
VERSION 5.7 ;
BUSBITCHARS "[]" ;
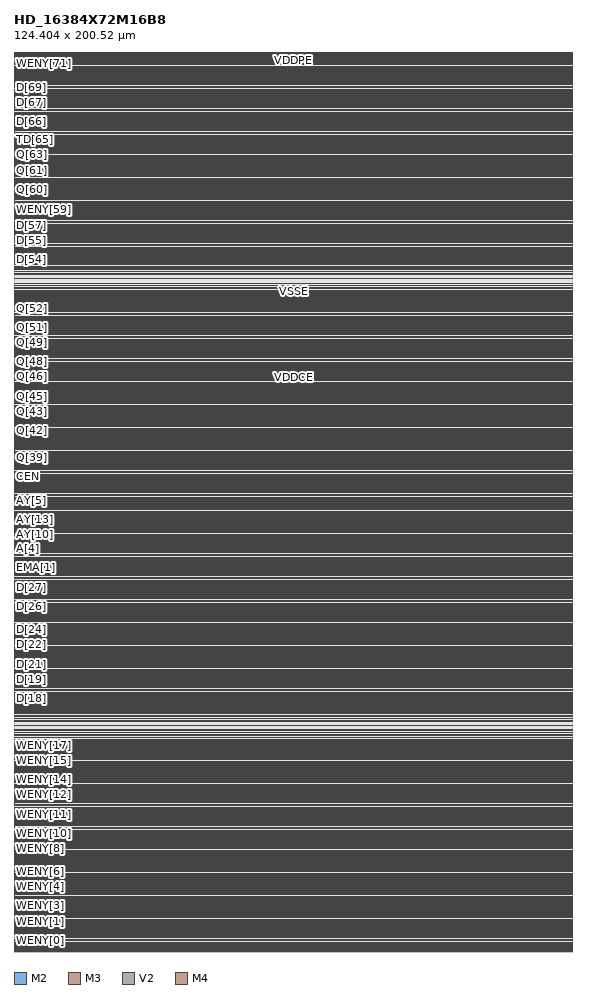
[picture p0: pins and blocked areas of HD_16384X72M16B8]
MACRO HD_16384X72M16B8
	FOREIGN HD_16384X72M16B8 0 0 ;
	SYMMETRY X Y ;
	SIZE 124.404 BY 200.52 ;
	CLASS BLOCK ;
	PIN AY[0]
		USE SIGNAL ;
		DIRECTION OUTPUT ;
		SHAPE ABUTMENT ;
		PORT
			 LAYER M2 ;
			RECT 0.0714 105.3427 0.1097 105.3804 ;
			 LAYER M3 ;
			RECT 0.0714 105.28 0.1097 105.3804 ;
			 LAYER V2 ;
			RECT 0.0831 105.3557 0.098 105.3682 ;
		END

		ANTENNADIFFAREA 0.00194719 ;
		ANTENNAPARTIALMETALAREA 0.00195671 ;
	END AY[0]

	PIN AY[10]
		USE SIGNAL ;
		DIRECTION OUTPUT ;
		SHAPE ABUTMENT ;
		PORT
			 LAYER M2 ;
			RECT 0.0098 91.2878 0.0481 91.3882 ;
			 LAYER M3 ;
			RECT 0.0098 91.2878 0.0481 91.3882 ;
			 LAYER V2 ;
			RECT 0.021 91.3008 0.0359 91.3133 ;
		END

		ANTENNADIFFAREA 0.00194719 ;
		ANTENNAPARTIALMETALAREA 0.00195671 ;
	END AY[10]

	PIN AY[11]
		USE SIGNAL ;
		DIRECTION OUTPUT ;
		SHAPE ABUTMENT ;
		PORT
			 LAYER M2 ;
			RECT 0.0098 93.8478 0.0481 93.9482 ;
			 LAYER M3 ;
			RECT 0.0098 93.8478 0.0481 93.9482 ;
			 LAYER V2 ;
			RECT 0.021 93.8608 0.0359 93.8733 ;
		END

		ANTENNADIFFAREA 0.00194719 ;
		ANTENNAPARTIALMETALAREA 0.00195671 ;
	END AY[11]

	PIN AY[12]
		USE SIGNAL ;
		DIRECTION OUTPUT ;
		SHAPE ABUTMENT ;
		PORT
			 LAYER M2 ;
			RECT 0.0098 95.1153 0.0481 95.1529 ;
			 LAYER M3 ;
			RECT 0.0098 95.0525 0.0481 95.1529 ;
			 LAYER V2 ;
			RECT 0.0215 95.1275 0.0364 95.14 ;
		END

		ANTENNADIFFAREA 0.00194719 ;
		ANTENNAPARTIALMETALAREA 0.00195671 ;
	END AY[12]

	PIN AY[13]
		USE SIGNAL ;
		DIRECTION OUTPUT ;
		SHAPE ABUTMENT ;
		PORT
			 LAYER M2 ;
			RECT 0.0098 96.3702 0.0481 96.4078 ;
			 LAYER M3 ;
			RECT 0.0098 96.3075 0.0481 96.4078 ;
			 LAYER V2 ;
			RECT 0.0215 96.3824 0.0364 96.3949 ;
		END

		ANTENNADIFFAREA 0.00194719 ;
		ANTENNAPARTIALMETALAREA 0.00195671 ;
	END AY[13]

	PIN AY[1]
		USE SIGNAL ;
		DIRECTION OUTPUT ;
		SHAPE ABUTMENT ;
		PORT
			 LAYER M2 ;
			RECT 0.0098 104.0753 0.0481 104.1129 ;
			 LAYER M3 ;
			RECT 0.0098 104.0753 0.0481 104.1757 ;
			 LAYER V2 ;
			RECT 0.0215 104.0882 0.0364 104.1008 ;
		END

		ANTENNADIFFAREA 0.00194719 ;
		ANTENNAPARTIALMETALAREA 0.00195671 ;
	END AY[1]

	PIN AY[2]
		USE SIGNAL ;
		DIRECTION OUTPUT ;
		SHAPE ABUTMENT ;
		PORT
			 LAYER M2 ;
			RECT 0.0098 103.0212 0.0481 103.0588 ;
			 LAYER M3 ;
			RECT 0.0098 103.0212 0.0481 103.1216 ;
			 LAYER V2 ;
			RECT 0.0215 103.0341 0.0364 103.0467 ;
		END

		ANTENNADIFFAREA 0.00194719 ;
		ANTENNAPARTIALMETALAREA 0.00195671 ;
	END AY[2]

	PIN AY[3]
		USE SIGNAL ;
		DIRECTION OUTPUT ;
		SHAPE ABUTMENT ;
		PORT
			 LAYER M2 ;
			RECT 0.0098 101.5153 0.0481 101.5529 ;
			 LAYER M3 ;
			RECT 0.0098 101.5153 0.0481 101.6157 ;
			 LAYER V2 ;
			RECT 0.0215 101.5282 0.0364 101.5408 ;
		END

		ANTENNADIFFAREA 0.00194719 ;
		ANTENNAPARTIALMETALAREA 0.00195671 ;
	END AY[3]

	PIN AY[4]
		USE SIGNAL ;
		DIRECTION OUTPUT ;
		SHAPE ABUTMENT ;
		PORT
			 LAYER M2 ;
			RECT 0.0098 89.5561 0.0481 89.6565 ;
			 LAYER M3 ;
			RECT 0.0098 89.5561 0.0481 89.6565 ;
			 LAYER V2 ;
			RECT 0.021 89.631 0.0359 89.6435 ;
		END

		ANTENNADIFFAREA 0.00194719 ;
		ANTENNAPARTIALMETALAREA 0.00195671 ;
	END AY[4]

	PIN AY[5]
		USE SIGNAL ;
		DIRECTION OUTPUT ;
		SHAPE ABUTMENT ;
		PORT
			 LAYER M2 ;
			RECT 0.0098 98.9302 0.0481 98.9678 ;
			 LAYER M3 ;
			RECT 0.0098 98.8675 0.0481 98.9678 ;
			 LAYER V2 ;
			RECT 0.0215 98.9424 0.0364 98.9549 ;
		END

		ANTENNADIFFAREA 0.00194719 ;
		ANTENNAPARTIALMETALAREA 0.00195671 ;
	END AY[5]

	PIN AY[6]
		USE SIGNAL ;
		DIRECTION OUTPUT ;
		SHAPE ABUTMENT ;
		PORT
			 LAYER M2 ;
			RECT 0.0714 94.7263 0.1097 94.7639 ;
			 LAYER M3 ;
			RECT 0.0714 94.7263 0.1097 94.8267 ;
			 LAYER V2 ;
			RECT 0.0831 94.7384 0.098 94.751 ;
		END

		ANTENNADIFFAREA 0.00194719 ;
		ANTENNAPARTIALMETALAREA 0.00195671 ;
	END AY[6]

	PIN AY[7]
		USE SIGNAL ;
		DIRECTION OUTPUT ;
		SHAPE ABUTMENT ;
		PORT
			 LAYER M2 ;
			RECT 0.0098 96.0816 0.0481 96.182 ;
			 LAYER M3 ;
			RECT 0.0098 96.0816 0.0481 96.182 ;
			 LAYER V2 ;
			RECT 0.021 96.1565 0.0359 96.169 ;
		END

		ANTENNADIFFAREA 0.00194719 ;
		ANTENNAPARTIALMETALAREA 0.00195671 ;
	END AY[7]

	PIN AY[8]
		USE SIGNAL ;
		DIRECTION OUTPUT ;
		SHAPE ABUTMENT ;
		PORT
			 LAYER M2 ;
			RECT 0.0098 92.5427 0.0481 92.6431 ;
			 LAYER M3 ;
			RECT 0.0098 92.5427 0.0481 92.6431 ;
			 LAYER V2 ;
			RECT 0.021 92.6176 0.0359 92.6302 ;
		END

		ANTENNADIFFAREA 0.00194719 ;
		ANTENNAPARTIALMETALAREA 0.00195671 ;
	END AY[8]

	PIN AY[9]
		USE SIGNAL ;
		DIRECTION OUTPUT ;
		SHAPE ABUTMENT ;
		PORT
			 LAYER M2 ;
			RECT 0.0098 90.0957 0.0481 90.1333 ;
			 LAYER M3 ;
			RECT 0.0098 90.0329 0.0481 90.1333 ;
			 LAYER V2 ;
			RECT 0.0215 90.1078 0.0364 90.1204 ;
		END

		ANTENNADIFFAREA 0.00194719 ;
		ANTENNAPARTIALMETALAREA 0.00195671 ;
	END AY[9]

	PIN A[0]
		USE SIGNAL ;
		DIRECTION INPUT ;
		SHAPE ABUTMENT ;
		PORT
			 LAYER M2 ;
			RECT 0.0098 105.4306 0.0481 105.4682 ;
			 LAYER M3 ;
			RECT 0.0098 105.4306 0.0481 105.531 ;
			 LAYER V2 ;
			RECT 0.0215 105.4435 0.0364 105.4561 ;
		END

		ANTENNAGATEAREA 0.00027817 ;
		ANTENNADIFFAREA 0.00194719 ;
		ANTENNAPARTIALMETALAREA 0.00195671 ;
	END A[0]

	PIN A[10]
		USE SIGNAL ;
		DIRECTION INPUT ;
		SHAPE ABUTMENT ;
		PORT
			 LAYER M2 ;
			RECT 0.0098 91.1373 0.0481 91.2376 ;
			 LAYER M3 ;
			RECT 0.0098 91.1373 0.0481 91.2376 ;
			 LAYER V2 ;
			RECT 0.021 91.2122 0.0359 91.2247 ;
		END

		ANTENNAGATEAREA 0.00027817 ;
		ANTENNADIFFAREA 0.00194719 ;
		ANTENNAPARTIALMETALAREA 0.00195671 ;
	END A[10]

	PIN A[11]
		USE SIGNAL ;
		DIRECTION INPUT ;
		SHAPE ABUTMENT ;
		PORT
			 LAYER M2 ;
			RECT 0.0098 93.4463 0.0481 93.5467 ;
			 LAYER M3 ;
			RECT 0.0098 93.4463 0.0481 93.5467 ;
			 LAYER V2 ;
			RECT 0.021 93.5212 0.0359 93.5337 ;
		END

		ANTENNAGATEAREA 0.00027817 ;
		ANTENNADIFFAREA 0.00194719 ;
		ANTENNAPARTIALMETALAREA 0.00195671 ;
	END A[11]

	PIN A[12]
		USE SIGNAL ;
		DIRECTION INPUT ;
		SHAPE ABUTMENT ;
		PORT
			 LAYER M2 ;
			RECT 0.0714 95.0525 0.1097 95.0902 ;
			 LAYER M3 ;
			RECT 0.0714 95.0525 0.1097 95.1529 ;
			 LAYER V2 ;
			RECT 0.0831 95.0647 0.098 95.0773 ;
		END

		ANTENNAGATEAREA 0.00027817 ;
		ANTENNADIFFAREA 0.00194719 ;
		ANTENNAPARTIALMETALAREA 0.00195671 ;
	END A[12]

	PIN A[13]
		USE SIGNAL ;
		DIRECTION INPUT ;
		SHAPE ABUTMENT ;
		PORT
			 LAYER M2 ;
			RECT 0.0714 96.3075 0.1097 96.3451 ;
			 LAYER M3 ;
			RECT 0.0714 96.3075 0.1097 96.4078 ;
			 LAYER V2 ;
			RECT 0.0831 96.3196 0.098 96.3322 ;
		END

		ANTENNAGATEAREA 0.00027817 ;
		ANTENNADIFFAREA 0.00194719 ;
		ANTENNAPARTIALMETALAREA 0.00195671 ;
	END A[13]

	PIN A[1]
		USE SIGNAL ;
		DIRECTION INPUT ;
		SHAPE ABUTMENT ;
		PORT
			 LAYER M2 ;
			RECT 0.0714 104.138 0.1097 104.1757 ;
			 LAYER M3 ;
			RECT 0.0714 104.0753 0.1097 104.1757 ;
			 LAYER V2 ;
			RECT 0.0831 104.151 0.098 104.1635 ;
		END

		ANTENNAGATEAREA 0.00027817 ;
		ANTENNADIFFAREA 0.00194719 ;
		ANTENNAPARTIALMETALAREA 0.00195671 ;
	END A[1]

	PIN A[2]
		USE SIGNAL ;
		DIRECTION INPUT ;
		SHAPE ABUTMENT ;
		PORT
			 LAYER M2 ;
			RECT 0.0098 102.4941 0.0481 102.5945 ;
			 LAYER M3 ;
			RECT 0.0098 102.4941 0.0481 102.5945 ;
			 LAYER V2 ;
			RECT 0.021 102.569 0.0359 102.5816 ;
		END

		ANTENNAGATEAREA 0.00027817 ;
		ANTENNADIFFAREA 0.00194719 ;
		ANTENNAPARTIALMETALAREA 0.00195671 ;
	END A[2]

	PIN A[3]
		USE SIGNAL ;
		DIRECTION INPUT ;
		SHAPE ABUTMENT ;
		PORT
			 LAYER M2 ;
			RECT 0.0098 101.2894 0.0481 101.3271 ;
			 LAYER M3 ;
			RECT 0.0098 101.2894 0.0481 101.3898 ;
			 LAYER V2 ;
			RECT 0.0215 101.3024 0.0364 101.3149 ;
		END

		ANTENNAGATEAREA 0.00027817 ;
		ANTENNADIFFAREA 0.00194719 ;
		ANTENNAPARTIALMETALAREA 0.00195671 ;
	END A[3]

	PIN A[4]
		USE SIGNAL ;
		DIRECTION INPUT ;
		SHAPE ABUTMENT ;
		PORT
			 LAYER M2 ;
			RECT 0.0714 89.8824 0.1097 89.92 ;
			 LAYER M3 ;
			RECT 0.0714 89.8824 0.1097 89.9827 ;
			 LAYER V2 ;
			RECT 0.0831 89.8945 0.098 89.9071 ;
		END

		ANTENNAGATEAREA 0.00027817 ;
		ANTENNADIFFAREA 0.00194719 ;
		ANTENNAPARTIALMETALAREA 0.00195671 ;
	END A[4]

	PIN A[5]
		USE SIGNAL ;
		DIRECTION INPUT ;
		SHAPE ABUTMENT ;
		PORT
			 LAYER M2 ;
			RECT 0.0098 99.1686 0.0481 99.269 ;
			 LAYER M3 ;
			RECT 0.0098 99.1686 0.0481 99.269 ;
			 LAYER V2 ;
			RECT 0.021 99.2435 0.0359 99.2561 ;
		END

		ANTENNAGATEAREA 0.00027817 ;
		ANTENNADIFFAREA 0.00194719 ;
		ANTENNAPARTIALMETALAREA 0.00195671 ;
	END A[5]

	PIN A[6]
		USE SIGNAL ;
		DIRECTION INPUT ;
		SHAPE ABUTMENT ;
		PORT
			 LAYER M2 ;
			RECT 0.0714 94.5757 0.1097 94.6133 ;
			 LAYER M3 ;
			RECT 0.0714 94.5757 0.1097 94.6761 ;
			 LAYER V2 ;
			RECT 0.0831 94.5878 0.098 94.6004 ;
		END

		ANTENNAGATEAREA 0.00027817 ;
		ANTENNADIFFAREA 0.00194719 ;
		ANTENNAPARTIALMETALAREA 0.00195671 ;
	END A[6]

	PIN A[7]
		USE SIGNAL ;
		DIRECTION INPUT ;
		SHAPE ABUTMENT ;
		PORT
			 LAYER M2 ;
			RECT 0.0098 95.9561 0.0481 96.0565 ;
			 LAYER M3 ;
			RECT 0.0098 95.9561 0.0481 96.0565 ;
			 LAYER V2 ;
			RECT 0.021 95.969 0.0359 95.9816 ;
		END

		ANTENNAGATEAREA 0.00027817 ;
		ANTENNADIFFAREA 0.00194719 ;
		ANTENNAPARTIALMETALAREA 0.00195671 ;
	END A[7]

	PIN A[8]
		USE SIGNAL ;
		DIRECTION INPUT ;
		SHAPE ABUTMENT ;
		PORT
			 LAYER M2 ;
			RECT 0.0098 90.811 0.0481 90.9114 ;
			 LAYER M3 ;
			RECT 0.0098 90.811 0.0481 90.9114 ;
			 LAYER V2 ;
			RECT 0.021 90.8859 0.0359 90.8984 ;
		END

		ANTENNAGATEAREA 0.00027817 ;
		ANTENNADIFFAREA 0.00194719 ;
		ANTENNAPARTIALMETALAREA 0.00195671 ;
	END A[8]

	PIN A[9]
		USE SIGNAL ;
		DIRECTION INPUT ;
		SHAPE ABUTMENT ;
		PORT
			 LAYER M2 ;
			RECT 0.0098 90.1835 0.0481 90.2839 ;
			 LAYER M3 ;
			RECT 0.0098 90.1835 0.0481 90.2839 ;
			 LAYER V2 ;
			RECT 0.021 90.2584 0.0359 90.271 ;
		END

		ANTENNAGATEAREA 0.00027817 ;
		ANTENNADIFFAREA 0.00194719 ;
		ANTENNAPARTIALMETALAREA 0.00195671 ;
	END A[9]

	PIN CEN
		USE SIGNAL ;
		DIRECTION INPUT ;
		SHAPE ABUTMENT ;
		PORT
			 LAYER M2 ;
			RECT 0.0098 105.8824 0.0481 105.92 ;
			 LAYER M3 ;
			RECT 0.0098 105.8824 0.0481 105.9827 ;
			 LAYER V2 ;
			RECT 0.0215 105.8953 0.0364 105.9078 ;
		END

		ANTENNAGATEAREA 0.00027817 ;
		ANTENNADIFFAREA 0.00194719 ;
		ANTENNAPARTIALMETALAREA 0.00195671 ;
	END CEN

	PIN CENY
		USE SIGNAL ;
		DIRECTION OUTPUT ;
		SHAPE ABUTMENT ;
		PORT
			 LAYER M2 ;
			RECT 0.0098 105.7318 0.0481 105.7694 ;
			 LAYER M3 ;
			RECT 0.0098 105.7318 0.0481 105.8322 ;
			 LAYER V2 ;
			RECT 0.0215 105.7447 0.0364 105.7573 ;
		END

		ANTENNADIFFAREA 0.00194719 ;
		ANTENNAPARTIALMETALAREA 0.00195671 ;
	END CENY

	PIN CLK
		USE SIGNAL ;
		DIRECTION INPUT ;
		SHAPE ABUTMENT ;
		PORT
			 LAYER M2 ;
			RECT 0.0098 107.9906 0.0481 108.091 ;
			 LAYER M3 ;
			RECT 0.0098 107.9906 0.0481 108.091 ;
			 LAYER V2 ;
			RECT 0.021 108.0655 0.0359 108.078 ;
		END

		ANTENNAGATEAREA 0.00027817 ;
		ANTENNADIFFAREA 0.00194719 ;
		ANTENNAPARTIALMETALAREA 0.00195671 ;
	END CLK

	PIN DFTRAMBYP
		USE SIGNAL ;
		DIRECTION INPUT ;
		SHAPE ABUTMENT ;
		PORT
			 LAYER M2 ;
			RECT 0.0098 113.0353 0.0481 113.0729 ;
			 LAYER M3 ;
			RECT 0.0098 113.0353 0.0481 113.1357 ;
			 LAYER V2 ;
			RECT 0.0215 113.0482 0.0364 113.0608 ;
		END

		ANTENNAGATEAREA 0.00027817 ;
		ANTENNADIFFAREA 0.00194719 ;
		ANTENNAPARTIALMETALAREA 0.00195671 ;
	END DFTRAMBYP

	PIN D[0]
		USE SIGNAL ;
		DIRECTION INPUT ;
		SHAPE ABUTMENT ;
		PORT
			 LAYER M2 ;
			RECT 0.0098 2.6478 0.0481 2.6855 ;
			 LAYER M3 ;
			RECT 0.0098 2.6478 0.0481 2.7482 ;
			 LAYER V2 ;
			RECT 0.0215 2.6608 0.0364 2.6733 ;
		END

		ANTENNAGATEAREA 0.00027817 ;
		ANTENNADIFFAREA 0.00194719 ;
		ANTENNAPARTIALMETALAREA 0.00195671 ;
	END D[0]

	PIN D[10]
		USE SIGNAL ;
		DIRECTION INPUT ;
		SHAPE ABUTMENT ;
		PORT
			 LAYER M2 ;
			RECT 0.0098 28.2478 0.0481 28.2855 ;
			 LAYER M3 ;
			RECT 0.0098 28.2478 0.0481 28.3482 ;
			 LAYER V2 ;
			RECT 0.0215 28.2608 0.0364 28.2733 ;
		END

		ANTENNAGATEAREA 0.00027817 ;
		ANTENNADIFFAREA 0.00194719 ;
		ANTENNAPARTIALMETALAREA 0.00195671 ;
	END D[10]

	PIN D[11]
		USE SIGNAL ;
		DIRECTION INPUT ;
		SHAPE ABUTMENT ;
		PORT
			 LAYER M2 ;
			RECT 0.0098 30.8078 0.0481 30.8455 ;
			 LAYER M3 ;
			RECT 0.0098 30.8078 0.0481 30.9082 ;
			 LAYER V2 ;
			RECT 0.0215 30.8208 0.0364 30.8333 ;
		END

		ANTENNAGATEAREA 0.00027817 ;
		ANTENNADIFFAREA 0.00194719 ;
		ANTENNAPARTIALMETALAREA 0.00195671 ;
	END D[11]

	PIN D[12]
		USE SIGNAL ;
		DIRECTION INPUT ;
		SHAPE ABUTMENT ;
		PORT
			 LAYER M2 ;
			RECT 0.0098 33.3678 0.0481 33.4055 ;
			 LAYER M3 ;
			RECT 0.0098 33.3678 0.0481 33.4682 ;
			 LAYER V2 ;
			RECT 0.0215 33.3808 0.0364 33.3933 ;
		END

		ANTENNAGATEAREA 0.00027817 ;
		ANTENNADIFFAREA 0.00194719 ;
		ANTENNAPARTIALMETALAREA 0.00195671 ;
	END D[12]

	PIN D[13]
		USE SIGNAL ;
		DIRECTION INPUT ;
		SHAPE ABUTMENT ;
		PORT
			 LAYER M2 ;
			RECT 0.0098 35.9278 0.0481 35.9655 ;
			 LAYER M3 ;
			RECT 0.0098 35.9278 0.0481 36.0282 ;
			 LAYER V2 ;
			RECT 0.0215 35.9408 0.0364 35.9533 ;
		END

		ANTENNAGATEAREA 0.00027817 ;
		ANTENNADIFFAREA 0.00194719 ;
		ANTENNAPARTIALMETALAREA 0.00195671 ;
	END D[13]

	PIN D[14]
		USE SIGNAL ;
		DIRECTION INPUT ;
		SHAPE ABUTMENT ;
		PORT
			 LAYER M2 ;
			RECT 0.0098 38.4878 0.0481 38.5255 ;
			 LAYER M3 ;
			RECT 0.0098 38.4878 0.0481 38.5882 ;
			 LAYER V2 ;
			RECT 0.0215 38.5008 0.0364 38.5133 ;
		END

		ANTENNAGATEAREA 0.00027817 ;
		ANTENNADIFFAREA 0.00194719 ;
		ANTENNAPARTIALMETALAREA 0.00195671 ;
	END D[14]

	PIN D[15]
		USE SIGNAL ;
		DIRECTION INPUT ;
		SHAPE ABUTMENT ;
		PORT
			 LAYER M2 ;
			RECT 0.0098 41.0478 0.0481 41.0855 ;
			 LAYER M3 ;
			RECT 0.0098 41.0478 0.0481 41.1482 ;
			 LAYER V2 ;
			RECT 0.0215 41.0608 0.0364 41.0733 ;
		END

		ANTENNAGATEAREA 0.00027817 ;
		ANTENNADIFFAREA 0.00194719 ;
		ANTENNAPARTIALMETALAREA 0.00195671 ;
	END D[15]

	PIN D[16]
		USE SIGNAL ;
		DIRECTION INPUT ;
		SHAPE ABUTMENT ;
		PORT
			 LAYER M2 ;
			RECT 0.0098 43.6078 0.0481 43.6455 ;
			 LAYER M3 ;
			RECT 0.0098 43.6078 0.0481 43.7082 ;
			 LAYER V2 ;
			RECT 0.0215 43.6208 0.0364 43.6333 ;
		END

		ANTENNAGATEAREA 0.00027817 ;
		ANTENNADIFFAREA 0.00194719 ;
		ANTENNAPARTIALMETALAREA 0.00195671 ;
	END D[16]

	PIN D[17]
		USE SIGNAL ;
		DIRECTION INPUT ;
		SHAPE ABUTMENT ;
		PORT
			 LAYER M2 ;
			RECT 0.0098 46.1678 0.0481 46.2055 ;
			 LAYER M3 ;
			RECT 0.0098 46.1678 0.0481 46.2682 ;
			 LAYER V2 ;
			RECT 0.0215 46.1808 0.0364 46.1933 ;
		END

		ANTENNAGATEAREA 0.00027817 ;
		ANTENNADIFFAREA 0.00194719 ;
		ANTENNAPARTIALMETALAREA 0.00195671 ;
	END D[17]

	PIN D[18]
		USE SIGNAL ;
		DIRECTION INPUT ;
		SHAPE ABUTMENT ;
		PORT
			 LAYER M2 ;
			RECT 0.0098 56.4267 0.0481 56.4643 ;
			 LAYER M3 ;
			RECT 0.0098 56.4267 0.0481 56.5271 ;
			 LAYER V2 ;
			RECT 0.0215 56.4396 0.0364 56.4522 ;
		END

		ANTENNAGATEAREA 0.00027817 ;
		ANTENNADIFFAREA 0.00194719 ;
		ANTENNAPARTIALMETALAREA 0.00195671 ;
	END D[18]

	PIN D[19]
		USE SIGNAL ;
		DIRECTION INPUT ;
		SHAPE ABUTMENT ;
		PORT
			 LAYER M2 ;
			RECT 0.0098 58.9867 0.0481 59.0243 ;
			 LAYER M3 ;
			RECT 0.0098 58.9867 0.0481 59.0871 ;
			 LAYER V2 ;
			RECT 0.0215 58.9996 0.0364 59.0122 ;
		END

		ANTENNAGATEAREA 0.00027817 ;
		ANTENNADIFFAREA 0.00194719 ;
		ANTENNAPARTIALMETALAREA 0.00195671 ;
	END D[19]

	PIN D[1]
		USE SIGNAL ;
		DIRECTION INPUT ;
		SHAPE ABUTMENT ;
		PORT
			 LAYER M2 ;
			RECT 0.0098 5.2078 0.0481 5.2455 ;
			 LAYER M3 ;
			RECT 0.0098 5.2078 0.0481 5.3082 ;
			 LAYER V2 ;
			RECT 0.0215 5.2208 0.0364 5.2333 ;
		END

		ANTENNAGATEAREA 0.00027817 ;
		ANTENNADIFFAREA 0.00194719 ;
		ANTENNAPARTIALMETALAREA 0.00195671 ;
	END D[1]

	PIN D[20]
		USE SIGNAL ;
		DIRECTION INPUT ;
		SHAPE ABUTMENT ;
		PORT
			 LAYER M2 ;
			RECT 0.0098 61.5467 0.0481 61.5843 ;
			 LAYER M3 ;
			RECT 0.0098 61.5467 0.0481 61.6471 ;
			 LAYER V2 ;
			RECT 0.0215 61.5596 0.0364 61.5722 ;
		END

		ANTENNAGATEAREA 0.00027817 ;
		ANTENNADIFFAREA 0.00194719 ;
		ANTENNAPARTIALMETALAREA 0.00195671 ;
	END D[20]

	PIN D[21]
		USE SIGNAL ;
		DIRECTION INPUT ;
		SHAPE ABUTMENT ;
		PORT
			 LAYER M2 ;
			RECT 0.0098 64.1067 0.0481 64.1443 ;
			 LAYER M3 ;
			RECT 0.0098 64.1067 0.0481 64.2071 ;
			 LAYER V2 ;
			RECT 0.0215 64.1196 0.0364 64.1322 ;
		END

		ANTENNAGATEAREA 0.00027817 ;
		ANTENNADIFFAREA 0.00194719 ;
		ANTENNAPARTIALMETALAREA 0.00195671 ;
	END D[21]

	PIN D[22]
		USE SIGNAL ;
		DIRECTION INPUT ;
		SHAPE ABUTMENT ;
		PORT
			 LAYER M2 ;
			RECT 0.0098 66.6667 0.0481 66.7043 ;
			 LAYER M3 ;
			RECT 0.0098 66.6667 0.0481 66.7671 ;
			 LAYER V2 ;
			RECT 0.0215 66.6796 0.0364 66.6922 ;
		END

		ANTENNAGATEAREA 0.00027817 ;
		ANTENNADIFFAREA 0.00194719 ;
		ANTENNAPARTIALMETALAREA 0.00195671 ;
	END D[22]

	PIN D[23]
		USE SIGNAL ;
		DIRECTION INPUT ;
		SHAPE ABUTMENT ;
		PORT
			 LAYER M2 ;
			RECT 0.0098 69.2267 0.0481 69.2643 ;
			 LAYER M3 ;
			RECT 0.0098 69.2267 0.0481 69.3271 ;
			 LAYER V2 ;
			RECT 0.0215 69.2396 0.0364 69.2522 ;
		END

		ANTENNAGATEAREA 0.00027817 ;
		ANTENNADIFFAREA 0.00194719 ;
		ANTENNAPARTIALMETALAREA 0.00195671 ;
	END D[23]

	PIN D[24]
		USE SIGNAL ;
		DIRECTION INPUT ;
		SHAPE ABUTMENT ;
		PORT
			 LAYER M2 ;
			RECT 0.0098 71.7867 0.0481 71.8243 ;
			 LAYER M3 ;
			RECT 0.0098 71.7867 0.0481 71.8871 ;
			 LAYER V2 ;
			RECT 0.0215 71.7996 0.0364 71.8122 ;
		END

		ANTENNAGATEAREA 0.00027817 ;
		ANTENNADIFFAREA 0.00194719 ;
		ANTENNAPARTIALMETALAREA 0.00195671 ;
	END D[24]

	PIN D[25]
		USE SIGNAL ;
		DIRECTION INPUT ;
		SHAPE ABUTMENT ;
		PORT
			 LAYER M2 ;
			RECT 0.0098 74.3467 0.0481 74.3843 ;
			 LAYER M3 ;
			RECT 0.0098 74.3467 0.0481 74.4471 ;
			 LAYER V2 ;
			RECT 0.0215 74.3596 0.0364 74.3722 ;
		END

		ANTENNAGATEAREA 0.00027817 ;
		ANTENNADIFFAREA 0.00194719 ;
		ANTENNAPARTIALMETALAREA 0.00195671 ;
	END D[25]

	PIN D[26]
		USE SIGNAL ;
		DIRECTION INPUT ;
		SHAPE ABUTMENT ;
		PORT
			 LAYER M2 ;
			RECT 0.0098 76.9067 0.0481 76.9443 ;
			 LAYER M3 ;
			RECT 0.0098 76.9067 0.0481 77.0071 ;
			 LAYER V2 ;
			RECT 0.0215 76.9196 0.0364 76.9322 ;
		END

		ANTENNAGATEAREA 0.00027817 ;
		ANTENNADIFFAREA 0.00194719 ;
		ANTENNAPARTIALMETALAREA 0.00195671 ;
	END D[26]

	PIN D[27]
		USE SIGNAL ;
		DIRECTION INPUT ;
		SHAPE ABUTMENT ;
		PORT
			 LAYER M2 ;
			RECT 0.0098 79.4667 0.0481 79.5043 ;
			 LAYER M3 ;
			RECT 0.0098 79.4667 0.0481 79.5671 ;
			 LAYER V2 ;
			RECT 0.0215 79.4796 0.0364 79.4922 ;
		END

		ANTENNAGATEAREA 0.00027817 ;
		ANTENNADIFFAREA 0.00194719 ;
		ANTENNAPARTIALMETALAREA 0.00195671 ;
	END D[27]

	PIN D[28]
		USE SIGNAL ;
		DIRECTION INPUT ;
		SHAPE ABUTMENT ;
		PORT
			 LAYER M2 ;
			RECT 0.0098 82.0267 0.0481 82.0643 ;
			 LAYER M3 ;
			RECT 0.0098 82.0267 0.0481 82.1271 ;
			 LAYER V2 ;
			RECT 0.0215 82.0396 0.0364 82.0522 ;
		END

		ANTENNAGATEAREA 0.00027817 ;
		ANTENNADIFFAREA 0.00194719 ;
		ANTENNAPARTIALMETALAREA 0.00195671 ;
	END D[28]

	PIN D[29]
		USE SIGNAL ;
		DIRECTION INPUT ;
		SHAPE ABUTMENT ;
		PORT
			 LAYER M2 ;
			RECT 0.0098 84.5867 0.0481 84.6243 ;
			 LAYER M3 ;
			RECT 0.0098 84.5867 0.0481 84.6871 ;
			 LAYER V2 ;
			RECT 0.0215 84.5996 0.0364 84.6122 ;
		END

		ANTENNAGATEAREA 0.00027817 ;
		ANTENNADIFFAREA 0.00194719 ;
		ANTENNAPARTIALMETALAREA 0.00195671 ;
	END D[29]

	PIN D[2]
		USE SIGNAL ;
		DIRECTION INPUT ;
		SHAPE ABUTMENT ;
		PORT
			 LAYER M2 ;
			RECT 0.0098 7.7678 0.0481 7.8055 ;
			 LAYER M3 ;
			RECT 0.0098 7.7678 0.0481 7.8682 ;
			 LAYER V2 ;
			RECT 0.0215 7.7808 0.0364 7.7933 ;
		END

		ANTENNAGATEAREA 0.00027817 ;
		ANTENNADIFFAREA 0.00194719 ;
		ANTENNAPARTIALMETALAREA 0.00195671 ;
	END D[2]

	PIN D[30]
		USE SIGNAL ;
		DIRECTION INPUT ;
		SHAPE ABUTMENT ;
		PORT
			 LAYER M2 ;
			RECT 0.0098 87.1467 0.0481 87.1843 ;
			 LAYER M3 ;
			RECT 0.0098 87.1467 0.0481 87.2471 ;
			 LAYER V2 ;
			RECT 0.0215 87.1596 0.0364 87.1722 ;
		END

		ANTENNAGATEAREA 0.00027817 ;
		ANTENNADIFFAREA 0.00194719 ;
		ANTENNAPARTIALMETALAREA 0.00195671 ;
	END D[30]

	PIN D[31]
		USE SIGNAL ;
		DIRECTION INPUT ;
		SHAPE ABUTMENT ;
		PORT
			 LAYER M2 ;
			RECT 0.0098 89.3176 0.0481 89.3553 ;
			 LAYER M3 ;
			RECT 0.0098 89.2549 0.0481 89.3553 ;
			 LAYER V2 ;
			RECT 0.0215 89.3298 0.0364 89.3424 ;
		END

		ANTENNAGATEAREA 0.00027817 ;
		ANTENNADIFFAREA 0.00194719 ;
		ANTENNAPARTIALMETALAREA 0.00195671 ;
	END D[31]

	PIN D[32]
		USE SIGNAL ;
		DIRECTION INPUT ;
		SHAPE ABUTMENT ;
		PORT
			 LAYER M2 ;
			RECT 0.0714 91.8902 0.1097 91.9278 ;
			 LAYER M3 ;
			RECT 0.0714 91.8902 0.1097 91.9906 ;
			 LAYER V2 ;
			RECT 0.0831 91.9024 0.098 91.9149 ;
		END

		ANTENNAGATEAREA 0.00027817 ;
		ANTENNADIFFAREA 0.00194719 ;
		ANTENNAPARTIALMETALAREA 0.00195671 ;
	END D[32]

	PIN D[33]
		USE SIGNAL ;
		DIRECTION INPUT ;
		SHAPE ABUTMENT ;
		PORT
			 LAYER M2 ;
			RECT 0.0714 94.4251 0.1097 94.4627 ;
			 LAYER M3 ;
			RECT 0.0714 94.4251 0.1097 94.5255 ;
			 LAYER V2 ;
			RECT 0.0831 94.4373 0.098 94.4498 ;
		END

		ANTENNAGATEAREA 0.00027817 ;
		ANTENNADIFFAREA 0.00194719 ;
		ANTENNAPARTIALMETALAREA 0.00195671 ;
	END D[33]

	PIN D[34]
		USE SIGNAL ;
		DIRECTION INPUT ;
		SHAPE ABUTMENT ;
		PORT
			 LAYER M2 ;
			RECT 0.0098 96.9725 0.0481 97.0102 ;
			 LAYER M3 ;
			RECT 0.0098 96.9098 0.0481 97.0102 ;
			 LAYER V2 ;
			RECT 0.0215 96.9847 0.0364 96.9973 ;
		END

		ANTENNAGATEAREA 0.00027817 ;
		ANTENNADIFFAREA 0.00194719 ;
		ANTENNAPARTIALMETALAREA 0.00195671 ;
	END D[34]

	PIN D[35]
		USE SIGNAL ;
		DIRECTION INPUT ;
		SHAPE ABUTMENT ;
		PORT
			 LAYER M2 ;
			RECT 0.0098 99.5325 0.0481 99.5702 ;
			 LAYER M3 ;
			RECT 0.0098 99.4698 0.0481 99.5702 ;
			 LAYER V2 ;
			RECT 0.0215 99.5447 0.0364 99.5573 ;
		END

		ANTENNAGATEAREA 0.00027817 ;
		ANTENNADIFFAREA 0.00194719 ;
		ANTENNAPARTIALMETALAREA 0.00195671 ;
	END D[35]

	PIN D[36]
		USE SIGNAL ;
		DIRECTION INPUT ;
		SHAPE ABUTMENT ;
		PORT
			 LAYER M2 ;
			RECT 0.0098 100.9129 0.0481 100.9506 ;
			 LAYER M3 ;
			RECT 0.0098 100.9129 0.0481 101.0133 ;
			 LAYER V2 ;
			RECT 0.0215 100.9259 0.0364 100.9384 ;
		END

		ANTENNAGATEAREA 0.00027817 ;
		ANTENNADIFFAREA 0.00194719 ;
		ANTENNAPARTIALMETALAREA 0.00195671 ;
	END D[36]

	PIN D[37]
		USE SIGNAL ;
		DIRECTION INPUT ;
		SHAPE ABUTMENT ;
		PORT
			 LAYER M2 ;
			RECT 0.0098 103.4729 0.0481 103.5106 ;
			 LAYER M3 ;
			RECT 0.0098 103.4729 0.0481 103.5733 ;
			 LAYER V2 ;
			RECT 0.0215 103.4859 0.0364 103.4984 ;
		END

		ANTENNAGATEAREA 0.00027817 ;
		ANTENNADIFFAREA 0.00194719 ;
		ANTENNAPARTIALMETALAREA 0.00195671 ;
	END D[37]

	PIN D[38]
		USE SIGNAL ;
		DIRECTION INPUT ;
		SHAPE ABUTMENT ;
		PORT
			 LAYER M2 ;
			RECT 0.0098 106.0329 0.0481 106.0706 ;
			 LAYER M3 ;
			RECT 0.0098 106.0329 0.0481 106.1333 ;
			 LAYER V2 ;
			RECT 0.0215 106.0459 0.0364 106.0584 ;
		END

		ANTENNAGATEAREA 0.00027817 ;
		ANTENNADIFFAREA 0.00194719 ;
		ANTENNAPARTIALMETALAREA 0.00195671 ;
	END D[38]

	PIN D[39]
		USE SIGNAL ;
		DIRECTION INPUT ;
		SHAPE ABUTMENT ;
		PORT
			 LAYER M2 ;
			RECT 0.0098 108.5929 0.0481 108.6306 ;
			 LAYER M3 ;
			RECT 0.0098 108.5929 0.0481 108.6933 ;
			 LAYER V2 ;
			RECT 0.0215 108.6059 0.0364 108.6184 ;
		END

		ANTENNAGATEAREA 0.00027817 ;
		ANTENNADIFFAREA 0.00194719 ;
		ANTENNAPARTIALMETALAREA 0.00195671 ;
	END D[39]

	PIN D[3]
		USE SIGNAL ;
		DIRECTION INPUT ;
		SHAPE ABUTMENT ;
		PORT
			 LAYER M2 ;
			RECT 0.0098 10.3278 0.0481 10.3655 ;
			 LAYER M3 ;
			RECT 0.0098 10.3278 0.0481 10.4282 ;
			 LAYER V2 ;
			RECT 0.0215 10.3408 0.0364 10.3533 ;
		END

		ANTENNAGATEAREA 0.00027817 ;
		ANTENNADIFFAREA 0.00194719 ;
		ANTENNAPARTIALMETALAREA 0.00195671 ;
	END D[3]

	PIN D[40]
		USE SIGNAL ;
		DIRECTION INPUT ;
		SHAPE ABUTMENT ;
		PORT
			 LAYER M2 ;
			RECT 0.0098 111.1529 0.0481 111.1906 ;
			 LAYER M3 ;
			RECT 0.0098 111.1529 0.0481 111.2533 ;
			 LAYER V2 ;
			RECT 0.0215 111.1659 0.0364 111.1784 ;
		END

		ANTENNAGATEAREA 0.00027817 ;
		ANTENNADIFFAREA 0.00194719 ;
		ANTENNAPARTIALMETALAREA 0.00195671 ;
	END D[40]

	PIN D[41]
		USE SIGNAL ;
		DIRECTION INPUT ;
		SHAPE ABUTMENT ;
		PORT
			 LAYER M2 ;
			RECT 0.0098 113.3239 0.0481 113.3616 ;
			 LAYER M3 ;
			RECT 0.0098 113.2612 0.0481 113.3616 ;
			 LAYER V2 ;
			RECT 0.0215 113.3361 0.0364 113.3486 ;
		END

		ANTENNAGATEAREA 0.00027817 ;
		ANTENNADIFFAREA 0.00194719 ;
		ANTENNAPARTIALMETALAREA 0.00195671 ;
	END D[41]

	PIN D[42]
		USE SIGNAL ;
		DIRECTION INPUT ;
		SHAPE ABUTMENT ;
		PORT
			 LAYER M2 ;
			RECT 0.0098 115.8839 0.0481 115.9216 ;
			 LAYER M3 ;
			RECT 0.0098 115.8212 0.0481 115.9216 ;
			 LAYER V2 ;
			RECT 0.0215 115.8961 0.0364 115.9086 ;
		END

		ANTENNAGATEAREA 0.00027817 ;
		ANTENNADIFFAREA 0.00194719 ;
		ANTENNAPARTIALMETALAREA 0.00195671 ;
	END D[42]

	PIN D[43]
		USE SIGNAL ;
		DIRECTION INPUT ;
		SHAPE ABUTMENT ;
		PORT
			 LAYER M2 ;
			RECT 0.0098 118.4439 0.0481 118.4816 ;
			 LAYER M3 ;
			RECT 0.0098 118.3812 0.0481 118.4816 ;
			 LAYER V2 ;
			RECT 0.0215 118.4561 0.0364 118.4686 ;
		END

		ANTENNAGATEAREA 0.00027817 ;
		ANTENNADIFFAREA 0.00194719 ;
		ANTENNAPARTIALMETALAREA 0.00195671 ;
	END D[43]

	PIN D[44]
		USE SIGNAL ;
		DIRECTION INPUT ;
		SHAPE ABUTMENT ;
		PORT
			 LAYER M2 ;
			RECT 0.0098 121.0039 0.0481 121.0416 ;
			 LAYER M3 ;
			RECT 0.0098 120.9412 0.0481 121.0416 ;
			 LAYER V2 ;
			RECT 0.0215 121.0161 0.0364 121.0286 ;
		END

		ANTENNAGATEAREA 0.00027817 ;
		ANTENNADIFFAREA 0.00194719 ;
		ANTENNAPARTIALMETALAREA 0.00195671 ;
	END D[44]

	PIN D[45]
		USE SIGNAL ;
		DIRECTION INPUT ;
		SHAPE ABUTMENT ;
		PORT
			 LAYER M2 ;
			RECT 0.0098 123.5639 0.0481 123.6016 ;
			 LAYER M3 ;
			RECT 0.0098 123.5012 0.0481 123.6016 ;
			 LAYER V2 ;
			RECT 0.0215 123.5761 0.0364 123.5886 ;
		END

		ANTENNAGATEAREA 0.00027817 ;
		ANTENNADIFFAREA 0.00194719 ;
		ANTENNAPARTIALMETALAREA 0.00195671 ;
	END D[45]

	PIN D[46]
		USE SIGNAL ;
		DIRECTION INPUT ;
		SHAPE ABUTMENT ;
		PORT
			 LAYER M2 ;
			RECT 0.0098 126.1239 0.0481 126.1616 ;
			 LAYER M3 ;
			RECT 0.0098 126.0612 0.0481 126.1616 ;
			 LAYER V2 ;
			RECT 0.0215 126.1361 0.0364 126.1486 ;
		END

		ANTENNAGATEAREA 0.00027817 ;
		ANTENNADIFFAREA 0.00194719 ;
		ANTENNAPARTIALMETALAREA 0.00195671 ;
	END D[46]

	PIN D[47]
		USE SIGNAL ;
		DIRECTION INPUT ;
		SHAPE ABUTMENT ;
		PORT
			 LAYER M2 ;
			RECT 0.0098 128.6839 0.0481 128.7216 ;
			 LAYER M3 ;
			RECT 0.0098 128.6212 0.0481 128.7216 ;
			 LAYER V2 ;
			RECT 0.0215 128.6961 0.0364 128.7086 ;
		END

		ANTENNAGATEAREA 0.00027817 ;
		ANTENNADIFFAREA 0.00194719 ;
		ANTENNAPARTIALMETALAREA 0.00195671 ;
	END D[47]

	PIN D[48]
		USE SIGNAL ;
		DIRECTION INPUT ;
		SHAPE ABUTMENT ;
		PORT
			 LAYER M2 ;
			RECT 0.0098 131.2439 0.0481 131.2816 ;
			 LAYER M3 ;
			RECT 0.0098 131.1812 0.0481 131.2816 ;
			 LAYER V2 ;
			RECT 0.0215 131.2561 0.0364 131.2686 ;
		END

		ANTENNAGATEAREA 0.00027817 ;
		ANTENNADIFFAREA 0.00194719 ;
		ANTENNAPARTIALMETALAREA 0.00195671 ;
	END D[48]

	PIN D[49]
		USE SIGNAL ;
		DIRECTION INPUT ;
		SHAPE ABUTMENT ;
		PORT
			 LAYER M2 ;
			RECT 0.0098 133.8039 0.0481 133.8416 ;
			 LAYER M3 ;
			RECT 0.0098 133.7412 0.0481 133.8416 ;
			 LAYER V2 ;
			RECT 0.0215 133.8161 0.0364 133.8286 ;
		END

		ANTENNAGATEAREA 0.00027817 ;
		ANTENNADIFFAREA 0.00194719 ;
		ANTENNAPARTIALMETALAREA 0.00195671 ;
	END D[49]

	PIN D[4]
		USE SIGNAL ;
		DIRECTION INPUT ;
		SHAPE ABUTMENT ;
		PORT
			 LAYER M2 ;
			RECT 0.0098 12.8878 0.0481 12.9255 ;
			 LAYER M3 ;
			RECT 0.0098 12.8878 0.0481 12.9882 ;
			 LAYER V2 ;
			RECT 0.0215 12.9008 0.0364 12.9133 ;
		END

		ANTENNAGATEAREA 0.00027817 ;
		ANTENNADIFFAREA 0.00194719 ;
		ANTENNAPARTIALMETALAREA 0.00195671 ;
	END D[4]

	PIN D[50]
		USE SIGNAL ;
		DIRECTION INPUT ;
		SHAPE ABUTMENT ;
		PORT
			 LAYER M2 ;
			RECT 0.0098 136.3639 0.0481 136.4016 ;
			 LAYER M3 ;
			RECT 0.0098 136.3012 0.0481 136.4016 ;
			 LAYER V2 ;
			RECT 0.0215 136.3761 0.0364 136.3886 ;
		END

		ANTENNAGATEAREA 0.00027817 ;
		ANTENNADIFFAREA 0.00194719 ;
		ANTENNAPARTIALMETALAREA 0.00195671 ;
	END D[50]

	PIN D[51]
		USE SIGNAL ;
		DIRECTION INPUT ;
		SHAPE ABUTMENT ;
		PORT
			 LAYER M2 ;
			RECT 0.0098 138.9239 0.0481 138.9616 ;
			 LAYER M3 ;
			RECT 0.0098 138.8612 0.0481 138.9616 ;
			 LAYER V2 ;
			RECT 0.0215 138.9361 0.0364 138.9486 ;
		END

		ANTENNAGATEAREA 0.00027817 ;
		ANTENNADIFFAREA 0.00194719 ;
		ANTENNAPARTIALMETALAREA 0.00195671 ;
	END D[51]

	PIN D[52]
		USE SIGNAL ;
		DIRECTION INPUT ;
		SHAPE ABUTMENT ;
		PORT
			 LAYER M2 ;
			RECT 0.0098 141.4839 0.0481 141.5216 ;
			 LAYER M3 ;
			RECT 0.0098 141.4212 0.0481 141.5216 ;
			 LAYER V2 ;
			RECT 0.0215 141.4961 0.0364 141.5086 ;
		END

		ANTENNAGATEAREA 0.00027817 ;
		ANTENNADIFFAREA 0.00194719 ;
		ANTENNAPARTIALMETALAREA 0.00195671 ;
	END D[52]

	PIN D[53]
		USE SIGNAL ;
		DIRECTION INPUT ;
		SHAPE ABUTMENT ;
		PORT
			 LAYER M2 ;
			RECT 0.0098 144.0439 0.0481 144.0816 ;
			 LAYER M3 ;
			RECT 0.0098 143.9812 0.0481 144.0816 ;
			 LAYER V2 ;
			RECT 0.0215 144.0561 0.0364 144.0686 ;
		END

		ANTENNAGATEAREA 0.00027817 ;
		ANTENNADIFFAREA 0.00194719 ;
		ANTENNAPARTIALMETALAREA 0.00195671 ;
	END D[53]

	PIN D[54]
		USE SIGNAL ;
		DIRECTION INPUT ;
		SHAPE ABUTMENT ;
		PORT
			 LAYER M2 ;
			RECT 0.0098 154.3027 0.0481 154.3404 ;
			 LAYER M3 ;
			RECT 0.0098 154.24 0.0481 154.3404 ;
			 LAYER V2 ;
			RECT 0.0215 154.3149 0.0364 154.3275 ;
		END

		ANTENNAGATEAREA 0.00027817 ;
		ANTENNADIFFAREA 0.00194719 ;
		ANTENNAPARTIALMETALAREA 0.00195671 ;
	END D[54]

	PIN D[55]
		USE SIGNAL ;
		DIRECTION INPUT ;
		SHAPE ABUTMENT ;
		PORT
			 LAYER M2 ;
			RECT 0.0098 156.8627 0.0481 156.9004 ;
			 LAYER M3 ;
			RECT 0.0098 156.8 0.0481 156.9004 ;
			 LAYER V2 ;
			RECT 0.0215 156.8749 0.0364 156.8875 ;
		END

		ANTENNAGATEAREA 0.00027817 ;
		ANTENNADIFFAREA 0.00194719 ;
		ANTENNAPARTIALMETALAREA 0.00195671 ;
	END D[55]

	PIN D[56]
		USE SIGNAL ;
		DIRECTION INPUT ;
		SHAPE ABUTMENT ;
		PORT
			 LAYER M2 ;
			RECT 0.0098 159.4227 0.0481 159.4604 ;
			 LAYER M3 ;
			RECT 0.0098 159.36 0.0481 159.4604 ;
			 LAYER V2 ;
			RECT 0.0215 159.4349 0.0364 159.4475 ;
		END

		ANTENNAGATEAREA 0.00027817 ;
		ANTENNADIFFAREA 0.00194719 ;
		ANTENNAPARTIALMETALAREA 0.00195671 ;
	END D[56]

	PIN D[57]
		USE SIGNAL ;
		DIRECTION INPUT ;
		SHAPE ABUTMENT ;
		PORT
			 LAYER M2 ;
			RECT 0.0098 161.9827 0.0481 162.0204 ;
			 LAYER M3 ;
			RECT 0.0098 161.92 0.0481 162.0204 ;
			 LAYER V2 ;
			RECT 0.0215 161.9949 0.0364 162.0075 ;
		END

		ANTENNAGATEAREA 0.00027817 ;
		ANTENNADIFFAREA 0.00194719 ;
		ANTENNAPARTIALMETALAREA 0.00195671 ;
	END D[57]

	PIN D[58]
		USE SIGNAL ;
		DIRECTION INPUT ;
		SHAPE ABUTMENT ;
		PORT
			 LAYER M2 ;
			RECT 0.0098 164.5427 0.0481 164.5804 ;
			 LAYER M3 ;
			RECT 0.0098 164.48 0.0481 164.5804 ;
			 LAYER V2 ;
			RECT 0.0215 164.5549 0.0364 164.5675 ;
		END

		ANTENNAGATEAREA 0.00027817 ;
		ANTENNADIFFAREA 0.00194719 ;
		ANTENNAPARTIALMETALAREA 0.00195671 ;
	END D[58]

	PIN D[59]
		USE SIGNAL ;
		DIRECTION INPUT ;
		SHAPE ABUTMENT ;
		PORT
			 LAYER M2 ;
			RECT 0.0098 167.1027 0.0481 167.1404 ;
			 LAYER M3 ;
			RECT 0.0098 167.04 0.0481 167.1404 ;
			 LAYER V2 ;
			RECT 0.0215 167.1149 0.0364 167.1275 ;
		END

		ANTENNAGATEAREA 0.00027817 ;
		ANTENNADIFFAREA 0.00194719 ;
		ANTENNAPARTIALMETALAREA 0.00195671 ;
	END D[59]

	PIN D[5]
		USE SIGNAL ;
		DIRECTION INPUT ;
		SHAPE ABUTMENT ;
		PORT
			 LAYER M2 ;
			RECT 0.0098 15.4478 0.0481 15.4855 ;
			 LAYER M3 ;
			RECT 0.0098 15.4478 0.0481 15.5482 ;
			 LAYER V2 ;
			RECT 0.0215 15.4608 0.0364 15.4733 ;
		END

		ANTENNAGATEAREA 0.00027817 ;
		ANTENNADIFFAREA 0.00194719 ;
		ANTENNAPARTIALMETALAREA 0.00195671 ;
	END D[5]

	PIN D[60]
		USE SIGNAL ;
		DIRECTION INPUT ;
		SHAPE ABUTMENT ;
		PORT
			 LAYER M2 ;
			RECT 0.0098 169.6627 0.0481 169.7004 ;
			 LAYER M3 ;
			RECT 0.0098 169.6 0.0481 169.7004 ;
			 LAYER V2 ;
			RECT 0.0215 169.6749 0.0364 169.6875 ;
		END

		ANTENNAGATEAREA 0.00027817 ;
		ANTENNADIFFAREA 0.00194719 ;
		ANTENNAPARTIALMETALAREA 0.00195671 ;
	END D[60]

	PIN D[61]
		USE SIGNAL ;
		DIRECTION INPUT ;
		SHAPE ABUTMENT ;
		PORT
			 LAYER M2 ;
			RECT 0.0098 172.2227 0.0481 172.2604 ;
			 LAYER M3 ;
			RECT 0.0098 172.16 0.0481 172.2604 ;
			 LAYER V2 ;
			RECT 0.0215 172.2349 0.0364 172.2475 ;
		END

		ANTENNAGATEAREA 0.00027817 ;
		ANTENNADIFFAREA 0.00194719 ;
		ANTENNAPARTIALMETALAREA 0.00195671 ;
	END D[61]

	PIN D[62]
		USE SIGNAL ;
		DIRECTION INPUT ;
		SHAPE ABUTMENT ;
		PORT
			 LAYER M2 ;
			RECT 0.0098 174.7827 0.0481 174.8204 ;
			 LAYER M3 ;
			RECT 0.0098 174.72 0.0481 174.8204 ;
			 LAYER V2 ;
			RECT 0.0215 174.7949 0.0364 174.8075 ;
		END

		ANTENNAGATEAREA 0.00027817 ;
		ANTENNADIFFAREA 0.00194719 ;
		ANTENNAPARTIALMETALAREA 0.00195671 ;
	END D[62]

	PIN D[63]
		USE SIGNAL ;
		DIRECTION INPUT ;
		SHAPE ABUTMENT ;
		PORT
			 LAYER M2 ;
			RECT 0.0098 177.3427 0.0481 177.3804 ;
			 LAYER M3 ;
			RECT 0.0098 177.28 0.0481 177.3804 ;
			 LAYER V2 ;
			RECT 0.0215 177.3549 0.0364 177.3675 ;
		END

		ANTENNAGATEAREA 0.00027817 ;
		ANTENNADIFFAREA 0.00194719 ;
		ANTENNAPARTIALMETALAREA 0.00195671 ;
	END D[63]

	PIN D[64]
		USE SIGNAL ;
		DIRECTION INPUT ;
		SHAPE ABUTMENT ;
		PORT
			 LAYER M2 ;
			RECT 0.0098 179.9027 0.0481 179.9404 ;
			 LAYER M3 ;
			RECT 0.0098 179.84 0.0481 179.9404 ;
			 LAYER V2 ;
			RECT 0.0215 179.9149 0.0364 179.9275 ;
		END

		ANTENNAGATEAREA 0.00027817 ;
		ANTENNADIFFAREA 0.00194719 ;
		ANTENNAPARTIALMETALAREA 0.00195671 ;
	END D[64]

	PIN D[65]
		USE SIGNAL ;
		DIRECTION INPUT ;
		SHAPE ABUTMENT ;
		PORT
			 LAYER M2 ;
			RECT 0.0098 182.4627 0.0481 182.5004 ;
			 LAYER M3 ;
			RECT 0.0098 182.4 0.0481 182.5004 ;
			 LAYER V2 ;
			RECT 0.0215 182.4749 0.0364 182.4875 ;
		END

		ANTENNAGATEAREA 0.00027817 ;
		ANTENNADIFFAREA 0.00194719 ;
		ANTENNAPARTIALMETALAREA 0.00195671 ;
	END D[65]

	PIN D[66]
		USE SIGNAL ;
		DIRECTION INPUT ;
		SHAPE ABUTMENT ;
		PORT
			 LAYER M2 ;
			RECT 0.0098 185.0227 0.0481 185.0604 ;
			 LAYER M3 ;
			RECT 0.0098 184.96 0.0481 185.0604 ;
			 LAYER V2 ;
			RECT 0.0215 185.0349 0.0364 185.0475 ;
		END

		ANTENNAGATEAREA 0.00027817 ;
		ANTENNADIFFAREA 0.00194719 ;
		ANTENNAPARTIALMETALAREA 0.00195671 ;
	END D[66]

	PIN D[67]
		USE SIGNAL ;
		DIRECTION INPUT ;
		SHAPE ABUTMENT ;
		PORT
			 LAYER M2 ;
			RECT 0.0098 187.5827 0.0481 187.6204 ;
			 LAYER M3 ;
			RECT 0.0098 187.52 0.0481 187.6204 ;
			 LAYER V2 ;
			RECT 0.0215 187.5949 0.0364 187.6075 ;
		END

		ANTENNAGATEAREA 0.00027817 ;
		ANTENNADIFFAREA 0.00194719 ;
		ANTENNAPARTIALMETALAREA 0.00195671 ;
	END D[67]

	PIN D[68]
		USE SIGNAL ;
		DIRECTION INPUT ;
		SHAPE ABUTMENT ;
		PORT
			 LAYER M2 ;
			RECT 0.0098 190.1427 0.0481 190.1804 ;
			 LAYER M3 ;
			RECT 0.0098 190.08 0.0481 190.1804 ;
			 LAYER V2 ;
			RECT 0.0215 190.1549 0.0364 190.1675 ;
		END

		ANTENNAGATEAREA 0.00027817 ;
		ANTENNADIFFAREA 0.00194719 ;
		ANTENNAPARTIALMETALAREA 0.00195671 ;
	END D[68]

	PIN D[69]
		USE SIGNAL ;
		DIRECTION INPUT ;
		SHAPE ABUTMENT ;
		PORT
			 LAYER M2 ;
			RECT 0.0098 192.7027 0.0481 192.7404 ;
			 LAYER M3 ;
			RECT 0.0098 192.64 0.0481 192.7404 ;
			 LAYER V2 ;
			RECT 0.0215 192.7149 0.0364 192.7275 ;
		END

		ANTENNAGATEAREA 0.00027817 ;
		ANTENNADIFFAREA 0.00194719 ;
		ANTENNAPARTIALMETALAREA 0.00195671 ;
	END D[69]

	PIN D[6]
		USE SIGNAL ;
		DIRECTION INPUT ;
		SHAPE ABUTMENT ;
		PORT
			 LAYER M2 ;
			RECT 0.0098 18.0078 0.0481 18.0455 ;
			 LAYER M3 ;
			RECT 0.0098 18.0078 0.0481 18.1082 ;
			 LAYER V2 ;
			RECT 0.0215 18.0208 0.0364 18.0333 ;
		END

		ANTENNAGATEAREA 0.00027817 ;
		ANTENNADIFFAREA 0.00194719 ;
		ANTENNAPARTIALMETALAREA 0.00195671 ;
	END D[6]

	PIN D[70]
		USE SIGNAL ;
		DIRECTION INPUT ;
		SHAPE ABUTMENT ;
		PORT
			 LAYER M2 ;
			RECT 0.0098 195.2627 0.0481 195.3004 ;
			 LAYER M3 ;
			RECT 0.0098 195.2 0.0481 195.3004 ;
			 LAYER V2 ;
			RECT 0.0215 195.2749 0.0364 195.2875 ;
		END

		ANTENNAGATEAREA 0.00027817 ;
		ANTENNADIFFAREA 0.00194719 ;
		ANTENNAPARTIALMETALAREA 0.00195671 ;
	END D[70]

	PIN D[71]
		USE SIGNAL ;
		DIRECTION INPUT ;
		SHAPE ABUTMENT ;
		PORT
			 LAYER M2 ;
			RECT 0.0098 197.8227 0.0481 197.8604 ;
			 LAYER M3 ;
			RECT 0.0098 197.76 0.0481 197.8604 ;
			 LAYER V2 ;
			RECT 0.0215 197.8349 0.0364 197.8475 ;
		END

		ANTENNAGATEAREA 0.00027817 ;
		ANTENNADIFFAREA 0.00194719 ;
		ANTENNAPARTIALMETALAREA 0.00195671 ;
	END D[71]

	PIN D[7]
		USE SIGNAL ;
		DIRECTION INPUT ;
		SHAPE ABUTMENT ;
		PORT
			 LAYER M2 ;
			RECT 0.0098 20.5678 0.0481 20.6055 ;
			 LAYER M3 ;
			RECT 0.0098 20.5678 0.0481 20.6682 ;
			 LAYER V2 ;
			RECT 0.0215 20.5808 0.0364 20.5933 ;
		END

		ANTENNAGATEAREA 0.00027817 ;
		ANTENNADIFFAREA 0.00194719 ;
		ANTENNAPARTIALMETALAREA 0.00195671 ;
	END D[7]

	PIN D[8]
		USE SIGNAL ;
		DIRECTION INPUT ;
		SHAPE ABUTMENT ;
		PORT
			 LAYER M2 ;
			RECT 0.0098 23.1278 0.0481 23.1655 ;
			 LAYER M3 ;
			RECT 0.0098 23.1278 0.0481 23.2282 ;
			 LAYER V2 ;
			RECT 0.0215 23.1408 0.0364 23.1533 ;
		END

		ANTENNAGATEAREA 0.00027817 ;
		ANTENNADIFFAREA 0.00194719 ;
		ANTENNAPARTIALMETALAREA 0.00195671 ;
	END D[8]

	PIN D[9]
		USE SIGNAL ;
		DIRECTION INPUT ;
		SHAPE ABUTMENT ;
		PORT
			 LAYER M2 ;
			RECT 0.0098 25.6878 0.0481 25.7255 ;
			 LAYER M3 ;
			RECT 0.0098 25.6878 0.0481 25.7882 ;
			 LAYER V2 ;
			RECT 0.0215 25.7008 0.0364 25.7133 ;
		END

		ANTENNAGATEAREA 0.00027817 ;
		ANTENNADIFFAREA 0.00194719 ;
		ANTENNAPARTIALMETALAREA 0.00195671 ;
	END D[9]

	PIN EMAS
		USE SIGNAL ;
		DIRECTION INPUT ;
		SHAPE ABUTMENT ;
		PORT
			 LAYER M2 ;
			RECT 0.0098 93.2957 0.0481 93.3961 ;
			 LAYER M3 ;
			RECT 0.0098 93.2957 0.0481 93.3961 ;
			 LAYER V2 ;
			RECT 0.021 93.3706 0.0359 93.3831 ;
		END

		ANTENNAGATEAREA 0.00027817 ;
		ANTENNADIFFAREA 0.00194719 ;
		ANTENNAPARTIALMETALAREA 0.00195671 ;
	END EMAS

	PIN EMAW[0]
		USE SIGNAL ;
		DIRECTION INPUT ;
		SHAPE ABUTMENT ;
		PORT
			 LAYER M2 ;
			RECT 0.0098 90.6604 0.0481 90.7608 ;
			 LAYER M3 ;
			RECT 0.0098 90.6604 0.0481 90.7608 ;
			 LAYER V2 ;
			RECT 0.021 90.7353 0.0359 90.7478 ;
		END

		ANTENNAGATEAREA 0.00027817 ;
		ANTENNADIFFAREA 0.00194719 ;
		ANTENNAPARTIALMETALAREA 0.00195671 ;
	END EMAW[0]

	PIN EMAW[1]
		USE SIGNAL ;
		DIRECTION INPUT ;
		SHAPE ABUTMENT ;
		PORT
			 LAYER M2 ;
			RECT 0.0714 92.3922 0.1097 92.4298 ;
			 LAYER M3 ;
			RECT 0.0714 92.3922 0.1097 92.4925 ;
			 LAYER V2 ;
			RECT 0.0831 92.4043 0.098 92.4169 ;
		END

		ANTENNAGATEAREA 0.00027817 ;
		ANTENNADIFFAREA 0.00194719 ;
		ANTENNAPARTIALMETALAREA 0.00195671 ;
	END EMAW[1]

	PIN EMA[0]
		USE SIGNAL ;
		DIRECTION INPUT ;
		SHAPE ABUTMENT ;
		PORT
			 LAYER M2 ;
			RECT 0.0098 88.778 0.0481 88.8784 ;
			 LAYER M3 ;
			RECT 0.0098 88.778 0.0481 88.8784 ;
			 LAYER V2 ;
			RECT 0.021 88.8529 0.0359 88.8655 ;
		END

		ANTENNAGATEAREA 0.00027817 ;
		ANTENNADIFFAREA 0.00194719 ;
		ANTENNAPARTIALMETALAREA 0.00195671 ;
	END EMA[0]

	PIN EMA[1]
		USE SIGNAL ;
		DIRECTION INPUT ;
		SHAPE ABUTMENT ;
		PORT
			 LAYER M2 ;
			RECT 0.0098 87.4353 0.0481 87.4729 ;
			 LAYER M3 ;
			RECT 0.0098 87.3725 0.0481 87.4729 ;
			 LAYER V2 ;
			RECT 0.0215 87.4475 0.0364 87.46 ;
		END

		ANTENNAGATEAREA 0.00027817 ;
		ANTENNADIFFAREA 0.00194719 ;
		ANTENNAPARTIALMETALAREA 0.00195671 ;
	END EMA[1]

	PIN EMA[2]
		USE SIGNAL ;
		DIRECTION INPUT ;
		SHAPE ABUTMENT ;
		PORT
			 LAYER M2 ;
			RECT 0.0714 87.3725 0.1097 87.4102 ;
			 LAYER M3 ;
			RECT 0.0714 87.3725 0.1097 87.4729 ;
			 LAYER V2 ;
			RECT 0.0831 87.3847 0.098 87.3973 ;
		END

		ANTENNAGATEAREA 0.00027817 ;
		ANTENNADIFFAREA 0.00194719 ;
		ANTENNAPARTIALMETALAREA 0.00195671 ;
	END EMA[2]

	PIN GWEN
		USE SIGNAL ;
		DIRECTION INPUT ;
		SHAPE ABUTMENT ;
		PORT
			 LAYER M2 ;
			RECT 0.0098 107.0118 0.0481 107.1122 ;
			 LAYER M3 ;
			RECT 0.0098 107.0118 0.0481 107.1122 ;
			 LAYER V2 ;
			RECT 0.021 107.0867 0.0359 107.0992 ;
		END

		ANTENNAGATEAREA 0.00027817 ;
		ANTENNADIFFAREA 0.00194719 ;
		ANTENNAPARTIALMETALAREA 0.00195671 ;
	END GWEN

	PIN GWENY
		USE SIGNAL ;
		DIRECTION OUTPUT ;
		SHAPE ABUTMENT ;
		PORT
			 LAYER M2 ;
			RECT 0.0098 106.6353 0.0481 106.6729 ;
			 LAYER M3 ;
			RECT 0.0098 106.6353 0.0481 106.7357 ;
			 LAYER V2 ;
			RECT 0.0215 106.6482 0.0364 106.6608 ;
		END

		ANTENNADIFFAREA 0.00194719 ;
		ANTENNAPARTIALMETALAREA 0.00195671 ;
	END GWENY

	PIN Q[0]
		USE SIGNAL ;
		DIRECTION OUTPUT ;
		SHAPE ABUTMENT ;
		PORT
			 LAYER M2 ;
			RECT 0.0098 2.3718 0.0481 2.4722 ;
			 LAYER M3 ;
			RECT 0.0098 2.3718 0.0481 2.4722 ;
			 LAYER V2 ;
			RECT 0.021 2.4467 0.0359 2.4592 ;
		END

		ANTENNADIFFAREA 0.00194719 ;
		ANTENNAPARTIALMETALAREA 0.00195671 ;
	END Q[0]

	PIN Q[10]
		USE SIGNAL ;
		DIRECTION OUTPUT ;
		SHAPE ABUTMENT ;
		PORT
			 LAYER M2 ;
			RECT 0.0098 27.9718 0.0481 28.0722 ;
			 LAYER M3 ;
			RECT 0.0098 27.9718 0.0481 28.0722 ;
			 LAYER V2 ;
			RECT 0.021 28.0467 0.0359 28.0592 ;
		END

		ANTENNADIFFAREA 0.00194719 ;
		ANTENNAPARTIALMETALAREA 0.00195671 ;
	END Q[10]

	PIN Q[11]
		USE SIGNAL ;
		DIRECTION OUTPUT ;
		SHAPE ABUTMENT ;
		PORT
			 LAYER M2 ;
			RECT 0.0098 30.5318 0.0481 30.6322 ;
			 LAYER M3 ;
			RECT 0.0098 30.5318 0.0481 30.6322 ;
			 LAYER V2 ;
			RECT 0.021 30.6067 0.0359 30.6192 ;
		END

		ANTENNADIFFAREA 0.00194719 ;
		ANTENNAPARTIALMETALAREA 0.00195671 ;
	END Q[11]

	PIN Q[12]
		USE SIGNAL ;
		DIRECTION OUTPUT ;
		SHAPE ABUTMENT ;
		PORT
			 LAYER M2 ;
			RECT 0.0098 33.0918 0.0481 33.1922 ;
			 LAYER M3 ;
			RECT 0.0098 33.0918 0.0481 33.1922 ;
			 LAYER V2 ;
			RECT 0.021 33.1667 0.0359 33.1792 ;
		END

		ANTENNADIFFAREA 0.00194719 ;
		ANTENNAPARTIALMETALAREA 0.00195671 ;
	END Q[12]

	PIN Q[13]
		USE SIGNAL ;
		DIRECTION OUTPUT ;
		SHAPE ABUTMENT ;
		PORT
			 LAYER M2 ;
			RECT 0.0098 35.6518 0.0481 35.7522 ;
			 LAYER M3 ;
			RECT 0.0098 35.6518 0.0481 35.7522 ;
			 LAYER V2 ;
			RECT 0.021 35.7267 0.0359 35.7392 ;
		END

		ANTENNADIFFAREA 0.00194719 ;
		ANTENNAPARTIALMETALAREA 0.00195671 ;
	END Q[13]

	PIN Q[14]
		USE SIGNAL ;
		DIRECTION OUTPUT ;
		SHAPE ABUTMENT ;
		PORT
			 LAYER M2 ;
			RECT 0.0098 38.2118 0.0481 38.3122 ;
			 LAYER M3 ;
			RECT 0.0098 38.2118 0.0481 38.3122 ;
			 LAYER V2 ;
			RECT 0.021 38.2867 0.0359 38.2992 ;
		END

		ANTENNADIFFAREA 0.00194719 ;
		ANTENNAPARTIALMETALAREA 0.00195671 ;
	END Q[14]

	PIN Q[15]
		USE SIGNAL ;
		DIRECTION OUTPUT ;
		SHAPE ABUTMENT ;
		PORT
			 LAYER M2 ;
			RECT 0.0098 40.7718 0.0481 40.8722 ;
			 LAYER M3 ;
			RECT 0.0098 40.7718 0.0481 40.8722 ;
			 LAYER V2 ;
			RECT 0.021 40.8467 0.0359 40.8592 ;
		END

		ANTENNADIFFAREA 0.00194719 ;
		ANTENNAPARTIALMETALAREA 0.00195671 ;
	END Q[15]

	PIN Q[16]
		USE SIGNAL ;
		DIRECTION OUTPUT ;
		SHAPE ABUTMENT ;
		PORT
			 LAYER M2 ;
			RECT 0.0098 43.3318 0.0481 43.4322 ;
			 LAYER M3 ;
			RECT 0.0098 43.3318 0.0481 43.4322 ;
			 LAYER V2 ;
			RECT 0.021 43.4067 0.0359 43.4192 ;
		END

		ANTENNADIFFAREA 0.00194719 ;
		ANTENNAPARTIALMETALAREA 0.00195671 ;
	END Q[16]

	PIN Q[17]
		USE SIGNAL ;
		DIRECTION OUTPUT ;
		SHAPE ABUTMENT ;
		PORT
			 LAYER M2 ;
			RECT 0.0098 45.8918 0.0481 45.9922 ;
			 LAYER M3 ;
			RECT 0.0098 45.8918 0.0481 45.9922 ;
			 LAYER V2 ;
			RECT 0.021 45.9667 0.0359 45.9792 ;
		END

		ANTENNADIFFAREA 0.00194719 ;
		ANTENNAPARTIALMETALAREA 0.00195671 ;
	END Q[17]

	PIN Q[18]
		USE SIGNAL ;
		DIRECTION OUTPUT ;
		SHAPE ABUTMENT ;
		PORT
			 LAYER M2 ;
			RECT 0.0098 56.1506 0.0481 56.251 ;
			 LAYER M3 ;
			RECT 0.0098 56.1506 0.0481 56.251 ;
			 LAYER V2 ;
			RECT 0.021 56.2255 0.0359 56.238 ;
		END

		ANTENNADIFFAREA 0.00194719 ;
		ANTENNAPARTIALMETALAREA 0.00195671 ;
	END Q[18]

	PIN Q[19]
		USE SIGNAL ;
		DIRECTION OUTPUT ;
		SHAPE ABUTMENT ;
		PORT
			 LAYER M2 ;
			RECT 0.0098 58.7106 0.0481 58.811 ;
			 LAYER M3 ;
			RECT 0.0098 58.7106 0.0481 58.811 ;
			 LAYER V2 ;
			RECT 0.021 58.7855 0.0359 58.798 ;
		END

		ANTENNADIFFAREA 0.00194719 ;
		ANTENNAPARTIALMETALAREA 0.00195671 ;
	END Q[19]

	PIN Q[1]
		USE SIGNAL ;
		DIRECTION OUTPUT ;
		SHAPE ABUTMENT ;
		PORT
			 LAYER M2 ;
			RECT 0.0098 4.9318 0.0481 5.0322 ;
			 LAYER M3 ;
			RECT 0.0098 4.9318 0.0481 5.0322 ;
			 LAYER V2 ;
			RECT 0.021 5.0067 0.0359 5.0192 ;
		END

		ANTENNADIFFAREA 0.00194719 ;
		ANTENNAPARTIALMETALAREA 0.00195671 ;
	END Q[1]

	PIN Q[20]
		USE SIGNAL ;
		DIRECTION OUTPUT ;
		SHAPE ABUTMENT ;
		PORT
			 LAYER M2 ;
			RECT 0.0098 61.2706 0.0481 61.371 ;
			 LAYER M3 ;
			RECT 0.0098 61.2706 0.0481 61.371 ;
			 LAYER V2 ;
			RECT 0.021 61.3455 0.0359 61.358 ;
		END

		ANTENNADIFFAREA 0.00194719 ;
		ANTENNAPARTIALMETALAREA 0.00195671 ;
	END Q[20]

	PIN Q[21]
		USE SIGNAL ;
		DIRECTION OUTPUT ;
		SHAPE ABUTMENT ;
		PORT
			 LAYER M2 ;
			RECT 0.0098 63.8306 0.0481 63.931 ;
			 LAYER M3 ;
			RECT 0.0098 63.8306 0.0481 63.931 ;
			 LAYER V2 ;
			RECT 0.021 63.9055 0.0359 63.918 ;
		END

		ANTENNADIFFAREA 0.00194719 ;
		ANTENNAPARTIALMETALAREA 0.00195671 ;
	END Q[21]

	PIN Q[22]
		USE SIGNAL ;
		DIRECTION OUTPUT ;
		SHAPE ABUTMENT ;
		PORT
			 LAYER M2 ;
			RECT 0.0098 66.3906 0.0481 66.491 ;
			 LAYER M3 ;
			RECT 0.0098 66.3906 0.0481 66.491 ;
			 LAYER V2 ;
			RECT 0.021 66.4655 0.0359 66.478 ;
		END

		ANTENNADIFFAREA 0.00194719 ;
		ANTENNAPARTIALMETALAREA 0.00195671 ;
	END Q[22]

	PIN Q[23]
		USE SIGNAL ;
		DIRECTION OUTPUT ;
		SHAPE ABUTMENT ;
		PORT
			 LAYER M2 ;
			RECT 0.0098 68.9506 0.0481 69.051 ;
			 LAYER M3 ;
			RECT 0.0098 68.9506 0.0481 69.051 ;
			 LAYER V2 ;
			RECT 0.021 69.0255 0.0359 69.038 ;
		END

		ANTENNADIFFAREA 0.00194719 ;
		ANTENNAPARTIALMETALAREA 0.00195671 ;
	END Q[23]

	PIN Q[24]
		USE SIGNAL ;
		DIRECTION OUTPUT ;
		SHAPE ABUTMENT ;
		PORT
			 LAYER M2 ;
			RECT 0.0098 71.5106 0.0481 71.611 ;
			 LAYER M3 ;
			RECT 0.0098 71.5106 0.0481 71.611 ;
			 LAYER V2 ;
			RECT 0.021 71.5855 0.0359 71.598 ;
		END

		ANTENNADIFFAREA 0.00194719 ;
		ANTENNAPARTIALMETALAREA 0.00195671 ;
	END Q[24]

	PIN Q[25]
		USE SIGNAL ;
		DIRECTION OUTPUT ;
		SHAPE ABUTMENT ;
		PORT
			 LAYER M2 ;
			RECT 0.0098 74.0706 0.0481 74.171 ;
			 LAYER M3 ;
			RECT 0.0098 74.0706 0.0481 74.171 ;
			 LAYER V2 ;
			RECT 0.021 74.1455 0.0359 74.158 ;
		END

		ANTENNADIFFAREA 0.00194719 ;
		ANTENNAPARTIALMETALAREA 0.00195671 ;
	END Q[25]

	PIN Q[26]
		USE SIGNAL ;
		DIRECTION OUTPUT ;
		SHAPE ABUTMENT ;
		PORT
			 LAYER M2 ;
			RECT 0.0098 76.6306 0.0481 76.731 ;
			 LAYER M3 ;
			RECT 0.0098 76.6306 0.0481 76.731 ;
			 LAYER V2 ;
			RECT 0.021 76.7055 0.0359 76.718 ;
		END

		ANTENNADIFFAREA 0.00194719 ;
		ANTENNAPARTIALMETALAREA 0.00195671 ;
	END Q[26]

	PIN Q[27]
		USE SIGNAL ;
		DIRECTION OUTPUT ;
		SHAPE ABUTMENT ;
		PORT
			 LAYER M2 ;
			RECT 0.0098 79.1906 0.0481 79.291 ;
			 LAYER M3 ;
			RECT 0.0098 79.1906 0.0481 79.291 ;
			 LAYER V2 ;
			RECT 0.021 79.2655 0.0359 79.278 ;
		END

		ANTENNADIFFAREA 0.00194719 ;
		ANTENNAPARTIALMETALAREA 0.00195671 ;
	END Q[27]

	PIN Q[28]
		USE SIGNAL ;
		DIRECTION OUTPUT ;
		SHAPE ABUTMENT ;
		PORT
			 LAYER M2 ;
			RECT 0.0098 81.7506 0.0481 81.851 ;
			 LAYER M3 ;
			RECT 0.0098 81.7506 0.0481 81.851 ;
			 LAYER V2 ;
			RECT 0.021 81.8255 0.0359 81.838 ;
		END

		ANTENNADIFFAREA 0.00194719 ;
		ANTENNAPARTIALMETALAREA 0.00195671 ;
	END Q[28]

	PIN Q[29]
		USE SIGNAL ;
		DIRECTION OUTPUT ;
		SHAPE ABUTMENT ;
		PORT
			 LAYER M2 ;
			RECT 0.0098 84.3106 0.0481 84.411 ;
			 LAYER M3 ;
			RECT 0.0098 84.3106 0.0481 84.411 ;
			 LAYER V2 ;
			RECT 0.021 84.3855 0.0359 84.398 ;
		END

		ANTENNADIFFAREA 0.00194719 ;
		ANTENNAPARTIALMETALAREA 0.00195671 ;
	END Q[29]

	PIN Q[2]
		USE SIGNAL ;
		DIRECTION OUTPUT ;
		SHAPE ABUTMENT ;
		PORT
			 LAYER M2 ;
			RECT 0.0098 7.4918 0.0481 7.5922 ;
			 LAYER M3 ;
			RECT 0.0098 7.4918 0.0481 7.5922 ;
			 LAYER V2 ;
			RECT 0.021 7.5667 0.0359 7.5792 ;
		END

		ANTENNADIFFAREA 0.00194719 ;
		ANTENNAPARTIALMETALAREA 0.00195671 ;
	END Q[2]

	PIN Q[30]
		USE SIGNAL ;
		DIRECTION OUTPUT ;
		SHAPE ABUTMENT ;
		PORT
			 LAYER M2 ;
			RECT 0.0098 86.8706 0.0481 86.971 ;
			 LAYER M3 ;
			RECT 0.0098 86.8706 0.0481 86.971 ;
			 LAYER V2 ;
			RECT 0.021 86.9455 0.0359 86.958 ;
		END

		ANTENNADIFFAREA 0.00194719 ;
		ANTENNAPARTIALMETALAREA 0.00195671 ;
	END Q[30]

	PIN Q[31]
		USE SIGNAL ;
		DIRECTION OUTPUT ;
		SHAPE ABUTMENT ;
		PORT
			 LAYER M2 ;
			RECT 0.0714 89.4055 0.1097 89.4431 ;
			 LAYER M3 ;
			RECT 0.0714 89.4055 0.1097 89.5059 ;
			 LAYER V2 ;
			RECT 0.0831 89.4176 0.098 89.4302 ;
		END

		ANTENNADIFFAREA 0.00194719 ;
		ANTENNAPARTIALMETALAREA 0.00195671 ;
	END Q[31]

	PIN Q[32]
		USE SIGNAL ;
		DIRECTION OUTPUT ;
		SHAPE ABUTMENT ;
		PORT
			 LAYER M2 ;
			RECT 0.0098 91.9529 0.0481 91.9906 ;
			 LAYER M3 ;
			RECT 0.0098 91.8902 0.0481 91.9906 ;
			 LAYER V2 ;
			RECT 0.0215 91.9651 0.0364 91.9776 ;
		END

		ANTENNADIFFAREA 0.00194719 ;
		ANTENNAPARTIALMETALAREA 0.00195671 ;
	END Q[32]

	PIN Q[33]
		USE SIGNAL ;
		DIRECTION OUTPUT ;
		SHAPE ABUTMENT ;
		PORT
			 LAYER M2 ;
			RECT 0.0098 94.4878 0.0481 94.5255 ;
			 LAYER M3 ;
			RECT 0.0098 94.4251 0.0481 94.5255 ;
			 LAYER V2 ;
			RECT 0.0215 94.5 0.0364 94.5125 ;
		END

		ANTENNADIFFAREA 0.00194719 ;
		ANTENNAPARTIALMETALAREA 0.00195671 ;
	END Q[33]

	PIN Q[34]
		USE SIGNAL ;
		DIRECTION OUTPUT ;
		SHAPE ABUTMENT ;
		PORT
			 LAYER M2 ;
			RECT 0.0714 97.0604 0.1097 97.098 ;
			 LAYER M3 ;
			RECT 0.0714 97.0604 0.1097 97.1608 ;
			 LAYER V2 ;
			RECT 0.0831 97.0725 0.098 97.0851 ;
		END

		ANTENNADIFFAREA 0.00194719 ;
		ANTENNAPARTIALMETALAREA 0.00195671 ;
	END Q[34]

	PIN Q[35]
		USE SIGNAL ;
		DIRECTION OUTPUT ;
		SHAPE ABUTMENT ;
		PORT
			 LAYER M2 ;
			RECT 0.0714 99.6204 0.1097 99.658 ;
			 LAYER M3 ;
			RECT 0.0714 99.6204 0.1097 99.7208 ;
			 LAYER V2 ;
			RECT 0.0831 99.6325 0.098 99.6451 ;
		END

		ANTENNADIFFAREA 0.00194719 ;
		ANTENNAPARTIALMETALAREA 0.00195671 ;
	END Q[35]

	PIN Q[36]
		USE SIGNAL ;
		DIRECTION OUTPUT ;
		SHAPE ABUTMENT ;
		PORT
			 LAYER M2 ;
			RECT 0.0714 100.8251 0.1097 100.8627 ;
			 LAYER M3 ;
			RECT 0.0714 100.7624 0.1097 100.8627 ;
			 LAYER V2 ;
			RECT 0.0831 100.838 0.098 100.8506 ;
		END

		ANTENNADIFFAREA 0.00194719 ;
		ANTENNAPARTIALMETALAREA 0.00195671 ;
	END Q[36]

	PIN Q[37]
		USE SIGNAL ;
		DIRECTION OUTPUT ;
		SHAPE ABUTMENT ;
		PORT
			 LAYER M2 ;
			RECT 0.0714 103.3851 0.1097 103.4227 ;
			 LAYER M3 ;
			RECT 0.0714 103.3224 0.1097 103.4227 ;
			 LAYER V2 ;
			RECT 0.0831 103.398 0.098 103.4106 ;
		END

		ANTENNADIFFAREA 0.00194719 ;
		ANTENNAPARTIALMETALAREA 0.00195671 ;
	END Q[37]

	PIN Q[38]
		USE SIGNAL ;
		DIRECTION OUTPUT ;
		SHAPE ABUTMENT ;
		PORT
			 LAYER M2 ;
			RECT 0.0714 105.9451 0.1097 105.9827 ;
			 LAYER M3 ;
			RECT 0.0714 105.8824 0.1097 105.9827 ;
			 LAYER V2 ;
			RECT 0.0831 105.958 0.098 105.9706 ;
		END

		ANTENNADIFFAREA 0.00194719 ;
		ANTENNAPARTIALMETALAREA 0.00195671 ;
	END Q[38]

	PIN Q[39]
		USE SIGNAL ;
		DIRECTION OUTPUT ;
		SHAPE ABUTMENT ;
		PORT
			 LAYER M2 ;
			RECT 0.0714 108.5051 0.1097 108.5427 ;
			 LAYER M3 ;
			RECT 0.0714 108.4424 0.1097 108.5427 ;
			 LAYER V2 ;
			RECT 0.0831 108.518 0.098 108.5306 ;
		END

		ANTENNADIFFAREA 0.00194719 ;
		ANTENNAPARTIALMETALAREA 0.00195671 ;
	END Q[39]

	PIN Q[3]
		USE SIGNAL ;
		DIRECTION OUTPUT ;
		SHAPE ABUTMENT ;
		PORT
			 LAYER M2 ;
			RECT 0.0098 10.0518 0.0481 10.1522 ;
			 LAYER M3 ;
			RECT 0.0098 10.0518 0.0481 10.1522 ;
			 LAYER V2 ;
			RECT 0.021 10.1267 0.0359 10.1392 ;
		END

		ANTENNADIFFAREA 0.00194719 ;
		ANTENNAPARTIALMETALAREA 0.00195671 ;
	END Q[3]

	PIN Q[40]
		USE SIGNAL ;
		DIRECTION OUTPUT ;
		SHAPE ABUTMENT ;
		PORT
			 LAYER M2 ;
			RECT 0.0714 111.0651 0.1097 111.1027 ;
			 LAYER M3 ;
			RECT 0.0714 111.0024 0.1097 111.1027 ;
			 LAYER V2 ;
			RECT 0.0831 111.078 0.098 111.0906 ;
		END

		ANTENNADIFFAREA 0.00194719 ;
		ANTENNAPARTIALMETALAREA 0.00195671 ;
	END Q[40]

	PIN Q[41]
		USE SIGNAL ;
		DIRECTION OUTPUT ;
		SHAPE ABUTMENT ;
		PORT
			 LAYER M2 ;
			RECT 0.0098 113.5373 0.0481 113.6376 ;
			 LAYER M3 ;
			RECT 0.0098 113.5373 0.0481 113.6376 ;
			 LAYER V2 ;
			RECT 0.021 113.5502 0.0359 113.5627 ;
		END

		ANTENNADIFFAREA 0.00194719 ;
		ANTENNAPARTIALMETALAREA 0.00195671 ;
	END Q[41]

	PIN Q[42]
		USE SIGNAL ;
		DIRECTION OUTPUT ;
		SHAPE ABUTMENT ;
		PORT
			 LAYER M2 ;
			RECT 0.0098 116.0973 0.0481 116.1976 ;
			 LAYER M3 ;
			RECT 0.0098 116.0973 0.0481 116.1976 ;
			 LAYER V2 ;
			RECT 0.021 116.1102 0.0359 116.1227 ;
		END

		ANTENNADIFFAREA 0.00194719 ;
		ANTENNAPARTIALMETALAREA 0.00195671 ;
	END Q[42]

	PIN Q[43]
		USE SIGNAL ;
		DIRECTION OUTPUT ;
		SHAPE ABUTMENT ;
		PORT
			 LAYER M2 ;
			RECT 0.0098 118.6573 0.0481 118.7576 ;
			 LAYER M3 ;
			RECT 0.0098 118.6573 0.0481 118.7576 ;
			 LAYER V2 ;
			RECT 0.021 118.6702 0.0359 118.6827 ;
		END

		ANTENNADIFFAREA 0.00194719 ;
		ANTENNAPARTIALMETALAREA 0.00195671 ;
	END Q[43]

	PIN Q[44]
		USE SIGNAL ;
		DIRECTION OUTPUT ;
		SHAPE ABUTMENT ;
		PORT
			 LAYER M2 ;
			RECT 0.0098 121.2173 0.0481 121.3176 ;
			 LAYER M3 ;
			RECT 0.0098 121.2173 0.0481 121.3176 ;
			 LAYER V2 ;
			RECT 0.021 121.2302 0.0359 121.2427 ;
		END

		ANTENNADIFFAREA 0.00194719 ;
		ANTENNAPARTIALMETALAREA 0.00195671 ;
	END Q[44]

	PIN Q[45]
		USE SIGNAL ;
		DIRECTION OUTPUT ;
		SHAPE ABUTMENT ;
		PORT
			 LAYER M2 ;
			RECT 0.0098 123.7773 0.0481 123.8776 ;
			 LAYER M3 ;
			RECT 0.0098 123.7773 0.0481 123.8776 ;
			 LAYER V2 ;
			RECT 0.021 123.7902 0.0359 123.8027 ;
		END

		ANTENNADIFFAREA 0.00194719 ;
		ANTENNAPARTIALMETALAREA 0.00195671 ;
	END Q[45]

	PIN Q[46]
		USE SIGNAL ;
		DIRECTION OUTPUT ;
		SHAPE ABUTMENT ;
		PORT
			 LAYER M2 ;
			RECT 0.0098 126.3373 0.0481 126.4376 ;
			 LAYER M3 ;
			RECT 0.0098 126.3373 0.0481 126.4376 ;
			 LAYER V2 ;
			RECT 0.021 126.3502 0.0359 126.3627 ;
		END

		ANTENNADIFFAREA 0.00194719 ;
		ANTENNAPARTIALMETALAREA 0.00195671 ;
	END Q[46]

	PIN Q[47]
		USE SIGNAL ;
		DIRECTION OUTPUT ;
		SHAPE ABUTMENT ;
		PORT
			 LAYER M2 ;
			RECT 0.0098 128.8973 0.0481 128.9976 ;
			 LAYER M3 ;
			RECT 0.0098 128.8973 0.0481 128.9976 ;
			 LAYER V2 ;
			RECT 0.021 128.9102 0.0359 128.9227 ;
		END

		ANTENNADIFFAREA 0.00194719 ;
		ANTENNAPARTIALMETALAREA 0.00195671 ;
	END Q[47]

	PIN Q[48]
		USE SIGNAL ;
		DIRECTION OUTPUT ;
		SHAPE ABUTMENT ;
		PORT
			 LAYER M2 ;
			RECT 0.0098 131.4573 0.0481 131.5576 ;
			 LAYER M3 ;
			RECT 0.0098 131.4573 0.0481 131.5576 ;
			 LAYER V2 ;
			RECT 0.021 131.4702 0.0359 131.4827 ;
		END

		ANTENNADIFFAREA 0.00194719 ;
		ANTENNAPARTIALMETALAREA 0.00195671 ;
	END Q[48]

	PIN Q[49]
		USE SIGNAL ;
		DIRECTION OUTPUT ;
		SHAPE ABUTMENT ;
		PORT
			 LAYER M2 ;
			RECT 0.0098 134.0173 0.0481 134.1176 ;
			 LAYER M3 ;
			RECT 0.0098 134.0173 0.0481 134.1176 ;
			 LAYER V2 ;
			RECT 0.021 134.0302 0.0359 134.0427 ;
		END

		ANTENNADIFFAREA 0.00194719 ;
		ANTENNAPARTIALMETALAREA 0.00195671 ;
	END Q[49]

	PIN Q[4]
		USE SIGNAL ;
		DIRECTION OUTPUT ;
		SHAPE ABUTMENT ;
		PORT
			 LAYER M2 ;
			RECT 0.0098 12.6118 0.0481 12.7122 ;
			 LAYER M3 ;
			RECT 0.0098 12.6118 0.0481 12.7122 ;
			 LAYER V2 ;
			RECT 0.021 12.6867 0.0359 12.6992 ;
		END

		ANTENNADIFFAREA 0.00194719 ;
		ANTENNAPARTIALMETALAREA 0.00195671 ;
	END Q[4]

	PIN Q[50]
		USE SIGNAL ;
		DIRECTION OUTPUT ;
		SHAPE ABUTMENT ;
		PORT
			 LAYER M2 ;
			RECT 0.0098 136.5773 0.0481 136.6776 ;
			 LAYER M3 ;
			RECT 0.0098 136.5773 0.0481 136.6776 ;
			 LAYER V2 ;
			RECT 0.021 136.5902 0.0359 136.6027 ;
		END

		ANTENNADIFFAREA 0.00194719 ;
		ANTENNAPARTIALMETALAREA 0.00195671 ;
	END Q[50]

	PIN Q[51]
		USE SIGNAL ;
		DIRECTION OUTPUT ;
		SHAPE ABUTMENT ;
		PORT
			 LAYER M2 ;
			RECT 0.0098 139.1373 0.0481 139.2376 ;
			 LAYER M3 ;
			RECT 0.0098 139.1373 0.0481 139.2376 ;
			 LAYER V2 ;
			RECT 0.021 139.1502 0.0359 139.1627 ;
		END

		ANTENNADIFFAREA 0.00194719 ;
		ANTENNAPARTIALMETALAREA 0.00195671 ;
	END Q[51]

	PIN Q[52]
		USE SIGNAL ;
		DIRECTION OUTPUT ;
		SHAPE ABUTMENT ;
		PORT
			 LAYER M2 ;
			RECT 0.0098 141.6973 0.0481 141.7976 ;
			 LAYER M3 ;
			RECT 0.0098 141.6973 0.0481 141.7976 ;
			 LAYER V2 ;
			RECT 0.021 141.7102 0.0359 141.7227 ;
		END

		ANTENNADIFFAREA 0.00194719 ;
		ANTENNAPARTIALMETALAREA 0.00195671 ;
	END Q[52]

	PIN Q[53]
		USE SIGNAL ;
		DIRECTION OUTPUT ;
		SHAPE ABUTMENT ;
		PORT
			 LAYER M2 ;
			RECT 0.0098 144.2573 0.0481 144.3576 ;
			 LAYER M3 ;
			RECT 0.0098 144.2573 0.0481 144.3576 ;
			 LAYER V2 ;
			RECT 0.021 144.2702 0.0359 144.2827 ;
		END

		ANTENNADIFFAREA 0.00194719 ;
		ANTENNAPARTIALMETALAREA 0.00195671 ;
	END Q[53]

	PIN Q[54]
		USE SIGNAL ;
		DIRECTION OUTPUT ;
		SHAPE ABUTMENT ;
		PORT
			 LAYER M2 ;
			RECT 0.0098 154.5161 0.0481 154.6165 ;
			 LAYER M3 ;
			RECT 0.0098 154.5161 0.0481 154.6165 ;
			 LAYER V2 ;
			RECT 0.021 154.529 0.0359 154.5416 ;
		END

		ANTENNADIFFAREA 0.00194719 ;
		ANTENNAPARTIALMETALAREA 0.00195671 ;
	END Q[54]

	PIN Q[55]
		USE SIGNAL ;
		DIRECTION OUTPUT ;
		SHAPE ABUTMENT ;
		PORT
			 LAYER M2 ;
			RECT 0.0098 157.0761 0.0481 157.1765 ;
			 LAYER M3 ;
			RECT 0.0098 157.0761 0.0481 157.1765 ;
			 LAYER V2 ;
			RECT 0.021 157.089 0.0359 157.1016 ;
		END

		ANTENNADIFFAREA 0.00194719 ;
		ANTENNAPARTIALMETALAREA 0.00195671 ;
	END Q[55]

	PIN Q[56]
		USE SIGNAL ;
		DIRECTION OUTPUT ;
		SHAPE ABUTMENT ;
		PORT
			 LAYER M2 ;
			RECT 0.0098 159.6361 0.0481 159.7365 ;
			 LAYER M3 ;
			RECT 0.0098 159.6361 0.0481 159.7365 ;
			 LAYER V2 ;
			RECT 0.021 159.649 0.0359 159.6616 ;
		END

		ANTENNADIFFAREA 0.00194719 ;
		ANTENNAPARTIALMETALAREA 0.00195671 ;
	END Q[56]

	PIN Q[57]
		USE SIGNAL ;
		DIRECTION OUTPUT ;
		SHAPE ABUTMENT ;
		PORT
			 LAYER M2 ;
			RECT 0.0098 162.1961 0.0481 162.2965 ;
			 LAYER M3 ;
			RECT 0.0098 162.1961 0.0481 162.2965 ;
			 LAYER V2 ;
			RECT 0.021 162.209 0.0359 162.2216 ;
		END

		ANTENNADIFFAREA 0.00194719 ;
		ANTENNAPARTIALMETALAREA 0.00195671 ;
	END Q[57]

	PIN Q[58]
		USE SIGNAL ;
		DIRECTION OUTPUT ;
		SHAPE ABUTMENT ;
		PORT
			 LAYER M2 ;
			RECT 0.0098 164.7561 0.0481 164.8565 ;
			 LAYER M3 ;
			RECT 0.0098 164.7561 0.0481 164.8565 ;
			 LAYER V2 ;
			RECT 0.021 164.769 0.0359 164.7816 ;
		END

		ANTENNADIFFAREA 0.00194719 ;
		ANTENNAPARTIALMETALAREA 0.00195671 ;
	END Q[58]

	PIN Q[59]
		USE SIGNAL ;
		DIRECTION OUTPUT ;
		SHAPE ABUTMENT ;
		PORT
			 LAYER M2 ;
			RECT 0.0098 167.3161 0.0481 167.4165 ;
			 LAYER M3 ;
			RECT 0.0098 167.3161 0.0481 167.4165 ;
			 LAYER V2 ;
			RECT 0.021 167.329 0.0359 167.3416 ;
		END

		ANTENNADIFFAREA 0.00194719 ;
		ANTENNAPARTIALMETALAREA 0.00195671 ;
	END Q[59]

	PIN Q[5]
		USE SIGNAL ;
		DIRECTION OUTPUT ;
		SHAPE ABUTMENT ;
		PORT
			 LAYER M2 ;
			RECT 0.0098 15.1718 0.0481 15.2722 ;
			 LAYER M3 ;
			RECT 0.0098 15.1718 0.0481 15.2722 ;
			 LAYER V2 ;
			RECT 0.021 15.2467 0.0359 15.2592 ;
		END

		ANTENNADIFFAREA 0.00194719 ;
		ANTENNAPARTIALMETALAREA 0.00195671 ;
	END Q[5]

	PIN Q[60]
		USE SIGNAL ;
		DIRECTION OUTPUT ;
		SHAPE ABUTMENT ;
		PORT
			 LAYER M2 ;
			RECT 0.0098 169.8761 0.0481 169.9765 ;
			 LAYER M3 ;
			RECT 0.0098 169.8761 0.0481 169.9765 ;
			 LAYER V2 ;
			RECT 0.021 169.889 0.0359 169.9016 ;
		END

		ANTENNADIFFAREA 0.00194719 ;
		ANTENNAPARTIALMETALAREA 0.00195671 ;
	END Q[60]

	PIN Q[61]
		USE SIGNAL ;
		DIRECTION OUTPUT ;
		SHAPE ABUTMENT ;
		PORT
			 LAYER M2 ;
			RECT 0.0098 172.4361 0.0481 172.5365 ;
			 LAYER M3 ;
			RECT 0.0098 172.4361 0.0481 172.5365 ;
			 LAYER V2 ;
			RECT 0.021 172.449 0.0359 172.4616 ;
		END

		ANTENNADIFFAREA 0.00194719 ;
		ANTENNAPARTIALMETALAREA 0.00195671 ;
	END Q[61]

	PIN Q[62]
		USE SIGNAL ;
		DIRECTION OUTPUT ;
		SHAPE ABUTMENT ;
		PORT
			 LAYER M2 ;
			RECT 0.0098 174.9961 0.0481 175.0965 ;
			 LAYER M3 ;
			RECT 0.0098 174.9961 0.0481 175.0965 ;
			 LAYER V2 ;
			RECT 0.021 175.009 0.0359 175.0216 ;
		END

		ANTENNADIFFAREA 0.00194719 ;
		ANTENNAPARTIALMETALAREA 0.00195671 ;
	END Q[62]

	PIN Q[63]
		USE SIGNAL ;
		DIRECTION OUTPUT ;
		SHAPE ABUTMENT ;
		PORT
			 LAYER M2 ;
			RECT 0.0098 177.5561 0.0481 177.6565 ;
			 LAYER M3 ;
			RECT 0.0098 177.5561 0.0481 177.6565 ;
			 LAYER V2 ;
			RECT 0.021 177.569 0.0359 177.5816 ;
		END

		ANTENNADIFFAREA 0.00194719 ;
		ANTENNAPARTIALMETALAREA 0.00195671 ;
	END Q[63]

	PIN Q[64]
		USE SIGNAL ;
		DIRECTION OUTPUT ;
		SHAPE ABUTMENT ;
		PORT
			 LAYER M2 ;
			RECT 0.0098 180.1161 0.0481 180.2165 ;
			 LAYER M3 ;
			RECT 0.0098 180.1161 0.0481 180.2165 ;
			 LAYER V2 ;
			RECT 0.021 180.129 0.0359 180.1416 ;
		END

		ANTENNADIFFAREA 0.00194719 ;
		ANTENNAPARTIALMETALAREA 0.00195671 ;
	END Q[64]

	PIN Q[65]
		USE SIGNAL ;
		DIRECTION OUTPUT ;
		SHAPE ABUTMENT ;
		PORT
			 LAYER M2 ;
			RECT 0.0098 182.6761 0.0481 182.7765 ;
			 LAYER M3 ;
			RECT 0.0098 182.6761 0.0481 182.7765 ;
			 LAYER V2 ;
			RECT 0.021 182.689 0.0359 182.7016 ;
		END

		ANTENNADIFFAREA 0.00194719 ;
		ANTENNAPARTIALMETALAREA 0.00195671 ;
	END Q[65]

	PIN Q[66]
		USE SIGNAL ;
		DIRECTION OUTPUT ;
		SHAPE ABUTMENT ;
		PORT
			 LAYER M2 ;
			RECT 0.0098 185.2361 0.0481 185.3365 ;
			 LAYER M3 ;
			RECT 0.0098 185.2361 0.0481 185.3365 ;
			 LAYER V2 ;
			RECT 0.021 185.249 0.0359 185.2616 ;
		END

		ANTENNADIFFAREA 0.00194719 ;
		ANTENNAPARTIALMETALAREA 0.00195671 ;
	END Q[66]

	PIN Q[67]
		USE SIGNAL ;
		DIRECTION OUTPUT ;
		SHAPE ABUTMENT ;
		PORT
			 LAYER M2 ;
			RECT 0.0098 187.7961 0.0481 187.8965 ;
			 LAYER M3 ;
			RECT 0.0098 187.7961 0.0481 187.8965 ;
			 LAYER V2 ;
			RECT 0.021 187.809 0.0359 187.8216 ;
		END

		ANTENNADIFFAREA 0.00194719 ;
		ANTENNAPARTIALMETALAREA 0.00195671 ;
	END Q[67]

	PIN Q[68]
		USE SIGNAL ;
		DIRECTION OUTPUT ;
		SHAPE ABUTMENT ;
		PORT
			 LAYER M2 ;
			RECT 0.0098 190.3561 0.0481 190.4565 ;
			 LAYER M3 ;
			RECT 0.0098 190.3561 0.0481 190.4565 ;
			 LAYER V2 ;
			RECT 0.021 190.369 0.0359 190.3816 ;
		END

		ANTENNADIFFAREA 0.00194719 ;
		ANTENNAPARTIALMETALAREA 0.00195671 ;
	END Q[68]

	PIN Q[69]
		USE SIGNAL ;
		DIRECTION OUTPUT ;
		SHAPE ABUTMENT ;
		PORT
			 LAYER M2 ;
			RECT 0.0098 192.9161 0.0481 193.0165 ;
			 LAYER M3 ;
			RECT 0.0098 192.9161 0.0481 193.0165 ;
			 LAYER V2 ;
			RECT 0.021 192.929 0.0359 192.9416 ;
		END

		ANTENNADIFFAREA 0.00194719 ;
		ANTENNAPARTIALMETALAREA 0.00195671 ;
	END Q[69]

	PIN Q[6]
		USE SIGNAL ;
		DIRECTION OUTPUT ;
		SHAPE ABUTMENT ;
		PORT
			 LAYER M2 ;
			RECT 0.0098 17.7318 0.0481 17.8322 ;
			 LAYER M3 ;
			RECT 0.0098 17.7318 0.0481 17.8322 ;
			 LAYER V2 ;
			RECT 0.021 17.8067 0.0359 17.8192 ;
		END

		ANTENNADIFFAREA 0.00194719 ;
		ANTENNAPARTIALMETALAREA 0.00195671 ;
	END Q[6]

	PIN Q[70]
		USE SIGNAL ;
		DIRECTION OUTPUT ;
		SHAPE ABUTMENT ;
		PORT
			 LAYER M2 ;
			RECT 0.0098 195.4761 0.0481 195.5765 ;
			 LAYER M3 ;
			RECT 0.0098 195.4761 0.0481 195.5765 ;
			 LAYER V2 ;
			RECT 0.021 195.489 0.0359 195.5016 ;
		END

		ANTENNADIFFAREA 0.00194719 ;
		ANTENNAPARTIALMETALAREA 0.00195671 ;
	END Q[70]

	PIN Q[71]
		USE SIGNAL ;
		DIRECTION OUTPUT ;
		SHAPE ABUTMENT ;
		PORT
			 LAYER M2 ;
			RECT 0.0098 198.0361 0.0481 198.1365 ;
			 LAYER M3 ;
			RECT 0.0098 198.0361 0.0481 198.1365 ;
			 LAYER V2 ;
			RECT 0.021 198.049 0.0359 198.0616 ;
		END

		ANTENNADIFFAREA 0.00194719 ;
		ANTENNAPARTIALMETALAREA 0.00195671 ;
	END Q[71]

	PIN Q[7]
		USE SIGNAL ;
		DIRECTION OUTPUT ;
		SHAPE ABUTMENT ;
		PORT
			 LAYER M2 ;
			RECT 0.0098 20.2918 0.0481 20.3922 ;
			 LAYER M3 ;
			RECT 0.0098 20.2918 0.0481 20.3922 ;
			 LAYER V2 ;
			RECT 0.021 20.3667 0.0359 20.3792 ;
		END

		ANTENNADIFFAREA 0.00194719 ;
		ANTENNAPARTIALMETALAREA 0.00195671 ;
	END Q[7]

	PIN Q[8]
		USE SIGNAL ;
		DIRECTION OUTPUT ;
		SHAPE ABUTMENT ;
		PORT
			 LAYER M2 ;
			RECT 0.0098 22.8518 0.0481 22.9522 ;
			 LAYER M3 ;
			RECT 0.0098 22.8518 0.0481 22.9522 ;
			 LAYER V2 ;
			RECT 0.021 22.9267 0.0359 22.9392 ;
		END

		ANTENNADIFFAREA 0.00194719 ;
		ANTENNAPARTIALMETALAREA 0.00195671 ;
	END Q[8]

	PIN Q[9]
		USE SIGNAL ;
		DIRECTION OUTPUT ;
		SHAPE ABUTMENT ;
		PORT
			 LAYER M2 ;
			RECT 0.0098 25.4118 0.0481 25.5122 ;
			 LAYER M3 ;
			RECT 0.0098 25.4118 0.0481 25.5122 ;
			 LAYER V2 ;
			RECT 0.021 25.4867 0.0359 25.4992 ;
		END

		ANTENNADIFFAREA 0.00194719 ;
		ANTENNAPARTIALMETALAREA 0.00195671 ;
	END Q[9]

	PIN RAWL
		USE SIGNAL ;
		DIRECTION INPUT ;
		SHAPE ABUTMENT ;
		PORT
			 LAYER M2 ;
			RECT 0.0714 101.578 0.1097 101.6157 ;
			 LAYER M3 ;
			RECT 0.0714 101.5153 0.1097 101.6157 ;
			 LAYER V2 ;
			RECT 0.0831 101.591 0.098 101.6035 ;
		END

		ANTENNAGATEAREA 0.00027817 ;
		ANTENNADIFFAREA 0.00194719 ;
		ANTENNAPARTIALMETALAREA 0.00195671 ;
	END RAWL

	PIN RAWLM[0]
		USE SIGNAL ;
		DIRECTION INPUT ;
		SHAPE ABUTMENT ;
		PORT
			 LAYER M2 ;
			RECT 0.0714 101.3522 0.1097 101.3898 ;
			 LAYER M3 ;
			RECT 0.0714 101.2894 0.1097 101.3898 ;
			 LAYER V2 ;
			RECT 0.0831 101.3651 0.098 101.3776 ;
		END

		ANTENNAGATEAREA 0.00027817 ;
		ANTENNADIFFAREA 0.00194719 ;
		ANTENNAPARTIALMETALAREA 0.00195671 ;
	END RAWLM[0]

	PIN RAWLM[1]
		USE SIGNAL ;
		DIRECTION INPUT ;
		SHAPE ABUTMENT ;
		PORT
			 LAYER M2 ;
			RECT 0.0098 100.7624 0.0481 100.8 ;
			 LAYER M3 ;
			RECT 0.0098 100.7624 0.0481 100.8627 ;
			 LAYER V2 ;
			RECT 0.0215 100.7753 0.0364 100.7878 ;
		END

		ANTENNAGATEAREA 0.00027817 ;
		ANTENNADIFFAREA 0.00194719 ;
		ANTENNAPARTIALMETALAREA 0.00195671 ;
	END RAWLM[1]

	PIN RET1N
		USE SIGNAL ;
		DIRECTION INPUT ;
		SHAPE ABUTMENT ;
		PORT
			 LAYER M2 ;
			RECT 0.0098 112.3576 0.0481 112.458 ;
			 LAYER M3 ;
			RECT 0.0098 112.3576 0.0481 112.458 ;
			 LAYER V2 ;
			RECT 0.021 112.4325 0.0359 112.4451 ;
		END

		ANTENNAGATEAREA 0.00027817 ;
		ANTENNADIFFAREA 0.00194719 ;
		ANTENNAPARTIALMETALAREA 0.00195671 ;
	END RET1N

	PIN SE
		USE SIGNAL ;
		DIRECTION INPUT ;
		SHAPE ABUTMENT ;
		PORT
			 LAYER M2 ;
			RECT 0.0098 109.7224 0.0481 109.8227 ;
			 LAYER M3 ;
			RECT 0.0098 109.7224 0.0481 109.8227 ;
			 LAYER V2 ;
			RECT 0.021 109.7973 0.0359 109.8098 ;
		END

		ANTENNAGATEAREA 0.00027817 ;
		ANTENNADIFFAREA 0.00194719 ;
		ANTENNAPARTIALMETALAREA 0.00195671 ;
	END SE

	PIN SI[0]
		USE SIGNAL ;
		DIRECTION INPUT ;
		SHAPE ABUTMENT ;
		PORT
			 LAYER M2 ;
			RECT 0.0714 0.0627 0.1097 0.1004 ;
			 LAYER M3 ;
			RECT 0.0714 0.0627 0.1097 0.1631 ;
			 LAYER V2 ;
			RECT 0.0831 0.0749 0.098 0.0875 ;
		END

		ANTENNAGATEAREA 0.00027817 ;
		ANTENNADIFFAREA 0.00194719 ;
		ANTENNAPARTIALMETALAREA 0.00195671 ;
	END SI[0]

	PIN SI[1]
		USE SIGNAL ;
		DIRECTION INPUT ;
		SHAPE ABUTMENT ;
		PORT
			 LAYER M2 ;
			RECT 0.0714 200.4078 0.1097 200.4455 ;
			 LAYER M3 ;
			RECT 0.0714 200.3451 0.1097 200.4455 ;
			 LAYER V2 ;
			RECT 0.0831 200.4208 0.098 200.4333 ;
		END

		ANTENNAGATEAREA 0.00027817 ;
		ANTENNADIFFAREA 0.00194719 ;
		ANTENNAPARTIALMETALAREA 0.00195671 ;
	END SI[1]

	PIN SO[0]
		USE SIGNAL ;
		DIRECTION OUTPUT ;
		SHAPE ABUTMENT ;
		PORT
			 LAYER M2 ;
			RECT 0.0098 100.0094 0.0481 100.0471 ;
			 LAYER M3 ;
			RECT 0.0098 99.9467 0.0481 100.0471 ;
			 LAYER V2 ;
			RECT 0.0215 100.0216 0.0364 100.0341 ;
		END

		ANTENNADIFFAREA 0.00194719 ;
		ANTENNAPARTIALMETALAREA 0.00195671 ;
	END SO[0]

	PIN SO[1]
		USE SIGNAL ;
		DIRECTION OUTPUT ;
		SHAPE ABUTMENT ;
		PORT
			 LAYER M2 ;
			RECT 0.0098 100.4612 0.0481 100.4988 ;
			 LAYER M3 ;
			RECT 0.0098 100.4612 0.0481 100.5616 ;
			 LAYER V2 ;
			RECT 0.0215 100.4741 0.0364 100.4867 ;
		END

		ANTENNADIFFAREA 0.00194719 ;
		ANTENNAPARTIALMETALAREA 0.00195671 ;
	END SO[1]

	PIN STOV
		USE SIGNAL ;
		DIRECTION INPUT ;
		SHAPE ABUTMENT ;
		PORT
			 LAYER M2 ;
			RECT 0.0714 111.5922 0.1097 111.6298 ;
			 LAYER M3 ;
			RECT 0.0714 111.5294 0.1097 111.6298 ;
			 LAYER V2 ;
			RECT 0.0831 111.6051 0.098 111.6176 ;
		END

		ANTENNAGATEAREA 0.00027817 ;
		ANTENNADIFFAREA 0.00194719 ;
		ANTENNAPARTIALMETALAREA 0.00195671 ;
	END STOV

	PIN TA[0]
		USE SIGNAL ;
		DIRECTION INPUT ;
		SHAPE ABUTMENT ;
		PORT
			 LAYER M2 ;
			RECT 0.0098 105.28 0.0481 105.3176 ;
			 LAYER M3 ;
			RECT 0.0098 105.28 0.0481 105.3804 ;
			 LAYER V2 ;
			RECT 0.0215 105.2929 0.0364 105.3055 ;
		END

		ANTENNAGATEAREA 0.00027817 ;
		ANTENNADIFFAREA 0.00194719 ;
		ANTENNAPARTIALMETALAREA 0.00195671 ;
	END TA[0]

	PIN TA[10]
		USE SIGNAL ;
		DIRECTION INPUT ;
		SHAPE ABUTMENT ;
		PORT
			 LAYER M2 ;
			RECT 0.0098 91.589 0.0481 91.6894 ;
			 LAYER M3 ;
			RECT 0.0098 91.589 0.0481 91.6894 ;
			 LAYER V2 ;
			RECT 0.021 91.6639 0.0359 91.6765 ;
		END

		ANTENNAGATEAREA 0.00027817 ;
		ANTENNADIFFAREA 0.00194719 ;
		ANTENNAPARTIALMETALAREA 0.00195671 ;
	END TA[10]

	PIN TA[11]
		USE SIGNAL ;
		DIRECTION INPUT ;
		SHAPE ABUTMENT ;
		PORT
			 LAYER M2 ;
			RECT 0.0098 93.6973 0.0481 93.7976 ;
			 LAYER M3 ;
			RECT 0.0098 93.6973 0.0481 93.7976 ;
			 LAYER V2 ;
			RECT 0.021 93.7722 0.0359 93.7847 ;
		END

		ANTENNAGATEAREA 0.00027817 ;
		ANTENNADIFFAREA 0.00194719 ;
		ANTENNAPARTIALMETALAREA 0.00195671 ;
	END TA[11]

	PIN TA[12]
		USE SIGNAL ;
		DIRECTION INPUT ;
		SHAPE ABUTMENT ;
		PORT
			 LAYER M2 ;
			RECT 0.0098 95.2031 0.0481 95.3035 ;
			 LAYER M3 ;
			RECT 0.0098 95.2031 0.0481 95.3035 ;
			 LAYER V2 ;
			RECT 0.021 95.278 0.0359 95.2906 ;
		END

		ANTENNAGATEAREA 0.00027817 ;
		ANTENNADIFFAREA 0.00194719 ;
		ANTENNAPARTIALMETALAREA 0.00195671 ;
	END TA[12]

	PIN TA[13]
		USE SIGNAL ;
		DIRECTION INPUT ;
		SHAPE ABUTMENT ;
		PORT
			 LAYER M2 ;
			RECT 0.0098 96.458 0.0481 96.5584 ;
			 LAYER M3 ;
			RECT 0.0098 96.458 0.0481 96.5584 ;
			 LAYER V2 ;
			RECT 0.021 96.5329 0.0359 96.5455 ;
		END

		ANTENNAGATEAREA 0.00027817 ;
		ANTENNADIFFAREA 0.00194719 ;
		ANTENNAPARTIALMETALAREA 0.00195671 ;
	END TA[13]

	PIN TA[1]
		USE SIGNAL ;
		DIRECTION INPUT ;
		SHAPE ABUTMENT ;
		PORT
			 LAYER M2 ;
			RECT 0.0098 103.8494 0.0481 103.9498 ;
			 LAYER M3 ;
			RECT 0.0098 103.8494 0.0481 103.9498 ;
			 LAYER V2 ;
			RECT 0.021 103.9243 0.0359 103.9369 ;
		END

		ANTENNAGATEAREA 0.00027817 ;
		ANTENNADIFFAREA 0.00194719 ;
		ANTENNAPARTIALMETALAREA 0.00195671 ;
	END TA[1]

	PIN TA[2]
		USE SIGNAL ;
		DIRECTION INPUT ;
		SHAPE ABUTMENT ;
		PORT
			 LAYER M2 ;
			RECT 0.0098 102.8706 0.0481 102.9082 ;
			 LAYER M3 ;
			RECT 0.0098 102.8706 0.0481 102.971 ;
			 LAYER V2 ;
			RECT 0.0215 102.8835 0.0364 102.8961 ;
		END

		ANTENNAGATEAREA 0.00027817 ;
		ANTENNADIFFAREA 0.00194719 ;
		ANTENNAPARTIALMETALAREA 0.00195671 ;
	END TA[2]

	PIN TA[3]
		USE SIGNAL ;
		DIRECTION INPUT ;
		SHAPE ABUTMENT ;
		PORT
			 LAYER M2 ;
			RECT 0.0714 101.1263 0.1097 101.1639 ;
			 LAYER M3 ;
			RECT 0.0714 101.0635 0.1097 101.1639 ;
			 LAYER V2 ;
			RECT 0.0831 101.1392 0.098 101.1518 ;
		END

		ANTENNAGATEAREA 0.00027817 ;
		ANTENNADIFFAREA 0.00194719 ;
		ANTENNAPARTIALMETALAREA 0.00195671 ;
	END TA[3]

	PIN TA[4]
		USE SIGNAL ;
		DIRECTION INPUT ;
		SHAPE ABUTMENT ;
		PORT
			 LAYER M2 ;
			RECT 0.0714 89.7067 0.1097 89.7443 ;
			 LAYER M3 ;
			RECT 0.0714 89.7067 0.1097 89.8071 ;
			 LAYER V2 ;
			RECT 0.0831 89.7188 0.098 89.7314 ;
		END

		ANTENNAGATEAREA 0.00027817 ;
		ANTENNADIFFAREA 0.00194719 ;
		ANTENNAPARTIALMETALAREA 0.00195671 ;
	END TA[4]

	PIN TA[5]
		USE SIGNAL ;
		DIRECTION INPUT ;
		SHAPE ABUTMENT ;
		PORT
			 LAYER M2 ;
			RECT 0.0098 99.3192 0.0481 99.4196 ;
			 LAYER M3 ;
			RECT 0.0098 99.3192 0.0481 99.4196 ;
			 LAYER V2 ;
			RECT 0.021 99.3941 0.0359 99.4067 ;
		END

		ANTENNAGATEAREA 0.00027817 ;
		ANTENNADIFFAREA 0.00194719 ;
		ANTENNAPARTIALMETALAREA 0.00195671 ;
	END TA[5]

	PIN TA[6]
		USE SIGNAL ;
		DIRECTION INPUT ;
		SHAPE ABUTMENT ;
		PORT
			 LAYER M2 ;
			RECT 0.0098 94.789 0.0481 94.8267 ;
			 LAYER M3 ;
			RECT 0.0098 94.7263 0.0481 94.8267 ;
			 LAYER V2 ;
			RECT 0.0215 94.8012 0.0364 94.8137 ;
		END

		ANTENNAGATEAREA 0.00027817 ;
		ANTENNADIFFAREA 0.00194719 ;
		ANTENNAPARTIALMETALAREA 0.00195671 ;
	END TA[6]

	PIN TA[7]
		USE SIGNAL ;
		DIRECTION INPUT ;
		SHAPE ABUTMENT ;
		PORT
			 LAYER M2 ;
			RECT 0.0098 95.8055 0.0481 95.9059 ;
			 LAYER M3 ;
			RECT 0.0098 95.8055 0.0481 95.9059 ;
			 LAYER V2 ;
			RECT 0.021 95.8804 0.0359 95.8929 ;
		END

		ANTENNAGATEAREA 0.00027817 ;
		ANTENNADIFFAREA 0.00194719 ;
		ANTENNAPARTIALMETALAREA 0.00195671 ;
	END TA[7]

	PIN TA[8]
		USE SIGNAL ;
		DIRECTION INPUT ;
		SHAPE ABUTMENT ;
		PORT
			 LAYER M2 ;
			RECT 0.0098 92.4549 0.0481 92.4925 ;
			 LAYER M3 ;
			RECT 0.0098 92.3922 0.0481 92.4925 ;
			 LAYER V2 ;
			RECT 0.0215 92.4671 0.0364 92.4796 ;
		END

		ANTENNAGATEAREA 0.00027817 ;
		ANTENNADIFFAREA 0.00194719 ;
		ANTENNAPARTIALMETALAREA 0.00195671 ;
	END TA[8]

	PIN TA[9]
		USE SIGNAL ;
		DIRECTION INPUT ;
		SHAPE ABUTMENT ;
		PORT
			 LAYER M2 ;
			RECT 0.0098 89.9451 0.0481 89.9827 ;
			 LAYER M3 ;
			RECT 0.0098 89.8824 0.0481 89.9827 ;
			 LAYER V2 ;
			RECT 0.0215 89.9573 0.0364 89.9698 ;
		END

		ANTENNAGATEAREA 0.00027817 ;
		ANTENNADIFFAREA 0.00194719 ;
		ANTENNAPARTIALMETALAREA 0.00195671 ;
	END TA[9]

	PIN TCEN
		USE SIGNAL ;
		DIRECTION INPUT ;
		SHAPE ABUTMENT ;
		PORT
			 LAYER M2 ;
			RECT 0.0714 105.6439 0.1097 105.6816 ;
			 LAYER M3 ;
			RECT 0.0714 105.5812 0.1097 105.6816 ;
			 LAYER V2 ;
			RECT 0.0831 105.6569 0.098 105.6694 ;
		END

		ANTENNAGATEAREA 0.00027817 ;
		ANTENNADIFFAREA 0.00194719 ;
		ANTENNAPARTIALMETALAREA 0.00195671 ;
	END TCEN

	PIN TD[0]
		USE SIGNAL ;
		DIRECTION INPUT ;
		SHAPE ABUTMENT ;
		PORT
			 LAYER M2 ;
			RECT 0.0098 2.2463 0.0481 2.2839 ;
			 LAYER M3 ;
			RECT 0.0098 2.2463 0.0481 2.3467 ;
			 LAYER V2 ;
			RECT 0.0215 2.2592 0.0364 2.2718 ;
		END

		ANTENNAGATEAREA 0.00027817 ;
		ANTENNADIFFAREA 0.00194719 ;
		ANTENNAPARTIALMETALAREA 0.00195671 ;
	END TD[0]

	PIN TD[10]
		USE SIGNAL ;
		DIRECTION INPUT ;
		SHAPE ABUTMENT ;
		PORT
			 LAYER M2 ;
			RECT 0.0098 27.8463 0.0481 27.8839 ;
			 LAYER M3 ;
			RECT 0.0098 27.8463 0.0481 27.9467 ;
			 LAYER V2 ;
			RECT 0.0215 27.8592 0.0364 27.8718 ;
		END

		ANTENNAGATEAREA 0.00027817 ;
		ANTENNADIFFAREA 0.00194719 ;
		ANTENNAPARTIALMETALAREA 0.00195671 ;
	END TD[10]

	PIN TD[11]
		USE SIGNAL ;
		DIRECTION INPUT ;
		SHAPE ABUTMENT ;
		PORT
			 LAYER M2 ;
			RECT 0.0098 30.4063 0.0481 30.4439 ;
			 LAYER M3 ;
			RECT 0.0098 30.4063 0.0481 30.5067 ;
			 LAYER V2 ;
			RECT 0.0215 30.4192 0.0364 30.4318 ;
		END

		ANTENNAGATEAREA 0.00027817 ;
		ANTENNADIFFAREA 0.00194719 ;
		ANTENNAPARTIALMETALAREA 0.00195671 ;
	END TD[11]

	PIN TD[12]
		USE SIGNAL ;
		DIRECTION INPUT ;
		SHAPE ABUTMENT ;
		PORT
			 LAYER M2 ;
			RECT 0.0098 32.9663 0.0481 33.0039 ;
			 LAYER M3 ;
			RECT 0.0098 32.9663 0.0481 33.0667 ;
			 LAYER V2 ;
			RECT 0.0215 32.9792 0.0364 32.9918 ;
		END

		ANTENNAGATEAREA 0.00027817 ;
		ANTENNADIFFAREA 0.00194719 ;
		ANTENNAPARTIALMETALAREA 0.00195671 ;
	END TD[12]

	PIN TD[13]
		USE SIGNAL ;
		DIRECTION INPUT ;
		SHAPE ABUTMENT ;
		PORT
			 LAYER M2 ;
			RECT 0.0098 35.5263 0.0481 35.5639 ;
			 LAYER M3 ;
			RECT 0.0098 35.5263 0.0481 35.6267 ;
			 LAYER V2 ;
			RECT 0.0215 35.5392 0.0364 35.5518 ;
		END

		ANTENNAGATEAREA 0.00027817 ;
		ANTENNADIFFAREA 0.00194719 ;
		ANTENNAPARTIALMETALAREA 0.00195671 ;
	END TD[13]

	PIN TD[14]
		USE SIGNAL ;
		DIRECTION INPUT ;
		SHAPE ABUTMENT ;
		PORT
			 LAYER M2 ;
			RECT 0.0098 38.0863 0.0481 38.1239 ;
			 LAYER M3 ;
			RECT 0.0098 38.0863 0.0481 38.1867 ;
			 LAYER V2 ;
			RECT 0.0215 38.0992 0.0364 38.1118 ;
		END

		ANTENNAGATEAREA 0.00027817 ;
		ANTENNADIFFAREA 0.00194719 ;
		ANTENNAPARTIALMETALAREA 0.00195671 ;
	END TD[14]

	PIN TD[15]
		USE SIGNAL ;
		DIRECTION INPUT ;
		SHAPE ABUTMENT ;
		PORT
			 LAYER M2 ;
			RECT 0.0098 40.6463 0.0481 40.6839 ;
			 LAYER M3 ;
			RECT 0.0098 40.6463 0.0481 40.7467 ;
			 LAYER V2 ;
			RECT 0.0215 40.6592 0.0364 40.6718 ;
		END

		ANTENNAGATEAREA 0.00027817 ;
		ANTENNADIFFAREA 0.00194719 ;
		ANTENNAPARTIALMETALAREA 0.00195671 ;
	END TD[15]

	PIN TD[16]
		USE SIGNAL ;
		DIRECTION INPUT ;
		SHAPE ABUTMENT ;
		PORT
			 LAYER M2 ;
			RECT 0.0098 43.2063 0.0481 43.2439 ;
			 LAYER M3 ;
			RECT 0.0098 43.2063 0.0481 43.3067 ;
			 LAYER V2 ;
			RECT 0.0215 43.2192 0.0364 43.2318 ;
		END

		ANTENNAGATEAREA 0.00027817 ;
		ANTENNADIFFAREA 0.00194719 ;
		ANTENNAPARTIALMETALAREA 0.00195671 ;
	END TD[16]

	PIN TD[17]
		USE SIGNAL ;
		DIRECTION INPUT ;
		SHAPE ABUTMENT ;
		PORT
			 LAYER M2 ;
			RECT 0.0098 45.7663 0.0481 45.8039 ;
			 LAYER M3 ;
			RECT 0.0098 45.7663 0.0481 45.8667 ;
			 LAYER V2 ;
			RECT 0.0215 45.7792 0.0364 45.7918 ;
		END

		ANTENNAGATEAREA 0.00027817 ;
		ANTENNADIFFAREA 0.00194719 ;
		ANTENNAPARTIALMETALAREA 0.00195671 ;
	END TD[17]

	PIN TD[18]
		USE SIGNAL ;
		DIRECTION INPUT ;
		SHAPE ABUTMENT ;
		PORT
			 LAYER M2 ;
			RECT 0.0098 56.0251 0.0481 56.0627 ;
			 LAYER M3 ;
			RECT 0.0098 56.0251 0.0481 56.1255 ;
			 LAYER V2 ;
			RECT 0.0215 56.038 0.0364 56.0506 ;
		END

		ANTENNAGATEAREA 0.00027817 ;
		ANTENNADIFFAREA 0.00194719 ;
		ANTENNAPARTIALMETALAREA 0.00195671 ;
	END TD[18]

	PIN TD[19]
		USE SIGNAL ;
		DIRECTION INPUT ;
		SHAPE ABUTMENT ;
		PORT
			 LAYER M2 ;
			RECT 0.0098 58.5851 0.0481 58.6227 ;
			 LAYER M3 ;
			RECT 0.0098 58.5851 0.0481 58.6855 ;
			 LAYER V2 ;
			RECT 0.0215 58.598 0.0364 58.6106 ;
		END

		ANTENNAGATEAREA 0.00027817 ;
		ANTENNADIFFAREA 0.00194719 ;
		ANTENNAPARTIALMETALAREA 0.00195671 ;
	END TD[19]

	PIN TD[1]
		USE SIGNAL ;
		DIRECTION INPUT ;
		SHAPE ABUTMENT ;
		PORT
			 LAYER M2 ;
			RECT 0.0098 4.8063 0.0481 4.8439 ;
			 LAYER M3 ;
			RECT 0.0098 4.8063 0.0481 4.9067 ;
			 LAYER V2 ;
			RECT 0.0215 4.8192 0.0364 4.8318 ;
		END

		ANTENNAGATEAREA 0.00027817 ;
		ANTENNADIFFAREA 0.00194719 ;
		ANTENNAPARTIALMETALAREA 0.00195671 ;
	END TD[1]

	PIN TD[20]
		USE SIGNAL ;
		DIRECTION INPUT ;
		SHAPE ABUTMENT ;
		PORT
			 LAYER M2 ;
			RECT 0.0098 61.1451 0.0481 61.1827 ;
			 LAYER M3 ;
			RECT 0.0098 61.1451 0.0481 61.2455 ;
			 LAYER V2 ;
			RECT 0.0215 61.158 0.0364 61.1706 ;
		END

		ANTENNAGATEAREA 0.00027817 ;
		ANTENNADIFFAREA 0.00194719 ;
		ANTENNAPARTIALMETALAREA 0.00195671 ;
	END TD[20]

	PIN TD[21]
		USE SIGNAL ;
		DIRECTION INPUT ;
		SHAPE ABUTMENT ;
		PORT
			 LAYER M2 ;
			RECT 0.0098 63.7051 0.0481 63.7427 ;
			 LAYER M3 ;
			RECT 0.0098 63.7051 0.0481 63.8055 ;
			 LAYER V2 ;
			RECT 0.0215 63.718 0.0364 63.7306 ;
		END

		ANTENNAGATEAREA 0.00027817 ;
		ANTENNADIFFAREA 0.00194719 ;
		ANTENNAPARTIALMETALAREA 0.00195671 ;
	END TD[21]

	PIN TD[22]
		USE SIGNAL ;
		DIRECTION INPUT ;
		SHAPE ABUTMENT ;
		PORT
			 LAYER M2 ;
			RECT 0.0098 66.2651 0.0481 66.3027 ;
			 LAYER M3 ;
			RECT 0.0098 66.2651 0.0481 66.3655 ;
			 LAYER V2 ;
			RECT 0.0215 66.278 0.0364 66.2906 ;
		END

		ANTENNAGATEAREA 0.00027817 ;
		ANTENNADIFFAREA 0.00194719 ;
		ANTENNAPARTIALMETALAREA 0.00195671 ;
	END TD[22]

	PIN TD[23]
		USE SIGNAL ;
		DIRECTION INPUT ;
		SHAPE ABUTMENT ;
		PORT
			 LAYER M2 ;
			RECT 0.0098 68.8251 0.0481 68.8627 ;
			 LAYER M3 ;
			RECT 0.0098 68.8251 0.0481 68.9255 ;
			 LAYER V2 ;
			RECT 0.0215 68.838 0.0364 68.8506 ;
		END

		ANTENNAGATEAREA 0.00027817 ;
		ANTENNADIFFAREA 0.00194719 ;
		ANTENNAPARTIALMETALAREA 0.00195671 ;
	END TD[23]

	PIN TD[24]
		USE SIGNAL ;
		DIRECTION INPUT ;
		SHAPE ABUTMENT ;
		PORT
			 LAYER M2 ;
			RECT 0.0098 71.3851 0.0481 71.4227 ;
			 LAYER M3 ;
			RECT 0.0098 71.3851 0.0481 71.4855 ;
			 LAYER V2 ;
			RECT 0.0215 71.398 0.0364 71.4106 ;
		END

		ANTENNAGATEAREA 0.00027817 ;
		ANTENNADIFFAREA 0.00194719 ;
		ANTENNAPARTIALMETALAREA 0.00195671 ;
	END TD[24]

	PIN TD[25]
		USE SIGNAL ;
		DIRECTION INPUT ;
		SHAPE ABUTMENT ;
		PORT
			 LAYER M2 ;
			RECT 0.0098 73.9451 0.0481 73.9827 ;
			 LAYER M3 ;
			RECT 0.0098 73.9451 0.0481 74.0455 ;
			 LAYER V2 ;
			RECT 0.0215 73.958 0.0364 73.9706 ;
		END

		ANTENNAGATEAREA 0.00027817 ;
		ANTENNADIFFAREA 0.00194719 ;
		ANTENNAPARTIALMETALAREA 0.00195671 ;
	END TD[25]

	PIN TD[26]
		USE SIGNAL ;
		DIRECTION INPUT ;
		SHAPE ABUTMENT ;
		PORT
			 LAYER M2 ;
			RECT 0.0098 76.5051 0.0481 76.5427 ;
			 LAYER M3 ;
			RECT 0.0098 76.5051 0.0481 76.6055 ;
			 LAYER V2 ;
			RECT 0.0215 76.518 0.0364 76.5306 ;
		END

		ANTENNAGATEAREA 0.00027817 ;
		ANTENNADIFFAREA 0.00194719 ;
		ANTENNAPARTIALMETALAREA 0.00195671 ;
	END TD[26]

	PIN TD[27]
		USE SIGNAL ;
		DIRECTION INPUT ;
		SHAPE ABUTMENT ;
		PORT
			 LAYER M2 ;
			RECT 0.0098 79.0651 0.0481 79.1027 ;
			 LAYER M3 ;
			RECT 0.0098 79.0651 0.0481 79.1655 ;
			 LAYER V2 ;
			RECT 0.0215 79.078 0.0364 79.0906 ;
		END

		ANTENNAGATEAREA 0.00027817 ;
		ANTENNADIFFAREA 0.00194719 ;
		ANTENNAPARTIALMETALAREA 0.00195671 ;
	END TD[27]

	PIN TD[28]
		USE SIGNAL ;
		DIRECTION INPUT ;
		SHAPE ABUTMENT ;
		PORT
			 LAYER M2 ;
			RECT 0.0098 81.6251 0.0481 81.6627 ;
			 LAYER M3 ;
			RECT 0.0098 81.6251 0.0481 81.7255 ;
			 LAYER V2 ;
			RECT 0.0215 81.638 0.0364 81.6506 ;
		END

		ANTENNAGATEAREA 0.00027817 ;
		ANTENNADIFFAREA 0.00194719 ;
		ANTENNAPARTIALMETALAREA 0.00195671 ;
	END TD[28]

	PIN TD[29]
		USE SIGNAL ;
		DIRECTION INPUT ;
		SHAPE ABUTMENT ;
		PORT
			 LAYER M2 ;
			RECT 0.0098 84.1851 0.0481 84.2227 ;
			 LAYER M3 ;
			RECT 0.0098 84.1851 0.0481 84.2855 ;
			 LAYER V2 ;
			RECT 0.0215 84.198 0.0364 84.2106 ;
		END

		ANTENNAGATEAREA 0.00027817 ;
		ANTENNADIFFAREA 0.00194719 ;
		ANTENNAPARTIALMETALAREA 0.00195671 ;
	END TD[29]

	PIN TD[2]
		USE SIGNAL ;
		DIRECTION INPUT ;
		SHAPE ABUTMENT ;
		PORT
			 LAYER M2 ;
			RECT 0.0098 7.3663 0.0481 7.4039 ;
			 LAYER M3 ;
			RECT 0.0098 7.3663 0.0481 7.4667 ;
			 LAYER V2 ;
			RECT 0.0215 7.3792 0.0364 7.3918 ;
		END

		ANTENNAGATEAREA 0.00027817 ;
		ANTENNADIFFAREA 0.00194719 ;
		ANTENNAPARTIALMETALAREA 0.00195671 ;
	END TD[2]

	PIN TD[30]
		USE SIGNAL ;
		DIRECTION INPUT ;
		SHAPE ABUTMENT ;
		PORT
			 LAYER M2 ;
			RECT 0.0098 86.7451 0.0481 86.7827 ;
			 LAYER M3 ;
			RECT 0.0098 86.7451 0.0481 86.8455 ;
			 LAYER V2 ;
			RECT 0.0215 86.758 0.0364 86.7706 ;
		END

		ANTENNAGATEAREA 0.00027817 ;
		ANTENNADIFFAREA 0.00194719 ;
		ANTENNAPARTIALMETALAREA 0.00195671 ;
	END TD[30]

	PIN TD[31]
		USE SIGNAL ;
		DIRECTION INPUT ;
		SHAPE ABUTMENT ;
		PORT
			 LAYER M2 ;
			RECT 0.0098 89.7694 0.0481 89.8071 ;
			 LAYER M3 ;
			RECT 0.0098 89.7067 0.0481 89.8071 ;
			 LAYER V2 ;
			RECT 0.0215 89.7816 0.0364 89.7941 ;
		END

		ANTENNAGATEAREA 0.00027817 ;
		ANTENNADIFFAREA 0.00194719 ;
		ANTENNAPARTIALMETALAREA 0.00195671 ;
	END TD[31]

	PIN TD[32]
		USE SIGNAL ;
		DIRECTION INPUT ;
		SHAPE ABUTMENT ;
		PORT
			 LAYER M2 ;
			RECT 0.0098 92.2792 0.0481 92.3169 ;
			 LAYER M3 ;
			RECT 0.0098 92.2165 0.0481 92.3169 ;
			 LAYER V2 ;
			RECT 0.0215 92.2914 0.0364 92.3039 ;
		END

		ANTENNAGATEAREA 0.00027817 ;
		ANTENNADIFFAREA 0.00194719 ;
		ANTENNAPARTIALMETALAREA 0.00195671 ;
	END TD[32]

	PIN TD[33]
		USE SIGNAL ;
		DIRECTION INPUT ;
		SHAPE ABUTMENT ;
		PORT
			 LAYER M2 ;
			RECT 0.0714 94.902 0.1097 94.9396 ;
			 LAYER M3 ;
			RECT 0.0714 94.902 0.1097 95.0024 ;
			 LAYER V2 ;
			RECT 0.0831 94.9141 0.098 94.9267 ;
		END

		ANTENNAGATEAREA 0.00027817 ;
		ANTENNADIFFAREA 0.00194719 ;
		ANTENNAPARTIALMETALAREA 0.00195671 ;
	END TD[33]

	PIN TD[34]
		USE SIGNAL ;
		DIRECTION INPUT ;
		SHAPE ABUTMENT ;
		PORT
			 LAYER M2 ;
			RECT 0.0714 97.3867 0.1097 97.4243 ;
			 LAYER M3 ;
			RECT 0.0714 97.3867 0.1097 97.4871 ;
			 LAYER V2 ;
			RECT 0.0831 97.3988 0.098 97.4114 ;
		END

		ANTENNAGATEAREA 0.00027817 ;
		ANTENNADIFFAREA 0.00194719 ;
		ANTENNAPARTIALMETALAREA 0.00195671 ;
	END TD[34]

	PIN TD[35]
		USE SIGNAL ;
		DIRECTION INPUT ;
		SHAPE ABUTMENT ;
		PORT
			 LAYER M2 ;
			RECT 0.0714 99.9467 0.1097 99.9843 ;
			 LAYER M3 ;
			RECT 0.0714 99.9467 0.1097 100.0471 ;
			 LAYER V2 ;
			RECT 0.0831 99.9588 0.098 99.9714 ;
		END

		ANTENNAGATEAREA 0.00027817 ;
		ANTENNADIFFAREA 0.00194719 ;
		ANTENNAPARTIALMETALAREA 0.00195671 ;
	END TD[35]

	PIN TD[36]
		USE SIGNAL ;
		DIRECTION INPUT ;
		SHAPE ABUTMENT ;
		PORT
			 LAYER M2 ;
			RECT 0.0714 100.5239 0.1097 100.5616 ;
			 LAYER M3 ;
			RECT 0.0714 100.4612 0.1097 100.5616 ;
			 LAYER V2 ;
			RECT 0.0831 100.5369 0.098 100.5494 ;
		END

		ANTENNAGATEAREA 0.00027817 ;
		ANTENNADIFFAREA 0.00194719 ;
		ANTENNAPARTIALMETALAREA 0.00195671 ;
	END TD[36]

	PIN TD[37]
		USE SIGNAL ;
		DIRECTION INPUT ;
		SHAPE ABUTMENT ;
		PORT
			 LAYER M2 ;
			RECT 0.0714 103.0839 0.1097 103.1216 ;
			 LAYER M3 ;
			RECT 0.0714 103.0212 0.1097 103.1216 ;
			 LAYER V2 ;
			RECT 0.0831 103.0969 0.098 103.1094 ;
		END

		ANTENNAGATEAREA 0.00027817 ;
		ANTENNADIFFAREA 0.00194719 ;
		ANTENNAPARTIALMETALAREA 0.00195671 ;
	END TD[37]

	PIN TD[38]
		USE SIGNAL ;
		DIRECTION INPUT ;
		SHAPE ABUTMENT ;
		PORT
			 LAYER M2 ;
			RECT 0.0098 105.5812 0.0481 105.6188 ;
			 LAYER M3 ;
			RECT 0.0098 105.5812 0.0481 105.6816 ;
			 LAYER V2 ;
			RECT 0.0215 105.5941 0.0364 105.6067 ;
		END

		ANTENNAGATEAREA 0.00027817 ;
		ANTENNADIFFAREA 0.00194719 ;
		ANTENNAPARTIALMETALAREA 0.00195671 ;
	END TD[38]

	PIN TD[39]
		USE SIGNAL ;
		DIRECTION INPUT ;
		SHAPE ABUTMENT ;
		PORT
			 LAYER M2 ;
			RECT 0.0098 108.2165 0.0481 108.2541 ;
			 LAYER M3 ;
			RECT 0.0098 108.2165 0.0481 108.3169 ;
			 LAYER V2 ;
			RECT 0.0215 108.2294 0.0364 108.242 ;
		END

		ANTENNAGATEAREA 0.00027817 ;
		ANTENNADIFFAREA 0.00194719 ;
		ANTENNAPARTIALMETALAREA 0.00195671 ;
	END TD[39]

	PIN TD[3]
		USE SIGNAL ;
		DIRECTION INPUT ;
		SHAPE ABUTMENT ;
		PORT
			 LAYER M2 ;
			RECT 0.0098 9.9263 0.0481 9.9639 ;
			 LAYER M3 ;
			RECT 0.0098 9.9263 0.0481 10.0267 ;
			 LAYER V2 ;
			RECT 0.0215 9.9392 0.0364 9.9518 ;
		END

		ANTENNAGATEAREA 0.00027817 ;
		ANTENNADIFFAREA 0.00194719 ;
		ANTENNAPARTIALMETALAREA 0.00195671 ;
	END TD[3]

	PIN TD[40]
		USE SIGNAL ;
		DIRECTION INPUT ;
		SHAPE ABUTMENT ;
		PORT
			 LAYER M2 ;
			RECT 0.0098 110.6259 0.0481 110.7263 ;
			 LAYER M3 ;
			RECT 0.0098 110.6259 0.0481 110.7263 ;
			 LAYER V2 ;
			RECT 0.021 110.7008 0.0359 110.7133 ;
		END

		ANTENNAGATEAREA 0.00027817 ;
		ANTENNADIFFAREA 0.00194719 ;
		ANTENNAPARTIALMETALAREA 0.00195671 ;
	END TD[40]

	PIN TD[41]
		USE SIGNAL ;
		DIRECTION INPUT ;
		SHAPE ABUTMENT ;
		PORT
			 LAYER M2 ;
			RECT 0.0098 113.7255 0.0481 113.7631 ;
			 LAYER M3 ;
			RECT 0.0098 113.6627 0.0481 113.7631 ;
			 LAYER V2 ;
			RECT 0.0215 113.7376 0.0364 113.7502 ;
		END

		ANTENNAGATEAREA 0.00027817 ;
		ANTENNADIFFAREA 0.00194719 ;
		ANTENNAPARTIALMETALAREA 0.00195671 ;
	END TD[41]

	PIN TD[42]
		USE SIGNAL ;
		DIRECTION INPUT ;
		SHAPE ABUTMENT ;
		PORT
			 LAYER M2 ;
			RECT 0.0098 116.2855 0.0481 116.3231 ;
			 LAYER M3 ;
			RECT 0.0098 116.2227 0.0481 116.3231 ;
			 LAYER V2 ;
			RECT 0.0215 116.2976 0.0364 116.3102 ;
		END

		ANTENNAGATEAREA 0.00027817 ;
		ANTENNADIFFAREA 0.00194719 ;
		ANTENNAPARTIALMETALAREA 0.00195671 ;
	END TD[42]

	PIN TD[43]
		USE SIGNAL ;
		DIRECTION INPUT ;
		SHAPE ABUTMENT ;
		PORT
			 LAYER M2 ;
			RECT 0.0098 118.8455 0.0481 118.8831 ;
			 LAYER M3 ;
			RECT 0.0098 118.7827 0.0481 118.8831 ;
			 LAYER V2 ;
			RECT 0.0215 118.8576 0.0364 118.8702 ;
		END

		ANTENNAGATEAREA 0.00027817 ;
		ANTENNADIFFAREA 0.00194719 ;
		ANTENNAPARTIALMETALAREA 0.00195671 ;
	END TD[43]

	PIN TD[44]
		USE SIGNAL ;
		DIRECTION INPUT ;
		SHAPE ABUTMENT ;
		PORT
			 LAYER M2 ;
			RECT 0.0098 121.4055 0.0481 121.4431 ;
			 LAYER M3 ;
			RECT 0.0098 121.3427 0.0481 121.4431 ;
			 LAYER V2 ;
			RECT 0.0215 121.4176 0.0364 121.4302 ;
		END

		ANTENNAGATEAREA 0.00027817 ;
		ANTENNADIFFAREA 0.00194719 ;
		ANTENNAPARTIALMETALAREA 0.00195671 ;
	END TD[44]

	PIN TD[45]
		USE SIGNAL ;
		DIRECTION INPUT ;
		SHAPE ABUTMENT ;
		PORT
			 LAYER M2 ;
			RECT 0.0098 123.9655 0.0481 124.0031 ;
			 LAYER M3 ;
			RECT 0.0098 123.9027 0.0481 124.0031 ;
			 LAYER V2 ;
			RECT 0.0215 123.9776 0.0364 123.9902 ;
		END

		ANTENNAGATEAREA 0.00027817 ;
		ANTENNADIFFAREA 0.00194719 ;
		ANTENNAPARTIALMETALAREA 0.00195671 ;
	END TD[45]

	PIN TD[46]
		USE SIGNAL ;
		DIRECTION INPUT ;
		SHAPE ABUTMENT ;
		PORT
			 LAYER M2 ;
			RECT 0.0098 126.5255 0.0481 126.5631 ;
			 LAYER M3 ;
			RECT 0.0098 126.4627 0.0481 126.5631 ;
			 LAYER V2 ;
			RECT 0.0215 126.5376 0.0364 126.5502 ;
		END

		ANTENNAGATEAREA 0.00027817 ;
		ANTENNADIFFAREA 0.00194719 ;
		ANTENNAPARTIALMETALAREA 0.00195671 ;
	END TD[46]

	PIN TD[47]
		USE SIGNAL ;
		DIRECTION INPUT ;
		SHAPE ABUTMENT ;
		PORT
			 LAYER M2 ;
			RECT 0.0098 129.0855 0.0481 129.1231 ;
			 LAYER M3 ;
			RECT 0.0098 129.0227 0.0481 129.1231 ;
			 LAYER V2 ;
			RECT 0.0215 129.0976 0.0364 129.1102 ;
		END

		ANTENNAGATEAREA 0.00027817 ;
		ANTENNADIFFAREA 0.00194719 ;
		ANTENNAPARTIALMETALAREA 0.00195671 ;
	END TD[47]

	PIN TD[48]
		USE SIGNAL ;
		DIRECTION INPUT ;
		SHAPE ABUTMENT ;
		PORT
			 LAYER M2 ;
			RECT 0.0098 131.6455 0.0481 131.6831 ;
			 LAYER M3 ;
			RECT 0.0098 131.5827 0.0481 131.6831 ;
			 LAYER V2 ;
			RECT 0.0215 131.6576 0.0364 131.6702 ;
		END

		ANTENNAGATEAREA 0.00027817 ;
		ANTENNADIFFAREA 0.00194719 ;
		ANTENNAPARTIALMETALAREA 0.00195671 ;
	END TD[48]

	PIN TD[49]
		USE SIGNAL ;
		DIRECTION INPUT ;
		SHAPE ABUTMENT ;
		PORT
			 LAYER M2 ;
			RECT 0.0098 134.2055 0.0481 134.2431 ;
			 LAYER M3 ;
			RECT 0.0098 134.1427 0.0481 134.2431 ;
			 LAYER V2 ;
			RECT 0.0215 134.2176 0.0364 134.2302 ;
		END

		ANTENNAGATEAREA 0.00027817 ;
		ANTENNADIFFAREA 0.00194719 ;
		ANTENNAPARTIALMETALAREA 0.00195671 ;
	END TD[49]

	PIN TD[4]
		USE SIGNAL ;
		DIRECTION INPUT ;
		SHAPE ABUTMENT ;
		PORT
			 LAYER M2 ;
			RECT 0.0098 12.4863 0.0481 12.5239 ;
			 LAYER M3 ;
			RECT 0.0098 12.4863 0.0481 12.5867 ;
			 LAYER V2 ;
			RECT 0.0215 12.4992 0.0364 12.5118 ;
		END

		ANTENNAGATEAREA 0.00027817 ;
		ANTENNADIFFAREA 0.00194719 ;
		ANTENNAPARTIALMETALAREA 0.00195671 ;
	END TD[4]

	PIN TD[50]
		USE SIGNAL ;
		DIRECTION INPUT ;
		SHAPE ABUTMENT ;
		PORT
			 LAYER M2 ;
			RECT 0.0098 136.7655 0.0481 136.8031 ;
			 LAYER M3 ;
			RECT 0.0098 136.7027 0.0481 136.8031 ;
			 LAYER V2 ;
			RECT 0.0215 136.7776 0.0364 136.7902 ;
		END

		ANTENNAGATEAREA 0.00027817 ;
		ANTENNADIFFAREA 0.00194719 ;
		ANTENNAPARTIALMETALAREA 0.00195671 ;
	END TD[50]

	PIN TD[51]
		USE SIGNAL ;
		DIRECTION INPUT ;
		SHAPE ABUTMENT ;
		PORT
			 LAYER M2 ;
			RECT 0.0098 139.3255 0.0481 139.3631 ;
			 LAYER M3 ;
			RECT 0.0098 139.2627 0.0481 139.3631 ;
			 LAYER V2 ;
			RECT 0.0215 139.3376 0.0364 139.3502 ;
		END

		ANTENNAGATEAREA 0.00027817 ;
		ANTENNADIFFAREA 0.00194719 ;
		ANTENNAPARTIALMETALAREA 0.00195671 ;
	END TD[51]

	PIN TD[52]
		USE SIGNAL ;
		DIRECTION INPUT ;
		SHAPE ABUTMENT ;
		PORT
			 LAYER M2 ;
			RECT 0.0098 141.8855 0.0481 141.9231 ;
			 LAYER M3 ;
			RECT 0.0098 141.8227 0.0481 141.9231 ;
			 LAYER V2 ;
			RECT 0.0215 141.8976 0.0364 141.9102 ;
		END

		ANTENNAGATEAREA 0.00027817 ;
		ANTENNADIFFAREA 0.00194719 ;
		ANTENNAPARTIALMETALAREA 0.00195671 ;
	END TD[52]

	PIN TD[53]
		USE SIGNAL ;
		DIRECTION INPUT ;
		SHAPE ABUTMENT ;
		PORT
			 LAYER M2 ;
			RECT 0.0098 144.4455 0.0481 144.4831 ;
			 LAYER M3 ;
			RECT 0.0098 144.3827 0.0481 144.4831 ;
			 LAYER V2 ;
			RECT 0.0215 144.4576 0.0364 144.4702 ;
		END

		ANTENNAGATEAREA 0.00027817 ;
		ANTENNADIFFAREA 0.00194719 ;
		ANTENNAPARTIALMETALAREA 0.00195671 ;
	END TD[53]

	PIN TD[54]
		USE SIGNAL ;
		DIRECTION INPUT ;
		SHAPE ABUTMENT ;
		PORT
			 LAYER M2 ;
			RECT 0.0098 154.7043 0.0481 154.742 ;
			 LAYER M3 ;
			RECT 0.0098 154.6416 0.0481 154.742 ;
			 LAYER V2 ;
			RECT 0.0215 154.7165 0.0364 154.729 ;
		END

		ANTENNAGATEAREA 0.00027817 ;
		ANTENNADIFFAREA 0.00194719 ;
		ANTENNAPARTIALMETALAREA 0.00195671 ;
	END TD[54]

	PIN TD[55]
		USE SIGNAL ;
		DIRECTION INPUT ;
		SHAPE ABUTMENT ;
		PORT
			 LAYER M2 ;
			RECT 0.0098 157.2643 0.0481 157.302 ;
			 LAYER M3 ;
			RECT 0.0098 157.2016 0.0481 157.302 ;
			 LAYER V2 ;
			RECT 0.0215 157.2765 0.0364 157.289 ;
		END

		ANTENNAGATEAREA 0.00027817 ;
		ANTENNADIFFAREA 0.00194719 ;
		ANTENNAPARTIALMETALAREA 0.00195671 ;
	END TD[55]

	PIN TD[56]
		USE SIGNAL ;
		DIRECTION INPUT ;
		SHAPE ABUTMENT ;
		PORT
			 LAYER M2 ;
			RECT 0.0098 159.8243 0.0481 159.862 ;
			 LAYER M3 ;
			RECT 0.0098 159.7616 0.0481 159.862 ;
			 LAYER V2 ;
			RECT 0.0215 159.8365 0.0364 159.849 ;
		END

		ANTENNAGATEAREA 0.00027817 ;
		ANTENNADIFFAREA 0.00194719 ;
		ANTENNAPARTIALMETALAREA 0.00195671 ;
	END TD[56]

	PIN TD[57]
		USE SIGNAL ;
		DIRECTION INPUT ;
		SHAPE ABUTMENT ;
		PORT
			 LAYER M2 ;
			RECT 0.0098 162.3843 0.0481 162.422 ;
			 LAYER M3 ;
			RECT 0.0098 162.3216 0.0481 162.422 ;
			 LAYER V2 ;
			RECT 0.0215 162.3965 0.0364 162.409 ;
		END

		ANTENNAGATEAREA 0.00027817 ;
		ANTENNADIFFAREA 0.00194719 ;
		ANTENNAPARTIALMETALAREA 0.00195671 ;
	END TD[57]

	PIN TD[58]
		USE SIGNAL ;
		DIRECTION INPUT ;
		SHAPE ABUTMENT ;
		PORT
			 LAYER M2 ;
			RECT 0.0098 164.9443 0.0481 164.982 ;
			 LAYER M3 ;
			RECT 0.0098 164.8816 0.0481 164.982 ;
			 LAYER V2 ;
			RECT 0.0215 164.9565 0.0364 164.969 ;
		END

		ANTENNAGATEAREA 0.00027817 ;
		ANTENNADIFFAREA 0.00194719 ;
		ANTENNAPARTIALMETALAREA 0.00195671 ;
	END TD[58]

	PIN TD[59]
		USE SIGNAL ;
		DIRECTION INPUT ;
		SHAPE ABUTMENT ;
		PORT
			 LAYER M2 ;
			RECT 0.0098 167.5043 0.0481 167.542 ;
			 LAYER M3 ;
			RECT 0.0098 167.4416 0.0481 167.542 ;
			 LAYER V2 ;
			RECT 0.0215 167.5165 0.0364 167.529 ;
		END

		ANTENNAGATEAREA 0.00027817 ;
		ANTENNADIFFAREA 0.00194719 ;
		ANTENNAPARTIALMETALAREA 0.00195671 ;
	END TD[59]

	PIN TD[5]
		USE SIGNAL ;
		DIRECTION INPUT ;
		SHAPE ABUTMENT ;
		PORT
			 LAYER M2 ;
			RECT 0.0098 15.0463 0.0481 15.0839 ;
			 LAYER M3 ;
			RECT 0.0098 15.0463 0.0481 15.1467 ;
			 LAYER V2 ;
			RECT 0.0215 15.0592 0.0364 15.0718 ;
		END

		ANTENNAGATEAREA 0.00027817 ;
		ANTENNADIFFAREA 0.00194719 ;
		ANTENNAPARTIALMETALAREA 0.00195671 ;
	END TD[5]

	PIN TD[60]
		USE SIGNAL ;
		DIRECTION INPUT ;
		SHAPE ABUTMENT ;
		PORT
			 LAYER M2 ;
			RECT 0.0098 170.0643 0.0481 170.102 ;
			 LAYER M3 ;
			RECT 0.0098 170.0016 0.0481 170.102 ;
			 LAYER V2 ;
			RECT 0.0215 170.0765 0.0364 170.089 ;
		END

		ANTENNAGATEAREA 0.00027817 ;
		ANTENNADIFFAREA 0.00194719 ;
		ANTENNAPARTIALMETALAREA 0.00195671 ;
	END TD[60]

	PIN TD[61]
		USE SIGNAL ;
		DIRECTION INPUT ;
		SHAPE ABUTMENT ;
		PORT
			 LAYER M2 ;
			RECT 0.0098 172.6243 0.0481 172.662 ;
			 LAYER M3 ;
			RECT 0.0098 172.5616 0.0481 172.662 ;
			 LAYER V2 ;
			RECT 0.0215 172.6365 0.0364 172.649 ;
		END

		ANTENNAGATEAREA 0.00027817 ;
		ANTENNADIFFAREA 0.00194719 ;
		ANTENNAPARTIALMETALAREA 0.00195671 ;
	END TD[61]

	PIN TD[62]
		USE SIGNAL ;
		DIRECTION INPUT ;
		SHAPE ABUTMENT ;
		PORT
			 LAYER M2 ;
			RECT 0.0098 175.1843 0.0481 175.222 ;
			 LAYER M3 ;
			RECT 0.0098 175.1216 0.0481 175.222 ;
			 LAYER V2 ;
			RECT 0.0215 175.1965 0.0364 175.209 ;
		END

		ANTENNAGATEAREA 0.00027817 ;
		ANTENNADIFFAREA 0.00194719 ;
		ANTENNAPARTIALMETALAREA 0.00195671 ;
	END TD[62]

	PIN TD[63]
		USE SIGNAL ;
		DIRECTION INPUT ;
		SHAPE ABUTMENT ;
		PORT
			 LAYER M2 ;
			RECT 0.0098 177.7443 0.0481 177.782 ;
			 LAYER M3 ;
			RECT 0.0098 177.6816 0.0481 177.782 ;
			 LAYER V2 ;
			RECT 0.0215 177.7565 0.0364 177.769 ;
		END

		ANTENNAGATEAREA 0.00027817 ;
		ANTENNADIFFAREA 0.00194719 ;
		ANTENNAPARTIALMETALAREA 0.00195671 ;
	END TD[63]

	PIN TD[64]
		USE SIGNAL ;
		DIRECTION INPUT ;
		SHAPE ABUTMENT ;
		PORT
			 LAYER M2 ;
			RECT 0.0098 180.3043 0.0481 180.342 ;
			 LAYER M3 ;
			RECT 0.0098 180.2416 0.0481 180.342 ;
			 LAYER V2 ;
			RECT 0.0215 180.3165 0.0364 180.329 ;
		END

		ANTENNAGATEAREA 0.00027817 ;
		ANTENNADIFFAREA 0.00194719 ;
		ANTENNAPARTIALMETALAREA 0.00195671 ;
	END TD[64]

	PIN TD[65]
		USE SIGNAL ;
		DIRECTION INPUT ;
		SHAPE ABUTMENT ;
		PORT
			 LAYER M2 ;
			RECT 0.0098 182.8643 0.0481 182.902 ;
			 LAYER M3 ;
			RECT 0.0098 182.8016 0.0481 182.902 ;
			 LAYER V2 ;
			RECT 0.0215 182.8765 0.0364 182.889 ;
		END

		ANTENNAGATEAREA 0.00027817 ;
		ANTENNADIFFAREA 0.00194719 ;
		ANTENNAPARTIALMETALAREA 0.00195671 ;
	END TD[65]

	PIN TD[66]
		USE SIGNAL ;
		DIRECTION INPUT ;
		SHAPE ABUTMENT ;
		PORT
			 LAYER M2 ;
			RECT 0.0098 185.4243 0.0481 185.462 ;
			 LAYER M3 ;
			RECT 0.0098 185.3616 0.0481 185.462 ;
			 LAYER V2 ;
			RECT 0.0215 185.4365 0.0364 185.449 ;
		END

		ANTENNAGATEAREA 0.00027817 ;
		ANTENNADIFFAREA 0.00194719 ;
		ANTENNAPARTIALMETALAREA 0.00195671 ;
	END TD[66]

	PIN TD[67]
		USE SIGNAL ;
		DIRECTION INPUT ;
		SHAPE ABUTMENT ;
		PORT
			 LAYER M2 ;
			RECT 0.0098 187.9843 0.0481 188.022 ;
			 LAYER M3 ;
			RECT 0.0098 187.9216 0.0481 188.022 ;
			 LAYER V2 ;
			RECT 0.0215 187.9965 0.0364 188.009 ;
		END

		ANTENNAGATEAREA 0.00027817 ;
		ANTENNADIFFAREA 0.00194719 ;
		ANTENNAPARTIALMETALAREA 0.00195671 ;
	END TD[67]

	PIN TD[68]
		USE SIGNAL ;
		DIRECTION INPUT ;
		SHAPE ABUTMENT ;
		PORT
			 LAYER M2 ;
			RECT 0.0098 190.5443 0.0481 190.582 ;
			 LAYER M3 ;
			RECT 0.0098 190.4816 0.0481 190.582 ;
			 LAYER V2 ;
			RECT 0.0215 190.5565 0.0364 190.569 ;
		END

		ANTENNAGATEAREA 0.00027817 ;
		ANTENNADIFFAREA 0.00194719 ;
		ANTENNAPARTIALMETALAREA 0.00195671 ;
	END TD[68]

	PIN TD[69]
		USE SIGNAL ;
		DIRECTION INPUT ;
		SHAPE ABUTMENT ;
		PORT
			 LAYER M2 ;
			RECT 0.0098 193.1043 0.0481 193.142 ;
			 LAYER M3 ;
			RECT 0.0098 193.0416 0.0481 193.142 ;
			 LAYER V2 ;
			RECT 0.0215 193.1165 0.0364 193.129 ;
		END

		ANTENNAGATEAREA 0.00027817 ;
		ANTENNADIFFAREA 0.00194719 ;
		ANTENNAPARTIALMETALAREA 0.00195671 ;
	END TD[69]

	PIN TD[6]
		USE SIGNAL ;
		DIRECTION INPUT ;
		SHAPE ABUTMENT ;
		PORT
			 LAYER M2 ;
			RECT 0.0098 17.6063 0.0481 17.6439 ;
			 LAYER M3 ;
			RECT 0.0098 17.6063 0.0481 17.7067 ;
			 LAYER V2 ;
			RECT 0.0215 17.6192 0.0364 17.6318 ;
		END

		ANTENNAGATEAREA 0.00027817 ;
		ANTENNADIFFAREA 0.00194719 ;
		ANTENNAPARTIALMETALAREA 0.00195671 ;
	END TD[6]

	PIN TD[70]
		USE SIGNAL ;
		DIRECTION INPUT ;
		SHAPE ABUTMENT ;
		PORT
			 LAYER M2 ;
			RECT 0.0098 195.6643 0.0481 195.702 ;
			 LAYER M3 ;
			RECT 0.0098 195.6016 0.0481 195.702 ;
			 LAYER V2 ;
			RECT 0.0215 195.6765 0.0364 195.689 ;
		END

		ANTENNAGATEAREA 0.00027817 ;
		ANTENNADIFFAREA 0.00194719 ;
		ANTENNAPARTIALMETALAREA 0.00195671 ;
	END TD[70]

	PIN TD[71]
		USE SIGNAL ;
		DIRECTION INPUT ;
		SHAPE ABUTMENT ;
		PORT
			 LAYER M2 ;
			RECT 0.0098 198.2243 0.0481 198.262 ;
			 LAYER M3 ;
			RECT 0.0098 198.1616 0.0481 198.262 ;
			 LAYER V2 ;
			RECT 0.0215 198.2365 0.0364 198.249 ;
		END

		ANTENNAGATEAREA 0.00027817 ;
		ANTENNADIFFAREA 0.00194719 ;
		ANTENNAPARTIALMETALAREA 0.00195671 ;
	END TD[71]

	PIN TD[7]
		USE SIGNAL ;
		DIRECTION INPUT ;
		SHAPE ABUTMENT ;
		PORT
			 LAYER M2 ;
			RECT 0.0098 20.1663 0.0481 20.2039 ;
			 LAYER M3 ;
			RECT 0.0098 20.1663 0.0481 20.2667 ;
			 LAYER V2 ;
			RECT 0.0215 20.1792 0.0364 20.1918 ;
		END

		ANTENNAGATEAREA 0.00027817 ;
		ANTENNADIFFAREA 0.00194719 ;
		ANTENNAPARTIALMETALAREA 0.00195671 ;
	END TD[7]

	PIN TD[8]
		USE SIGNAL ;
		DIRECTION INPUT ;
		SHAPE ABUTMENT ;
		PORT
			 LAYER M2 ;
			RECT 0.0098 22.7263 0.0481 22.7639 ;
			 LAYER M3 ;
			RECT 0.0098 22.7263 0.0481 22.8267 ;
			 LAYER V2 ;
			RECT 0.0215 22.7392 0.0364 22.7518 ;
		END

		ANTENNAGATEAREA 0.00027817 ;
		ANTENNADIFFAREA 0.00194719 ;
		ANTENNAPARTIALMETALAREA 0.00195671 ;
	END TD[8]

	PIN TD[9]
		USE SIGNAL ;
		DIRECTION INPUT ;
		SHAPE ABUTMENT ;
		PORT
			 LAYER M2 ;
			RECT 0.0098 25.2863 0.0481 25.3239 ;
			 LAYER M3 ;
			RECT 0.0098 25.2863 0.0481 25.3867 ;
			 LAYER V2 ;
			RECT 0.0215 25.2992 0.0364 25.3118 ;
		END

		ANTENNAGATEAREA 0.00027817 ;
		ANTENNADIFFAREA 0.00194719 ;
		ANTENNAPARTIALMETALAREA 0.00195671 ;
	END TD[9]

	PIN TEN
		USE SIGNAL ;
		DIRECTION INPUT ;
		SHAPE ABUTMENT ;
		PORT
			 LAYER M2 ;
			RECT 0.0714 113.098 0.1097 113.1357 ;
			 LAYER M3 ;
			RECT 0.0714 113.0353 0.1097 113.1357 ;
			 LAYER V2 ;
			RECT 0.0831 113.111 0.098 113.1235 ;
		END

		ANTENNAGATEAREA 0.00027817 ;
		ANTENNADIFFAREA 0.00194719 ;
		ANTENNAPARTIALMETALAREA 0.00195671 ;
	END TEN

	PIN TGWEN
		USE SIGNAL ;
		DIRECTION INPUT ;
		SHAPE ABUTMENT ;
		PORT
			 LAYER M2 ;
			RECT 0.0714 106.698 0.1097 106.7357 ;
			 LAYER M3 ;
			RECT 0.0714 106.6353 0.1097 106.7357 ;
			 LAYER V2 ;
			RECT 0.0831 106.711 0.098 106.7235 ;
		END

		ANTENNAGATEAREA 0.00027817 ;
		ANTENNADIFFAREA 0.00194719 ;
		ANTENNAPARTIALMETALAREA 0.00195671 ;
	END TGWEN

	PIN TWEN[0]
		USE SIGNAL ;
		DIRECTION INPUT ;
		SHAPE ABUTMENT ;
		PORT
			 LAYER M2 ;
			RECT 0.0714 2.7106 0.1097 2.7482 ;
			 LAYER M3 ;
			RECT 0.0714 2.6478 0.1097 2.7482 ;
			 LAYER V2 ;
			RECT 0.0831 2.7235 0.098 2.7361 ;
		END

		ANTENNAGATEAREA 0.00027817 ;
		ANTENNADIFFAREA 0.00194719 ;
		ANTENNAPARTIALMETALAREA 0.00195671 ;
	END TWEN[0]

	PIN TWEN[10]
		USE SIGNAL ;
		DIRECTION INPUT ;
		SHAPE ABUTMENT ;
		PORT
			 LAYER M2 ;
			RECT 0.0714 28.3106 0.1097 28.3482 ;
			 LAYER M3 ;
			RECT 0.0714 28.2478 0.1097 28.3482 ;
			 LAYER V2 ;
			RECT 0.0831 28.3235 0.098 28.3361 ;
		END

		ANTENNAGATEAREA 0.00027817 ;
		ANTENNADIFFAREA 0.00194719 ;
		ANTENNAPARTIALMETALAREA 0.00195671 ;
	END TWEN[10]

	PIN TWEN[11]
		USE SIGNAL ;
		DIRECTION INPUT ;
		SHAPE ABUTMENT ;
		PORT
			 LAYER M2 ;
			RECT 0.0714 30.8706 0.1097 30.9082 ;
			 LAYER M3 ;
			RECT 0.0714 30.8078 0.1097 30.9082 ;
			 LAYER V2 ;
			RECT 0.0831 30.8835 0.098 30.8961 ;
		END

		ANTENNAGATEAREA 0.00027817 ;
		ANTENNADIFFAREA 0.00194719 ;
		ANTENNAPARTIALMETALAREA 0.00195671 ;
	END TWEN[11]

	PIN TWEN[12]
		USE SIGNAL ;
		DIRECTION INPUT ;
		SHAPE ABUTMENT ;
		PORT
			 LAYER M2 ;
			RECT 0.0714 33.4306 0.1097 33.4682 ;
			 LAYER M3 ;
			RECT 0.0714 33.3678 0.1097 33.4682 ;
			 LAYER V2 ;
			RECT 0.0831 33.4435 0.098 33.4561 ;
		END

		ANTENNAGATEAREA 0.00027817 ;
		ANTENNADIFFAREA 0.00194719 ;
		ANTENNAPARTIALMETALAREA 0.00195671 ;
	END TWEN[12]

	PIN TWEN[13]
		USE SIGNAL ;
		DIRECTION INPUT ;
		SHAPE ABUTMENT ;
		PORT
			 LAYER M2 ;
			RECT 0.0714 35.9906 0.1097 36.0282 ;
			 LAYER M3 ;
			RECT 0.0714 35.9278 0.1097 36.0282 ;
			 LAYER V2 ;
			RECT 0.0831 36.0035 0.098 36.0161 ;
		END

		ANTENNAGATEAREA 0.00027817 ;
		ANTENNADIFFAREA 0.00194719 ;
		ANTENNAPARTIALMETALAREA 0.00195671 ;
	END TWEN[13]

	PIN TWEN[14]
		USE SIGNAL ;
		DIRECTION INPUT ;
		SHAPE ABUTMENT ;
		PORT
			 LAYER M2 ;
			RECT 0.0714 38.5506 0.1097 38.5882 ;
			 LAYER M3 ;
			RECT 0.0714 38.4878 0.1097 38.5882 ;
			 LAYER V2 ;
			RECT 0.0831 38.5635 0.098 38.5761 ;
		END

		ANTENNAGATEAREA 0.00027817 ;
		ANTENNADIFFAREA 0.00194719 ;
		ANTENNAPARTIALMETALAREA 0.00195671 ;
	END TWEN[14]

	PIN TWEN[15]
		USE SIGNAL ;
		DIRECTION INPUT ;
		SHAPE ABUTMENT ;
		PORT
			 LAYER M2 ;
			RECT 0.0714 41.1106 0.1097 41.1482 ;
			 LAYER M3 ;
			RECT 0.0714 41.0478 0.1097 41.1482 ;
			 LAYER V2 ;
			RECT 0.0831 41.1235 0.098 41.1361 ;
		END

		ANTENNAGATEAREA 0.00027817 ;
		ANTENNADIFFAREA 0.00194719 ;
		ANTENNAPARTIALMETALAREA 0.00195671 ;
	END TWEN[15]

	PIN TWEN[16]
		USE SIGNAL ;
		DIRECTION INPUT ;
		SHAPE ABUTMENT ;
		PORT
			 LAYER M2 ;
			RECT 0.0714 43.6706 0.1097 43.7082 ;
			 LAYER M3 ;
			RECT 0.0714 43.6078 0.1097 43.7082 ;
			 LAYER V2 ;
			RECT 0.0831 43.6835 0.098 43.6961 ;
		END

		ANTENNAGATEAREA 0.00027817 ;
		ANTENNADIFFAREA 0.00194719 ;
		ANTENNAPARTIALMETALAREA 0.00195671 ;
	END TWEN[16]

	PIN TWEN[17]
		USE SIGNAL ;
		DIRECTION INPUT ;
		SHAPE ABUTMENT ;
		PORT
			 LAYER M2 ;
			RECT 0.0714 46.2306 0.1097 46.2682 ;
			 LAYER M3 ;
			RECT 0.0714 46.1678 0.1097 46.2682 ;
			 LAYER V2 ;
			RECT 0.0831 46.2435 0.098 46.2561 ;
		END

		ANTENNAGATEAREA 0.00027817 ;
		ANTENNADIFFAREA 0.00194719 ;
		ANTENNAPARTIALMETALAREA 0.00195671 ;
	END TWEN[17]

	PIN TWEN[18]
		USE SIGNAL ;
		DIRECTION INPUT ;
		SHAPE ABUTMENT ;
		PORT
			 LAYER M2 ;
			RECT 0.0714 56.4894 0.1097 56.5271 ;
			 LAYER M3 ;
			RECT 0.0714 56.4267 0.1097 56.5271 ;
			 LAYER V2 ;
			RECT 0.0831 56.5024 0.098 56.5149 ;
		END

		ANTENNAGATEAREA 0.00027817 ;
		ANTENNADIFFAREA 0.00194719 ;
		ANTENNAPARTIALMETALAREA 0.00195671 ;
	END TWEN[18]

	PIN TWEN[19]
		USE SIGNAL ;
		DIRECTION INPUT ;
		SHAPE ABUTMENT ;
		PORT
			 LAYER M2 ;
			RECT 0.0714 59.0494 0.1097 59.0871 ;
			 LAYER M3 ;
			RECT 0.0714 58.9867 0.1097 59.0871 ;
			 LAYER V2 ;
			RECT 0.0831 59.0624 0.098 59.0749 ;
		END

		ANTENNAGATEAREA 0.00027817 ;
		ANTENNADIFFAREA 0.00194719 ;
		ANTENNAPARTIALMETALAREA 0.00195671 ;
	END TWEN[19]

	PIN TWEN[1]
		USE SIGNAL ;
		DIRECTION INPUT ;
		SHAPE ABUTMENT ;
		PORT
			 LAYER M2 ;
			RECT 0.0714 5.2706 0.1097 5.3082 ;
			 LAYER M3 ;
			RECT 0.0714 5.2078 0.1097 5.3082 ;
			 LAYER V2 ;
			RECT 0.0831 5.2835 0.098 5.2961 ;
		END

		ANTENNAGATEAREA 0.00027817 ;
		ANTENNADIFFAREA 0.00194719 ;
		ANTENNAPARTIALMETALAREA 0.00195671 ;
	END TWEN[1]

	PIN TWEN[20]
		USE SIGNAL ;
		DIRECTION INPUT ;
		SHAPE ABUTMENT ;
		PORT
			 LAYER M2 ;
			RECT 0.0714 61.6094 0.1097 61.6471 ;
			 LAYER M3 ;
			RECT 0.0714 61.5467 0.1097 61.6471 ;
			 LAYER V2 ;
			RECT 0.0831 61.6224 0.098 61.6349 ;
		END

		ANTENNAGATEAREA 0.00027817 ;
		ANTENNADIFFAREA 0.00194719 ;
		ANTENNAPARTIALMETALAREA 0.00195671 ;
	END TWEN[20]

	PIN TWEN[21]
		USE SIGNAL ;
		DIRECTION INPUT ;
		SHAPE ABUTMENT ;
		PORT
			 LAYER M2 ;
			RECT 0.0714 64.1694 0.1097 64.2071 ;
			 LAYER M3 ;
			RECT 0.0714 64.1067 0.1097 64.2071 ;
			 LAYER V2 ;
			RECT 0.0831 64.1824 0.098 64.1949 ;
		END

		ANTENNAGATEAREA 0.00027817 ;
		ANTENNADIFFAREA 0.00194719 ;
		ANTENNAPARTIALMETALAREA 0.00195671 ;
	END TWEN[21]

	PIN TWEN[22]
		USE SIGNAL ;
		DIRECTION INPUT ;
		SHAPE ABUTMENT ;
		PORT
			 LAYER M2 ;
			RECT 0.0714 66.7294 0.1097 66.7671 ;
			 LAYER M3 ;
			RECT 0.0714 66.6667 0.1097 66.7671 ;
			 LAYER V2 ;
			RECT 0.0831 66.7424 0.098 66.7549 ;
		END

		ANTENNAGATEAREA 0.00027817 ;
		ANTENNADIFFAREA 0.00194719 ;
		ANTENNAPARTIALMETALAREA 0.00195671 ;
	END TWEN[22]

	PIN TWEN[23]
		USE SIGNAL ;
		DIRECTION INPUT ;
		SHAPE ABUTMENT ;
		PORT
			 LAYER M2 ;
			RECT 0.0714 69.2894 0.1097 69.3271 ;
			 LAYER M3 ;
			RECT 0.0714 69.2267 0.1097 69.3271 ;
			 LAYER V2 ;
			RECT 0.0831 69.3024 0.098 69.3149 ;
		END

		ANTENNAGATEAREA 0.00027817 ;
		ANTENNADIFFAREA 0.00194719 ;
		ANTENNAPARTIALMETALAREA 0.00195671 ;
	END TWEN[23]

	PIN TWEN[24]
		USE SIGNAL ;
		DIRECTION INPUT ;
		SHAPE ABUTMENT ;
		PORT
			 LAYER M2 ;
			RECT 0.0714 71.8494 0.1097 71.8871 ;
			 LAYER M3 ;
			RECT 0.0714 71.7867 0.1097 71.8871 ;
			 LAYER V2 ;
			RECT 0.0831 71.8624 0.098 71.8749 ;
		END

		ANTENNAGATEAREA 0.00027817 ;
		ANTENNADIFFAREA 0.00194719 ;
		ANTENNAPARTIALMETALAREA 0.00195671 ;
	END TWEN[24]

	PIN TWEN[25]
		USE SIGNAL ;
		DIRECTION INPUT ;
		SHAPE ABUTMENT ;
		PORT
			 LAYER M2 ;
			RECT 0.0714 74.4094 0.1097 74.4471 ;
			 LAYER M3 ;
			RECT 0.0714 74.3467 0.1097 74.4471 ;
			 LAYER V2 ;
			RECT 0.0831 74.4224 0.098 74.4349 ;
		END

		ANTENNAGATEAREA 0.00027817 ;
		ANTENNADIFFAREA 0.00194719 ;
		ANTENNAPARTIALMETALAREA 0.00195671 ;
	END TWEN[25]

	PIN TWEN[26]
		USE SIGNAL ;
		DIRECTION INPUT ;
		SHAPE ABUTMENT ;
		PORT
			 LAYER M2 ;
			RECT 0.0714 76.9694 0.1097 77.0071 ;
			 LAYER M3 ;
			RECT 0.0714 76.9067 0.1097 77.0071 ;
			 LAYER V2 ;
			RECT 0.0831 76.9824 0.098 76.9949 ;
		END

		ANTENNAGATEAREA 0.00027817 ;
		ANTENNADIFFAREA 0.00194719 ;
		ANTENNAPARTIALMETALAREA 0.00195671 ;
	END TWEN[26]

	PIN TWEN[27]
		USE SIGNAL ;
		DIRECTION INPUT ;
		SHAPE ABUTMENT ;
		PORT
			 LAYER M2 ;
			RECT 0.0714 79.5294 0.1097 79.5671 ;
			 LAYER M3 ;
			RECT 0.0714 79.4667 0.1097 79.5671 ;
			 LAYER V2 ;
			RECT 0.0831 79.5424 0.098 79.5549 ;
		END

		ANTENNAGATEAREA 0.00027817 ;
		ANTENNADIFFAREA 0.00194719 ;
		ANTENNAPARTIALMETALAREA 0.00195671 ;
	END TWEN[27]

	PIN TWEN[28]
		USE SIGNAL ;
		DIRECTION INPUT ;
		SHAPE ABUTMENT ;
		PORT
			 LAYER M2 ;
			RECT 0.0714 82.0894 0.1097 82.1271 ;
			 LAYER M3 ;
			RECT 0.0714 82.0267 0.1097 82.1271 ;
			 LAYER V2 ;
			RECT 0.0831 82.1024 0.098 82.1149 ;
		END

		ANTENNAGATEAREA 0.00027817 ;
		ANTENNADIFFAREA 0.00194719 ;
		ANTENNAPARTIALMETALAREA 0.00195671 ;
	END TWEN[28]

	PIN TWEN[29]
		USE SIGNAL ;
		DIRECTION INPUT ;
		SHAPE ABUTMENT ;
		PORT
			 LAYER M2 ;
			RECT 0.0714 84.6494 0.1097 84.6871 ;
			 LAYER M3 ;
			RECT 0.0714 84.5867 0.1097 84.6871 ;
			 LAYER V2 ;
			RECT 0.0831 84.6624 0.098 84.6749 ;
		END

		ANTENNAGATEAREA 0.00027817 ;
		ANTENNADIFFAREA 0.00194719 ;
		ANTENNAPARTIALMETALAREA 0.00195671 ;
	END TWEN[29]

	PIN TWEN[2]
		USE SIGNAL ;
		DIRECTION INPUT ;
		SHAPE ABUTMENT ;
		PORT
			 LAYER M2 ;
			RECT 0.0714 7.8306 0.1097 7.8682 ;
			 LAYER M3 ;
			RECT 0.0714 7.7678 0.1097 7.8682 ;
			 LAYER V2 ;
			RECT 0.0831 7.8435 0.098 7.8561 ;
		END

		ANTENNAGATEAREA 0.00027817 ;
		ANTENNADIFFAREA 0.00194719 ;
		ANTENNAPARTIALMETALAREA 0.00195671 ;
	END TWEN[2]

	PIN TWEN[30]
		USE SIGNAL ;
		DIRECTION INPUT ;
		SHAPE ABUTMENT ;
		PORT
			 LAYER M2 ;
			RECT 0.0714 87.2094 0.1097 87.2471 ;
			 LAYER M3 ;
			RECT 0.0714 87.1467 0.1097 87.2471 ;
			 LAYER V2 ;
			RECT 0.0831 87.2224 0.098 87.2349 ;
		END

		ANTENNAGATEAREA 0.00027817 ;
		ANTENNADIFFAREA 0.00194719 ;
		ANTENNAPARTIALMETALAREA 0.00195671 ;
	END TWEN[30]

	PIN TWEN[31]
		USE SIGNAL ;
		DIRECTION INPUT ;
		SHAPE ABUTMENT ;
		PORT
			 LAYER M2 ;
			RECT 0.0714 89.2549 0.1097 89.2925 ;
			 LAYER M3 ;
			RECT 0.0714 89.2549 0.1097 89.3553 ;
			 LAYER V2 ;
			RECT 0.0831 89.2671 0.098 89.2796 ;
		END

		ANTENNAGATEAREA 0.00027817 ;
		ANTENNADIFFAREA 0.00194719 ;
		ANTENNAPARTIALMETALAREA 0.00195671 ;
	END TWEN[31]

	PIN TWEN[32]
		USE SIGNAL ;
		DIRECTION INPUT ;
		SHAPE ABUTMENT ;
		PORT
			 LAYER M2 ;
			RECT 0.0098 91.7647 0.0481 91.8651 ;
			 LAYER M3 ;
			RECT 0.0098 91.7647 0.0481 91.8651 ;
			 LAYER V2 ;
			RECT 0.021 91.8396 0.0359 91.8522 ;
		END

		ANTENNAGATEAREA 0.00027817 ;
		ANTENNADIFFAREA 0.00194719 ;
		ANTENNAPARTIALMETALAREA 0.00195671 ;
	END TWEN[32]

	PIN TWEN[33]
		USE SIGNAL ;
		DIRECTION INPUT ;
		SHAPE ABUTMENT ;
		PORT
			 LAYER M2 ;
			RECT 0.0098 94.2745 0.0481 94.3749 ;
			 LAYER M3 ;
			RECT 0.0098 94.2745 0.0481 94.3749 ;
			 LAYER V2 ;
			RECT 0.021 94.3494 0.0359 94.362 ;
		END

		ANTENNAGATEAREA 0.00027817 ;
		ANTENNADIFFAREA 0.00194719 ;
		ANTENNAPARTIALMETALAREA 0.00195671 ;
	END TWEN[33]

	PIN TWEN[34]
		USE SIGNAL ;
		DIRECTION INPUT ;
		SHAPE ABUTMENT ;
		PORT
			 LAYER M2 ;
			RECT 0.0714 96.9098 0.1097 96.9475 ;
			 LAYER M3 ;
			RECT 0.0714 96.9098 0.1097 97.0102 ;
			 LAYER V2 ;
			RECT 0.0831 96.922 0.098 96.9345 ;
		END

		ANTENNAGATEAREA 0.00027817 ;
		ANTENNADIFFAREA 0.00194719 ;
		ANTENNAPARTIALMETALAREA 0.00195671 ;
	END TWEN[34]

	PIN TWEN[35]
		USE SIGNAL ;
		DIRECTION INPUT ;
		SHAPE ABUTMENT ;
		PORT
			 LAYER M2 ;
			RECT 0.0714 99.4698 0.1097 99.5075 ;
			 LAYER M3 ;
			RECT 0.0714 99.4698 0.1097 99.5702 ;
			 LAYER V2 ;
			RECT 0.0831 99.482 0.098 99.4945 ;
		END

		ANTENNAGATEAREA 0.00027817 ;
		ANTENNADIFFAREA 0.00194719 ;
		ANTENNAPARTIALMETALAREA 0.00195671 ;
	END TWEN[35]

	PIN TWEN[36]
		USE SIGNAL ;
		DIRECTION INPUT ;
		SHAPE ABUTMENT ;
		PORT
			 LAYER M2 ;
			RECT 0.0714 100.9757 0.1097 101.0133 ;
			 LAYER M3 ;
			RECT 0.0714 100.9129 0.1097 101.0133 ;
			 LAYER V2 ;
			RECT 0.0831 100.9886 0.098 101.0012 ;
		END

		ANTENNAGATEAREA 0.00027817 ;
		ANTENNADIFFAREA 0.00194719 ;
		ANTENNAPARTIALMETALAREA 0.00195671 ;
	END TWEN[36]

	PIN TWEN[37]
		USE SIGNAL ;
		DIRECTION INPUT ;
		SHAPE ABUTMENT ;
		PORT
			 LAYER M2 ;
			RECT 0.0714 103.5357 0.1097 103.5733 ;
			 LAYER M3 ;
			RECT 0.0714 103.4729 0.1097 103.5733 ;
			 LAYER V2 ;
			RECT 0.0831 103.5486 0.098 103.5612 ;
		END

		ANTENNAGATEAREA 0.00027817 ;
		ANTENNADIFFAREA 0.00194719 ;
		ANTENNAPARTIALMETALAREA 0.00195671 ;
	END TWEN[37]

	PIN TWEN[38]
		USE SIGNAL ;
		DIRECTION INPUT ;
		SHAPE ABUTMENT ;
		PORT
			 LAYER M2 ;
			RECT 0.0714 106.0957 0.1097 106.1333 ;
			 LAYER M3 ;
			RECT 0.0714 106.0329 0.1097 106.1333 ;
			 LAYER V2 ;
			RECT 0.0831 106.1086 0.098 106.1212 ;
		END

		ANTENNAGATEAREA 0.00027817 ;
		ANTENNADIFFAREA 0.00194719 ;
		ANTENNAPARTIALMETALAREA 0.00195671 ;
	END TWEN[38]

	PIN TWEN[39]
		USE SIGNAL ;
		DIRECTION INPUT ;
		SHAPE ABUTMENT ;
		PORT
			 LAYER M2 ;
			RECT 0.0714 108.6557 0.1097 108.6933 ;
			 LAYER M3 ;
			RECT 0.0714 108.5929 0.1097 108.6933 ;
			 LAYER V2 ;
			RECT 0.0831 108.6686 0.098 108.6812 ;
		END

		ANTENNAGATEAREA 0.00027817 ;
		ANTENNADIFFAREA 0.00194719 ;
		ANTENNAPARTIALMETALAREA 0.00195671 ;
	END TWEN[39]

	PIN TWEN[3]
		USE SIGNAL ;
		DIRECTION INPUT ;
		SHAPE ABUTMENT ;
		PORT
			 LAYER M2 ;
			RECT 0.0714 10.3906 0.1097 10.4282 ;
			 LAYER M3 ;
			RECT 0.0714 10.3278 0.1097 10.4282 ;
			 LAYER V2 ;
			RECT 0.0831 10.4035 0.098 10.4161 ;
		END

		ANTENNAGATEAREA 0.00027817 ;
		ANTENNADIFFAREA 0.00194719 ;
		ANTENNAPARTIALMETALAREA 0.00195671 ;
	END TWEN[3]

	PIN TWEN[40]
		USE SIGNAL ;
		DIRECTION INPUT ;
		SHAPE ABUTMENT ;
		PORT
			 LAYER M2 ;
			RECT 0.0714 111.2157 0.1097 111.2533 ;
			 LAYER M3 ;
			RECT 0.0714 111.1529 0.1097 111.2533 ;
			 LAYER V2 ;
			RECT 0.0831 111.2286 0.098 111.2412 ;
		END

		ANTENNAGATEAREA 0.00027817 ;
		ANTENNADIFFAREA 0.00194719 ;
		ANTENNAPARTIALMETALAREA 0.00195671 ;
	END TWEN[40]

	PIN TWEN[41]
		USE SIGNAL ;
		DIRECTION INPUT ;
		SHAPE ABUTMENT ;
		PORT
			 LAYER M2 ;
			RECT 0.0714 113.2612 0.1097 113.2988 ;
			 LAYER M3 ;
			RECT 0.0714 113.2612 0.1097 113.3616 ;
			 LAYER V2 ;
			RECT 0.0831 113.2733 0.098 113.2859 ;
		END

		ANTENNAGATEAREA 0.00027817 ;
		ANTENNADIFFAREA 0.00194719 ;
		ANTENNAPARTIALMETALAREA 0.00195671 ;
	END TWEN[41]

	PIN TWEN[42]
		USE SIGNAL ;
		DIRECTION INPUT ;
		SHAPE ABUTMENT ;
		PORT
			 LAYER M2 ;
			RECT 0.0714 115.8212 0.1097 115.8588 ;
			 LAYER M3 ;
			RECT 0.0714 115.8212 0.1097 115.9216 ;
			 LAYER V2 ;
			RECT 0.0831 115.8333 0.098 115.8459 ;
		END

		ANTENNAGATEAREA 0.00027817 ;
		ANTENNADIFFAREA 0.00194719 ;
		ANTENNAPARTIALMETALAREA 0.00195671 ;
	END TWEN[42]

	PIN TWEN[43]
		USE SIGNAL ;
		DIRECTION INPUT ;
		SHAPE ABUTMENT ;
		PORT
			 LAYER M2 ;
			RECT 0.0714 118.3812 0.1097 118.4188 ;
			 LAYER M3 ;
			RECT 0.0714 118.3812 0.1097 118.4816 ;
			 LAYER V2 ;
			RECT 0.0831 118.3933 0.098 118.4059 ;
		END

		ANTENNAGATEAREA 0.00027817 ;
		ANTENNADIFFAREA 0.00194719 ;
		ANTENNAPARTIALMETALAREA 0.00195671 ;
	END TWEN[43]

	PIN TWEN[44]
		USE SIGNAL ;
		DIRECTION INPUT ;
		SHAPE ABUTMENT ;
		PORT
			 LAYER M2 ;
			RECT 0.0714 120.9412 0.1097 120.9788 ;
			 LAYER M3 ;
			RECT 0.0714 120.9412 0.1097 121.0416 ;
			 LAYER V2 ;
			RECT 0.0831 120.9533 0.098 120.9659 ;
		END

		ANTENNAGATEAREA 0.00027817 ;
		ANTENNADIFFAREA 0.00194719 ;
		ANTENNAPARTIALMETALAREA 0.00195671 ;
	END TWEN[44]

	PIN TWEN[45]
		USE SIGNAL ;
		DIRECTION INPUT ;
		SHAPE ABUTMENT ;
		PORT
			 LAYER M2 ;
			RECT 0.0714 123.5012 0.1097 123.5388 ;
			 LAYER M3 ;
			RECT 0.0714 123.5012 0.1097 123.6016 ;
			 LAYER V2 ;
			RECT 0.0831 123.5133 0.098 123.5259 ;
		END

		ANTENNAGATEAREA 0.00027817 ;
		ANTENNADIFFAREA 0.00194719 ;
		ANTENNAPARTIALMETALAREA 0.00195671 ;
	END TWEN[45]

	PIN TWEN[46]
		USE SIGNAL ;
		DIRECTION INPUT ;
		SHAPE ABUTMENT ;
		PORT
			 LAYER M2 ;
			RECT 0.0714 126.0612 0.1097 126.0988 ;
			 LAYER M3 ;
			RECT 0.0714 126.0612 0.1097 126.1616 ;
			 LAYER V2 ;
			RECT 0.0831 126.0733 0.098 126.0859 ;
		END

		ANTENNAGATEAREA 0.00027817 ;
		ANTENNADIFFAREA 0.00194719 ;
		ANTENNAPARTIALMETALAREA 0.00195671 ;
	END TWEN[46]

	PIN TWEN[47]
		USE SIGNAL ;
		DIRECTION INPUT ;
		SHAPE ABUTMENT ;
		PORT
			 LAYER M2 ;
			RECT 0.0714 128.6212 0.1097 128.6588 ;
			 LAYER M3 ;
			RECT 0.0714 128.6212 0.1097 128.7216 ;
			 LAYER V2 ;
			RECT 0.0831 128.6333 0.098 128.6459 ;
		END

		ANTENNAGATEAREA 0.00027817 ;
		ANTENNADIFFAREA 0.00194719 ;
		ANTENNAPARTIALMETALAREA 0.00195671 ;
	END TWEN[47]

	PIN TWEN[48]
		USE SIGNAL ;
		DIRECTION INPUT ;
		SHAPE ABUTMENT ;
		PORT
			 LAYER M2 ;
			RECT 0.0714 131.1812 0.1097 131.2188 ;
			 LAYER M3 ;
			RECT 0.0714 131.1812 0.1097 131.2816 ;
			 LAYER V2 ;
			RECT 0.0831 131.1933 0.098 131.2059 ;
		END

		ANTENNAGATEAREA 0.00027817 ;
		ANTENNADIFFAREA 0.00194719 ;
		ANTENNAPARTIALMETALAREA 0.00195671 ;
	END TWEN[48]

	PIN TWEN[49]
		USE SIGNAL ;
		DIRECTION INPUT ;
		SHAPE ABUTMENT ;
		PORT
			 LAYER M2 ;
			RECT 0.0714 133.7412 0.1097 133.7788 ;
			 LAYER M3 ;
			RECT 0.0714 133.7412 0.1097 133.8416 ;
			 LAYER V2 ;
			RECT 0.0831 133.7533 0.098 133.7659 ;
		END

		ANTENNAGATEAREA 0.00027817 ;
		ANTENNADIFFAREA 0.00194719 ;
		ANTENNAPARTIALMETALAREA 0.00195671 ;
	END TWEN[49]

	PIN TWEN[4]
		USE SIGNAL ;
		DIRECTION INPUT ;
		SHAPE ABUTMENT ;
		PORT
			 LAYER M2 ;
			RECT 0.0714 12.9506 0.1097 12.9882 ;
			 LAYER M3 ;
			RECT 0.0714 12.8878 0.1097 12.9882 ;
			 LAYER V2 ;
			RECT 0.0831 12.9635 0.098 12.9761 ;
		END

		ANTENNAGATEAREA 0.00027817 ;
		ANTENNADIFFAREA 0.00194719 ;
		ANTENNAPARTIALMETALAREA 0.00195671 ;
	END TWEN[4]

	PIN TWEN[50]
		USE SIGNAL ;
		DIRECTION INPUT ;
		SHAPE ABUTMENT ;
		PORT
			 LAYER M2 ;
			RECT 0.0714 136.3012 0.1097 136.3388 ;
			 LAYER M3 ;
			RECT 0.0714 136.3012 0.1097 136.4016 ;
			 LAYER V2 ;
			RECT 0.0831 136.3133 0.098 136.3259 ;
		END

		ANTENNAGATEAREA 0.00027817 ;
		ANTENNADIFFAREA 0.00194719 ;
		ANTENNAPARTIALMETALAREA 0.00195671 ;
	END TWEN[50]

	PIN TWEN[51]
		USE SIGNAL ;
		DIRECTION INPUT ;
		SHAPE ABUTMENT ;
		PORT
			 LAYER M2 ;
			RECT 0.0714 138.8612 0.1097 138.8988 ;
			 LAYER M3 ;
			RECT 0.0714 138.8612 0.1097 138.9616 ;
			 LAYER V2 ;
			RECT 0.0831 138.8733 0.098 138.8859 ;
		END

		ANTENNAGATEAREA 0.00027817 ;
		ANTENNADIFFAREA 0.00194719 ;
		ANTENNAPARTIALMETALAREA 0.00195671 ;
	END TWEN[51]

	PIN TWEN[52]
		USE SIGNAL ;
		DIRECTION INPUT ;
		SHAPE ABUTMENT ;
		PORT
			 LAYER M2 ;
			RECT 0.0714 141.4212 0.1097 141.4588 ;
			 LAYER M3 ;
			RECT 0.0714 141.4212 0.1097 141.5216 ;
			 LAYER V2 ;
			RECT 0.0831 141.4333 0.098 141.4459 ;
		END

		ANTENNAGATEAREA 0.00027817 ;
		ANTENNADIFFAREA 0.00194719 ;
		ANTENNAPARTIALMETALAREA 0.00195671 ;
	END TWEN[52]

	PIN TWEN[53]
		USE SIGNAL ;
		DIRECTION INPUT ;
		SHAPE ABUTMENT ;
		PORT
			 LAYER M2 ;
			RECT 0.0714 143.9812 0.1097 144.0188 ;
			 LAYER M3 ;
			RECT 0.0714 143.9812 0.1097 144.0816 ;
			 LAYER V2 ;
			RECT 0.0831 143.9933 0.098 144.0059 ;
		END

		ANTENNAGATEAREA 0.00027817 ;
		ANTENNADIFFAREA 0.00194719 ;
		ANTENNAPARTIALMETALAREA 0.00195671 ;
	END TWEN[53]

	PIN TWEN[54]
		USE SIGNAL ;
		DIRECTION INPUT ;
		SHAPE ABUTMENT ;
		PORT
			 LAYER M2 ;
			RECT 0.0714 154.24 0.1097 154.2776 ;
			 LAYER M3 ;
			RECT 0.0714 154.24 0.1097 154.3404 ;
			 LAYER V2 ;
			RECT 0.0831 154.2522 0.098 154.2647 ;
		END

		ANTENNAGATEAREA 0.00027817 ;
		ANTENNADIFFAREA 0.00194719 ;
		ANTENNAPARTIALMETALAREA 0.00195671 ;
	END TWEN[54]

	PIN TWEN[55]
		USE SIGNAL ;
		DIRECTION INPUT ;
		SHAPE ABUTMENT ;
		PORT
			 LAYER M2 ;
			RECT 0.0714 156.8 0.1097 156.8376 ;
			 LAYER M3 ;
			RECT 0.0714 156.8 0.1097 156.9004 ;
			 LAYER V2 ;
			RECT 0.0831 156.8122 0.098 156.8247 ;
		END

		ANTENNAGATEAREA 0.00027817 ;
		ANTENNADIFFAREA 0.00194719 ;
		ANTENNAPARTIALMETALAREA 0.00195671 ;
	END TWEN[55]

	PIN TWEN[56]
		USE SIGNAL ;
		DIRECTION INPUT ;
		SHAPE ABUTMENT ;
		PORT
			 LAYER M2 ;
			RECT 0.0714 159.36 0.1097 159.3976 ;
			 LAYER M3 ;
			RECT 0.0714 159.36 0.1097 159.4604 ;
			 LAYER V2 ;
			RECT 0.0831 159.3722 0.098 159.3847 ;
		END

		ANTENNAGATEAREA 0.00027817 ;
		ANTENNADIFFAREA 0.00194719 ;
		ANTENNAPARTIALMETALAREA 0.00195671 ;
	END TWEN[56]

	PIN TWEN[57]
		USE SIGNAL ;
		DIRECTION INPUT ;
		SHAPE ABUTMENT ;
		PORT
			 LAYER M2 ;
			RECT 0.0714 161.92 0.1097 161.9576 ;
			 LAYER M3 ;
			RECT 0.0714 161.92 0.1097 162.0204 ;
			 LAYER V2 ;
			RECT 0.0831 161.9322 0.098 161.9447 ;
		END

		ANTENNAGATEAREA 0.00027817 ;
		ANTENNADIFFAREA 0.00194719 ;
		ANTENNAPARTIALMETALAREA 0.00195671 ;
	END TWEN[57]

	PIN TWEN[58]
		USE SIGNAL ;
		DIRECTION INPUT ;
		SHAPE ABUTMENT ;
		PORT
			 LAYER M2 ;
			RECT 0.0714 164.48 0.1097 164.5176 ;
			 LAYER M3 ;
			RECT 0.0714 164.48 0.1097 164.5804 ;
			 LAYER V2 ;
			RECT 0.0831 164.4922 0.098 164.5047 ;
		END

		ANTENNAGATEAREA 0.00027817 ;
		ANTENNADIFFAREA 0.00194719 ;
		ANTENNAPARTIALMETALAREA 0.00195671 ;
	END TWEN[58]

	PIN TWEN[59]
		USE SIGNAL ;
		DIRECTION INPUT ;
		SHAPE ABUTMENT ;
		PORT
			 LAYER M2 ;
			RECT 0.0714 167.04 0.1097 167.0776 ;
			 LAYER M3 ;
			RECT 0.0714 167.04 0.1097 167.1404 ;
			 LAYER V2 ;
			RECT 0.0831 167.0522 0.098 167.0647 ;
		END

		ANTENNAGATEAREA 0.00027817 ;
		ANTENNADIFFAREA 0.00194719 ;
		ANTENNAPARTIALMETALAREA 0.00195671 ;
	END TWEN[59]

	PIN TWEN[5]
		USE SIGNAL ;
		DIRECTION INPUT ;
		SHAPE ABUTMENT ;
		PORT
			 LAYER M2 ;
			RECT 0.0714 15.5106 0.1097 15.5482 ;
			 LAYER M3 ;
			RECT 0.0714 15.4478 0.1097 15.5482 ;
			 LAYER V2 ;
			RECT 0.0831 15.5235 0.098 15.5361 ;
		END

		ANTENNAGATEAREA 0.00027817 ;
		ANTENNADIFFAREA 0.00194719 ;
		ANTENNAPARTIALMETALAREA 0.00195671 ;
	END TWEN[5]

	PIN TWEN[60]
		USE SIGNAL ;
		DIRECTION INPUT ;
		SHAPE ABUTMENT ;
		PORT
			 LAYER M2 ;
			RECT 0.0714 169.6 0.1097 169.6376 ;
			 LAYER M3 ;
			RECT 0.0714 169.6 0.1097 169.7004 ;
			 LAYER V2 ;
			RECT 0.0831 169.6122 0.098 169.6247 ;
		END

		ANTENNAGATEAREA 0.00027817 ;
		ANTENNADIFFAREA 0.00194719 ;
		ANTENNAPARTIALMETALAREA 0.00195671 ;
	END TWEN[60]

	PIN TWEN[61]
		USE SIGNAL ;
		DIRECTION INPUT ;
		SHAPE ABUTMENT ;
		PORT
			 LAYER M2 ;
			RECT 0.0714 172.16 0.1097 172.1976 ;
			 LAYER M3 ;
			RECT 0.0714 172.16 0.1097 172.2604 ;
			 LAYER V2 ;
			RECT 0.0831 172.1722 0.098 172.1847 ;
		END

		ANTENNAGATEAREA 0.00027817 ;
		ANTENNADIFFAREA 0.00194719 ;
		ANTENNAPARTIALMETALAREA 0.00195671 ;
	END TWEN[61]

	PIN TWEN[62]
		USE SIGNAL ;
		DIRECTION INPUT ;
		SHAPE ABUTMENT ;
		PORT
			 LAYER M2 ;
			RECT 0.0714 174.72 0.1097 174.7576 ;
			 LAYER M3 ;
			RECT 0.0714 174.72 0.1097 174.8204 ;
			 LAYER V2 ;
			RECT 0.0831 174.7322 0.098 174.7447 ;
		END

		ANTENNAGATEAREA 0.00027817 ;
		ANTENNADIFFAREA 0.00194719 ;
		ANTENNAPARTIALMETALAREA 0.00195671 ;
	END TWEN[62]

	PIN TWEN[63]
		USE SIGNAL ;
		DIRECTION INPUT ;
		SHAPE ABUTMENT ;
		PORT
			 LAYER M2 ;
			RECT 0.0714 177.28 0.1097 177.3176 ;
			 LAYER M3 ;
			RECT 0.0714 177.28 0.1097 177.3804 ;
			 LAYER V2 ;
			RECT 0.0831 177.2922 0.098 177.3047 ;
		END

		ANTENNAGATEAREA 0.00027817 ;
		ANTENNADIFFAREA 0.00194719 ;
		ANTENNAPARTIALMETALAREA 0.00195671 ;
	END TWEN[63]

	PIN TWEN[64]
		USE SIGNAL ;
		DIRECTION INPUT ;
		SHAPE ABUTMENT ;
		PORT
			 LAYER M2 ;
			RECT 0.0714 179.84 0.1097 179.8776 ;
			 LAYER M3 ;
			RECT 0.0714 179.84 0.1097 179.9404 ;
			 LAYER V2 ;
			RECT 0.0831 179.8522 0.098 179.8647 ;
		END

		ANTENNAGATEAREA 0.00027817 ;
		ANTENNADIFFAREA 0.00194719 ;
		ANTENNAPARTIALMETALAREA 0.00195671 ;
	END TWEN[64]

	PIN TWEN[65]
		USE SIGNAL ;
		DIRECTION INPUT ;
		SHAPE ABUTMENT ;
		PORT
			 LAYER M2 ;
			RECT 0.0714 182.4 0.1097 182.4376 ;
			 LAYER M3 ;
			RECT 0.0714 182.4 0.1097 182.5004 ;
			 LAYER V2 ;
			RECT 0.0831 182.4122 0.098 182.4247 ;
		END

		ANTENNAGATEAREA 0.00027817 ;
		ANTENNADIFFAREA 0.00194719 ;
		ANTENNAPARTIALMETALAREA 0.00195671 ;
	END TWEN[65]

	PIN TWEN[66]
		USE SIGNAL ;
		DIRECTION INPUT ;
		SHAPE ABUTMENT ;
		PORT
			 LAYER M2 ;
			RECT 0.0714 184.96 0.1097 184.9976 ;
			 LAYER M3 ;
			RECT 0.0714 184.96 0.1097 185.0604 ;
			 LAYER V2 ;
			RECT 0.0831 184.9722 0.098 184.9847 ;
		END

		ANTENNAGATEAREA 0.00027817 ;
		ANTENNADIFFAREA 0.00194719 ;
		ANTENNAPARTIALMETALAREA 0.00195671 ;
	END TWEN[66]

	PIN TWEN[67]
		USE SIGNAL ;
		DIRECTION INPUT ;
		SHAPE ABUTMENT ;
		PORT
			 LAYER M2 ;
			RECT 0.0714 187.52 0.1097 187.5576 ;
			 LAYER M3 ;
			RECT 0.0714 187.52 0.1097 187.6204 ;
			 LAYER V2 ;
			RECT 0.0831 187.5322 0.098 187.5447 ;
		END

		ANTENNAGATEAREA 0.00027817 ;
		ANTENNADIFFAREA 0.00194719 ;
		ANTENNAPARTIALMETALAREA 0.00195671 ;
	END TWEN[67]

	PIN TWEN[68]
		USE SIGNAL ;
		DIRECTION INPUT ;
		SHAPE ABUTMENT ;
		PORT
			 LAYER M2 ;
			RECT 0.0714 190.08 0.1097 190.1176 ;
			 LAYER M3 ;
			RECT 0.0714 190.08 0.1097 190.1804 ;
			 LAYER V2 ;
			RECT 0.0831 190.0922 0.098 190.1047 ;
		END

		ANTENNAGATEAREA 0.00027817 ;
		ANTENNADIFFAREA 0.00194719 ;
		ANTENNAPARTIALMETALAREA 0.00195671 ;
	END TWEN[68]

	PIN TWEN[69]
		USE SIGNAL ;
		DIRECTION INPUT ;
		SHAPE ABUTMENT ;
		PORT
			 LAYER M2 ;
			RECT 0.0714 192.64 0.1097 192.6776 ;
			 LAYER M3 ;
			RECT 0.0714 192.64 0.1097 192.7404 ;
			 LAYER V2 ;
			RECT 0.0831 192.6522 0.098 192.6647 ;
		END

		ANTENNAGATEAREA 0.00027817 ;
		ANTENNADIFFAREA 0.00194719 ;
		ANTENNAPARTIALMETALAREA 0.00195671 ;
	END TWEN[69]

	PIN TWEN[6]
		USE SIGNAL ;
		DIRECTION INPUT ;
		SHAPE ABUTMENT ;
		PORT
			 LAYER M2 ;
			RECT 0.0714 18.0706 0.1097 18.1082 ;
			 LAYER M3 ;
			RECT 0.0714 18.0078 0.1097 18.1082 ;
			 LAYER V2 ;
			RECT 0.0831 18.0835 0.098 18.0961 ;
		END

		ANTENNAGATEAREA 0.00027817 ;
		ANTENNADIFFAREA 0.00194719 ;
		ANTENNAPARTIALMETALAREA 0.00195671 ;
	END TWEN[6]

	PIN TWEN[70]
		USE SIGNAL ;
		DIRECTION INPUT ;
		SHAPE ABUTMENT ;
		PORT
			 LAYER M2 ;
			RECT 0.0714 195.2 0.1097 195.2376 ;
			 LAYER M3 ;
			RECT 0.0714 195.2 0.1097 195.3004 ;
			 LAYER V2 ;
			RECT 0.0831 195.2122 0.098 195.2247 ;
		END

		ANTENNAGATEAREA 0.00027817 ;
		ANTENNADIFFAREA 0.00194719 ;
		ANTENNAPARTIALMETALAREA 0.00195671 ;
	END TWEN[70]

	PIN TWEN[71]
		USE SIGNAL ;
		DIRECTION INPUT ;
		SHAPE ABUTMENT ;
		PORT
			 LAYER M2 ;
			RECT 0.0714 197.76 0.1097 197.7976 ;
			 LAYER M3 ;
			RECT 0.0714 197.76 0.1097 197.8604 ;
			 LAYER V2 ;
			RECT 0.0831 197.7722 0.098 197.7847 ;
		END

		ANTENNAGATEAREA 0.00027817 ;
		ANTENNADIFFAREA 0.00194719 ;
		ANTENNAPARTIALMETALAREA 0.00195671 ;
	END TWEN[71]

	PIN TWEN[7]
		USE SIGNAL ;
		DIRECTION INPUT ;
		SHAPE ABUTMENT ;
		PORT
			 LAYER M2 ;
			RECT 0.0714 20.6306 0.1097 20.6682 ;
			 LAYER M3 ;
			RECT 0.0714 20.5678 0.1097 20.6682 ;
			 LAYER V2 ;
			RECT 0.0831 20.6435 0.098 20.6561 ;
		END

		ANTENNAGATEAREA 0.00027817 ;
		ANTENNADIFFAREA 0.00194719 ;
		ANTENNAPARTIALMETALAREA 0.00195671 ;
	END TWEN[7]

	PIN TWEN[8]
		USE SIGNAL ;
		DIRECTION INPUT ;
		SHAPE ABUTMENT ;
		PORT
			 LAYER M2 ;
			RECT 0.0714 23.1906 0.1097 23.2282 ;
			 LAYER M3 ;
			RECT 0.0714 23.1278 0.1097 23.2282 ;
			 LAYER V2 ;
			RECT 0.0831 23.2035 0.098 23.2161 ;
		END

		ANTENNAGATEAREA 0.00027817 ;
		ANTENNADIFFAREA 0.00194719 ;
		ANTENNAPARTIALMETALAREA 0.00195671 ;
	END TWEN[8]

	PIN TWEN[9]
		USE SIGNAL ;
		DIRECTION INPUT ;
		SHAPE ABUTMENT ;
		PORT
			 LAYER M2 ;
			RECT 0.0714 25.7506 0.1097 25.7882 ;
			 LAYER M3 ;
			RECT 0.0714 25.6878 0.1097 25.7882 ;
			 LAYER V2 ;
			RECT 0.0831 25.7635 0.098 25.7761 ;
		END

		ANTENNAGATEAREA 0.00027817 ;
		ANTENNADIFFAREA 0.00194719 ;
		ANTENNAPARTIALMETALAREA 0.00195671 ;
	END TWEN[9]

	PIN VDDCE
		USE POWER ;
		DIRECTION INOUT ;
		PORT
			 LAYER M4 ;
			RECT 0.2105 199.6667 124.383 199.7137 ;
		END

		PORT
			 LAYER M4 ;
			RECT 0.2105 179.1867 124.383 179.2337 ;
		END

		PORT
			 LAYER M4 ;
			RECT 0.2105 178.5467 124.383 178.5937 ;
		END

		PORT
			 LAYER M4 ;
			RECT 0.2105 177.9067 124.383 177.9537 ;
		END

		PORT
			 LAYER M4 ;
			RECT 0.2105 198.3867 124.383 198.4337 ;
		END

		PORT
			 LAYER M4 ;
			RECT 0.2105 177.2667 124.383 177.3137 ;
		END

		PORT
			 LAYER M4 ;
			RECT 0.2105 176.6267 124.383 176.6737 ;
		END

		PORT
			 LAYER M4 ;
			RECT 0.2105 175.9867 124.383 176.0337 ;
		END

		PORT
			 LAYER M4 ;
			RECT 0.2105 175.3467 124.383 175.3937 ;
		END

		PORT
			 LAYER M4 ;
			RECT 0.2105 174.7067 124.383 174.7537 ;
		END

		PORT
			 LAYER M4 ;
			RECT 0.2105 174.0667 124.383 174.1137 ;
		END

		PORT
			 LAYER M4 ;
			RECT 0.2105 173.4267 124.383 173.4737 ;
		END

		PORT
			 LAYER M4 ;
			RECT 0.2105 172.7867 124.383 172.8337 ;
		END

		PORT
			 LAYER M4 ;
			RECT 0.2105 172.1467 124.383 172.1937 ;
		END

		PORT
			 LAYER M4 ;
			RECT 0.2105 171.5067 124.383 171.5537 ;
		END

		PORT
			 LAYER M4 ;
			RECT 0.2105 197.7467 124.383 197.7937 ;
		END

		PORT
			 LAYER M4 ;
			RECT 0.2105 170.8667 124.383 170.9137 ;
		END

		PORT
			 LAYER M4 ;
			RECT 0.2105 170.2267 124.383 170.2737 ;
		END

		PORT
			 LAYER M4 ;
			RECT 0.2105 169.5867 124.383 169.6337 ;
		END

		PORT
			 LAYER M4 ;
			RECT 0.2105 168.9467 124.383 168.9937 ;
		END

		PORT
			 LAYER M4 ;
			RECT 0.2105 168.3067 124.383 168.3537 ;
		END

		PORT
			 LAYER M4 ;
			RECT 0.2105 167.6667 124.383 167.7137 ;
		END

		PORT
			 LAYER M4 ;
			RECT 0.2105 167.0267 124.383 167.0737 ;
		END

		PORT
			 LAYER M4 ;
			RECT 0.2105 166.3867 124.383 166.4337 ;
		END

		PORT
			 LAYER M4 ;
			RECT 0.2105 165.7467 124.383 165.7937 ;
		END

		PORT
			 LAYER M4 ;
			RECT 0.2105 165.1067 124.383 165.1537 ;
		END

		PORT
			 LAYER M4 ;
			RECT 0.2105 197.1067 124.383 197.1537 ;
		END

		PORT
			 LAYER M4 ;
			RECT 0.2105 164.4667 124.383 164.5137 ;
		END

		PORT
			 LAYER M4 ;
			RECT 0.2105 163.8267 124.383 163.8737 ;
		END

		PORT
			 LAYER M4 ;
			RECT 0.2105 163.1867 124.383 163.2337 ;
		END

		PORT
			 LAYER M4 ;
			RECT 0.2105 162.5467 124.383 162.5937 ;
		END

		PORT
			 LAYER M4 ;
			RECT 0.2105 161.9067 124.383 161.9537 ;
		END

		PORT
			 LAYER M4 ;
			RECT 0.2105 161.2667 124.383 161.3137 ;
		END

		PORT
			 LAYER M4 ;
			RECT 0.2105 160.6267 124.383 160.6737 ;
		END

		PORT
			 LAYER M4 ;
			RECT 0.2105 159.9867 124.383 160.0337 ;
		END

		PORT
			 LAYER M4 ;
			RECT 0.2105 159.3467 124.383 159.3937 ;
		END

		PORT
			 LAYER M4 ;
			RECT 0.2105 158.7067 124.383 158.7537 ;
		END

		PORT
			 LAYER M4 ;
			RECT 0.2105 196.4667 124.383 196.5137 ;
		END

		PORT
			 LAYER M4 ;
			RECT 0.2105 158.0667 124.383 158.1137 ;
		END

		PORT
			 LAYER M4 ;
			RECT 0.2105 157.4267 124.383 157.4737 ;
		END

		PORT
			 LAYER M4 ;
			RECT 0.2105 156.7867 124.383 156.8337 ;
		END

		PORT
			 LAYER M4 ;
			RECT 0.2105 156.1467 124.383 156.1937 ;
		END

		PORT
			 LAYER M4 ;
			RECT 0.2105 155.5067 124.383 155.5537 ;
		END

		PORT
			 LAYER M4 ;
			RECT 0.2105 154.8667 124.383 154.9137 ;
		END

		PORT
			 LAYER M4 ;
			RECT 0.2105 154.2267 124.383 154.2737 ;
		END

		PORT
			 LAYER M4 ;
			RECT 0.2105 195.8267 124.383 195.8737 ;
		END

		PORT
			 LAYER M4 ;
			RECT 0.2105 145.8878 124.383 145.9349 ;
		END

		PORT
			 LAYER M4 ;
			RECT 0.2105 145.2478 124.383 145.2949 ;
		END

		PORT
			 LAYER M4 ;
			RECT 0.2105 195.1867 124.383 195.2337 ;
		END

		PORT
			 LAYER M4 ;
			RECT 0.2105 144.6078 124.383 144.6549 ;
		END

		PORT
			 LAYER M4 ;
			RECT 0.2105 143.9678 124.383 144.0149 ;
		END

		PORT
			 LAYER M4 ;
			RECT 0.2105 143.3278 124.383 143.3749 ;
		END

		PORT
			 LAYER M4 ;
			RECT 0.2105 142.6878 124.383 142.7349 ;
		END

		PORT
			 LAYER M4 ;
			RECT 0.2105 142.0478 124.383 142.0949 ;
		END

		PORT
			 LAYER M4 ;
			RECT 0.2105 141.4078 124.383 141.4549 ;
		END

		PORT
			 LAYER M4 ;
			RECT 0.2105 140.7678 124.383 140.8149 ;
		END

		PORT
			 LAYER M4 ;
			RECT 0.2105 140.1278 124.383 140.1749 ;
		END

		PORT
			 LAYER M4 ;
			RECT 0.2105 139.4878 124.383 139.5349 ;
		END

		PORT
			 LAYER M4 ;
			RECT 0.2105 138.8478 124.383 138.8949 ;
		END

		PORT
			 LAYER M4 ;
			RECT 0.2105 194.5467 124.383 194.5937 ;
		END

		PORT
			 LAYER M4 ;
			RECT 0.2105 138.2078 124.383 138.2549 ;
		END

		PORT
			 LAYER M4 ;
			RECT 0.2105 137.5678 124.383 137.6149 ;
		END

		PORT
			 LAYER M4 ;
			RECT 0.2105 136.9278 124.383 136.9749 ;
		END

		PORT
			 LAYER M4 ;
			RECT 0.2105 136.2878 124.383 136.3349 ;
		END

		PORT
			 LAYER M4 ;
			RECT 0.2105 135.6478 124.383 135.6949 ;
		END

		PORT
			 LAYER M4 ;
			RECT 0.2105 135.0078 124.383 135.0549 ;
		END

		PORT
			 LAYER M4 ;
			RECT 0.2105 134.3678 124.383 134.4149 ;
		END

		PORT
			 LAYER M4 ;
			RECT 0.2105 133.7278 124.383 133.7749 ;
		END

		PORT
			 LAYER M4 ;
			RECT 0.2105 133.0878 124.383 133.1349 ;
		END

		PORT
			 LAYER M4 ;
			RECT 0.2105 132.4478 124.383 132.4949 ;
		END

		PORT
			 LAYER M4 ;
			RECT 0.2105 193.9067 124.383 193.9537 ;
		END

		PORT
			 LAYER M4 ;
			RECT 0.2105 131.8078 124.383 131.8549 ;
		END

		PORT
			 LAYER M4 ;
			RECT 0.2105 131.1678 124.383 131.2149 ;
		END

		PORT
			 LAYER M4 ;
			RECT 0.2105 130.5278 124.383 130.5749 ;
		END

		PORT
			 LAYER M4 ;
			RECT 0.2105 129.8878 124.383 129.9349 ;
		END

		PORT
			 LAYER M4 ;
			RECT 0.2105 129.2478 124.383 129.2949 ;
		END

		PORT
			 LAYER M4 ;
			RECT 0.2105 128.6078 124.383 128.6549 ;
		END

		PORT
			 LAYER M4 ;
			RECT 0.2105 127.9678 124.383 128.0149 ;
		END

		PORT
			 LAYER M4 ;
			RECT 0.2105 127.3278 124.383 127.3749 ;
		END

		PORT
			 LAYER M4 ;
			RECT 0.2105 126.6878 124.383 126.7349 ;
		END

		PORT
			 LAYER M4 ;
			RECT 0.2105 126.0478 124.383 126.0949 ;
		END

		PORT
			 LAYER M4 ;
			RECT 0.2105 193.2667 124.383 193.3137 ;
		END

		PORT
			 LAYER M4 ;
			RECT 0.2105 125.4078 124.383 125.4549 ;
		END

		PORT
			 LAYER M4 ;
			RECT 0.2105 124.7678 124.383 124.8149 ;
		END

		PORT
			 LAYER M4 ;
			RECT 0.2105 124.1278 124.383 124.1749 ;
		END

		PORT
			 LAYER M4 ;
			RECT 0.2105 123.4878 124.383 123.5349 ;
		END

		PORT
			 LAYER M4 ;
			RECT 0.2105 122.8478 124.383 122.8949 ;
		END

		PORT
			 LAYER M4 ;
			RECT 0.2105 122.2078 124.383 122.2549 ;
		END

		PORT
			 LAYER M4 ;
			RECT 0.2105 121.5678 124.383 121.6149 ;
		END

		PORT
			 LAYER M4 ;
			RECT 0.2105 120.9278 124.383 120.9749 ;
		END

		PORT
			 LAYER M4 ;
			RECT 0.2105 120.2878 124.383 120.3349 ;
		END

		PORT
			 LAYER M4 ;
			RECT 0.2105 119.6478 124.383 119.6949 ;
		END

		PORT
			 LAYER M4 ;
			RECT 0.2105 192.6267 124.383 192.6737 ;
		END

		PORT
			 LAYER M4 ;
			RECT 0.2105 119.0078 124.383 119.0549 ;
		END

		PORT
			 LAYER M4 ;
			RECT 0.2105 118.3678 124.383 118.4149 ;
		END

		PORT
			 LAYER M4 ;
			RECT 0.2105 117.7278 124.383 117.7749 ;
		END

		PORT
			 LAYER M4 ;
			RECT 0.2105 117.0878 124.383 117.1349 ;
		END

		PORT
			 LAYER M4 ;
			RECT 0.2105 116.4478 124.383 116.4949 ;
		END

		PORT
			 LAYER M4 ;
			RECT 0.2105 115.8078 124.383 115.8549 ;
		END

		PORT
			 LAYER M4 ;
			RECT 0.2105 115.1678 124.383 115.2149 ;
		END

		PORT
			 LAYER M4 ;
			RECT 0.2105 114.5278 124.383 114.5749 ;
		END

		PORT
			 LAYER M4 ;
			RECT 0.2105 113.8878 124.383 113.9349 ;
		END

		PORT
			 LAYER M4 ;
			RECT 0.2105 113.2478 124.383 113.2949 ;
		END

		PORT
			 LAYER M4 ;
			RECT 0.2105 191.9867 124.383 192.0337 ;
		END

		PORT
			 LAYER M4 ;
			RECT 0.2105 112.6078 124.383 112.6549 ;
		END

		PORT
			 LAYER M4 ;
			RECT 0.2105 111.9678 124.383 112.0149 ;
		END

		PORT
			 LAYER M4 ;
			RECT 0.2105 111.3278 124.383 111.3749 ;
		END

		PORT
			 LAYER M4 ;
			RECT 0.2105 110.6878 124.383 110.7349 ;
		END

		PORT
			 LAYER M4 ;
			RECT 0.2105 110.0478 124.383 110.0949 ;
		END

		PORT
			 LAYER M4 ;
			RECT 0.2105 109.4078 124.383 109.4549 ;
		END

		PORT
			 LAYER M4 ;
			RECT 0.2105 108.7678 124.383 108.8149 ;
		END

		PORT
			 LAYER M4 ;
			RECT 0.2105 108.1278 124.383 108.1749 ;
		END

		PORT
			 LAYER M4 ;
			RECT 0.2105 107.4878 124.383 107.5349 ;
		END

		PORT
			 LAYER M4 ;
			RECT 0.2105 106.8478 124.383 106.8949 ;
		END

		PORT
			 LAYER M4 ;
			RECT 0.2105 191.3467 124.383 191.3937 ;
		END

		PORT
			 LAYER M4 ;
			RECT 0.2105 106.2078 124.383 106.2549 ;
		END

		PORT
			 LAYER M4 ;
			RECT 0.2105 105.5678 124.383 105.6149 ;
		END

		PORT
			 LAYER M4 ;
			RECT 0.2105 104.9278 124.383 104.9749 ;
		END

		PORT
			 LAYER M4 ;
			RECT 0.2105 104.2878 124.383 104.3349 ;
		END

		PORT
			 LAYER M4 ;
			RECT 0.2105 103.6478 124.383 103.6949 ;
		END

		PORT
			 LAYER M4 ;
			RECT 0.2105 103.0078 124.383 103.0549 ;
		END

		PORT
			 LAYER M4 ;
			RECT 0.2105 102.3678 124.383 102.4149 ;
		END

		PORT
			 LAYER M4 ;
			RECT 0.2105 101.7278 124.383 101.7749 ;
		END

		PORT
			 LAYER M4 ;
			RECT 0.2105 101.0878 124.383 101.1349 ;
		END

		PORT
			 LAYER M4 ;
			RECT 0.2105 100.4478 124.383 100.4949 ;
		END

		PORT
			 LAYER M4 ;
			RECT 0.2105 190.7067 124.383 190.7537 ;
		END

		PORT
			 LAYER M4 ;
			RECT 0.2105 100.0133 124.383 100.0604 ;
		END

		PORT
			 LAYER M4 ;
			RECT 0.2105 99.3733 124.383 99.4204 ;
		END

		PORT
			 LAYER M4 ;
			RECT 0.2105 98.7333 124.383 98.7804 ;
		END

		PORT
			 LAYER M4 ;
			RECT 0.2105 98.0933 124.383 98.1404 ;
		END

		PORT
			 LAYER M4 ;
			RECT 0.2105 97.4533 124.383 97.5004 ;
		END

		PORT
			 LAYER M4 ;
			RECT 0.2105 96.8133 124.383 96.8604 ;
		END

		PORT
			 LAYER M4 ;
			RECT 0.2105 96.1733 124.383 96.2204 ;
		END

		PORT
			 LAYER M4 ;
			RECT 0.2105 95.5333 124.383 95.5804 ;
		END

		PORT
			 LAYER M4 ;
			RECT 0.2105 94.8933 124.383 94.9404 ;
		END

		PORT
			 LAYER M4 ;
			RECT 0.2105 190.0667 124.383 190.1137 ;
		END

		PORT
			 LAYER M4 ;
			RECT 0.2105 94.2533 124.383 94.3004 ;
		END

		PORT
			 LAYER M4 ;
			RECT 0.2105 93.6133 124.383 93.6604 ;
		END

		PORT
			 LAYER M4 ;
			RECT 0.2105 92.9733 124.383 93.0204 ;
		END

		PORT
			 LAYER M4 ;
			RECT 0.2105 92.3333 124.383 92.3804 ;
		END

		PORT
			 LAYER M4 ;
			RECT 0.2105 91.6933 124.383 91.7404 ;
		END

		PORT
			 LAYER M4 ;
			RECT 0.2105 91.0533 124.383 91.1004 ;
		END

		PORT
			 LAYER M4 ;
			RECT 0.2105 90.4133 124.383 90.4604 ;
		END

		PORT
			 LAYER M4 ;
			RECT 0.2105 89.7733 124.383 89.8204 ;
		END

		PORT
			 LAYER M4 ;
			RECT 0.2105 89.1333 124.383 89.1804 ;
		END

		PORT
			 LAYER M4 ;
			RECT 0.2105 88.4933 124.383 88.5404 ;
		END

		PORT
			 LAYER M4 ;
			RECT 0.2105 189.4267 124.383 189.4737 ;
		END

		PORT
			 LAYER M4 ;
			RECT 0.2105 87.8533 124.383 87.9004 ;
		END

		PORT
			 LAYER M4 ;
			RECT 0.2105 87.2133 124.383 87.2604 ;
		END

		PORT
			 LAYER M4 ;
			RECT 0.2105 86.5733 124.383 86.6204 ;
		END

		PORT
			 LAYER M4 ;
			RECT 0.2105 85.9333 124.383 85.9804 ;
		END

		PORT
			 LAYER M4 ;
			RECT 0.2105 85.2933 124.383 85.3404 ;
		END

		PORT
			 LAYER M4 ;
			RECT 0.2105 84.6533 124.383 84.7004 ;
		END

		PORT
			 LAYER M4 ;
			RECT 0.2105 84.0133 124.383 84.0604 ;
		END

		PORT
			 LAYER M4 ;
			RECT 0.2105 83.3733 124.383 83.4204 ;
		END

		PORT
			 LAYER M4 ;
			RECT 0.2105 82.7333 124.383 82.7804 ;
		END

		PORT
			 LAYER M4 ;
			RECT 0.2105 82.0933 124.383 82.1404 ;
		END

		PORT
			 LAYER M4 ;
			RECT 0.2105 188.7867 124.383 188.8337 ;
		END

		PORT
			 LAYER M4 ;
			RECT 0.2105 81.4533 124.383 81.5004 ;
		END

		PORT
			 LAYER M4 ;
			RECT 0.2105 80.8133 124.383 80.8604 ;
		END

		PORT
			 LAYER M4 ;
			RECT 0.2105 80.1733 124.383 80.2204 ;
		END

		PORT
			 LAYER M4 ;
			RECT 0.2105 79.5333 124.383 79.5804 ;
		END

		PORT
			 LAYER M4 ;
			RECT 0.2105 78.8933 124.383 78.9404 ;
		END

		PORT
			 LAYER M4 ;
			RECT 0.2105 78.2533 124.383 78.3004 ;
		END

		PORT
			 LAYER M4 ;
			RECT 0.2105 77.6133 124.383 77.6604 ;
		END

		PORT
			 LAYER M4 ;
			RECT 0.2105 76.9733 124.383 77.0204 ;
		END

		PORT
			 LAYER M4 ;
			RECT 0.2105 76.3333 124.383 76.3804 ;
		END

		PORT
			 LAYER M4 ;
			RECT 0.2105 75.6933 124.383 75.7404 ;
		END

		PORT
			 LAYER M4 ;
			RECT 0.2105 188.1467 124.383 188.1937 ;
		END

		PORT
			 LAYER M4 ;
			RECT 0.2105 75.0533 124.383 75.1004 ;
		END

		PORT
			 LAYER M4 ;
			RECT 0.2105 74.4133 124.383 74.4604 ;
		END

		PORT
			 LAYER M4 ;
			RECT 0.2105 73.7733 124.383 73.8204 ;
		END

		PORT
			 LAYER M4 ;
			RECT 0.2105 73.1333 124.383 73.1804 ;
		END

		PORT
			 LAYER M4 ;
			RECT 0.2105 72.4933 124.383 72.5404 ;
		END

		PORT
			 LAYER M4 ;
			RECT 0.2105 71.8533 124.383 71.9004 ;
		END

		PORT
			 LAYER M4 ;
			RECT 0.2105 71.2133 124.383 71.2604 ;
		END

		PORT
			 LAYER M4 ;
			RECT 0.2105 70.5733 124.383 70.6204 ;
		END

		PORT
			 LAYER M4 ;
			RECT 0.2105 69.9333 124.383 69.9804 ;
		END

		PORT
			 LAYER M4 ;
			RECT 0.2105 69.2933 124.383 69.3404 ;
		END

		PORT
			 LAYER M4 ;
			RECT 0.2105 187.5067 124.383 187.5537 ;
		END

		PORT
			 LAYER M4 ;
			RECT 0.2105 68.6533 124.383 68.7004 ;
		END

		PORT
			 LAYER M4 ;
			RECT 0.2105 68.0133 124.383 68.0604 ;
		END

		PORT
			 LAYER M4 ;
			RECT 0.2105 67.3733 124.383 67.4204 ;
		END

		PORT
			 LAYER M4 ;
			RECT 0.2105 66.7333 124.383 66.7804 ;
		END

		PORT
			 LAYER M4 ;
			RECT 0.2105 66.0933 124.383 66.1404 ;
		END

		PORT
			 LAYER M4 ;
			RECT 0.2105 65.4533 124.383 65.5004 ;
		END

		PORT
			 LAYER M4 ;
			RECT 0.2105 64.8133 124.383 64.8604 ;
		END

		PORT
			 LAYER M4 ;
			RECT 0.2105 64.1733 124.383 64.2204 ;
		END

		PORT
			 LAYER M4 ;
			RECT 0.2105 63.5333 124.383 63.5804 ;
		END

		PORT
			 LAYER M4 ;
			RECT 0.2105 62.8933 124.383 62.9404 ;
		END

		PORT
			 LAYER M4 ;
			RECT 0.2105 186.8667 124.383 186.9137 ;
		END

		PORT
			 LAYER M4 ;
			RECT 0.2105 62.2533 124.383 62.3004 ;
		END

		PORT
			 LAYER M4 ;
			RECT 0.2105 61.6133 124.383 61.6604 ;
		END

		PORT
			 LAYER M4 ;
			RECT 0.2105 60.9733 124.383 61.0204 ;
		END

		PORT
			 LAYER M4 ;
			RECT 0.2105 60.3333 124.383 60.3804 ;
		END

		PORT
			 LAYER M4 ;
			RECT 0.2105 59.6933 124.383 59.7404 ;
		END

		PORT
			 LAYER M4 ;
			RECT 0.2105 59.0533 124.383 59.1004 ;
		END

		PORT
			 LAYER M4 ;
			RECT 0.2105 58.4133 124.383 58.4604 ;
		END

		PORT
			 LAYER M4 ;
			RECT 0.2105 57.7733 124.383 57.8204 ;
		END

		PORT
			 LAYER M4 ;
			RECT 0.2105 57.1333 124.383 57.1804 ;
		END

		PORT
			 LAYER M4 ;
			RECT 0.2105 56.4933 124.383 56.5404 ;
		END

		PORT
			 LAYER M4 ;
			RECT 0.2105 186.2267 124.383 186.2737 ;
		END

		PORT
			 LAYER M4 ;
			RECT 0.2105 55.8533 124.383 55.9004 ;
		END

		PORT
			 LAYER M4 ;
			RECT 0.2105 55.2133 124.383 55.2604 ;
		END

		PORT
			 LAYER M4 ;
			RECT 0.2105 54.5733 124.383 54.6204 ;
		END

		PORT
			 LAYER M4 ;
			RECT 0.2105 185.5867 124.383 185.6337 ;
		END

		PORT
			 LAYER M4 ;
			RECT 0.2105 46.2345 124.383 46.2816 ;
		END

		PORT
			 LAYER M4 ;
			RECT 0.2105 45.5945 124.383 45.6416 ;
		END

		PORT
			 LAYER M4 ;
			RECT 0.2105 44.9545 124.383 45.0016 ;
		END

		PORT
			 LAYER M4 ;
			RECT 0.2105 44.3145 124.383 44.3616 ;
		END

		PORT
			 LAYER M4 ;
			RECT 0.2105 43.6745 124.383 43.7216 ;
		END

		PORT
			 LAYER M4 ;
			RECT 0.2105 184.9467 124.383 184.9937 ;
		END

		PORT
			 LAYER M4 ;
			RECT 0.2105 43.0345 124.383 43.0816 ;
		END

		PORT
			 LAYER M4 ;
			RECT 0.2105 42.3945 124.383 42.4416 ;
		END

		PORT
			 LAYER M4 ;
			RECT 0.2105 41.7545 124.383 41.8016 ;
		END

		PORT
			 LAYER M4 ;
			RECT 0.2105 41.1145 124.383 41.1616 ;
		END

		PORT
			 LAYER M4 ;
			RECT 0.2105 40.4745 124.383 40.5216 ;
		END

		PORT
			 LAYER M4 ;
			RECT 0.2105 39.8345 124.383 39.8816 ;
		END

		PORT
			 LAYER M4 ;
			RECT 0.2105 39.1945 124.383 39.2416 ;
		END

		PORT
			 LAYER M4 ;
			RECT 0.2105 38.5545 124.383 38.6016 ;
		END

		PORT
			 LAYER M4 ;
			RECT 0.2105 37.9145 124.383 37.9616 ;
		END

		PORT
			 LAYER M4 ;
			RECT 0.2105 37.2745 124.383 37.3216 ;
		END

		PORT
			 LAYER M4 ;
			RECT 0.2105 184.3067 124.383 184.3537 ;
		END

		PORT
			 LAYER M4 ;
			RECT 0.2105 36.6345 124.383 36.6816 ;
		END

		PORT
			 LAYER M4 ;
			RECT 0.2105 35.9945 124.383 36.0416 ;
		END

		PORT
			 LAYER M4 ;
			RECT 0.2105 35.3545 124.383 35.4016 ;
		END

		PORT
			 LAYER M4 ;
			RECT 0.2105 34.7145 124.383 34.7616 ;
		END

		PORT
			 LAYER M4 ;
			RECT 0.2105 34.0745 124.383 34.1216 ;
		END

		PORT
			 LAYER M4 ;
			RECT 0.2105 33.4345 124.383 33.4816 ;
		END

		PORT
			 LAYER M4 ;
			RECT 0.2105 32.7945 124.383 32.8416 ;
		END

		PORT
			 LAYER M4 ;
			RECT 0.2105 32.1545 124.383 32.2016 ;
		END

		PORT
			 LAYER M4 ;
			RECT 0.2105 31.5145 124.383 31.5616 ;
		END

		PORT
			 LAYER M4 ;
			RECT 0.2105 30.8745 124.383 30.9216 ;
		END

		PORT
			 LAYER M4 ;
			RECT 0.2105 199.0267 124.383 199.0737 ;
		END

		PORT
			 LAYER M4 ;
			RECT 0.2105 183.6667 124.383 183.7137 ;
		END

		PORT
			 LAYER M4 ;
			RECT 0.2105 30.2345 124.383 30.2816 ;
		END

		PORT
			 LAYER M4 ;
			RECT 0.2105 29.5945 124.383 29.6416 ;
		END

		PORT
			 LAYER M4 ;
			RECT 0.2105 28.9545 124.383 29.0016 ;
		END

		PORT
			 LAYER M4 ;
			RECT 0.2105 28.3145 124.383 28.3616 ;
		END

		PORT
			 LAYER M4 ;
			RECT 0.2105 27.6745 124.383 27.7216 ;
		END

		PORT
			 LAYER M4 ;
			RECT 0.2105 27.0345 124.383 27.0816 ;
		END

		PORT
			 LAYER M4 ;
			RECT 0.2105 26.3945 124.383 26.4416 ;
		END

		PORT
			 LAYER M4 ;
			RECT 0.2105 25.7545 124.383 25.8016 ;
		END

		PORT
			 LAYER M4 ;
			RECT 0.2105 25.1145 124.383 25.1616 ;
		END

		PORT
			 LAYER M4 ;
			RECT 0.2105 24.4745 124.383 24.5216 ;
		END

		PORT
			 LAYER M4 ;
			RECT 0.2105 183.0267 124.383 183.0737 ;
		END

		PORT
			 LAYER M4 ;
			RECT 0.2105 23.8345 124.383 23.8816 ;
		END

		PORT
			 LAYER M4 ;
			RECT 0.2105 23.1945 124.383 23.2416 ;
		END

		PORT
			 LAYER M4 ;
			RECT 0.2105 22.5545 124.383 22.6016 ;
		END

		PORT
			 LAYER M4 ;
			RECT 0.2105 21.9145 124.383 21.9616 ;
		END

		PORT
			 LAYER M4 ;
			RECT 0.2105 21.2745 124.383 21.3216 ;
		END

		PORT
			 LAYER M4 ;
			RECT 0.2105 20.6345 124.383 20.6816 ;
		END

		PORT
			 LAYER M4 ;
			RECT 0.2105 19.9945 124.383 20.0416 ;
		END

		PORT
			 LAYER M4 ;
			RECT 0.2105 19.3545 124.383 19.4016 ;
		END

		PORT
			 LAYER M4 ;
			RECT 0.2105 18.7145 124.383 18.7616 ;
		END

		PORT
			 LAYER M4 ;
			RECT 0.2105 18.0745 124.383 18.1216 ;
		END

		PORT
			 LAYER M4 ;
			RECT 0.2105 182.3867 124.383 182.4337 ;
		END

		PORT
			 LAYER M4 ;
			RECT 0.2105 17.4345 124.383 17.4816 ;
		END

		PORT
			 LAYER M4 ;
			RECT 0.2105 16.7945 124.383 16.8416 ;
		END

		PORT
			 LAYER M4 ;
			RECT 0.2105 16.1545 124.383 16.2016 ;
		END

		PORT
			 LAYER M4 ;
			RECT 0.2105 15.5145 124.383 15.5616 ;
		END

		PORT
			 LAYER M4 ;
			RECT 0.2105 14.8745 124.383 14.9216 ;
		END

		PORT
			 LAYER M4 ;
			RECT 0.2105 14.2345 124.383 14.2816 ;
		END

		PORT
			 LAYER M4 ;
			RECT 0.2105 13.5945 124.383 13.6416 ;
		END

		PORT
			 LAYER M4 ;
			RECT 0.2105 12.9545 124.383 13.0016 ;
		END

		PORT
			 LAYER M4 ;
			RECT 0.2105 12.3145 124.383 12.3616 ;
		END

		PORT
			 LAYER M4 ;
			RECT 0.2105 11.6745 124.383 11.7216 ;
		END

		PORT
			 LAYER M4 ;
			RECT 0.2105 181.7467 124.383 181.7937 ;
		END

		PORT
			 LAYER M4 ;
			RECT 0.2105 11.0345 124.383 11.0816 ;
		END

		PORT
			 LAYER M4 ;
			RECT 0.2105 10.3945 124.383 10.4416 ;
		END

		PORT
			 LAYER M4 ;
			RECT 0.2105 9.7545 124.383 9.8016 ;
		END

		PORT
			 LAYER M4 ;
			RECT 0.2105 9.1145 124.383 9.1616 ;
		END

		PORT
			 LAYER M4 ;
			RECT 0.2105 8.4745 124.383 8.5216 ;
		END

		PORT
			 LAYER M4 ;
			RECT 0.2105 7.8345 124.383 7.8816 ;
		END

		PORT
			 LAYER M4 ;
			RECT 0.2105 7.1945 124.383 7.2416 ;
		END

		PORT
			 LAYER M4 ;
			RECT 0.2105 6.5545 124.383 6.6016 ;
		END

		PORT
			 LAYER M4 ;
			RECT 0.2105 5.9145 124.383 5.9616 ;
		END

		PORT
			 LAYER M4 ;
			RECT 0.2105 5.2745 124.383 5.3216 ;
		END

		PORT
			 LAYER M4 ;
			RECT 0.2105 181.1067 124.383 181.1537 ;
		END

		PORT
			 LAYER M4 ;
			RECT 0.2105 4.6345 124.383 4.6816 ;
		END

		PORT
			 LAYER M4 ;
			RECT 0.2105 3.9945 124.383 4.0416 ;
		END

		PORT
			 LAYER M4 ;
			RECT 0.2105 3.3545 124.383 3.4016 ;
		END

		PORT
			 LAYER M4 ;
			RECT 0.2105 2.7145 124.383 2.7616 ;
		END

		PORT
			 LAYER M4 ;
			RECT 0.2105 2.0745 124.383 2.1216 ;
		END

		PORT
			 LAYER M4 ;
			RECT 0.2105 1.4345 124.383 1.4816 ;
		END

		PORT
			 LAYER M4 ;
			RECT 0.2105 0.7945 124.383 0.8416 ;
		END

		PORT
			 LAYER M4 ;
			RECT 0.2105 180.4667 124.383 180.5137 ;
		END

		PORT
			 LAYER M4 ;
			RECT 0.2105 179.8267 124.383 179.8737 ;
		END

		PORT
			 LAYER M4 ;
			RECT 0.2105 200.4235 124.383 200.4549 ;
		END

		PORT
			 LAYER M4 ;
			RECT 0.2105 0.0533 124.383 0.0847 ;
		END

		PORT
			 LAYER M4 ;
			RECT 0.2105 153.5137 124.383 153.5608 ;
		END

		PORT
			 LAYER M4 ;
			RECT 0.2105 46.9475 124.383 46.9945 ;
		END

		PORT
			 LAYER M4 ;
			RECT 0.2105 153.222 124.383 153.269 ;
		END

		PORT
			 LAYER M4 ;
			RECT 0.2105 47.2392 124.383 47.2863 ;
		END

		PORT
			 LAYER M4 ;
			RECT 0.2105 147.2675 124.383 147.3145 ;
		END

		PORT
			 LAYER M4 ;
			RECT 0.2105 53.1937 124.383 53.2408 ;
		END

		PORT
			 LAYER M4 ;
			RECT 0.2105 146.9757 124.383 147.0227 ;
		END

		PORT
			 LAYER M4 ;
			RECT 0.2105 53.4855 124.383 53.5325 ;
		END

		PORT
			 LAYER M4 ;
			RECT 0.2105 154.0925 124.383 154.1239 ;
		END

		PORT
			 LAYER M4 ;
			RECT 0.2105 46.3843 124.383 46.4157 ;
		END

		PORT
			 LAYER M4 ;
			RECT 0.2105 146.5784 124.383 146.6098 ;
		END

		PORT
			 LAYER M4 ;
			RECT 0.2105 53.8984 124.383 53.9298 ;
		END

		PORT
			 LAYER M4 ;
			RECT 0.2105 100.3765 124.383 100.4078 ;
		END

		PORT
			 LAYER M4 ;
			RECT 0.2105 100.1004 124.383 100.1318 ;
		END

		PORT
			 LAYER M4 ;
			RECT 0.2105 200.298 124.383 200.3294 ;
		END

		PORT
			 LAYER M4 ;
			RECT 0.2105 0.1788 124.383 0.2102 ;
		END

	END VDDCE

	PIN VDDPE
		USE POWER ;
		DIRECTION INOUT ;
		PORT
			 LAYER M4 ;
			RECT 0.2105 199.8996 124.383 199.9467 ;
		END

		PORT
			 LAYER M4 ;
			RECT 0.2105 198.6196 124.383 198.6667 ;
		END

		PORT
			 LAYER M4 ;
			RECT 0.2105 179.4196 124.383 179.4667 ;
		END

		PORT
			 LAYER M4 ;
			RECT 0.2105 178.7796 124.383 178.8267 ;
		END

		PORT
			 LAYER M4 ;
			RECT 0.2105 178.1396 124.383 178.1867 ;
		END

		PORT
			 LAYER M4 ;
			RECT 0.2105 177.4996 124.383 177.5467 ;
		END

		PORT
			 LAYER M4 ;
			RECT 0.2105 176.8596 124.383 176.9067 ;
		END

		PORT
			 LAYER M4 ;
			RECT 0.2105 176.2196 124.383 176.2667 ;
		END

		PORT
			 LAYER M4 ;
			RECT 0.2105 175.5796 124.383 175.6267 ;
		END

		PORT
			 LAYER M4 ;
			RECT 0.2105 174.9396 124.383 174.9867 ;
		END

		PORT
			 LAYER M4 ;
			RECT 0.2105 174.2996 124.383 174.3467 ;
		END

		PORT
			 LAYER M4 ;
			RECT 0.2105 173.6596 124.383 173.7067 ;
		END

		PORT
			 LAYER M4 ;
			RECT 0.2105 197.9796 124.383 198.0267 ;
		END

		PORT
			 LAYER M4 ;
			RECT 0.2105 173.0196 124.383 173.0667 ;
		END

		PORT
			 LAYER M4 ;
			RECT 0.2105 172.3796 124.383 172.4267 ;
		END

		PORT
			 LAYER M4 ;
			RECT 0.2105 171.7396 124.383 171.7867 ;
		END

		PORT
			 LAYER M4 ;
			RECT 0.2105 171.0996 124.383 171.1467 ;
		END

		PORT
			 LAYER M4 ;
			RECT 0.2105 170.4596 124.383 170.5067 ;
		END

		PORT
			 LAYER M4 ;
			RECT 0.2105 169.8196 124.383 169.8667 ;
		END

		PORT
			 LAYER M4 ;
			RECT 0.2105 169.1796 124.383 169.2267 ;
		END

		PORT
			 LAYER M4 ;
			RECT 0.2105 168.5396 124.383 168.5867 ;
		END

		PORT
			 LAYER M4 ;
			RECT 0.2105 167.8996 124.383 167.9467 ;
		END

		PORT
			 LAYER M4 ;
			RECT 0.2105 167.2596 124.383 167.3067 ;
		END

		PORT
			 LAYER M4 ;
			RECT 0.2105 197.3396 124.383 197.3867 ;
		END

		PORT
			 LAYER M4 ;
			RECT 0.2105 166.6196 124.383 166.6667 ;
		END

		PORT
			 LAYER M4 ;
			RECT 0.2105 165.9796 124.383 166.0267 ;
		END

		PORT
			 LAYER M4 ;
			RECT 0.2105 165.3396 124.383 165.3867 ;
		END

		PORT
			 LAYER M4 ;
			RECT 0.2105 164.6996 124.383 164.7467 ;
		END

		PORT
			 LAYER M4 ;
			RECT 0.2105 164.0596 124.383 164.1067 ;
		END

		PORT
			 LAYER M4 ;
			RECT 0.2105 163.4196 124.383 163.4667 ;
		END

		PORT
			 LAYER M4 ;
			RECT 0.2105 162.7796 124.383 162.8267 ;
		END

		PORT
			 LAYER M4 ;
			RECT 0.2105 162.1396 124.383 162.1867 ;
		END

		PORT
			 LAYER M4 ;
			RECT 0.2105 161.4996 124.383 161.5467 ;
		END

		PORT
			 LAYER M4 ;
			RECT 0.2105 160.8596 124.383 160.9067 ;
		END

		PORT
			 LAYER M4 ;
			RECT 0.2105 196.6996 124.383 196.7467 ;
		END

		PORT
			 LAYER M4 ;
			RECT 0.2105 160.2196 124.383 160.2667 ;
		END

		PORT
			 LAYER M4 ;
			RECT 0.2105 159.5796 124.383 159.6267 ;
		END

		PORT
			 LAYER M4 ;
			RECT 0.2105 158.9396 124.383 158.9867 ;
		END

		PORT
			 LAYER M4 ;
			RECT 0.2105 158.2996 124.383 158.3467 ;
		END

		PORT
			 LAYER M4 ;
			RECT 0.2105 157.6596 124.383 157.7067 ;
		END

		PORT
			 LAYER M4 ;
			RECT 0.2105 157.0196 124.383 157.0667 ;
		END

		PORT
			 LAYER M4 ;
			RECT 0.2105 156.3796 124.383 156.4267 ;
		END

		PORT
			 LAYER M4 ;
			RECT 0.2105 155.7396 124.383 155.7867 ;
		END

		PORT
			 LAYER M4 ;
			RECT 0.2105 155.0996 124.383 155.1467 ;
		END

		PORT
			 LAYER M4 ;
			RECT 0.2105 154.4596 124.383 154.5067 ;
		END

		PORT
			 LAYER M4 ;
			RECT 0.2105 196.0596 124.383 196.1067 ;
		END

		PORT
			 LAYER M4 ;
			RECT 0.2105 195.4196 124.383 195.4667 ;
		END

		PORT
			 LAYER M4 ;
			RECT 0.2105 146.1208 124.383 146.1678 ;
		END

		PORT
			 LAYER M4 ;
			RECT 0.2105 145.4808 124.383 145.5278 ;
		END

		PORT
			 LAYER M4 ;
			RECT 0.2105 144.8408 124.383 144.8878 ;
		END

		PORT
			 LAYER M4 ;
			RECT 0.2105 144.2008 124.383 144.2478 ;
		END

		PORT
			 LAYER M4 ;
			RECT 0.2105 143.5608 124.383 143.6078 ;
		END

		PORT
			 LAYER M4 ;
			RECT 0.2105 142.9208 124.383 142.9678 ;
		END

		PORT
			 LAYER M4 ;
			RECT 0.2105 142.2808 124.383 142.3278 ;
		END

		PORT
			 LAYER M4 ;
			RECT 0.2105 141.6408 124.383 141.6878 ;
		END

		PORT
			 LAYER M4 ;
			RECT 0.2105 141.0008 124.383 141.0478 ;
		END

		PORT
			 LAYER M4 ;
			RECT 0.2105 194.7796 124.383 194.8267 ;
		END

		PORT
			 LAYER M4 ;
			RECT 0.2105 140.3608 124.383 140.4078 ;
		END

		PORT
			 LAYER M4 ;
			RECT 0.2105 139.7208 124.383 139.7678 ;
		END

		PORT
			 LAYER M4 ;
			RECT 0.2105 139.0808 124.383 139.1278 ;
		END

		PORT
			 LAYER M4 ;
			RECT 0.2105 138.4408 124.383 138.4878 ;
		END

		PORT
			 LAYER M4 ;
			RECT 0.2105 137.8008 124.383 137.8478 ;
		END

		PORT
			 LAYER M4 ;
			RECT 0.2105 137.1608 124.383 137.2078 ;
		END

		PORT
			 LAYER M4 ;
			RECT 0.2105 136.5208 124.383 136.5678 ;
		END

		PORT
			 LAYER M4 ;
			RECT 0.2105 135.8808 124.383 135.9278 ;
		END

		PORT
			 LAYER M4 ;
			RECT 0.2105 135.2408 124.383 135.2878 ;
		END

		PORT
			 LAYER M4 ;
			RECT 0.2105 134.6008 124.383 134.6478 ;
		END

		PORT
			 LAYER M4 ;
			RECT 0.2105 194.1396 124.383 194.1867 ;
		END

		PORT
			 LAYER M4 ;
			RECT 0.2105 133.9608 124.383 134.0078 ;
		END

		PORT
			 LAYER M4 ;
			RECT 0.2105 133.3208 124.383 133.3678 ;
		END

		PORT
			 LAYER M4 ;
			RECT 0.2105 132.6808 124.383 132.7278 ;
		END

		PORT
			 LAYER M4 ;
			RECT 0.2105 132.0408 124.383 132.0878 ;
		END

		PORT
			 LAYER M4 ;
			RECT 0.2105 131.4008 124.383 131.4478 ;
		END

		PORT
			 LAYER M4 ;
			RECT 0.2105 130.7608 124.383 130.8078 ;
		END

		PORT
			 LAYER M4 ;
			RECT 0.2105 130.1208 124.383 130.1678 ;
		END

		PORT
			 LAYER M4 ;
			RECT 0.2105 129.4808 124.383 129.5278 ;
		END

		PORT
			 LAYER M4 ;
			RECT 0.2105 128.8408 124.383 128.8878 ;
		END

		PORT
			 LAYER M4 ;
			RECT 0.2105 128.2008 124.383 128.2478 ;
		END

		PORT
			 LAYER M4 ;
			RECT 0.2105 193.4996 124.383 193.5467 ;
		END

		PORT
			 LAYER M4 ;
			RECT 0.2105 127.5608 124.383 127.6078 ;
		END

		PORT
			 LAYER M4 ;
			RECT 0.2105 126.9208 124.383 126.9678 ;
		END

		PORT
			 LAYER M4 ;
			RECT 0.2105 126.2808 124.383 126.3278 ;
		END

		PORT
			 LAYER M4 ;
			RECT 0.2105 125.6408 124.383 125.6878 ;
		END

		PORT
			 LAYER M4 ;
			RECT 0.2105 125.0008 124.383 125.0478 ;
		END

		PORT
			 LAYER M4 ;
			RECT 0.2105 124.3608 124.383 124.4078 ;
		END

		PORT
			 LAYER M4 ;
			RECT 0.2105 123.7208 124.383 123.7678 ;
		END

		PORT
			 LAYER M4 ;
			RECT 0.2105 123.0808 124.383 123.1278 ;
		END

		PORT
			 LAYER M4 ;
			RECT 0.2105 122.4408 124.383 122.4878 ;
		END

		PORT
			 LAYER M4 ;
			RECT 0.2105 121.8008 124.383 121.8478 ;
		END

		PORT
			 LAYER M4 ;
			RECT 0.2105 192.8596 124.383 192.9067 ;
		END

		PORT
			 LAYER M4 ;
			RECT 0.2105 121.1608 124.383 121.2078 ;
		END

		PORT
			 LAYER M4 ;
			RECT 0.2105 120.5208 124.383 120.5678 ;
		END

		PORT
			 LAYER M4 ;
			RECT 0.2105 119.8808 124.383 119.9278 ;
		END

		PORT
			 LAYER M4 ;
			RECT 0.2105 119.2408 124.383 119.2878 ;
		END

		PORT
			 LAYER M4 ;
			RECT 0.2105 118.6008 124.383 118.6478 ;
		END

		PORT
			 LAYER M4 ;
			RECT 0.2105 117.9608 124.383 118.0078 ;
		END

		PORT
			 LAYER M4 ;
			RECT 0.2105 117.3208 124.383 117.3678 ;
		END

		PORT
			 LAYER M4 ;
			RECT 0.2105 116.6808 124.383 116.7278 ;
		END

		PORT
			 LAYER M4 ;
			RECT 0.2105 116.0408 124.383 116.0878 ;
		END

		PORT
			 LAYER M4 ;
			RECT 0.2105 115.4008 124.383 115.4478 ;
		END

		PORT
			 LAYER M4 ;
			RECT 0.2105 192.2196 124.383 192.2667 ;
		END

		PORT
			 LAYER M4 ;
			RECT 0.2105 114.7608 124.383 114.8078 ;
		END

		PORT
			 LAYER M4 ;
			RECT 0.2105 114.1208 124.383 114.1678 ;
		END

		PORT
			 LAYER M4 ;
			RECT 0.2105 113.4808 124.383 113.5278 ;
		END

		PORT
			 LAYER M4 ;
			RECT 0.2105 112.8408 124.383 112.8878 ;
		END

		PORT
			 LAYER M4 ;
			RECT 0.2105 112.2008 124.383 112.2478 ;
		END

		PORT
			 LAYER M4 ;
			RECT 0.2105 111.5608 124.383 111.6078 ;
		END

		PORT
			 LAYER M4 ;
			RECT 0.2105 110.9208 124.383 110.9678 ;
		END

		PORT
			 LAYER M4 ;
			RECT 0.2105 110.2808 124.383 110.3278 ;
		END

		PORT
			 LAYER M4 ;
			RECT 0.2105 109.6408 124.383 109.6878 ;
		END

		PORT
			 LAYER M4 ;
			RECT 0.2105 109.0008 124.383 109.0478 ;
		END

		PORT
			 LAYER M4 ;
			RECT 0.2105 191.5796 124.383 191.6267 ;
		END

		PORT
			 LAYER M4 ;
			RECT 0.2105 108.3608 124.383 108.4078 ;
		END

		PORT
			 LAYER M4 ;
			RECT 0.2105 107.7208 124.383 107.7678 ;
		END

		PORT
			 LAYER M4 ;
			RECT 0.2105 107.0808 124.383 107.1278 ;
		END

		PORT
			 LAYER M4 ;
			RECT 0.2105 106.4408 124.383 106.4878 ;
		END

		PORT
			 LAYER M4 ;
			RECT 0.2105 105.8008 124.383 105.8478 ;
		END

		PORT
			 LAYER M4 ;
			RECT 0.2105 105.1608 124.383 105.2078 ;
		END

		PORT
			 LAYER M4 ;
			RECT 0.2105 104.5208 124.383 104.5678 ;
		END

		PORT
			 LAYER M4 ;
			RECT 0.2105 103.8808 124.383 103.9278 ;
		END

		PORT
			 LAYER M4 ;
			RECT 0.2105 103.2408 124.383 103.2878 ;
		END

		PORT
			 LAYER M4 ;
			RECT 0.2105 102.6008 124.383 102.6478 ;
		END

		PORT
			 LAYER M4 ;
			RECT 0.2105 190.9396 124.383 190.9867 ;
		END

		PORT
			 LAYER M4 ;
			RECT 0.2105 101.9608 124.383 102.0078 ;
		END

		PORT
			 LAYER M4 ;
			RECT 0.2105 101.3208 124.383 101.3678 ;
		END

		PORT
			 LAYER M4 ;
			RECT 0.2105 100.6808 124.383 100.7278 ;
		END

		PORT
			 LAYER M4 ;
			RECT 0.2105 99.7804 124.383 99.8275 ;
		END

		PORT
			 LAYER M4 ;
			RECT 0.2105 99.1404 124.383 99.1875 ;
		END

		PORT
			 LAYER M4 ;
			RECT 0.2105 98.5004 124.383 98.5475 ;
		END

		PORT
			 LAYER M4 ;
			RECT 0.2105 97.8604 124.383 97.9075 ;
		END

		PORT
			 LAYER M4 ;
			RECT 0.2105 97.2204 124.383 97.2675 ;
		END

		PORT
			 LAYER M4 ;
			RECT 0.2105 190.2996 124.383 190.3467 ;
		END

		PORT
			 LAYER M4 ;
			RECT 0.2105 96.5804 124.383 96.6275 ;
		END

		PORT
			 LAYER M4 ;
			RECT 0.2105 95.9404 124.383 95.9875 ;
		END

		PORT
			 LAYER M4 ;
			RECT 0.2105 95.3004 124.383 95.3475 ;
		END

		PORT
			 LAYER M4 ;
			RECT 0.2105 94.6604 124.383 94.7075 ;
		END

		PORT
			 LAYER M4 ;
			RECT 0.2105 94.0204 124.383 94.0675 ;
		END

		PORT
			 LAYER M4 ;
			RECT 0.2105 93.3804 124.383 93.4275 ;
		END

		PORT
			 LAYER M4 ;
			RECT 0.2105 92.7404 124.383 92.7875 ;
		END

		PORT
			 LAYER M4 ;
			RECT 0.2105 92.1004 124.383 92.1475 ;
		END

		PORT
			 LAYER M4 ;
			RECT 0.2105 91.4604 124.383 91.5075 ;
		END

		PORT
			 LAYER M4 ;
			RECT 0.2105 90.8204 124.383 90.8675 ;
		END

		PORT
			 LAYER M4 ;
			RECT 0.2105 189.6596 124.383 189.7067 ;
		END

		PORT
			 LAYER M4 ;
			RECT 0.2105 90.1804 124.383 90.2275 ;
		END

		PORT
			 LAYER M4 ;
			RECT 0.2105 89.5404 124.383 89.5875 ;
		END

		PORT
			 LAYER M4 ;
			RECT 0.2105 88.9004 124.383 88.9475 ;
		END

		PORT
			 LAYER M4 ;
			RECT 0.2105 88.2604 124.383 88.3075 ;
		END

		PORT
			 LAYER M4 ;
			RECT 0.2105 87.6204 124.383 87.6675 ;
		END

		PORT
			 LAYER M4 ;
			RECT 0.2105 86.9804 124.383 87.0275 ;
		END

		PORT
			 LAYER M4 ;
			RECT 0.2105 86.3404 124.383 86.3875 ;
		END

		PORT
			 LAYER M4 ;
			RECT 0.2105 85.7004 124.383 85.7475 ;
		END

		PORT
			 LAYER M4 ;
			RECT 0.2105 85.0604 124.383 85.1075 ;
		END

		PORT
			 LAYER M4 ;
			RECT 0.2105 84.4204 124.383 84.4675 ;
		END

		PORT
			 LAYER M4 ;
			RECT 0.2105 189.0196 124.383 189.0667 ;
		END

		PORT
			 LAYER M4 ;
			RECT 0.2105 83.7804 124.383 83.8275 ;
		END

		PORT
			 LAYER M4 ;
			RECT 0.2105 83.1404 124.383 83.1875 ;
		END

		PORT
			 LAYER M4 ;
			RECT 0.2105 82.5004 124.383 82.5475 ;
		END

		PORT
			 LAYER M4 ;
			RECT 0.2105 81.8604 124.383 81.9075 ;
		END

		PORT
			 LAYER M4 ;
			RECT 0.2105 81.2204 124.383 81.2675 ;
		END

		PORT
			 LAYER M4 ;
			RECT 0.2105 80.5804 124.383 80.6275 ;
		END

		PORT
			 LAYER M4 ;
			RECT 0.2105 79.9404 124.383 79.9875 ;
		END

		PORT
			 LAYER M4 ;
			RECT 0.2105 79.3004 124.383 79.3475 ;
		END

		PORT
			 LAYER M4 ;
			RECT 0.2105 78.6604 124.383 78.7075 ;
		END

		PORT
			 LAYER M4 ;
			RECT 0.2105 78.0204 124.383 78.0675 ;
		END

		PORT
			 LAYER M4 ;
			RECT 0.2105 188.3796 124.383 188.4267 ;
		END

		PORT
			 LAYER M4 ;
			RECT 0.2105 77.3804 124.383 77.4275 ;
		END

		PORT
			 LAYER M4 ;
			RECT 0.2105 76.7404 124.383 76.7875 ;
		END

		PORT
			 LAYER M4 ;
			RECT 0.2105 76.1004 124.383 76.1475 ;
		END

		PORT
			 LAYER M4 ;
			RECT 0.2105 75.4604 124.383 75.5075 ;
		END

		PORT
			 LAYER M4 ;
			RECT 0.2105 74.8204 124.383 74.8675 ;
		END

		PORT
			 LAYER M4 ;
			RECT 0.2105 74.1804 124.383 74.2275 ;
		END

		PORT
			 LAYER M4 ;
			RECT 0.2105 73.5404 124.383 73.5875 ;
		END

		PORT
			 LAYER M4 ;
			RECT 0.2105 72.9004 124.383 72.9475 ;
		END

		PORT
			 LAYER M4 ;
			RECT 0.2105 72.2604 124.383 72.3075 ;
		END

		PORT
			 LAYER M4 ;
			RECT 0.2105 71.6204 124.383 71.6675 ;
		END

		PORT
			 LAYER M4 ;
			RECT 0.2105 187.7396 124.383 187.7867 ;
		END

		PORT
			 LAYER M4 ;
			RECT 0.2105 70.9804 124.383 71.0275 ;
		END

		PORT
			 LAYER M4 ;
			RECT 0.2105 70.3404 124.383 70.3875 ;
		END

		PORT
			 LAYER M4 ;
			RECT 0.2105 69.7004 124.383 69.7475 ;
		END

		PORT
			 LAYER M4 ;
			RECT 0.2105 69.0604 124.383 69.1075 ;
		END

		PORT
			 LAYER M4 ;
			RECT 0.2105 68.4204 124.383 68.4675 ;
		END

		PORT
			 LAYER M4 ;
			RECT 0.2105 67.7804 124.383 67.8275 ;
		END

		PORT
			 LAYER M4 ;
			RECT 0.2105 67.1404 124.383 67.1875 ;
		END

		PORT
			 LAYER M4 ;
			RECT 0.2105 66.5004 124.383 66.5475 ;
		END

		PORT
			 LAYER M4 ;
			RECT 0.2105 65.8604 124.383 65.9075 ;
		END

		PORT
			 LAYER M4 ;
			RECT 0.2105 65.2204 124.383 65.2675 ;
		END

		PORT
			 LAYER M4 ;
			RECT 0.2105 187.0996 124.383 187.1467 ;
		END

		PORT
			 LAYER M4 ;
			RECT 0.2105 64.5804 124.383 64.6275 ;
		END

		PORT
			 LAYER M4 ;
			RECT 0.2105 63.9404 124.383 63.9875 ;
		END

		PORT
			 LAYER M4 ;
			RECT 0.2105 63.3004 124.383 63.3475 ;
		END

		PORT
			 LAYER M4 ;
			RECT 0.2105 62.6604 124.383 62.7075 ;
		END

		PORT
			 LAYER M4 ;
			RECT 0.2105 62.0204 124.383 62.0675 ;
		END

		PORT
			 LAYER M4 ;
			RECT 0.2105 61.3804 124.383 61.4275 ;
		END

		PORT
			 LAYER M4 ;
			RECT 0.2105 60.7404 124.383 60.7875 ;
		END

		PORT
			 LAYER M4 ;
			RECT 0.2105 60.1004 124.383 60.1475 ;
		END

		PORT
			 LAYER M4 ;
			RECT 0.2105 59.4604 124.383 59.5075 ;
		END

		PORT
			 LAYER M4 ;
			RECT 0.2105 58.8204 124.383 58.8675 ;
		END

		PORT
			 LAYER M4 ;
			RECT 0.2105 186.4596 124.383 186.5067 ;
		END

		PORT
			 LAYER M4 ;
			RECT 0.2105 58.1804 124.383 58.2275 ;
		END

		PORT
			 LAYER M4 ;
			RECT 0.2105 57.5404 124.383 57.5875 ;
		END

		PORT
			 LAYER M4 ;
			RECT 0.2105 56.9004 124.383 56.9475 ;
		END

		PORT
			 LAYER M4 ;
			RECT 0.2105 56.2604 124.383 56.3075 ;
		END

		PORT
			 LAYER M4 ;
			RECT 0.2105 55.6204 124.383 55.6675 ;
		END

		PORT
			 LAYER M4 ;
			RECT 0.2105 54.9804 124.383 55.0275 ;
		END

		PORT
			 LAYER M4 ;
			RECT 0.2105 54.3404 124.383 54.3875 ;
		END

		PORT
			 LAYER M4 ;
			RECT 0.2105 199.2596 124.383 199.3067 ;
		END

		PORT
			 LAYER M4 ;
			RECT 0.2105 185.8196 124.383 185.8667 ;
		END

		PORT
			 LAYER M4 ;
			RECT 0.2105 46.0016 124.383 46.0486 ;
		END

		PORT
			 LAYER M4 ;
			RECT 0.2105 185.1796 124.383 185.2267 ;
		END

		PORT
			 LAYER M4 ;
			RECT 0.2105 45.3616 124.383 45.4086 ;
		END

		PORT
			 LAYER M4 ;
			RECT 0.2105 44.7216 124.383 44.7686 ;
		END

		PORT
			 LAYER M4 ;
			RECT 0.2105 44.0816 124.383 44.1286 ;
		END

		PORT
			 LAYER M4 ;
			RECT 0.2105 43.4416 124.383 43.4886 ;
		END

		PORT
			 LAYER M4 ;
			RECT 0.2105 42.8016 124.383 42.8486 ;
		END

		PORT
			 LAYER M4 ;
			RECT 0.2105 42.1616 124.383 42.2086 ;
		END

		PORT
			 LAYER M4 ;
			RECT 0.2105 41.5216 124.383 41.5686 ;
		END

		PORT
			 LAYER M4 ;
			RECT 0.2105 40.8816 124.383 40.9286 ;
		END

		PORT
			 LAYER M4 ;
			RECT 0.2105 40.2416 124.383 40.2886 ;
		END

		PORT
			 LAYER M4 ;
			RECT 0.2105 39.6016 124.383 39.6486 ;
		END

		PORT
			 LAYER M4 ;
			RECT 0.2105 184.5396 124.383 184.5867 ;
		END

		PORT
			 LAYER M4 ;
			RECT 0.2105 38.9616 124.383 39.0086 ;
		END

		PORT
			 LAYER M4 ;
			RECT 0.2105 38.3216 124.383 38.3686 ;
		END

		PORT
			 LAYER M4 ;
			RECT 0.2105 37.6816 124.383 37.7286 ;
		END

		PORT
			 LAYER M4 ;
			RECT 0.2105 37.0416 124.383 37.0886 ;
		END

		PORT
			 LAYER M4 ;
			RECT 0.2105 36.4016 124.383 36.4486 ;
		END

		PORT
			 LAYER M4 ;
			RECT 0.2105 35.7616 124.383 35.8086 ;
		END

		PORT
			 LAYER M4 ;
			RECT 0.2105 35.1216 124.383 35.1686 ;
		END

		PORT
			 LAYER M4 ;
			RECT 0.2105 34.4816 124.383 34.5286 ;
		END

		PORT
			 LAYER M4 ;
			RECT 0.2105 33.8416 124.383 33.8886 ;
		END

		PORT
			 LAYER M4 ;
			RECT 0.2105 33.2016 124.383 33.2486 ;
		END

		PORT
			 LAYER M4 ;
			RECT 0.2105 183.8996 124.383 183.9467 ;
		END

		PORT
			 LAYER M4 ;
			RECT 0.2105 32.5616 124.383 32.6086 ;
		END

		PORT
			 LAYER M4 ;
			RECT 0.2105 31.9216 124.383 31.9686 ;
		END

		PORT
			 LAYER M4 ;
			RECT 0.2105 31.2816 124.383 31.3286 ;
		END

		PORT
			 LAYER M4 ;
			RECT 0.2105 30.6416 124.383 30.6886 ;
		END

		PORT
			 LAYER M4 ;
			RECT 0.2105 30.0016 124.383 30.0486 ;
		END

		PORT
			 LAYER M4 ;
			RECT 0.2105 29.3616 124.383 29.4086 ;
		END

		PORT
			 LAYER M4 ;
			RECT 0.2105 28.7216 124.383 28.7686 ;
		END

		PORT
			 LAYER M4 ;
			RECT 0.2105 28.0816 124.383 28.1286 ;
		END

		PORT
			 LAYER M4 ;
			RECT 0.2105 27.4416 124.383 27.4886 ;
		END

		PORT
			 LAYER M4 ;
			RECT 0.2105 26.8016 124.383 26.8486 ;
		END

		PORT
			 LAYER M4 ;
			RECT 0.2105 183.2596 124.383 183.3067 ;
		END

		PORT
			 LAYER M4 ;
			RECT 0.2105 26.1616 124.383 26.2086 ;
		END

		PORT
			 LAYER M4 ;
			RECT 0.2105 25.5216 124.383 25.5686 ;
		END

		PORT
			 LAYER M4 ;
			RECT 0.2105 24.8816 124.383 24.9286 ;
		END

		PORT
			 LAYER M4 ;
			RECT 0.2105 24.2416 124.383 24.2886 ;
		END

		PORT
			 LAYER M4 ;
			RECT 0.2105 23.6016 124.383 23.6486 ;
		END

		PORT
			 LAYER M4 ;
			RECT 0.2105 22.9616 124.383 23.0086 ;
		END

		PORT
			 LAYER M4 ;
			RECT 0.2105 22.3216 124.383 22.3686 ;
		END

		PORT
			 LAYER M4 ;
			RECT 0.2105 21.6816 124.383 21.7286 ;
		END

		PORT
			 LAYER M4 ;
			RECT 0.2105 21.0416 124.383 21.0886 ;
		END

		PORT
			 LAYER M4 ;
			RECT 0.2105 20.4016 124.383 20.4486 ;
		END

		PORT
			 LAYER M4 ;
			RECT 0.2105 182.6196 124.383 182.6667 ;
		END

		PORT
			 LAYER M4 ;
			RECT 0.2105 19.7616 124.383 19.8086 ;
		END

		PORT
			 LAYER M4 ;
			RECT 0.2105 19.1216 124.383 19.1686 ;
		END

		PORT
			 LAYER M4 ;
			RECT 0.2105 18.4816 124.383 18.5286 ;
		END

		PORT
			 LAYER M4 ;
			RECT 0.2105 17.8416 124.383 17.8886 ;
		END

		PORT
			 LAYER M4 ;
			RECT 0.2105 17.2016 124.383 17.2486 ;
		END

		PORT
			 LAYER M4 ;
			RECT 0.2105 16.5616 124.383 16.6086 ;
		END

		PORT
			 LAYER M4 ;
			RECT 0.2105 15.9216 124.383 15.9686 ;
		END

		PORT
			 LAYER M4 ;
			RECT 0.2105 15.2816 124.383 15.3286 ;
		END

		PORT
			 LAYER M4 ;
			RECT 0.2105 14.6416 124.383 14.6886 ;
		END

		PORT
			 LAYER M4 ;
			RECT 0.2105 14.0016 124.383 14.0486 ;
		END

		PORT
			 LAYER M4 ;
			RECT 0.2105 181.9796 124.383 182.0267 ;
		END

		PORT
			 LAYER M4 ;
			RECT 0.2105 13.3616 124.383 13.4086 ;
		END

		PORT
			 LAYER M4 ;
			RECT 0.2105 12.7216 124.383 12.7686 ;
		END

		PORT
			 LAYER M4 ;
			RECT 0.2105 12.0816 124.383 12.1286 ;
		END

		PORT
			 LAYER M4 ;
			RECT 0.2105 11.4416 124.383 11.4886 ;
		END

		PORT
			 LAYER M4 ;
			RECT 0.2105 10.8016 124.383 10.8486 ;
		END

		PORT
			 LAYER M4 ;
			RECT 0.2105 10.1616 124.383 10.2086 ;
		END

		PORT
			 LAYER M4 ;
			RECT 0.2105 9.5216 124.383 9.5686 ;
		END

		PORT
			 LAYER M4 ;
			RECT 0.2105 8.8816 124.383 8.9286 ;
		END

		PORT
			 LAYER M4 ;
			RECT 0.2105 8.2416 124.383 8.2886 ;
		END

		PORT
			 LAYER M4 ;
			RECT 0.2105 7.6016 124.383 7.6486 ;
		END

		PORT
			 LAYER M4 ;
			RECT 0.2105 181.3396 124.383 181.3867 ;
		END

		PORT
			 LAYER M4 ;
			RECT 0.2105 6.9616 124.383 7.0086 ;
		END

		PORT
			 LAYER M4 ;
			RECT 0.2105 6.3216 124.383 6.3686 ;
		END

		PORT
			 LAYER M4 ;
			RECT 0.2105 5.6816 124.383 5.7286 ;
		END

		PORT
			 LAYER M4 ;
			RECT 0.2105 5.0416 124.383 5.0886 ;
		END

		PORT
			 LAYER M4 ;
			RECT 0.2105 4.4016 124.383 4.4486 ;
		END

		PORT
			 LAYER M4 ;
			RECT 0.2105 3.7616 124.383 3.8086 ;
		END

		PORT
			 LAYER M4 ;
			RECT 0.2105 3.1216 124.383 3.1686 ;
		END

		PORT
			 LAYER M4 ;
			RECT 0.2105 2.4816 124.383 2.5286 ;
		END

		PORT
			 LAYER M4 ;
			RECT 0.2105 1.8416 124.383 1.8886 ;
		END

		PORT
			 LAYER M4 ;
			RECT 0.2105 1.2016 124.383 1.2486 ;
		END

		PORT
			 LAYER M4 ;
			RECT 0.2105 180.6996 124.383 180.7467 ;
		END

		PORT
			 LAYER M4 ;
			RECT 0.2105 0.5616 124.383 0.6086 ;
		END

		PORT
			 LAYER M4 ;
			RECT 0.2105 180.0596 124.383 180.1067 ;
		END

		PORT
			 LAYER M4 ;
			RECT 0.2105 153.8729 124.383 153.92 ;
		END

		PORT
			 LAYER M4 ;
			RECT 0.2105 46.5882 124.383 46.6353 ;
		END

		PORT
			 LAYER M4 ;
			RECT 0.2105 153.4353 124.383 153.4824 ;
		END

		PORT
			 LAYER M4 ;
			RECT 0.2105 47.0259 124.383 47.0729 ;
		END

		PORT
			 LAYER M4 ;
			RECT 0.2105 153.1435 124.383 153.1906 ;
		END

		PORT
			 LAYER M4 ;
			RECT 0.2105 47.3176 124.383 47.3647 ;
		END

		PORT
			 LAYER M4 ;
			RECT 0.2105 152.6165 124.383 152.6635 ;
		END

		PORT
			 LAYER M4 ;
			RECT 0.2105 47.8447 124.383 47.8918 ;
		END

		PORT
			 LAYER M4 ;
			RECT 0.2105 152.0894 124.383 152.1365 ;
		END

		PORT
			 LAYER M4 ;
			RECT 0.2105 48.3718 124.383 48.4188 ;
		END

		PORT
			 LAYER M4 ;
			RECT 0.2105 151.5624 124.383 151.6094 ;
		END

		PORT
			 LAYER M4 ;
			RECT 0.2105 48.8988 124.383 48.9459 ;
		END

		PORT
			 LAYER M4 ;
			RECT 0.2105 151.0353 124.383 151.0824 ;
		END

		PORT
			 LAYER M4 ;
			RECT 0.2105 49.4259 124.383 49.4729 ;
		END

		PORT
			 LAYER M4 ;
			RECT 0.2105 149.9812 124.383 150.0282 ;
		END

		PORT
			 LAYER M4 ;
			RECT 0.2105 50.48 124.383 50.5271 ;
		END

		PORT
			 LAYER M4 ;
			RECT 0.2105 148.9271 124.383 148.9741 ;
		END

		PORT
			 LAYER M4 ;
			RECT 0.2105 51.5341 124.383 51.5812 ;
		END

		PORT
			 LAYER M4 ;
			RECT 0.2105 148.4 124.383 148.4471 ;
		END

		PORT
			 LAYER M4 ;
			RECT 0.2105 52.0612 124.383 52.1082 ;
		END

		PORT
			 LAYER M4 ;
			RECT 0.2105 147.8729 124.383 147.92 ;
		END

		PORT
			 LAYER M4 ;
			RECT 0.2105 52.5882 124.383 52.6353 ;
		END

		PORT
			 LAYER M4 ;
			RECT 0.2105 147.3459 124.383 147.3929 ;
		END

		PORT
			 LAYER M4 ;
			RECT 0.2105 53.1153 124.383 53.1624 ;
		END

		PORT
			 LAYER M4 ;
			RECT 0.2105 147.0541 124.383 147.1012 ;
		END

		PORT
			 LAYER M4 ;
			RECT 0.2105 53.4071 124.383 53.4541 ;
		END

		PORT
			 LAYER M4 ;
			RECT 0.2105 154.0298 124.383 154.0612 ;
		END

		PORT
			 LAYER M4 ;
			RECT 0.2105 46.4471 124.383 46.4784 ;
		END

		PORT
			 LAYER M4 ;
			RECT 0.2105 146.6412 124.383 146.6725 ;
		END

		PORT
			 LAYER M4 ;
			RECT 0.2105 53.8357 124.383 53.8671 ;
		END

		PORT
			 LAYER M4 ;
			RECT 0.2105 100.2384 124.383 100.2698 ;
		END

	END VDDPE

	PIN VSSE
		USE GROUND ;
		DIRECTION INOUT ;
		PORT
			 LAYER M4 ;
			RECT 0.2105 154.1553 124.383 154.1867 ;
		END

		PORT
			 LAYER M4 ;
			RECT 0.2105 46.3216 124.383 46.3529 ;
		END

		PORT
			 LAYER M4 ;
			RECT 0.2105 146.5157 124.383 146.5471 ;
		END

		PORT
			 LAYER M4 ;
			RECT 0.2105 53.9612 124.383 53.9925 ;
		END

		PORT
			 LAYER M4 ;
			RECT 0.2105 200.3608 124.383 200.3922 ;
		END

		PORT
			 LAYER M4 ;
			RECT 0.2105 0.1161 124.383 0.1475 ;
		END

		PORT
			 LAYER M4 ;
			RECT 0.2105 100.3137 124.383 100.3451 ;
		END

		PORT
			 LAYER M4 ;
			RECT 0.2105 100.1631 124.383 100.1945 ;
		END

		PORT
			 LAYER M4 ;
			RECT 0.2105 147.189 124.383 147.2361 ;
		END

		PORT
			 LAYER M4 ;
			RECT 0.2105 53.2722 124.383 53.3192 ;
		END

		PORT
			 LAYER M4 ;
			RECT 0.2105 153.9514 124.383 153.9984 ;
		END

		PORT
			 LAYER M4 ;
			RECT 0.2105 46.5098 124.383 46.5569 ;
		END

		PORT
			 LAYER M4 ;
			RECT 0.2105 153.3004 124.383 153.3475 ;
		END

		PORT
			 LAYER M4 ;
			RECT 0.2105 47.1608 124.383 47.2078 ;
		END

		PORT
			 LAYER M4 ;
			RECT 0.2105 152.6949 124.383 152.742 ;
		END

		PORT
			 LAYER M4 ;
			RECT 0.2105 47.7663 124.383 47.8133 ;
		END

		PORT
			 LAYER M4 ;
			RECT 0.2105 152.1678 124.383 152.2149 ;
		END

		PORT
			 LAYER M4 ;
			RECT 0.2105 48.2933 124.383 48.3404 ;
		END

		PORT
			 LAYER M4 ;
			RECT 0.2105 151.6408 124.383 151.6878 ;
		END

		PORT
			 LAYER M4 ;
			RECT 0.2105 48.8204 124.383 48.8675 ;
		END

		PORT
			 LAYER M4 ;
			RECT 0.2105 151.1137 124.383 151.1608 ;
		END

		PORT
			 LAYER M4 ;
			RECT 0.2105 49.3475 124.383 49.3945 ;
		END

		PORT
			 LAYER M4 ;
			RECT 0.2105 150.0596 124.383 150.1067 ;
		END

		PORT
			 LAYER M4 ;
			RECT 0.2105 50.4016 124.383 50.4486 ;
		END

		PORT
			 LAYER M4 ;
			RECT 0.2105 149.0055 124.383 149.0525 ;
		END

		PORT
			 LAYER M4 ;
			RECT 0.2105 51.4557 124.383 51.5027 ;
		END

		PORT
			 LAYER M4 ;
			RECT 0.2105 148.4784 124.383 148.5255 ;
		END

		PORT
			 LAYER M4 ;
			RECT 0.2105 51.9827 124.383 52.0298 ;
		END

		PORT
			 LAYER M4 ;
			RECT 0.2105 147.9514 124.383 147.9984 ;
		END

		PORT
			 LAYER M4 ;
			RECT 0.2105 52.5098 124.383 52.5569 ;
		END

		PORT
			 LAYER M4 ;
			RECT 0.2105 147.4243 124.383 147.4714 ;
		END

		PORT
			 LAYER M4 ;
			RECT 0.2105 53.0369 124.383 53.0839 ;
		END

		PORT
			 LAYER M4 ;
			RECT 0.2105 200.211 124.383 200.258 ;
		END

		PORT
			 LAYER M4 ;
			RECT 0.2105 179.091 124.383 179.138 ;
		END

		PORT
			 LAYER M4 ;
			RECT 0.2105 178.451 124.383 178.498 ;
		END

		PORT
			 LAYER M4 ;
			RECT 0.2105 177.811 124.383 177.858 ;
		END

		PORT
			 LAYER M4 ;
			RECT 0.2105 177.171 124.383 177.218 ;
		END

		PORT
			 LAYER M4 ;
			RECT 0.2105 176.531 124.383 176.578 ;
		END

		PORT
			 LAYER M4 ;
			RECT 0.2105 175.891 124.383 175.938 ;
		END

		PORT
			 LAYER M4 ;
			RECT 0.2105 198.291 124.383 198.338 ;
		END

		PORT
			 LAYER M4 ;
			RECT 0.2105 175.251 124.383 175.298 ;
		END

		PORT
			 LAYER M4 ;
			RECT 0.2105 174.611 124.383 174.658 ;
		END

		PORT
			 LAYER M4 ;
			RECT 0.2105 173.971 124.383 174.018 ;
		END

		PORT
			 LAYER M4 ;
			RECT 0.2105 173.331 124.383 173.378 ;
		END

		PORT
			 LAYER M4 ;
			RECT 0.2105 172.691 124.383 172.738 ;
		END

		PORT
			 LAYER M4 ;
			RECT 0.2105 172.051 124.383 172.098 ;
		END

		PORT
			 LAYER M4 ;
			RECT 0.2105 171.411 124.383 171.458 ;
		END

		PORT
			 LAYER M4 ;
			RECT 0.2105 170.771 124.383 170.818 ;
		END

		PORT
			 LAYER M4 ;
			RECT 0.2105 170.131 124.383 170.178 ;
		END

		PORT
			 LAYER M4 ;
			RECT 0.2105 169.491 124.383 169.538 ;
		END

		PORT
			 LAYER M4 ;
			RECT 0.2105 197.651 124.383 197.698 ;
		END

		PORT
			 LAYER M4 ;
			RECT 0.2105 168.851 124.383 168.898 ;
		END

		PORT
			 LAYER M4 ;
			RECT 0.2105 168.211 124.383 168.258 ;
		END

		PORT
			 LAYER M4 ;
			RECT 0.2105 167.571 124.383 167.618 ;
		END

		PORT
			 LAYER M4 ;
			RECT 0.2105 166.931 124.383 166.978 ;
		END

		PORT
			 LAYER M4 ;
			RECT 0.2105 166.291 124.383 166.338 ;
		END

		PORT
			 LAYER M4 ;
			RECT 0.2105 165.651 124.383 165.698 ;
		END

		PORT
			 LAYER M4 ;
			RECT 0.2105 165.011 124.383 165.058 ;
		END

		PORT
			 LAYER M4 ;
			RECT 0.2105 164.371 124.383 164.418 ;
		END

		PORT
			 LAYER M4 ;
			RECT 0.2105 163.731 124.383 163.778 ;
		END

		PORT
			 LAYER M4 ;
			RECT 0.2105 163.091 124.383 163.138 ;
		END

		PORT
			 LAYER M4 ;
			RECT 0.2105 197.011 124.383 197.058 ;
		END

		PORT
			 LAYER M4 ;
			RECT 0.2105 162.451 124.383 162.498 ;
		END

		PORT
			 LAYER M4 ;
			RECT 0.2105 161.811 124.383 161.858 ;
		END

		PORT
			 LAYER M4 ;
			RECT 0.2105 161.171 124.383 161.218 ;
		END

		PORT
			 LAYER M4 ;
			RECT 0.2105 160.531 124.383 160.578 ;
		END

		PORT
			 LAYER M4 ;
			RECT 0.2105 159.891 124.383 159.938 ;
		END

		PORT
			 LAYER M4 ;
			RECT 0.2105 159.251 124.383 159.298 ;
		END

		PORT
			 LAYER M4 ;
			RECT 0.2105 158.611 124.383 158.658 ;
		END

		PORT
			 LAYER M4 ;
			RECT 0.2105 157.971 124.383 158.018 ;
		END

		PORT
			 LAYER M4 ;
			RECT 0.2105 157.331 124.383 157.378 ;
		END

		PORT
			 LAYER M4 ;
			RECT 0.2105 156.691 124.383 156.738 ;
		END

		PORT
			 LAYER M4 ;
			RECT 0.2105 196.371 124.383 196.418 ;
		END

		PORT
			 LAYER M4 ;
			RECT 0.2105 156.051 124.383 156.098 ;
		END

		PORT
			 LAYER M4 ;
			RECT 0.2105 155.411 124.383 155.458 ;
		END

		PORT
			 LAYER M4 ;
			RECT 0.2105 154.771 124.383 154.818 ;
		END

		PORT
			 LAYER M4 ;
			RECT 0.2105 195.731 124.383 195.778 ;
		END

		PORT
			 LAYER M4 ;
			RECT 0.2105 146.4322 124.383 146.4792 ;
		END

		PORT
			 LAYER M4 ;
			RECT 0.2105 145.7922 124.383 145.8392 ;
		END

		PORT
			 LAYER M4 ;
			RECT 0.2105 145.1522 124.383 145.1992 ;
		END

		PORT
			 LAYER M4 ;
			RECT 0.2105 144.5122 124.383 144.5592 ;
		END

		PORT
			 LAYER M4 ;
			RECT 0.2105 143.8722 124.383 143.9192 ;
		END

		PORT
			 LAYER M4 ;
			RECT 0.2105 143.2322 124.383 143.2792 ;
		END

		PORT
			 LAYER M4 ;
			RECT 0.2105 195.091 124.383 195.138 ;
		END

		PORT
			 LAYER M4 ;
			RECT 0.2105 142.5922 124.383 142.6392 ;
		END

		PORT
			 LAYER M4 ;
			RECT 0.2105 141.9522 124.383 141.9992 ;
		END

		PORT
			 LAYER M4 ;
			RECT 0.2105 141.3122 124.383 141.3592 ;
		END

		PORT
			 LAYER M4 ;
			RECT 0.2105 140.6722 124.383 140.7192 ;
		END

		PORT
			 LAYER M4 ;
			RECT 0.2105 140.0322 124.383 140.0792 ;
		END

		PORT
			 LAYER M4 ;
			RECT 0.2105 139.3922 124.383 139.4392 ;
		END

		PORT
			 LAYER M4 ;
			RECT 0.2105 138.7522 124.383 138.7992 ;
		END

		PORT
			 LAYER M4 ;
			RECT 0.2105 138.1122 124.383 138.1592 ;
		END

		PORT
			 LAYER M4 ;
			RECT 0.2105 137.4722 124.383 137.5192 ;
		END

		PORT
			 LAYER M4 ;
			RECT 0.2105 136.8322 124.383 136.8792 ;
		END

		PORT
			 LAYER M4 ;
			RECT 0.2105 194.451 124.383 194.498 ;
		END

		PORT
			 LAYER M4 ;
			RECT 0.2105 136.1922 124.383 136.2392 ;
		END

		PORT
			 LAYER M4 ;
			RECT 0.2105 135.5522 124.383 135.5992 ;
		END

		PORT
			 LAYER M4 ;
			RECT 0.2105 134.9122 124.383 134.9592 ;
		END

		PORT
			 LAYER M4 ;
			RECT 0.2105 134.2722 124.383 134.3192 ;
		END

		PORT
			 LAYER M4 ;
			RECT 0.2105 133.6322 124.383 133.6792 ;
		END

		PORT
			 LAYER M4 ;
			RECT 0.2105 132.9922 124.383 133.0392 ;
		END

		PORT
			 LAYER M4 ;
			RECT 0.2105 132.3522 124.383 132.3992 ;
		END

		PORT
			 LAYER M4 ;
			RECT 0.2105 131.7122 124.383 131.7592 ;
		END

		PORT
			 LAYER M4 ;
			RECT 0.2105 131.0722 124.383 131.1192 ;
		END

		PORT
			 LAYER M4 ;
			RECT 0.2105 130.4322 124.383 130.4792 ;
		END

		PORT
			 LAYER M4 ;
			RECT 0.2105 193.811 124.383 193.858 ;
		END

		PORT
			 LAYER M4 ;
			RECT 0.2105 129.7922 124.383 129.8392 ;
		END

		PORT
			 LAYER M4 ;
			RECT 0.2105 129.1522 124.383 129.1992 ;
		END

		PORT
			 LAYER M4 ;
			RECT 0.2105 128.5122 124.383 128.5592 ;
		END

		PORT
			 LAYER M4 ;
			RECT 0.2105 127.8722 124.383 127.9192 ;
		END

		PORT
			 LAYER M4 ;
			RECT 0.2105 127.2322 124.383 127.2792 ;
		END

		PORT
			 LAYER M4 ;
			RECT 0.2105 126.5922 124.383 126.6392 ;
		END

		PORT
			 LAYER M4 ;
			RECT 0.2105 125.9522 124.383 125.9992 ;
		END

		PORT
			 LAYER M4 ;
			RECT 0.2105 125.3122 124.383 125.3592 ;
		END

		PORT
			 LAYER M4 ;
			RECT 0.2105 124.6722 124.383 124.7192 ;
		END

		PORT
			 LAYER M4 ;
			RECT 0.2105 124.0322 124.383 124.0792 ;
		END

		PORT
			 LAYER M4 ;
			RECT 0.2105 193.171 124.383 193.218 ;
		END

		PORT
			 LAYER M4 ;
			RECT 0.2105 123.3922 124.383 123.4392 ;
		END

		PORT
			 LAYER M4 ;
			RECT 0.2105 122.7522 124.383 122.7992 ;
		END

		PORT
			 LAYER M4 ;
			RECT 0.2105 122.1122 124.383 122.1592 ;
		END

		PORT
			 LAYER M4 ;
			RECT 0.2105 121.4722 124.383 121.5192 ;
		END

		PORT
			 LAYER M4 ;
			RECT 0.2105 120.8322 124.383 120.8792 ;
		END

		PORT
			 LAYER M4 ;
			RECT 0.2105 120.1922 124.383 120.2392 ;
		END

		PORT
			 LAYER M4 ;
			RECT 0.2105 119.5522 124.383 119.5992 ;
		END

		PORT
			 LAYER M4 ;
			RECT 0.2105 118.9122 124.383 118.9592 ;
		END

		PORT
			 LAYER M4 ;
			RECT 0.2105 118.2722 124.383 118.3192 ;
		END

		PORT
			 LAYER M4 ;
			RECT 0.2105 117.6322 124.383 117.6792 ;
		END

		PORT
			 LAYER M4 ;
			RECT 0.2105 192.531 124.383 192.578 ;
		END

		PORT
			 LAYER M4 ;
			RECT 0.2105 116.9922 124.383 117.0392 ;
		END

		PORT
			 LAYER M4 ;
			RECT 0.2105 116.3522 124.383 116.3992 ;
		END

		PORT
			 LAYER M4 ;
			RECT 0.2105 115.7122 124.383 115.7592 ;
		END

		PORT
			 LAYER M4 ;
			RECT 0.2105 115.0722 124.383 115.1192 ;
		END

		PORT
			 LAYER M4 ;
			RECT 0.2105 114.4322 124.383 114.4792 ;
		END

		PORT
			 LAYER M4 ;
			RECT 0.2105 113.7922 124.383 113.8392 ;
		END

		PORT
			 LAYER M4 ;
			RECT 0.2105 113.1522 124.383 113.1992 ;
		END

		PORT
			 LAYER M4 ;
			RECT 0.2105 112.5122 124.383 112.5592 ;
		END

		PORT
			 LAYER M4 ;
			RECT 0.2105 111.8722 124.383 111.9192 ;
		END

		PORT
			 LAYER M4 ;
			RECT 0.2105 111.2322 124.383 111.2792 ;
		END

		PORT
			 LAYER M4 ;
			RECT 0.2105 191.891 124.383 191.938 ;
		END

		PORT
			 LAYER M4 ;
			RECT 0.2105 110.5922 124.383 110.6392 ;
		END

		PORT
			 LAYER M4 ;
			RECT 0.2105 109.9522 124.383 109.9992 ;
		END

		PORT
			 LAYER M4 ;
			RECT 0.2105 109.3122 124.383 109.3592 ;
		END

		PORT
			 LAYER M4 ;
			RECT 0.2105 108.6722 124.383 108.7192 ;
		END

		PORT
			 LAYER M4 ;
			RECT 0.2105 108.0322 124.383 108.0792 ;
		END

		PORT
			 LAYER M4 ;
			RECT 0.2105 107.3922 124.383 107.4392 ;
		END

		PORT
			 LAYER M4 ;
			RECT 0.2105 106.7522 124.383 106.7992 ;
		END

		PORT
			 LAYER M4 ;
			RECT 0.2105 106.1122 124.383 106.1592 ;
		END

		PORT
			 LAYER M4 ;
			RECT 0.2105 105.4722 124.383 105.5192 ;
		END

		PORT
			 LAYER M4 ;
			RECT 0.2105 104.8322 124.383 104.8792 ;
		END

		PORT
			 LAYER M4 ;
			RECT 0.2105 191.251 124.383 191.298 ;
		END

		PORT
			 LAYER M4 ;
			RECT 0.2105 104.1922 124.383 104.2392 ;
		END

		PORT
			 LAYER M4 ;
			RECT 0.2105 103.5522 124.383 103.5992 ;
		END

		PORT
			 LAYER M4 ;
			RECT 0.2105 102.9122 124.383 102.9592 ;
		END

		PORT
			 LAYER M4 ;
			RECT 0.2105 102.2722 124.383 102.3192 ;
		END

		PORT
			 LAYER M4 ;
			RECT 0.2105 101.6322 124.383 101.6792 ;
		END

		PORT
			 LAYER M4 ;
			RECT 0.2105 100.9922 124.383 101.0392 ;
		END

		PORT
			 LAYER M4 ;
			RECT 0.2105 99.469 124.383 99.5161 ;
		END

		PORT
			 LAYER M4 ;
			RECT 0.2105 190.611 124.383 190.658 ;
		END

		PORT
			 LAYER M4 ;
			RECT 0.2105 98.829 124.383 98.8761 ;
		END

		PORT
			 LAYER M4 ;
			RECT 0.2105 98.189 124.383 98.2361 ;
		END

		PORT
			 LAYER M4 ;
			RECT 0.2105 97.549 124.383 97.5961 ;
		END

		PORT
			 LAYER M4 ;
			RECT 0.2105 96.909 124.383 96.9561 ;
		END

		PORT
			 LAYER M4 ;
			RECT 0.2105 96.269 124.383 96.3161 ;
		END

		PORT
			 LAYER M4 ;
			RECT 0.2105 95.629 124.383 95.6761 ;
		END

		PORT
			 LAYER M4 ;
			RECT 0.2105 94.989 124.383 95.0361 ;
		END

		PORT
			 LAYER M4 ;
			RECT 0.2105 94.349 124.383 94.3961 ;
		END

		PORT
			 LAYER M4 ;
			RECT 0.2105 93.709 124.383 93.7561 ;
		END

		PORT
			 LAYER M4 ;
			RECT 0.2105 93.069 124.383 93.1161 ;
		END

		PORT
			 LAYER M4 ;
			RECT 0.2105 189.971 124.383 190.018 ;
		END

		PORT
			 LAYER M4 ;
			RECT 0.2105 92.429 124.383 92.4761 ;
		END

		PORT
			 LAYER M4 ;
			RECT 0.2105 91.789 124.383 91.8361 ;
		END

		PORT
			 LAYER M4 ;
			RECT 0.2105 91.149 124.383 91.1961 ;
		END

		PORT
			 LAYER M4 ;
			RECT 0.2105 90.509 124.383 90.5561 ;
		END

		PORT
			 LAYER M4 ;
			RECT 0.2105 89.869 124.383 89.9161 ;
		END

		PORT
			 LAYER M4 ;
			RECT 0.2105 89.229 124.383 89.2761 ;
		END

		PORT
			 LAYER M4 ;
			RECT 0.2105 88.589 124.383 88.6361 ;
		END

		PORT
			 LAYER M4 ;
			RECT 0.2105 87.949 124.383 87.9961 ;
		END

		PORT
			 LAYER M4 ;
			RECT 0.2105 87.309 124.383 87.3561 ;
		END

		PORT
			 LAYER M4 ;
			RECT 0.2105 86.669 124.383 86.7161 ;
		END

		PORT
			 LAYER M4 ;
			RECT 0.2105 189.331 124.383 189.378 ;
		END

		PORT
			 LAYER M4 ;
			RECT 0.2105 86.029 124.383 86.0761 ;
		END

		PORT
			 LAYER M4 ;
			RECT 0.2105 85.389 124.383 85.4361 ;
		END

		PORT
			 LAYER M4 ;
			RECT 0.2105 84.749 124.383 84.7961 ;
		END

		PORT
			 LAYER M4 ;
			RECT 0.2105 84.109 124.383 84.1561 ;
		END

		PORT
			 LAYER M4 ;
			RECT 0.2105 83.469 124.383 83.5161 ;
		END

		PORT
			 LAYER M4 ;
			RECT 0.2105 82.829 124.383 82.8761 ;
		END

		PORT
			 LAYER M4 ;
			RECT 0.2105 82.189 124.383 82.2361 ;
		END

		PORT
			 LAYER M4 ;
			RECT 0.2105 81.549 124.383 81.5961 ;
		END

		PORT
			 LAYER M4 ;
			RECT 0.2105 80.909 124.383 80.9561 ;
		END

		PORT
			 LAYER M4 ;
			RECT 0.2105 80.269 124.383 80.3161 ;
		END

		PORT
			 LAYER M4 ;
			RECT 0.2105 188.691 124.383 188.738 ;
		END

		PORT
			 LAYER M4 ;
			RECT 0.2105 79.629 124.383 79.6761 ;
		END

		PORT
			 LAYER M4 ;
			RECT 0.2105 78.989 124.383 79.0361 ;
		END

		PORT
			 LAYER M4 ;
			RECT 0.2105 78.349 124.383 78.3961 ;
		END

		PORT
			 LAYER M4 ;
			RECT 0.2105 77.709 124.383 77.7561 ;
		END

		PORT
			 LAYER M4 ;
			RECT 0.2105 77.069 124.383 77.1161 ;
		END

		PORT
			 LAYER M4 ;
			RECT 0.2105 76.429 124.383 76.4761 ;
		END

		PORT
			 LAYER M4 ;
			RECT 0.2105 75.789 124.383 75.8361 ;
		END

		PORT
			 LAYER M4 ;
			RECT 0.2105 75.149 124.383 75.1961 ;
		END

		PORT
			 LAYER M4 ;
			RECT 0.2105 74.509 124.383 74.5561 ;
		END

		PORT
			 LAYER M4 ;
			RECT 0.2105 73.869 124.383 73.9161 ;
		END

		PORT
			 LAYER M4 ;
			RECT 0.2105 199.571 124.383 199.618 ;
		END

		PORT
			 LAYER M4 ;
			RECT 0.2105 188.051 124.383 188.098 ;
		END

		PORT
			 LAYER M4 ;
			RECT 0.2105 73.229 124.383 73.2761 ;
		END

		PORT
			 LAYER M4 ;
			RECT 0.2105 72.589 124.383 72.6361 ;
		END

		PORT
			 LAYER M4 ;
			RECT 0.2105 71.949 124.383 71.9961 ;
		END

		PORT
			 LAYER M4 ;
			RECT 0.2105 71.309 124.383 71.3561 ;
		END

		PORT
			 LAYER M4 ;
			RECT 0.2105 70.669 124.383 70.7161 ;
		END

		PORT
			 LAYER M4 ;
			RECT 0.2105 70.029 124.383 70.0761 ;
		END

		PORT
			 LAYER M4 ;
			RECT 0.2105 69.389 124.383 69.4361 ;
		END

		PORT
			 LAYER M4 ;
			RECT 0.2105 68.749 124.383 68.7961 ;
		END

		PORT
			 LAYER M4 ;
			RECT 0.2105 68.109 124.383 68.1561 ;
		END

		PORT
			 LAYER M4 ;
			RECT 0.2105 67.469 124.383 67.5161 ;
		END

		PORT
			 LAYER M4 ;
			RECT 0.2105 187.411 124.383 187.458 ;
		END

		PORT
			 LAYER M4 ;
			RECT 0.2105 66.829 124.383 66.8761 ;
		END

		PORT
			 LAYER M4 ;
			RECT 0.2105 66.189 124.383 66.2361 ;
		END

		PORT
			 LAYER M4 ;
			RECT 0.2105 65.549 124.383 65.5961 ;
		END

		PORT
			 LAYER M4 ;
			RECT 0.2105 64.909 124.383 64.9561 ;
		END

		PORT
			 LAYER M4 ;
			RECT 0.2105 64.269 124.383 64.3161 ;
		END

		PORT
			 LAYER M4 ;
			RECT 0.2105 63.629 124.383 63.6761 ;
		END

		PORT
			 LAYER M4 ;
			RECT 0.2105 62.989 124.383 63.0361 ;
		END

		PORT
			 LAYER M4 ;
			RECT 0.2105 62.349 124.383 62.3961 ;
		END

		PORT
			 LAYER M4 ;
			RECT 0.2105 61.709 124.383 61.7561 ;
		END

		PORT
			 LAYER M4 ;
			RECT 0.2105 61.069 124.383 61.1161 ;
		END

		PORT
			 LAYER M4 ;
			RECT 0.2105 186.771 124.383 186.818 ;
		END

		PORT
			 LAYER M4 ;
			RECT 0.2105 60.429 124.383 60.4761 ;
		END

		PORT
			 LAYER M4 ;
			RECT 0.2105 59.789 124.383 59.8361 ;
		END

		PORT
			 LAYER M4 ;
			RECT 0.2105 59.149 124.383 59.1961 ;
		END

		PORT
			 LAYER M4 ;
			RECT 0.2105 58.509 124.383 58.5561 ;
		END

		PORT
			 LAYER M4 ;
			RECT 0.2105 57.869 124.383 57.9161 ;
		END

		PORT
			 LAYER M4 ;
			RECT 0.2105 57.229 124.383 57.2761 ;
		END

		PORT
			 LAYER M4 ;
			RECT 0.2105 56.589 124.383 56.6361 ;
		END

		PORT
			 LAYER M4 ;
			RECT 0.2105 55.949 124.383 55.9961 ;
		END

		PORT
			 LAYER M4 ;
			RECT 0.2105 55.309 124.383 55.3561 ;
		END

		PORT
			 LAYER M4 ;
			RECT 0.2105 54.669 124.383 54.7161 ;
		END

		PORT
			 LAYER M4 ;
			RECT 0.2105 186.131 124.383 186.178 ;
		END

		PORT
			 LAYER M4 ;
			RECT 0.2105 54.029 124.383 54.0761 ;
		END

		PORT
			 LAYER M4 ;
			RECT 0.2105 185.491 124.383 185.538 ;
		END

		PORT
			 LAYER M4 ;
			RECT 0.2105 45.6902 124.383 45.7373 ;
		END

		PORT
			 LAYER M4 ;
			RECT 0.2105 45.0502 124.383 45.0973 ;
		END

		PORT
			 LAYER M4 ;
			RECT 0.2105 44.4102 124.383 44.4573 ;
		END

		PORT
			 LAYER M4 ;
			RECT 0.2105 43.7702 124.383 43.8173 ;
		END

		PORT
			 LAYER M4 ;
			RECT 0.2105 43.1302 124.383 43.1773 ;
		END

		PORT
			 LAYER M4 ;
			RECT 0.2105 42.4902 124.383 42.5373 ;
		END

		PORT
			 LAYER M4 ;
			RECT 0.2105 41.8502 124.383 41.8973 ;
		END

		PORT
			 LAYER M4 ;
			RECT 0.2105 41.2102 124.383 41.2573 ;
		END

		PORT
			 LAYER M4 ;
			RECT 0.2105 184.851 124.383 184.898 ;
		END

		PORT
			 LAYER M4 ;
			RECT 0.2105 40.5702 124.383 40.6173 ;
		END

		PORT
			 LAYER M4 ;
			RECT 0.2105 39.9302 124.383 39.9773 ;
		END

		PORT
			 LAYER M4 ;
			RECT 0.2105 39.2902 124.383 39.3373 ;
		END

		PORT
			 LAYER M4 ;
			RECT 0.2105 38.6502 124.383 38.6973 ;
		END

		PORT
			 LAYER M4 ;
			RECT 0.2105 38.0102 124.383 38.0573 ;
		END

		PORT
			 LAYER M4 ;
			RECT 0.2105 37.3702 124.383 37.4173 ;
		END

		PORT
			 LAYER M4 ;
			RECT 0.2105 36.7302 124.383 36.7773 ;
		END

		PORT
			 LAYER M4 ;
			RECT 0.2105 36.0902 124.383 36.1373 ;
		END

		PORT
			 LAYER M4 ;
			RECT 0.2105 35.4502 124.383 35.4973 ;
		END

		PORT
			 LAYER M4 ;
			RECT 0.2105 34.8102 124.383 34.8573 ;
		END

		PORT
			 LAYER M4 ;
			RECT 0.2105 184.211 124.383 184.258 ;
		END

		PORT
			 LAYER M4 ;
			RECT 0.2105 34.1702 124.383 34.2173 ;
		END

		PORT
			 LAYER M4 ;
			RECT 0.2105 33.5302 124.383 33.5773 ;
		END

		PORT
			 LAYER M4 ;
			RECT 0.2105 32.8902 124.383 32.9373 ;
		END

		PORT
			 LAYER M4 ;
			RECT 0.2105 32.2502 124.383 32.2973 ;
		END

		PORT
			 LAYER M4 ;
			RECT 0.2105 31.6102 124.383 31.6573 ;
		END

		PORT
			 LAYER M4 ;
			RECT 0.2105 30.9702 124.383 31.0173 ;
		END

		PORT
			 LAYER M4 ;
			RECT 0.2105 30.3302 124.383 30.3773 ;
		END

		PORT
			 LAYER M4 ;
			RECT 0.2105 29.6902 124.383 29.7373 ;
		END

		PORT
			 LAYER M4 ;
			RECT 0.2105 29.0502 124.383 29.0973 ;
		END

		PORT
			 LAYER M4 ;
			RECT 0.2105 28.4102 124.383 28.4573 ;
		END

		PORT
			 LAYER M4 ;
			RECT 0.2105 183.571 124.383 183.618 ;
		END

		PORT
			 LAYER M4 ;
			RECT 0.2105 27.7702 124.383 27.8173 ;
		END

		PORT
			 LAYER M4 ;
			RECT 0.2105 27.1302 124.383 27.1773 ;
		END

		PORT
			 LAYER M4 ;
			RECT 0.2105 26.4902 124.383 26.5373 ;
		END

		PORT
			 LAYER M4 ;
			RECT 0.2105 25.8502 124.383 25.8973 ;
		END

		PORT
			 LAYER M4 ;
			RECT 0.2105 25.2102 124.383 25.2573 ;
		END

		PORT
			 LAYER M4 ;
			RECT 0.2105 24.5702 124.383 24.6173 ;
		END

		PORT
			 LAYER M4 ;
			RECT 0.2105 23.9302 124.383 23.9773 ;
		END

		PORT
			 LAYER M4 ;
			RECT 0.2105 23.2902 124.383 23.3373 ;
		END

		PORT
			 LAYER M4 ;
			RECT 0.2105 22.6502 124.383 22.6973 ;
		END

		PORT
			 LAYER M4 ;
			RECT 0.2105 22.0102 124.383 22.0573 ;
		END

		PORT
			 LAYER M4 ;
			RECT 0.2105 182.931 124.383 182.978 ;
		END

		PORT
			 LAYER M4 ;
			RECT 0.2105 21.3702 124.383 21.4173 ;
		END

		PORT
			 LAYER M4 ;
			RECT 0.2105 20.7302 124.383 20.7773 ;
		END

		PORT
			 LAYER M4 ;
			RECT 0.2105 20.0902 124.383 20.1373 ;
		END

		PORT
			 LAYER M4 ;
			RECT 0.2105 19.4502 124.383 19.4973 ;
		END

		PORT
			 LAYER M4 ;
			RECT 0.2105 18.8102 124.383 18.8573 ;
		END

		PORT
			 LAYER M4 ;
			RECT 0.2105 18.1702 124.383 18.2173 ;
		END

		PORT
			 LAYER M4 ;
			RECT 0.2105 17.5302 124.383 17.5773 ;
		END

		PORT
			 LAYER M4 ;
			RECT 0.2105 16.8902 124.383 16.9373 ;
		END

		PORT
			 LAYER M4 ;
			RECT 0.2105 16.2502 124.383 16.2973 ;
		END

		PORT
			 LAYER M4 ;
			RECT 0.2105 15.6102 124.383 15.6573 ;
		END

		PORT
			 LAYER M4 ;
			RECT 0.2105 182.291 124.383 182.338 ;
		END

		PORT
			 LAYER M4 ;
			RECT 0.2105 14.9702 124.383 15.0173 ;
		END

		PORT
			 LAYER M4 ;
			RECT 0.2105 14.3302 124.383 14.3773 ;
		END

		PORT
			 LAYER M4 ;
			RECT 0.2105 13.6902 124.383 13.7373 ;
		END

		PORT
			 LAYER M4 ;
			RECT 0.2105 13.0502 124.383 13.0973 ;
		END

		PORT
			 LAYER M4 ;
			RECT 0.2105 12.4102 124.383 12.4573 ;
		END

		PORT
			 LAYER M4 ;
			RECT 0.2105 11.7702 124.383 11.8173 ;
		END

		PORT
			 LAYER M4 ;
			RECT 0.2105 11.1302 124.383 11.1773 ;
		END

		PORT
			 LAYER M4 ;
			RECT 0.2105 10.4902 124.383 10.5373 ;
		END

		PORT
			 LAYER M4 ;
			RECT 0.2105 9.8502 124.383 9.8973 ;
		END

		PORT
			 LAYER M4 ;
			RECT 0.2105 9.2102 124.383 9.2573 ;
		END

		PORT
			 LAYER M4 ;
			RECT 0.2105 198.931 124.383 198.978 ;
		END

		PORT
			 LAYER M4 ;
			RECT 0.2105 181.651 124.383 181.698 ;
		END

		PORT
			 LAYER M4 ;
			RECT 0.2105 8.5702 124.383 8.6173 ;
		END

		PORT
			 LAYER M4 ;
			RECT 0.2105 7.9302 124.383 7.9773 ;
		END

		PORT
			 LAYER M4 ;
			RECT 0.2105 7.2902 124.383 7.3373 ;
		END

		PORT
			 LAYER M4 ;
			RECT 0.2105 6.6502 124.383 6.6973 ;
		END

		PORT
			 LAYER M4 ;
			RECT 0.2105 6.0102 124.383 6.0573 ;
		END

		PORT
			 LAYER M4 ;
			RECT 0.2105 5.3702 124.383 5.4173 ;
		END

		PORT
			 LAYER M4 ;
			RECT 0.2105 4.7302 124.383 4.7773 ;
		END

		PORT
			 LAYER M4 ;
			RECT 0.2105 4.0902 124.383 4.1373 ;
		END

		PORT
			 LAYER M4 ;
			RECT 0.2105 3.4502 124.383 3.4973 ;
		END

		PORT
			 LAYER M4 ;
			RECT 0.2105 2.8102 124.383 2.8573 ;
		END

		PORT
			 LAYER M4 ;
			RECT 0.2105 181.011 124.383 181.058 ;
		END

		PORT
			 LAYER M4 ;
			RECT 0.2105 2.1702 124.383 2.2173 ;
		END

		PORT
			 LAYER M4 ;
			RECT 0.2105 1.5302 124.383 1.5773 ;
		END

		PORT
			 LAYER M4 ;
			RECT 0.2105 0.8902 124.383 0.9373 ;
		END

		PORT
			 LAYER M4 ;
			RECT 0.2105 0.2502 124.383 0.2973 ;
		END

		PORT
			 LAYER M4 ;
			RECT 0.2105 180.371 124.383 180.418 ;
		END

		PORT
			 LAYER M4 ;
			RECT 0.2105 179.731 124.383 179.778 ;
		END

	END VSSE

	PIN WABL
		USE SIGNAL ;
		DIRECTION INPUT ;
		SHAPE ABUTMENT ;
		PORT
			 LAYER M2 ;
			RECT 0.0714 98.8675 0.1097 98.9051 ;
			 LAYER M3 ;
			RECT 0.0714 98.8675 0.1097 98.9678 ;
			 LAYER V2 ;
			RECT 0.0831 98.8796 0.098 98.8922 ;
		END

		ANTENNAGATEAREA 0.00027817 ;
		ANTENNADIFFAREA 0.00194719 ;
		ANTENNAPARTIALMETALAREA 0.00195671 ;
	END WABL

	PIN WABLM[0]
		USE SIGNAL ;
		DIRECTION INPUT ;
		SHAPE ABUTMENT ;
		PORT
			 LAYER M2 ;
			RECT 0.0098 99.018 0.0481 99.1184 ;
			 LAYER M3 ;
			RECT 0.0098 99.018 0.0481 99.1184 ;
			 LAYER V2 ;
			RECT 0.021 99.0929 0.0359 99.1055 ;
		END

		ANTENNAGATEAREA 0.00027817 ;
		ANTENNADIFFAREA 0.00194719 ;
		ANTENNAPARTIALMETALAREA 0.00195671 ;
	END WABLM[0]

	PIN WABLM[1]
		USE SIGNAL ;
		DIRECTION INPUT ;
		SHAPE ABUTMENT ;
		PORT
			 LAYER M2 ;
			RECT 0.0098 99.6831 0.0481 99.7208 ;
			 LAYER M3 ;
			RECT 0.0098 99.6204 0.0481 99.7208 ;
			 LAYER V2 ;
			RECT 0.0215 99.6953 0.0364 99.7078 ;
		END

		ANTENNAGATEAREA 0.00027817 ;
		ANTENNADIFFAREA 0.00194719 ;
		ANTENNAPARTIALMETALAREA 0.00195671 ;
	END WABLM[1]

	PIN WENY[0]
		USE SIGNAL ;
		DIRECTION OUTPUT ;
		SHAPE ABUTMENT ;
		PORT
			 LAYER M2 ;
			RECT 0.0098 2.5224 0.0481 2.6227 ;
			 LAYER M3 ;
			RECT 0.0098 2.5224 0.0481 2.6227 ;
			 LAYER V2 ;
			RECT 0.021 2.5353 0.0359 2.5478 ;
		END

		ANTENNADIFFAREA 0.00194719 ;
		ANTENNAPARTIALMETALAREA 0.00195671 ;
	END WENY[0]

	PIN WENY[10]
		USE SIGNAL ;
		DIRECTION OUTPUT ;
		SHAPE ABUTMENT ;
		PORT
			 LAYER M2 ;
			RECT 0.0098 28.1224 0.0481 28.2227 ;
			 LAYER M3 ;
			RECT 0.0098 28.1224 0.0481 28.2227 ;
			 LAYER V2 ;
			RECT 0.021 28.1353 0.0359 28.1478 ;
		END

		ANTENNADIFFAREA 0.00194719 ;
		ANTENNAPARTIALMETALAREA 0.00195671 ;
	END WENY[10]

	PIN WENY[11]
		USE SIGNAL ;
		DIRECTION OUTPUT ;
		SHAPE ABUTMENT ;
		PORT
			 LAYER M2 ;
			RECT 0.0098 30.6824 0.0481 30.7827 ;
			 LAYER M3 ;
			RECT 0.0098 30.6824 0.0481 30.7827 ;
			 LAYER V2 ;
			RECT 0.021 30.6953 0.0359 30.7078 ;
		END

		ANTENNADIFFAREA 0.00194719 ;
		ANTENNAPARTIALMETALAREA 0.00195671 ;
	END WENY[11]

	PIN WENY[12]
		USE SIGNAL ;
		DIRECTION OUTPUT ;
		SHAPE ABUTMENT ;
		PORT
			 LAYER M2 ;
			RECT 0.0098 33.2424 0.0481 33.3427 ;
			 LAYER M3 ;
			RECT 0.0098 33.2424 0.0481 33.3427 ;
			 LAYER V2 ;
			RECT 0.021 33.2553 0.0359 33.2678 ;
		END

		ANTENNADIFFAREA 0.00194719 ;
		ANTENNAPARTIALMETALAREA 0.00195671 ;
	END WENY[12]

	PIN WENY[13]
		USE SIGNAL ;
		DIRECTION OUTPUT ;
		SHAPE ABUTMENT ;
		PORT
			 LAYER M2 ;
			RECT 0.0098 35.8024 0.0481 35.9027 ;
			 LAYER M3 ;
			RECT 0.0098 35.8024 0.0481 35.9027 ;
			 LAYER V2 ;
			RECT 0.021 35.8153 0.0359 35.8278 ;
		END

		ANTENNADIFFAREA 0.00194719 ;
		ANTENNAPARTIALMETALAREA 0.00195671 ;
	END WENY[13]

	PIN WENY[14]
		USE SIGNAL ;
		DIRECTION OUTPUT ;
		SHAPE ABUTMENT ;
		PORT
			 LAYER M2 ;
			RECT 0.0098 38.3624 0.0481 38.4627 ;
			 LAYER M3 ;
			RECT 0.0098 38.3624 0.0481 38.4627 ;
			 LAYER V2 ;
			RECT 0.021 38.3753 0.0359 38.3878 ;
		END

		ANTENNADIFFAREA 0.00194719 ;
		ANTENNAPARTIALMETALAREA 0.00195671 ;
	END WENY[14]

	PIN WENY[15]
		USE SIGNAL ;
		DIRECTION OUTPUT ;
		SHAPE ABUTMENT ;
		PORT
			 LAYER M2 ;
			RECT 0.0098 40.9224 0.0481 41.0227 ;
			 LAYER M3 ;
			RECT 0.0098 40.9224 0.0481 41.0227 ;
			 LAYER V2 ;
			RECT 0.021 40.9353 0.0359 40.9478 ;
		END

		ANTENNADIFFAREA 0.00194719 ;
		ANTENNAPARTIALMETALAREA 0.00195671 ;
	END WENY[15]

	PIN WENY[16]
		USE SIGNAL ;
		DIRECTION OUTPUT ;
		SHAPE ABUTMENT ;
		PORT
			 LAYER M2 ;
			RECT 0.0098 43.4824 0.0481 43.5827 ;
			 LAYER M3 ;
			RECT 0.0098 43.4824 0.0481 43.5827 ;
			 LAYER V2 ;
			RECT 0.021 43.4953 0.0359 43.5078 ;
		END

		ANTENNADIFFAREA 0.00194719 ;
		ANTENNAPARTIALMETALAREA 0.00195671 ;
	END WENY[16]

	PIN WENY[17]
		USE SIGNAL ;
		DIRECTION OUTPUT ;
		SHAPE ABUTMENT ;
		PORT
			 LAYER M2 ;
			RECT 0.0098 46.0424 0.0481 46.1427 ;
			 LAYER M3 ;
			RECT 0.0098 46.0424 0.0481 46.1427 ;
			 LAYER V2 ;
			RECT 0.021 46.0553 0.0359 46.0678 ;
		END

		ANTENNADIFFAREA 0.00194719 ;
		ANTENNAPARTIALMETALAREA 0.00195671 ;
	END WENY[17]

	PIN WENY[18]
		USE SIGNAL ;
		DIRECTION OUTPUT ;
		SHAPE ABUTMENT ;
		PORT
			 LAYER M2 ;
			RECT 0.0098 56.3012 0.0481 56.4016 ;
			 LAYER M3 ;
			RECT 0.0098 56.3012 0.0481 56.4016 ;
			 LAYER V2 ;
			RECT 0.021 56.3141 0.0359 56.3267 ;
		END

		ANTENNADIFFAREA 0.00194719 ;
		ANTENNAPARTIALMETALAREA 0.00195671 ;
	END WENY[18]

	PIN WENY[19]
		USE SIGNAL ;
		DIRECTION OUTPUT ;
		SHAPE ABUTMENT ;
		PORT
			 LAYER M2 ;
			RECT 0.0098 58.8612 0.0481 58.9616 ;
			 LAYER M3 ;
			RECT 0.0098 58.8612 0.0481 58.9616 ;
			 LAYER V2 ;
			RECT 0.021 58.8741 0.0359 58.8867 ;
		END

		ANTENNADIFFAREA 0.00194719 ;
		ANTENNAPARTIALMETALAREA 0.00195671 ;
	END WENY[19]

	PIN WENY[1]
		USE SIGNAL ;
		DIRECTION OUTPUT ;
		SHAPE ABUTMENT ;
		PORT
			 LAYER M2 ;
			RECT 0.0098 5.0824 0.0481 5.1827 ;
			 LAYER M3 ;
			RECT 0.0098 5.0824 0.0481 5.1827 ;
			 LAYER V2 ;
			RECT 0.021 5.0953 0.0359 5.1078 ;
		END

		ANTENNADIFFAREA 0.00194719 ;
		ANTENNAPARTIALMETALAREA 0.00195671 ;
	END WENY[1]

	PIN WENY[20]
		USE SIGNAL ;
		DIRECTION OUTPUT ;
		SHAPE ABUTMENT ;
		PORT
			 LAYER M2 ;
			RECT 0.0098 61.4212 0.0481 61.5216 ;
			 LAYER M3 ;
			RECT 0.0098 61.4212 0.0481 61.5216 ;
			 LAYER V2 ;
			RECT 0.021 61.4341 0.0359 61.4467 ;
		END

		ANTENNADIFFAREA 0.00194719 ;
		ANTENNAPARTIALMETALAREA 0.00195671 ;
	END WENY[20]

	PIN WENY[21]
		USE SIGNAL ;
		DIRECTION OUTPUT ;
		SHAPE ABUTMENT ;
		PORT
			 LAYER M2 ;
			RECT 0.0098 63.9812 0.0481 64.0816 ;
			 LAYER M3 ;
			RECT 0.0098 63.9812 0.0481 64.0816 ;
			 LAYER V2 ;
			RECT 0.021 63.9941 0.0359 64.0067 ;
		END

		ANTENNADIFFAREA 0.00194719 ;
		ANTENNAPARTIALMETALAREA 0.00195671 ;
	END WENY[21]

	PIN WENY[22]
		USE SIGNAL ;
		DIRECTION OUTPUT ;
		SHAPE ABUTMENT ;
		PORT
			 LAYER M2 ;
			RECT 0.0098 66.5412 0.0481 66.6416 ;
			 LAYER M3 ;
			RECT 0.0098 66.5412 0.0481 66.6416 ;
			 LAYER V2 ;
			RECT 0.021 66.5541 0.0359 66.5667 ;
		END

		ANTENNADIFFAREA 0.00194719 ;
		ANTENNAPARTIALMETALAREA 0.00195671 ;
	END WENY[22]

	PIN WENY[23]
		USE SIGNAL ;
		DIRECTION OUTPUT ;
		SHAPE ABUTMENT ;
		PORT
			 LAYER M2 ;
			RECT 0.0098 69.1012 0.0481 69.2016 ;
			 LAYER M3 ;
			RECT 0.0098 69.1012 0.0481 69.2016 ;
			 LAYER V2 ;
			RECT 0.021 69.1141 0.0359 69.1267 ;
		END

		ANTENNADIFFAREA 0.00194719 ;
		ANTENNAPARTIALMETALAREA 0.00195671 ;
	END WENY[23]

	PIN WENY[24]
		USE SIGNAL ;
		DIRECTION OUTPUT ;
		SHAPE ABUTMENT ;
		PORT
			 LAYER M2 ;
			RECT 0.0098 71.6612 0.0481 71.7616 ;
			 LAYER M3 ;
			RECT 0.0098 71.6612 0.0481 71.7616 ;
			 LAYER V2 ;
			RECT 0.021 71.6741 0.0359 71.6867 ;
		END

		ANTENNADIFFAREA 0.00194719 ;
		ANTENNAPARTIALMETALAREA 0.00195671 ;
	END WENY[24]

	PIN WENY[25]
		USE SIGNAL ;
		DIRECTION OUTPUT ;
		SHAPE ABUTMENT ;
		PORT
			 LAYER M2 ;
			RECT 0.0098 74.2212 0.0481 74.3216 ;
			 LAYER M3 ;
			RECT 0.0098 74.2212 0.0481 74.3216 ;
			 LAYER V2 ;
			RECT 0.021 74.2341 0.0359 74.2467 ;
		END

		ANTENNADIFFAREA 0.00194719 ;
		ANTENNAPARTIALMETALAREA 0.00195671 ;
	END WENY[25]

	PIN WENY[26]
		USE SIGNAL ;
		DIRECTION OUTPUT ;
		SHAPE ABUTMENT ;
		PORT
			 LAYER M2 ;
			RECT 0.0098 76.7812 0.0481 76.8816 ;
			 LAYER M3 ;
			RECT 0.0098 76.7812 0.0481 76.8816 ;
			 LAYER V2 ;
			RECT 0.021 76.7941 0.0359 76.8067 ;
		END

		ANTENNADIFFAREA 0.00194719 ;
		ANTENNAPARTIALMETALAREA 0.00195671 ;
	END WENY[26]

	PIN WENY[27]
		USE SIGNAL ;
		DIRECTION OUTPUT ;
		SHAPE ABUTMENT ;
		PORT
			 LAYER M2 ;
			RECT 0.0098 79.3412 0.0481 79.4416 ;
			 LAYER M3 ;
			RECT 0.0098 79.3412 0.0481 79.4416 ;
			 LAYER V2 ;
			RECT 0.021 79.3541 0.0359 79.3667 ;
		END

		ANTENNADIFFAREA 0.00194719 ;
		ANTENNAPARTIALMETALAREA 0.00195671 ;
	END WENY[27]

	PIN WENY[28]
		USE SIGNAL ;
		DIRECTION OUTPUT ;
		SHAPE ABUTMENT ;
		PORT
			 LAYER M2 ;
			RECT 0.0098 81.9012 0.0481 82.0016 ;
			 LAYER M3 ;
			RECT 0.0098 81.9012 0.0481 82.0016 ;
			 LAYER V2 ;
			RECT 0.021 81.9141 0.0359 81.9267 ;
		END

		ANTENNADIFFAREA 0.00194719 ;
		ANTENNAPARTIALMETALAREA 0.00195671 ;
	END WENY[28]

	PIN WENY[29]
		USE SIGNAL ;
		DIRECTION OUTPUT ;
		SHAPE ABUTMENT ;
		PORT
			 LAYER M2 ;
			RECT 0.0098 84.4612 0.0481 84.5616 ;
			 LAYER M3 ;
			RECT 0.0098 84.4612 0.0481 84.5616 ;
			 LAYER V2 ;
			RECT 0.021 84.4741 0.0359 84.4867 ;
		END

		ANTENNADIFFAREA 0.00194719 ;
		ANTENNAPARTIALMETALAREA 0.00195671 ;
	END WENY[29]

	PIN WENY[2]
		USE SIGNAL ;
		DIRECTION OUTPUT ;
		SHAPE ABUTMENT ;
		PORT
			 LAYER M2 ;
			RECT 0.0098 7.6424 0.0481 7.7427 ;
			 LAYER M3 ;
			RECT 0.0098 7.6424 0.0481 7.7427 ;
			 LAYER V2 ;
			RECT 0.021 7.6553 0.0359 7.6678 ;
		END

		ANTENNADIFFAREA 0.00194719 ;
		ANTENNAPARTIALMETALAREA 0.00195671 ;
	END WENY[2]

	PIN WENY[30]
		USE SIGNAL ;
		DIRECTION OUTPUT ;
		SHAPE ABUTMENT ;
		PORT
			 LAYER M2 ;
			RECT 0.0098 87.0212 0.0481 87.1216 ;
			 LAYER M3 ;
			RECT 0.0098 87.0212 0.0481 87.1216 ;
			 LAYER V2 ;
			RECT 0.021 87.0341 0.0359 87.0467 ;
		END

		ANTENNADIFFAREA 0.00194719 ;
		ANTENNAPARTIALMETALAREA 0.00195671 ;
	END WENY[30]

	PIN WENY[31]
		USE SIGNAL ;
		DIRECTION OUTPUT ;
		SHAPE ABUTMENT ;
		PORT
			 LAYER M2 ;
			RECT 0.0098 89.4682 0.0481 89.5059 ;
			 LAYER M3 ;
			RECT 0.0098 89.4055 0.0481 89.5059 ;
			 LAYER V2 ;
			RECT 0.0215 89.4804 0.0364 89.4929 ;
		END

		ANTENNADIFFAREA 0.00194719 ;
		ANTENNAPARTIALMETALAREA 0.00195671 ;
	END WENY[31]

	PIN WENY[32]
		USE SIGNAL ;
		DIRECTION OUTPUT ;
		SHAPE ABUTMENT ;
		PORT
			 LAYER M2 ;
			RECT 0.0098 92.0659 0.0481 92.1663 ;
			 LAYER M3 ;
			RECT 0.0098 92.0659 0.0481 92.1663 ;
			 LAYER V2 ;
			RECT 0.021 92.1408 0.0359 92.1533 ;
		END

		ANTENNADIFFAREA 0.00194719 ;
		ANTENNAPARTIALMETALAREA 0.00195671 ;
	END WENY[32]

	PIN WENY[33]
		USE SIGNAL ;
		DIRECTION OUTPUT ;
		SHAPE ABUTMENT ;
		PORT
			 LAYER M2 ;
			RECT 0.0098 94.6384 0.0481 94.6761 ;
			 LAYER M3 ;
			RECT 0.0098 94.5757 0.0481 94.6761 ;
			 LAYER V2 ;
			RECT 0.0215 94.6506 0.0364 94.6631 ;
		END

		ANTENNADIFFAREA 0.00194719 ;
		ANTENNAPARTIALMETALAREA 0.00195671 ;
	END WENY[33]

	PIN WENY[34]
		USE SIGNAL ;
		DIRECTION OUTPUT ;
		SHAPE ABUTMENT ;
		PORT
			 LAYER M2 ;
			RECT 0.0098 97.1231 0.0481 97.1608 ;
			 LAYER M3 ;
			RECT 0.0098 97.0604 0.0481 97.1608 ;
			 LAYER V2 ;
			RECT 0.0215 97.1353 0.0364 97.1478 ;
		END

		ANTENNADIFFAREA 0.00194719 ;
		ANTENNAPARTIALMETALAREA 0.00195671 ;
	END WENY[34]

	PIN WENY[35]
		USE SIGNAL ;
		DIRECTION OUTPUT ;
		SHAPE ABUTMENT ;
		PORT
			 LAYER M2 ;
			RECT 0.0714 99.771 0.1097 99.8086 ;
			 LAYER M3 ;
			RECT 0.0714 99.771 0.1097 99.8714 ;
			 LAYER V2 ;
			RECT 0.0831 99.7831 0.098 99.7957 ;
		END

		ANTENNADIFFAREA 0.00194719 ;
		ANTENNAPARTIALMETALAREA 0.00195671 ;
	END WENY[35]

	PIN WENY[36]
		USE SIGNAL ;
		DIRECTION OUTPUT ;
		SHAPE ABUTMENT ;
		PORT
			 LAYER M2 ;
			RECT 0.0714 100.6745 0.1097 100.7122 ;
			 LAYER M3 ;
			RECT 0.0714 100.6118 0.1097 100.7122 ;
			 LAYER V2 ;
			RECT 0.0831 100.6875 0.098 100.7 ;
		END

		ANTENNADIFFAREA 0.00194719 ;
		ANTENNAPARTIALMETALAREA 0.00195671 ;
	END WENY[36]

	PIN WENY[37]
		USE SIGNAL ;
		DIRECTION OUTPUT ;
		SHAPE ABUTMENT ;
		PORT
			 LAYER M2 ;
			RECT 0.0098 103.3224 0.0481 103.36 ;
			 LAYER M3 ;
			RECT 0.0098 103.3224 0.0481 103.4227 ;
			 LAYER V2 ;
			RECT 0.0215 103.3353 0.0364 103.3478 ;
		END

		ANTENNADIFFAREA 0.00194719 ;
		ANTENNAPARTIALMETALAREA 0.00195671 ;
	END WENY[37]

	PIN WENY[38]
		USE SIGNAL ;
		DIRECTION OUTPUT ;
		SHAPE ABUTMENT ;
		PORT
			 LAYER M2 ;
			RECT 0.0714 105.7945 0.1097 105.8322 ;
			 LAYER M3 ;
			RECT 0.0714 105.7318 0.1097 105.8322 ;
			 LAYER V2 ;
			RECT 0.0831 105.8075 0.098 105.82 ;
		END

		ANTENNADIFFAREA 0.00194719 ;
		ANTENNAPARTIALMETALAREA 0.00195671 ;
	END WENY[38]

	PIN WENY[39]
		USE SIGNAL ;
		DIRECTION OUTPUT ;
		SHAPE ABUTMENT ;
		PORT
			 LAYER M2 ;
			RECT 0.0098 108.4424 0.0481 108.48 ;
			 LAYER M3 ;
			RECT 0.0098 108.4424 0.0481 108.5427 ;
			 LAYER V2 ;
			RECT 0.0215 108.4553 0.0364 108.4678 ;
		END

		ANTENNADIFFAREA 0.00194719 ;
		ANTENNAPARTIALMETALAREA 0.00195671 ;
	END WENY[39]

	PIN WENY[3]
		USE SIGNAL ;
		DIRECTION OUTPUT ;
		SHAPE ABUTMENT ;
		PORT
			 LAYER M2 ;
			RECT 0.0098 10.2024 0.0481 10.3027 ;
			 LAYER M3 ;
			RECT 0.0098 10.2024 0.0481 10.3027 ;
			 LAYER V2 ;
			RECT 0.021 10.2153 0.0359 10.2278 ;
		END

		ANTENNADIFFAREA 0.00194719 ;
		ANTENNAPARTIALMETALAREA 0.00195671 ;
	END WENY[3]

	PIN WENY[40]
		USE SIGNAL ;
		DIRECTION OUTPUT ;
		SHAPE ABUTMENT ;
		PORT
			 LAYER M2 ;
			RECT 0.0098 111.0024 0.0481 111.04 ;
			 LAYER M3 ;
			RECT 0.0098 111.0024 0.0481 111.1027 ;
			 LAYER V2 ;
			RECT 0.0215 111.0153 0.0364 111.0278 ;
		END

		ANTENNADIFFAREA 0.00194719 ;
		ANTENNAPARTIALMETALAREA 0.00195671 ;
	END WENY[40]

	PIN WENY[41]
		USE SIGNAL ;
		DIRECTION OUTPUT ;
		SHAPE ABUTMENT ;
		PORT
			 LAYER M2 ;
			RECT 0.0098 113.3867 0.0481 113.4871 ;
			 LAYER M3 ;
			RECT 0.0098 113.3867 0.0481 113.4871 ;
			 LAYER V2 ;
			RECT 0.021 113.4616 0.0359 113.4741 ;
		END

		ANTENNADIFFAREA 0.00194719 ;
		ANTENNAPARTIALMETALAREA 0.00195671 ;
	END WENY[41]

	PIN WENY[42]
		USE SIGNAL ;
		DIRECTION OUTPUT ;
		SHAPE ABUTMENT ;
		PORT
			 LAYER M2 ;
			RECT 0.0098 115.9467 0.0481 116.0471 ;
			 LAYER M3 ;
			RECT 0.0098 115.9467 0.0481 116.0471 ;
			 LAYER V2 ;
			RECT 0.021 116.0216 0.0359 116.0341 ;
		END

		ANTENNADIFFAREA 0.00194719 ;
		ANTENNAPARTIALMETALAREA 0.00195671 ;
	END WENY[42]

	PIN WENY[43]
		USE SIGNAL ;
		DIRECTION OUTPUT ;
		SHAPE ABUTMENT ;
		PORT
			 LAYER M2 ;
			RECT 0.0098 118.5067 0.0481 118.6071 ;
			 LAYER M3 ;
			RECT 0.0098 118.5067 0.0481 118.6071 ;
			 LAYER V2 ;
			RECT 0.021 118.5816 0.0359 118.5941 ;
		END

		ANTENNADIFFAREA 0.00194719 ;
		ANTENNAPARTIALMETALAREA 0.00195671 ;
	END WENY[43]

	PIN WENY[44]
		USE SIGNAL ;
		DIRECTION OUTPUT ;
		SHAPE ABUTMENT ;
		PORT
			 LAYER M2 ;
			RECT 0.0098 121.0667 0.0481 121.1671 ;
			 LAYER M3 ;
			RECT 0.0098 121.0667 0.0481 121.1671 ;
			 LAYER V2 ;
			RECT 0.021 121.1416 0.0359 121.1541 ;
		END

		ANTENNADIFFAREA 0.00194719 ;
		ANTENNAPARTIALMETALAREA 0.00195671 ;
	END WENY[44]

	PIN WENY[45]
		USE SIGNAL ;
		DIRECTION OUTPUT ;
		SHAPE ABUTMENT ;
		PORT
			 LAYER M2 ;
			RECT 0.0098 123.6267 0.0481 123.7271 ;
			 LAYER M3 ;
			RECT 0.0098 123.6267 0.0481 123.7271 ;
			 LAYER V2 ;
			RECT 0.021 123.7016 0.0359 123.7141 ;
		END

		ANTENNADIFFAREA 0.00194719 ;
		ANTENNAPARTIALMETALAREA 0.00195671 ;
	END WENY[45]

	PIN WENY[46]
		USE SIGNAL ;
		DIRECTION OUTPUT ;
		SHAPE ABUTMENT ;
		PORT
			 LAYER M2 ;
			RECT 0.0098 126.1867 0.0481 126.2871 ;
			 LAYER M3 ;
			RECT 0.0098 126.1867 0.0481 126.2871 ;
			 LAYER V2 ;
			RECT 0.021 126.2616 0.0359 126.2741 ;
		END

		ANTENNADIFFAREA 0.00194719 ;
		ANTENNAPARTIALMETALAREA 0.00195671 ;
	END WENY[46]

	PIN WENY[47]
		USE SIGNAL ;
		DIRECTION OUTPUT ;
		SHAPE ABUTMENT ;
		PORT
			 LAYER M2 ;
			RECT 0.0098 128.7467 0.0481 128.8471 ;
			 LAYER M3 ;
			RECT 0.0098 128.7467 0.0481 128.8471 ;
			 LAYER V2 ;
			RECT 0.021 128.8216 0.0359 128.8341 ;
		END

		ANTENNADIFFAREA 0.00194719 ;
		ANTENNAPARTIALMETALAREA 0.00195671 ;
	END WENY[47]

	PIN WENY[48]
		USE SIGNAL ;
		DIRECTION OUTPUT ;
		SHAPE ABUTMENT ;
		PORT
			 LAYER M2 ;
			RECT 0.0098 131.3067 0.0481 131.4071 ;
			 LAYER M3 ;
			RECT 0.0098 131.3067 0.0481 131.4071 ;
			 LAYER V2 ;
			RECT 0.021 131.3816 0.0359 131.3941 ;
		END

		ANTENNADIFFAREA 0.00194719 ;
		ANTENNAPARTIALMETALAREA 0.00195671 ;
	END WENY[48]

	PIN WENY[49]
		USE SIGNAL ;
		DIRECTION OUTPUT ;
		SHAPE ABUTMENT ;
		PORT
			 LAYER M2 ;
			RECT 0.0098 133.8667 0.0481 133.9671 ;
			 LAYER M3 ;
			RECT 0.0098 133.8667 0.0481 133.9671 ;
			 LAYER V2 ;
			RECT 0.021 133.9416 0.0359 133.9541 ;
		END

		ANTENNADIFFAREA 0.00194719 ;
		ANTENNAPARTIALMETALAREA 0.00195671 ;
	END WENY[49]

	PIN WENY[4]
		USE SIGNAL ;
		DIRECTION OUTPUT ;
		SHAPE ABUTMENT ;
		PORT
			 LAYER M2 ;
			RECT 0.0098 12.7624 0.0481 12.8627 ;
			 LAYER M3 ;
			RECT 0.0098 12.7624 0.0481 12.8627 ;
			 LAYER V2 ;
			RECT 0.021 12.7753 0.0359 12.7878 ;
		END

		ANTENNADIFFAREA 0.00194719 ;
		ANTENNAPARTIALMETALAREA 0.00195671 ;
	END WENY[4]

	PIN WENY[50]
		USE SIGNAL ;
		DIRECTION OUTPUT ;
		SHAPE ABUTMENT ;
		PORT
			 LAYER M2 ;
			RECT 0.0098 136.4267 0.0481 136.5271 ;
			 LAYER M3 ;
			RECT 0.0098 136.4267 0.0481 136.5271 ;
			 LAYER V2 ;
			RECT 0.021 136.5016 0.0359 136.5141 ;
		END

		ANTENNADIFFAREA 0.00194719 ;
		ANTENNAPARTIALMETALAREA 0.00195671 ;
	END WENY[50]

	PIN WENY[51]
		USE SIGNAL ;
		DIRECTION OUTPUT ;
		SHAPE ABUTMENT ;
		PORT
			 LAYER M2 ;
			RECT 0.0098 138.9867 0.0481 139.0871 ;
			 LAYER M3 ;
			RECT 0.0098 138.9867 0.0481 139.0871 ;
			 LAYER V2 ;
			RECT 0.021 139.0616 0.0359 139.0741 ;
		END

		ANTENNADIFFAREA 0.00194719 ;
		ANTENNAPARTIALMETALAREA 0.00195671 ;
	END WENY[51]

	PIN WENY[52]
		USE SIGNAL ;
		DIRECTION OUTPUT ;
		SHAPE ABUTMENT ;
		PORT
			 LAYER M2 ;
			RECT 0.0098 141.5467 0.0481 141.6471 ;
			 LAYER M3 ;
			RECT 0.0098 141.5467 0.0481 141.6471 ;
			 LAYER V2 ;
			RECT 0.021 141.6216 0.0359 141.6341 ;
		END

		ANTENNADIFFAREA 0.00194719 ;
		ANTENNAPARTIALMETALAREA 0.00195671 ;
	END WENY[52]

	PIN WENY[53]
		USE SIGNAL ;
		DIRECTION OUTPUT ;
		SHAPE ABUTMENT ;
		PORT
			 LAYER M2 ;
			RECT 0.0098 144.1067 0.0481 144.2071 ;
			 LAYER M3 ;
			RECT 0.0098 144.1067 0.0481 144.2071 ;
			 LAYER V2 ;
			RECT 0.021 144.1816 0.0359 144.1941 ;
		END

		ANTENNADIFFAREA 0.00194719 ;
		ANTENNAPARTIALMETALAREA 0.00195671 ;
	END WENY[53]

	PIN WENY[54]
		USE SIGNAL ;
		DIRECTION OUTPUT ;
		SHAPE ABUTMENT ;
		PORT
			 LAYER M2 ;
			RECT 0.0098 154.3655 0.0481 154.4659 ;
			 LAYER M3 ;
			RECT 0.0098 154.3655 0.0481 154.4659 ;
			 LAYER V2 ;
			RECT 0.021 154.4404 0.0359 154.4529 ;
		END

		ANTENNADIFFAREA 0.00194719 ;
		ANTENNAPARTIALMETALAREA 0.00195671 ;
	END WENY[54]

	PIN WENY[55]
		USE SIGNAL ;
		DIRECTION OUTPUT ;
		SHAPE ABUTMENT ;
		PORT
			 LAYER M2 ;
			RECT 0.0098 156.9255 0.0481 157.0259 ;
			 LAYER M3 ;
			RECT 0.0098 156.9255 0.0481 157.0259 ;
			 LAYER V2 ;
			RECT 0.021 157.0004 0.0359 157.0129 ;
		END

		ANTENNADIFFAREA 0.00194719 ;
		ANTENNAPARTIALMETALAREA 0.00195671 ;
	END WENY[55]

	PIN WENY[56]
		USE SIGNAL ;
		DIRECTION OUTPUT ;
		SHAPE ABUTMENT ;
		PORT
			 LAYER M2 ;
			RECT 0.0098 159.4855 0.0481 159.5859 ;
			 LAYER M3 ;
			RECT 0.0098 159.4855 0.0481 159.5859 ;
			 LAYER V2 ;
			RECT 0.021 159.5604 0.0359 159.5729 ;
		END

		ANTENNADIFFAREA 0.00194719 ;
		ANTENNAPARTIALMETALAREA 0.00195671 ;
	END WENY[56]

	PIN WENY[57]
		USE SIGNAL ;
		DIRECTION OUTPUT ;
		SHAPE ABUTMENT ;
		PORT
			 LAYER M2 ;
			RECT 0.0098 162.0455 0.0481 162.1459 ;
			 LAYER M3 ;
			RECT 0.0098 162.0455 0.0481 162.1459 ;
			 LAYER V2 ;
			RECT 0.021 162.1204 0.0359 162.1329 ;
		END

		ANTENNADIFFAREA 0.00194719 ;
		ANTENNAPARTIALMETALAREA 0.00195671 ;
	END WENY[57]

	PIN WENY[58]
		USE SIGNAL ;
		DIRECTION OUTPUT ;
		SHAPE ABUTMENT ;
		PORT
			 LAYER M2 ;
			RECT 0.0098 164.6055 0.0481 164.7059 ;
			 LAYER M3 ;
			RECT 0.0098 164.6055 0.0481 164.7059 ;
			 LAYER V2 ;
			RECT 0.021 164.6804 0.0359 164.6929 ;
		END

		ANTENNADIFFAREA 0.00194719 ;
		ANTENNAPARTIALMETALAREA 0.00195671 ;
	END WENY[58]

	PIN WENY[59]
		USE SIGNAL ;
		DIRECTION OUTPUT ;
		SHAPE ABUTMENT ;
		PORT
			 LAYER M2 ;
			RECT 0.0098 167.1655 0.0481 167.2659 ;
			 LAYER M3 ;
			RECT 0.0098 167.1655 0.0481 167.2659 ;
			 LAYER V2 ;
			RECT 0.021 167.2404 0.0359 167.2529 ;
		END

		ANTENNADIFFAREA 0.00194719 ;
		ANTENNAPARTIALMETALAREA 0.00195671 ;
	END WENY[59]

	PIN WENY[5]
		USE SIGNAL ;
		DIRECTION OUTPUT ;
		SHAPE ABUTMENT ;
		PORT
			 LAYER M2 ;
			RECT 0.0098 15.3224 0.0481 15.4227 ;
			 LAYER M3 ;
			RECT 0.0098 15.3224 0.0481 15.4227 ;
			 LAYER V2 ;
			RECT 0.021 15.3353 0.0359 15.3478 ;
		END

		ANTENNADIFFAREA 0.00194719 ;
		ANTENNAPARTIALMETALAREA 0.00195671 ;
	END WENY[5]

	PIN WENY[60]
		USE SIGNAL ;
		DIRECTION OUTPUT ;
		SHAPE ABUTMENT ;
		PORT
			 LAYER M2 ;
			RECT 0.0098 169.7255 0.0481 169.8259 ;
			 LAYER M3 ;
			RECT 0.0098 169.7255 0.0481 169.8259 ;
			 LAYER V2 ;
			RECT 0.021 169.8004 0.0359 169.8129 ;
		END

		ANTENNADIFFAREA 0.00194719 ;
		ANTENNAPARTIALMETALAREA 0.00195671 ;
	END WENY[60]

	PIN WENY[61]
		USE SIGNAL ;
		DIRECTION OUTPUT ;
		SHAPE ABUTMENT ;
		PORT
			 LAYER M2 ;
			RECT 0.0098 172.2855 0.0481 172.3859 ;
			 LAYER M3 ;
			RECT 0.0098 172.2855 0.0481 172.3859 ;
			 LAYER V2 ;
			RECT 0.021 172.3604 0.0359 172.3729 ;
		END

		ANTENNADIFFAREA 0.00194719 ;
		ANTENNAPARTIALMETALAREA 0.00195671 ;
	END WENY[61]

	PIN WENY[62]
		USE SIGNAL ;
		DIRECTION OUTPUT ;
		SHAPE ABUTMENT ;
		PORT
			 LAYER M2 ;
			RECT 0.0098 174.8455 0.0481 174.9459 ;
			 LAYER M3 ;
			RECT 0.0098 174.8455 0.0481 174.9459 ;
			 LAYER V2 ;
			RECT 0.021 174.9204 0.0359 174.9329 ;
		END

		ANTENNADIFFAREA 0.00194719 ;
		ANTENNAPARTIALMETALAREA 0.00195671 ;
	END WENY[62]

	PIN WENY[63]
		USE SIGNAL ;
		DIRECTION OUTPUT ;
		SHAPE ABUTMENT ;
		PORT
			 LAYER M2 ;
			RECT 0.0098 177.4055 0.0481 177.5059 ;
			 LAYER M3 ;
			RECT 0.0098 177.4055 0.0481 177.5059 ;
			 LAYER V2 ;
			RECT 0.021 177.4804 0.0359 177.4929 ;
		END

		ANTENNADIFFAREA 0.00194719 ;
		ANTENNAPARTIALMETALAREA 0.00195671 ;
	END WENY[63]

	PIN WENY[64]
		USE SIGNAL ;
		DIRECTION OUTPUT ;
		SHAPE ABUTMENT ;
		PORT
			 LAYER M2 ;
			RECT 0.0098 179.9655 0.0481 180.0659 ;
			 LAYER M3 ;
			RECT 0.0098 179.9655 0.0481 180.0659 ;
			 LAYER V2 ;
			RECT 0.021 180.0404 0.0359 180.0529 ;
		END

		ANTENNADIFFAREA 0.00194719 ;
		ANTENNAPARTIALMETALAREA 0.00195671 ;
	END WENY[64]

	PIN WENY[65]
		USE SIGNAL ;
		DIRECTION OUTPUT ;
		SHAPE ABUTMENT ;
		PORT
			 LAYER M2 ;
			RECT 0.0098 182.5255 0.0481 182.6259 ;
			 LAYER M3 ;
			RECT 0.0098 182.5255 0.0481 182.6259 ;
			 LAYER V2 ;
			RECT 0.021 182.6004 0.0359 182.6129 ;
		END

		ANTENNADIFFAREA 0.00194719 ;
		ANTENNAPARTIALMETALAREA 0.00195671 ;
	END WENY[65]

	PIN WENY[66]
		USE SIGNAL ;
		DIRECTION OUTPUT ;
		SHAPE ABUTMENT ;
		PORT
			 LAYER M2 ;
			RECT 0.0098 185.0855 0.0481 185.1859 ;
			 LAYER M3 ;
			RECT 0.0098 185.0855 0.0481 185.1859 ;
			 LAYER V2 ;
			RECT 0.021 185.1604 0.0359 185.1729 ;
		END

		ANTENNADIFFAREA 0.00194719 ;
		ANTENNAPARTIALMETALAREA 0.00195671 ;
	END WENY[66]

	PIN WENY[67]
		USE SIGNAL ;
		DIRECTION OUTPUT ;
		SHAPE ABUTMENT ;
		PORT
			 LAYER M2 ;
			RECT 0.0098 187.6455 0.0481 187.7459 ;
			 LAYER M3 ;
			RECT 0.0098 187.6455 0.0481 187.7459 ;
			 LAYER V2 ;
			RECT 0.021 187.7204 0.0359 187.7329 ;
		END

		ANTENNADIFFAREA 0.00194719 ;
		ANTENNAPARTIALMETALAREA 0.00195671 ;
	END WENY[67]

	PIN WENY[68]
		USE SIGNAL ;
		DIRECTION OUTPUT ;
		SHAPE ABUTMENT ;
		PORT
			 LAYER M2 ;
			RECT 0.0098 190.2055 0.0481 190.3059 ;
			 LAYER M3 ;
			RECT 0.0098 190.2055 0.0481 190.3059 ;
			 LAYER V2 ;
			RECT 0.021 190.2804 0.0359 190.2929 ;
		END

		ANTENNADIFFAREA 0.00194719 ;
		ANTENNAPARTIALMETALAREA 0.00195671 ;
	END WENY[68]

	PIN WENY[69]
		USE SIGNAL ;
		DIRECTION OUTPUT ;
		SHAPE ABUTMENT ;
		PORT
			 LAYER M2 ;
			RECT 0.0098 192.7655 0.0481 192.8659 ;
			 LAYER M3 ;
			RECT 0.0098 192.7655 0.0481 192.8659 ;
			 LAYER V2 ;
			RECT 0.021 192.8404 0.0359 192.8529 ;
		END

		ANTENNADIFFAREA 0.00194719 ;
		ANTENNAPARTIALMETALAREA 0.00195671 ;
	END WENY[69]

	PIN WENY[6]
		USE SIGNAL ;
		DIRECTION OUTPUT ;
		SHAPE ABUTMENT ;
		PORT
			 LAYER M2 ;
			RECT 0.0098 17.8824 0.0481 17.9827 ;
			 LAYER M3 ;
			RECT 0.0098 17.8824 0.0481 17.9827 ;
			 LAYER V2 ;
			RECT 0.021 17.8953 0.0359 17.9078 ;
		END

		ANTENNADIFFAREA 0.00194719 ;
		ANTENNAPARTIALMETALAREA 0.00195671 ;
	END WENY[6]

	PIN WENY[70]
		USE SIGNAL ;
		DIRECTION OUTPUT ;
		SHAPE ABUTMENT ;
		PORT
			 LAYER M2 ;
			RECT 0.0098 195.3255 0.0481 195.4259 ;
			 LAYER M3 ;
			RECT 0.0098 195.3255 0.0481 195.4259 ;
			 LAYER V2 ;
			RECT 0.021 195.4004 0.0359 195.4129 ;
		END

		ANTENNADIFFAREA 0.00194719 ;
		ANTENNAPARTIALMETALAREA 0.00195671 ;
	END WENY[70]

	PIN WENY[71]
		USE SIGNAL ;
		DIRECTION OUTPUT ;
		SHAPE ABUTMENT ;
		PORT
			 LAYER M2 ;
			RECT 0.0098 197.8855 0.0481 197.9859 ;
			 LAYER M3 ;
			RECT 0.0098 197.8855 0.0481 197.9859 ;
			 LAYER V2 ;
			RECT 0.021 197.9604 0.0359 197.9729 ;
		END

		ANTENNADIFFAREA 0.00194719 ;
		ANTENNAPARTIALMETALAREA 0.00195671 ;
	END WENY[71]

	PIN WENY[7]
		USE SIGNAL ;
		DIRECTION OUTPUT ;
		SHAPE ABUTMENT ;
		PORT
			 LAYER M2 ;
			RECT 0.0098 20.4424 0.0481 20.5427 ;
			 LAYER M3 ;
			RECT 0.0098 20.4424 0.0481 20.5427 ;
			 LAYER V2 ;
			RECT 0.021 20.4553 0.0359 20.4678 ;
		END

		ANTENNADIFFAREA 0.00194719 ;
		ANTENNAPARTIALMETALAREA 0.00195671 ;
	END WENY[7]

	PIN WENY[8]
		USE SIGNAL ;
		DIRECTION OUTPUT ;
		SHAPE ABUTMENT ;
		PORT
			 LAYER M2 ;
			RECT 0.0098 23.0024 0.0481 23.1027 ;
			 LAYER M3 ;
			RECT 0.0098 23.0024 0.0481 23.1027 ;
			 LAYER V2 ;
			RECT 0.021 23.0153 0.0359 23.0278 ;
		END

		ANTENNADIFFAREA 0.00194719 ;
		ANTENNAPARTIALMETALAREA 0.00195671 ;
	END WENY[8]

	PIN WENY[9]
		USE SIGNAL ;
		DIRECTION OUTPUT ;
		SHAPE ABUTMENT ;
		PORT
			 LAYER M2 ;
			RECT 0.0098 25.5624 0.0481 25.6627 ;
			 LAYER M3 ;
			RECT 0.0098 25.5624 0.0481 25.6627 ;
			 LAYER V2 ;
			RECT 0.021 25.5753 0.0359 25.5878 ;
		END

		ANTENNADIFFAREA 0.00194719 ;
		ANTENNAPARTIALMETALAREA 0.00195671 ;
	END WENY[9]

	PIN WEN[0]
		USE SIGNAL ;
		DIRECTION INPUT ;
		SHAPE ABUTMENT ;
		PORT
			 LAYER M2 ;
			RECT 0.0714 2.309 0.1097 2.3467 ;
			 LAYER M3 ;
			RECT 0.0714 2.2463 0.1097 2.3467 ;
			 LAYER V2 ;
			RECT 0.0831 2.322 0.098 2.3345 ;
		END

		ANTENNAGATEAREA 0.00027817 ;
		ANTENNADIFFAREA 0.00194719 ;
		ANTENNAPARTIALMETALAREA 0.00195671 ;
	END WEN[0]

	PIN WEN[10]
		USE SIGNAL ;
		DIRECTION INPUT ;
		SHAPE ABUTMENT ;
		PORT
			 LAYER M2 ;
			RECT 0.0714 27.909 0.1097 27.9467 ;
			 LAYER M3 ;
			RECT 0.0714 27.8463 0.1097 27.9467 ;
			 LAYER V2 ;
			RECT 0.0831 27.922 0.098 27.9345 ;
		END

		ANTENNAGATEAREA 0.00027817 ;
		ANTENNADIFFAREA 0.00194719 ;
		ANTENNAPARTIALMETALAREA 0.00195671 ;
	END WEN[10]

	PIN WEN[11]
		USE SIGNAL ;
		DIRECTION INPUT ;
		SHAPE ABUTMENT ;
		PORT
			 LAYER M2 ;
			RECT 0.0714 30.469 0.1097 30.5067 ;
			 LAYER M3 ;
			RECT 0.0714 30.4063 0.1097 30.5067 ;
			 LAYER V2 ;
			RECT 0.0831 30.482 0.098 30.4945 ;
		END

		ANTENNAGATEAREA 0.00027817 ;
		ANTENNADIFFAREA 0.00194719 ;
		ANTENNAPARTIALMETALAREA 0.00195671 ;
	END WEN[11]

	PIN WEN[12]
		USE SIGNAL ;
		DIRECTION INPUT ;
		SHAPE ABUTMENT ;
		PORT
			 LAYER M2 ;
			RECT 0.0714 33.029 0.1097 33.0667 ;
			 LAYER M3 ;
			RECT 0.0714 32.9663 0.1097 33.0667 ;
			 LAYER V2 ;
			RECT 0.0831 33.042 0.098 33.0545 ;
		END

		ANTENNAGATEAREA 0.00027817 ;
		ANTENNADIFFAREA 0.00194719 ;
		ANTENNAPARTIALMETALAREA 0.00195671 ;
	END WEN[12]

	PIN WEN[13]
		USE SIGNAL ;
		DIRECTION INPUT ;
		SHAPE ABUTMENT ;
		PORT
			 LAYER M2 ;
			RECT 0.0714 35.589 0.1097 35.6267 ;
			 LAYER M3 ;
			RECT 0.0714 35.5263 0.1097 35.6267 ;
			 LAYER V2 ;
			RECT 0.0831 35.602 0.098 35.6145 ;
		END

		ANTENNAGATEAREA 0.00027817 ;
		ANTENNADIFFAREA 0.00194719 ;
		ANTENNAPARTIALMETALAREA 0.00195671 ;
	END WEN[13]

	PIN WEN[14]
		USE SIGNAL ;
		DIRECTION INPUT ;
		SHAPE ABUTMENT ;
		PORT
			 LAYER M2 ;
			RECT 0.0714 38.149 0.1097 38.1867 ;
			 LAYER M3 ;
			RECT 0.0714 38.0863 0.1097 38.1867 ;
			 LAYER V2 ;
			RECT 0.0831 38.162 0.098 38.1745 ;
		END

		ANTENNAGATEAREA 0.00027817 ;
		ANTENNADIFFAREA 0.00194719 ;
		ANTENNAPARTIALMETALAREA 0.00195671 ;
	END WEN[14]

	PIN WEN[15]
		USE SIGNAL ;
		DIRECTION INPUT ;
		SHAPE ABUTMENT ;
		PORT
			 LAYER M2 ;
			RECT 0.0714 40.709 0.1097 40.7467 ;
			 LAYER M3 ;
			RECT 0.0714 40.6463 0.1097 40.7467 ;
			 LAYER V2 ;
			RECT 0.0831 40.722 0.098 40.7345 ;
		END

		ANTENNAGATEAREA 0.00027817 ;
		ANTENNADIFFAREA 0.00194719 ;
		ANTENNAPARTIALMETALAREA 0.00195671 ;
	END WEN[15]

	PIN WEN[16]
		USE SIGNAL ;
		DIRECTION INPUT ;
		SHAPE ABUTMENT ;
		PORT
			 LAYER M2 ;
			RECT 0.0714 43.269 0.1097 43.3067 ;
			 LAYER M3 ;
			RECT 0.0714 43.2063 0.1097 43.3067 ;
			 LAYER V2 ;
			RECT 0.0831 43.282 0.098 43.2945 ;
		END

		ANTENNAGATEAREA 0.00027817 ;
		ANTENNADIFFAREA 0.00194719 ;
		ANTENNAPARTIALMETALAREA 0.00195671 ;
	END WEN[16]

	PIN WEN[17]
		USE SIGNAL ;
		DIRECTION INPUT ;
		SHAPE ABUTMENT ;
		PORT
			 LAYER M2 ;
			RECT 0.0714 45.829 0.1097 45.8667 ;
			 LAYER M3 ;
			RECT 0.0714 45.7663 0.1097 45.8667 ;
			 LAYER V2 ;
			RECT 0.0831 45.842 0.098 45.8545 ;
		END

		ANTENNAGATEAREA 0.00027817 ;
		ANTENNADIFFAREA 0.00194719 ;
		ANTENNAPARTIALMETALAREA 0.00195671 ;
	END WEN[17]

	PIN WEN[18]
		USE SIGNAL ;
		DIRECTION INPUT ;
		SHAPE ABUTMENT ;
		PORT
			 LAYER M2 ;
			RECT 0.0714 56.0878 0.1097 56.1255 ;
			 LAYER M3 ;
			RECT 0.0714 56.0251 0.1097 56.1255 ;
			 LAYER V2 ;
			RECT 0.0831 56.1008 0.098 56.1133 ;
		END

		ANTENNAGATEAREA 0.00027817 ;
		ANTENNADIFFAREA 0.00194719 ;
		ANTENNAPARTIALMETALAREA 0.00195671 ;
	END WEN[18]

	PIN WEN[19]
		USE SIGNAL ;
		DIRECTION INPUT ;
		SHAPE ABUTMENT ;
		PORT
			 LAYER M2 ;
			RECT 0.0714 58.6478 0.1097 58.6855 ;
			 LAYER M3 ;
			RECT 0.0714 58.5851 0.1097 58.6855 ;
			 LAYER V2 ;
			RECT 0.0831 58.6608 0.098 58.6733 ;
		END

		ANTENNAGATEAREA 0.00027817 ;
		ANTENNADIFFAREA 0.00194719 ;
		ANTENNAPARTIALMETALAREA 0.00195671 ;
	END WEN[19]

	PIN WEN[1]
		USE SIGNAL ;
		DIRECTION INPUT ;
		SHAPE ABUTMENT ;
		PORT
			 LAYER M2 ;
			RECT 0.0714 4.869 0.1097 4.9067 ;
			 LAYER M3 ;
			RECT 0.0714 4.8063 0.1097 4.9067 ;
			 LAYER V2 ;
			RECT 0.0831 4.882 0.098 4.8945 ;
		END

		ANTENNAGATEAREA 0.00027817 ;
		ANTENNADIFFAREA 0.00194719 ;
		ANTENNAPARTIALMETALAREA 0.00195671 ;
	END WEN[1]

	PIN WEN[20]
		USE SIGNAL ;
		DIRECTION INPUT ;
		SHAPE ABUTMENT ;
		PORT
			 LAYER M2 ;
			RECT 0.0714 61.2078 0.1097 61.2455 ;
			 LAYER M3 ;
			RECT 0.0714 61.1451 0.1097 61.2455 ;
			 LAYER V2 ;
			RECT 0.0831 61.2208 0.098 61.2333 ;
		END

		ANTENNAGATEAREA 0.00027817 ;
		ANTENNADIFFAREA 0.00194719 ;
		ANTENNAPARTIALMETALAREA 0.00195671 ;
	END WEN[20]

	PIN WEN[21]
		USE SIGNAL ;
		DIRECTION INPUT ;
		SHAPE ABUTMENT ;
		PORT
			 LAYER M2 ;
			RECT 0.0714 63.7678 0.1097 63.8055 ;
			 LAYER M3 ;
			RECT 0.0714 63.7051 0.1097 63.8055 ;
			 LAYER V2 ;
			RECT 0.0831 63.7808 0.098 63.7933 ;
		END

		ANTENNAGATEAREA 0.00027817 ;
		ANTENNADIFFAREA 0.00194719 ;
		ANTENNAPARTIALMETALAREA 0.00195671 ;
	END WEN[21]

	PIN WEN[22]
		USE SIGNAL ;
		DIRECTION INPUT ;
		SHAPE ABUTMENT ;
		PORT
			 LAYER M2 ;
			RECT 0.0714 66.3278 0.1097 66.3655 ;
			 LAYER M3 ;
			RECT 0.0714 66.2651 0.1097 66.3655 ;
			 LAYER V2 ;
			RECT 0.0831 66.3408 0.098 66.3533 ;
		END

		ANTENNAGATEAREA 0.00027817 ;
		ANTENNADIFFAREA 0.00194719 ;
		ANTENNAPARTIALMETALAREA 0.00195671 ;
	END WEN[22]

	PIN WEN[23]
		USE SIGNAL ;
		DIRECTION INPUT ;
		SHAPE ABUTMENT ;
		PORT
			 LAYER M2 ;
			RECT 0.0714 68.8878 0.1097 68.9255 ;
			 LAYER M3 ;
			RECT 0.0714 68.8251 0.1097 68.9255 ;
			 LAYER V2 ;
			RECT 0.0831 68.9008 0.098 68.9133 ;
		END

		ANTENNAGATEAREA 0.00027817 ;
		ANTENNADIFFAREA 0.00194719 ;
		ANTENNAPARTIALMETALAREA 0.00195671 ;
	END WEN[23]

	PIN WEN[24]
		USE SIGNAL ;
		DIRECTION INPUT ;
		SHAPE ABUTMENT ;
		PORT
			 LAYER M2 ;
			RECT 0.0714 71.4478 0.1097 71.4855 ;
			 LAYER M3 ;
			RECT 0.0714 71.3851 0.1097 71.4855 ;
			 LAYER V2 ;
			RECT 0.0831 71.4608 0.098 71.4733 ;
		END

		ANTENNAGATEAREA 0.00027817 ;
		ANTENNADIFFAREA 0.00194719 ;
		ANTENNAPARTIALMETALAREA 0.00195671 ;
	END WEN[24]

	PIN WEN[25]
		USE SIGNAL ;
		DIRECTION INPUT ;
		SHAPE ABUTMENT ;
		PORT
			 LAYER M2 ;
			RECT 0.0714 74.0078 0.1097 74.0455 ;
			 LAYER M3 ;
			RECT 0.0714 73.9451 0.1097 74.0455 ;
			 LAYER V2 ;
			RECT 0.0831 74.0208 0.098 74.0333 ;
		END

		ANTENNAGATEAREA 0.00027817 ;
		ANTENNADIFFAREA 0.00194719 ;
		ANTENNAPARTIALMETALAREA 0.00195671 ;
	END WEN[25]

	PIN WEN[26]
		USE SIGNAL ;
		DIRECTION INPUT ;
		SHAPE ABUTMENT ;
		PORT
			 LAYER M2 ;
			RECT 0.0714 76.5678 0.1097 76.6055 ;
			 LAYER M3 ;
			RECT 0.0714 76.5051 0.1097 76.6055 ;
			 LAYER V2 ;
			RECT 0.0831 76.5808 0.098 76.5933 ;
		END

		ANTENNAGATEAREA 0.00027817 ;
		ANTENNADIFFAREA 0.00194719 ;
		ANTENNAPARTIALMETALAREA 0.00195671 ;
	END WEN[26]

	PIN WEN[27]
		USE SIGNAL ;
		DIRECTION INPUT ;
		SHAPE ABUTMENT ;
		PORT
			 LAYER M2 ;
			RECT 0.0714 79.1278 0.1097 79.1655 ;
			 LAYER M3 ;
			RECT 0.0714 79.0651 0.1097 79.1655 ;
			 LAYER V2 ;
			RECT 0.0831 79.1408 0.098 79.1533 ;
		END

		ANTENNAGATEAREA 0.00027817 ;
		ANTENNADIFFAREA 0.00194719 ;
		ANTENNAPARTIALMETALAREA 0.00195671 ;
	END WEN[27]

	PIN WEN[28]
		USE SIGNAL ;
		DIRECTION INPUT ;
		SHAPE ABUTMENT ;
		PORT
			 LAYER M2 ;
			RECT 0.0714 81.6878 0.1097 81.7255 ;
			 LAYER M3 ;
			RECT 0.0714 81.6251 0.1097 81.7255 ;
			 LAYER V2 ;
			RECT 0.0831 81.7008 0.098 81.7133 ;
		END

		ANTENNAGATEAREA 0.00027817 ;
		ANTENNADIFFAREA 0.00194719 ;
		ANTENNAPARTIALMETALAREA 0.00195671 ;
	END WEN[28]

	PIN WEN[29]
		USE SIGNAL ;
		DIRECTION INPUT ;
		SHAPE ABUTMENT ;
		PORT
			 LAYER M2 ;
			RECT 0.0714 84.2478 0.1097 84.2855 ;
			 LAYER M3 ;
			RECT 0.0714 84.1851 0.1097 84.2855 ;
			 LAYER V2 ;
			RECT 0.0831 84.2608 0.098 84.2733 ;
		END

		ANTENNAGATEAREA 0.00027817 ;
		ANTENNADIFFAREA 0.00194719 ;
		ANTENNAPARTIALMETALAREA 0.00195671 ;
	END WEN[29]

	PIN WEN[2]
		USE SIGNAL ;
		DIRECTION INPUT ;
		SHAPE ABUTMENT ;
		PORT
			 LAYER M2 ;
			RECT 0.0714 7.429 0.1097 7.4667 ;
			 LAYER M3 ;
			RECT 0.0714 7.3663 0.1097 7.4667 ;
			 LAYER V2 ;
			RECT 0.0831 7.442 0.098 7.4545 ;
		END

		ANTENNAGATEAREA 0.00027817 ;
		ANTENNADIFFAREA 0.00194719 ;
		ANTENNAPARTIALMETALAREA 0.00195671 ;
	END WEN[2]

	PIN WEN[30]
		USE SIGNAL ;
		DIRECTION INPUT ;
		SHAPE ABUTMENT ;
		PORT
			 LAYER M2 ;
			RECT 0.0714 86.8078 0.1097 86.8455 ;
			 LAYER M3 ;
			RECT 0.0714 86.7451 0.1097 86.8455 ;
			 LAYER V2 ;
			RECT 0.0831 86.8208 0.098 86.8333 ;
		END

		ANTENNAGATEAREA 0.00027817 ;
		ANTENNADIFFAREA 0.00194719 ;
		ANTENNAPARTIALMETALAREA 0.00195671 ;
	END WEN[30]

	PIN WEN[31]
		USE SIGNAL ;
		DIRECTION INPUT ;
		SHAPE ABUTMENT ;
		PORT
			 LAYER M2 ;
			RECT 0.0714 90.0329 0.1097 90.0706 ;
			 LAYER M3 ;
			RECT 0.0714 90.0329 0.1097 90.1333 ;
			 LAYER V2 ;
			RECT 0.0831 90.0451 0.098 90.0576 ;
		END

		ANTENNAGATEAREA 0.00027817 ;
		ANTENNADIFFAREA 0.00194719 ;
		ANTENNAPARTIALMETALAREA 0.00195671 ;
	END WEN[31]

	PIN WEN[32]
		USE SIGNAL ;
		DIRECTION INPUT ;
		SHAPE ABUTMENT ;
		PORT
			 LAYER M2 ;
			RECT 0.0714 92.2165 0.1097 92.2541 ;
			 LAYER M3 ;
			RECT 0.0714 92.2165 0.1097 92.3169 ;
			 LAYER V2 ;
			RECT 0.0831 92.2286 0.098 92.2412 ;
		END

		ANTENNAGATEAREA 0.00027817 ;
		ANTENNADIFFAREA 0.00194719 ;
		ANTENNAPARTIALMETALAREA 0.00195671 ;
	END WEN[32]

	PIN WEN[33]
		USE SIGNAL ;
		DIRECTION INPUT ;
		SHAPE ABUTMENT ;
		PORT
			 LAYER M2 ;
			RECT 0.0098 94.9647 0.0481 95.0024 ;
			 LAYER M3 ;
			RECT 0.0098 94.902 0.0481 95.0024 ;
			 LAYER V2 ;
			RECT 0.0215 94.9769 0.0364 94.9894 ;
		END

		ANTENNAGATEAREA 0.00027817 ;
		ANTENNADIFFAREA 0.00194719 ;
		ANTENNAPARTIALMETALAREA 0.00195671 ;
	END WEN[33]

	PIN WEN[34]
		USE SIGNAL ;
		DIRECTION INPUT ;
		SHAPE ABUTMENT ;
		PORT
			 LAYER M2 ;
			RECT 0.0098 97.211 0.0481 97.3114 ;
			 LAYER M3 ;
			RECT 0.0098 97.211 0.0481 97.3114 ;
			 LAYER V2 ;
			RECT 0.021 97.2859 0.0359 97.2984 ;
		END

		ANTENNAGATEAREA 0.00027817 ;
		ANTENNADIFFAREA 0.00194719 ;
		ANTENNAPARTIALMETALAREA 0.00195671 ;
	END WEN[34]

	PIN WEN[35]
		USE SIGNAL ;
		DIRECTION INPUT ;
		SHAPE ABUTMENT ;
		PORT
			 LAYER M2 ;
			RECT 0.0098 99.8337 0.0481 99.8714 ;
			 LAYER M3 ;
			RECT 0.0098 99.771 0.0481 99.8714 ;
			 LAYER V2 ;
			RECT 0.0215 99.8459 0.0364 99.8584 ;
		END

		ANTENNAGATEAREA 0.00027817 ;
		ANTENNADIFFAREA 0.00194719 ;
		ANTENNAPARTIALMETALAREA 0.00195671 ;
	END WEN[35]

	PIN WEN[36]
		USE SIGNAL ;
		DIRECTION INPUT ;
		SHAPE ABUTMENT ;
		PORT
			 LAYER M2 ;
			RECT 0.0098 100.6118 0.0481 100.6494 ;
			 LAYER M3 ;
			RECT 0.0098 100.6118 0.0481 100.7122 ;
			 LAYER V2 ;
			RECT 0.0215 100.6247 0.0364 100.6373 ;
		END

		ANTENNAGATEAREA 0.00027817 ;
		ANTENNADIFFAREA 0.00194719 ;
		ANTENNAPARTIALMETALAREA 0.00195671 ;
	END WEN[36]

	PIN WEN[37]
		USE SIGNAL ;
		DIRECTION INPUT ;
		SHAPE ABUTMENT ;
		PORT
			 LAYER M2 ;
			RECT 0.0098 103.1718 0.0481 103.2722 ;
			 LAYER M3 ;
			RECT 0.0098 103.1718 0.0481 103.2722 ;
			 LAYER V2 ;
			RECT 0.021 103.1847 0.0359 103.1973 ;
		END

		ANTENNAGATEAREA 0.00027817 ;
		ANTENNADIFFAREA 0.00194719 ;
		ANTENNAPARTIALMETALAREA 0.00195671 ;
	END WEN[37]

	PIN WEN[38]
		USE SIGNAL ;
		DIRECTION INPUT ;
		SHAPE ABUTMENT ;
		PORT
			 LAYER M2 ;
			RECT 0.0714 105.4933 0.1097 105.531 ;
			 LAYER M3 ;
			RECT 0.0714 105.4306 0.1097 105.531 ;
			 LAYER V2 ;
			RECT 0.0831 105.5063 0.098 105.5188 ;
		END

		ANTENNAGATEAREA 0.00027817 ;
		ANTENNADIFFAREA 0.00194719 ;
		ANTENNAPARTIALMETALAREA 0.00195671 ;
	END WEN[38]

	PIN WEN[39]
		USE SIGNAL ;
		DIRECTION INPUT ;
		SHAPE ABUTMENT ;
		PORT
			 LAYER M2 ;
			RECT 0.0714 108.2792 0.1097 108.3169 ;
			 LAYER M3 ;
			RECT 0.0714 108.2165 0.1097 108.3169 ;
			 LAYER V2 ;
			RECT 0.0831 108.2922 0.098 108.3047 ;
		END

		ANTENNAGATEAREA 0.00027817 ;
		ANTENNADIFFAREA 0.00194719 ;
		ANTENNAPARTIALMETALAREA 0.00195671 ;
	END WEN[39]

	PIN WEN[3]
		USE SIGNAL ;
		DIRECTION INPUT ;
		SHAPE ABUTMENT ;
		PORT
			 LAYER M2 ;
			RECT 0.0714 9.989 0.1097 10.0267 ;
			 LAYER M3 ;
			RECT 0.0714 9.9263 0.1097 10.0267 ;
			 LAYER V2 ;
			RECT 0.0831 10.002 0.098 10.0145 ;
		END

		ANTENNAGATEAREA 0.00027817 ;
		ANTENNADIFFAREA 0.00194719 ;
		ANTENNAPARTIALMETALAREA 0.00195671 ;
	END WEN[3]

	PIN WEN[40]
		USE SIGNAL ;
		DIRECTION INPUT ;
		SHAPE ABUTMENT ;
		PORT
			 LAYER M2 ;
			RECT 0.0098 110.4 0.0481 110.5004 ;
			 LAYER M3 ;
			RECT 0.0098 110.4 0.0481 110.5004 ;
			 LAYER V2 ;
			RECT 0.021 110.4749 0.0359 110.4875 ;
		END

		ANTENNAGATEAREA 0.00027817 ;
		ANTENNADIFFAREA 0.00194719 ;
		ANTENNAPARTIALMETALAREA 0.00195671 ;
	END WEN[40]

	PIN WEN[41]
		USE SIGNAL ;
		DIRECTION INPUT ;
		SHAPE ABUTMENT ;
		PORT
			 LAYER M2 ;
			RECT 0.0714 113.6627 0.1097 113.7004 ;
			 LAYER M3 ;
			RECT 0.0714 113.6627 0.1097 113.7631 ;
			 LAYER V2 ;
			RECT 0.0831 113.6749 0.098 113.6875 ;
		END

		ANTENNAGATEAREA 0.00027817 ;
		ANTENNADIFFAREA 0.00194719 ;
		ANTENNAPARTIALMETALAREA 0.00195671 ;
	END WEN[41]

	PIN WEN[42]
		USE SIGNAL ;
		DIRECTION INPUT ;
		SHAPE ABUTMENT ;
		PORT
			 LAYER M2 ;
			RECT 0.0714 116.2227 0.1097 116.2604 ;
			 LAYER M3 ;
			RECT 0.0714 116.2227 0.1097 116.3231 ;
			 LAYER V2 ;
			RECT 0.0831 116.2349 0.098 116.2475 ;
		END

		ANTENNAGATEAREA 0.00027817 ;
		ANTENNADIFFAREA 0.00194719 ;
		ANTENNAPARTIALMETALAREA 0.00195671 ;
	END WEN[42]

	PIN WEN[43]
		USE SIGNAL ;
		DIRECTION INPUT ;
		SHAPE ABUTMENT ;
		PORT
			 LAYER M2 ;
			RECT 0.0714 118.7827 0.1097 118.8204 ;
			 LAYER M3 ;
			RECT 0.0714 118.7827 0.1097 118.8831 ;
			 LAYER V2 ;
			RECT 0.0831 118.7949 0.098 118.8075 ;
		END

		ANTENNAGATEAREA 0.00027817 ;
		ANTENNADIFFAREA 0.00194719 ;
		ANTENNAPARTIALMETALAREA 0.00195671 ;
	END WEN[43]

	PIN WEN[44]
		USE SIGNAL ;
		DIRECTION INPUT ;
		SHAPE ABUTMENT ;
		PORT
			 LAYER M2 ;
			RECT 0.0714 121.3427 0.1097 121.3804 ;
			 LAYER M3 ;
			RECT 0.0714 121.3427 0.1097 121.4431 ;
			 LAYER V2 ;
			RECT 0.0831 121.3549 0.098 121.3675 ;
		END

		ANTENNAGATEAREA 0.00027817 ;
		ANTENNADIFFAREA 0.00194719 ;
		ANTENNAPARTIALMETALAREA 0.00195671 ;
	END WEN[44]

	PIN WEN[45]
		USE SIGNAL ;
		DIRECTION INPUT ;
		SHAPE ABUTMENT ;
		PORT
			 LAYER M2 ;
			RECT 0.0714 123.9027 0.1097 123.9404 ;
			 LAYER M3 ;
			RECT 0.0714 123.9027 0.1097 124.0031 ;
			 LAYER V2 ;
			RECT 0.0831 123.9149 0.098 123.9275 ;
		END

		ANTENNAGATEAREA 0.00027817 ;
		ANTENNADIFFAREA 0.00194719 ;
		ANTENNAPARTIALMETALAREA 0.00195671 ;
	END WEN[45]

	PIN WEN[46]
		USE SIGNAL ;
		DIRECTION INPUT ;
		SHAPE ABUTMENT ;
		PORT
			 LAYER M2 ;
			RECT 0.0714 126.4627 0.1097 126.5004 ;
			 LAYER M3 ;
			RECT 0.0714 126.4627 0.1097 126.5631 ;
			 LAYER V2 ;
			RECT 0.0831 126.4749 0.098 126.4875 ;
		END

		ANTENNAGATEAREA 0.00027817 ;
		ANTENNADIFFAREA 0.00194719 ;
		ANTENNAPARTIALMETALAREA 0.00195671 ;
	END WEN[46]

	PIN WEN[47]
		USE SIGNAL ;
		DIRECTION INPUT ;
		SHAPE ABUTMENT ;
		PORT
			 LAYER M2 ;
			RECT 0.0714 129.0227 0.1097 129.0604 ;
			 LAYER M3 ;
			RECT 0.0714 129.0227 0.1097 129.1231 ;
			 LAYER V2 ;
			RECT 0.0831 129.0349 0.098 129.0475 ;
		END

		ANTENNAGATEAREA 0.00027817 ;
		ANTENNADIFFAREA 0.00194719 ;
		ANTENNAPARTIALMETALAREA 0.00195671 ;
	END WEN[47]

	PIN WEN[48]
		USE SIGNAL ;
		DIRECTION INPUT ;
		SHAPE ABUTMENT ;
		PORT
			 LAYER M2 ;
			RECT 0.0714 131.5827 0.1097 131.6204 ;
			 LAYER M3 ;
			RECT 0.0714 131.5827 0.1097 131.6831 ;
			 LAYER V2 ;
			RECT 0.0831 131.5949 0.098 131.6075 ;
		END

		ANTENNAGATEAREA 0.00027817 ;
		ANTENNADIFFAREA 0.00194719 ;
		ANTENNAPARTIALMETALAREA 0.00195671 ;
	END WEN[48]

	PIN WEN[49]
		USE SIGNAL ;
		DIRECTION INPUT ;
		SHAPE ABUTMENT ;
		PORT
			 LAYER M2 ;
			RECT 0.0714 134.1427 0.1097 134.1804 ;
			 LAYER M3 ;
			RECT 0.0714 134.1427 0.1097 134.2431 ;
			 LAYER V2 ;
			RECT 0.0831 134.1549 0.098 134.1675 ;
		END

		ANTENNAGATEAREA 0.00027817 ;
		ANTENNADIFFAREA 0.00194719 ;
		ANTENNAPARTIALMETALAREA 0.00195671 ;
	END WEN[49]

	PIN WEN[4]
		USE SIGNAL ;
		DIRECTION INPUT ;
		SHAPE ABUTMENT ;
		PORT
			 LAYER M2 ;
			RECT 0.0714 12.549 0.1097 12.5867 ;
			 LAYER M3 ;
			RECT 0.0714 12.4863 0.1097 12.5867 ;
			 LAYER V2 ;
			RECT 0.0831 12.562 0.098 12.5745 ;
		END

		ANTENNAGATEAREA 0.00027817 ;
		ANTENNADIFFAREA 0.00194719 ;
		ANTENNAPARTIALMETALAREA 0.00195671 ;
	END WEN[4]

	PIN WEN[50]
		USE SIGNAL ;
		DIRECTION INPUT ;
		SHAPE ABUTMENT ;
		PORT
			 LAYER M2 ;
			RECT 0.0714 136.7027 0.1097 136.7404 ;
			 LAYER M3 ;
			RECT 0.0714 136.7027 0.1097 136.8031 ;
			 LAYER V2 ;
			RECT 0.0831 136.7149 0.098 136.7275 ;
		END

		ANTENNAGATEAREA 0.00027817 ;
		ANTENNADIFFAREA 0.00194719 ;
		ANTENNAPARTIALMETALAREA 0.00195671 ;
	END WEN[50]

	PIN WEN[51]
		USE SIGNAL ;
		DIRECTION INPUT ;
		SHAPE ABUTMENT ;
		PORT
			 LAYER M2 ;
			RECT 0.0714 139.2627 0.1097 139.3004 ;
			 LAYER M3 ;
			RECT 0.0714 139.2627 0.1097 139.3631 ;
			 LAYER V2 ;
			RECT 0.0831 139.2749 0.098 139.2875 ;
		END

		ANTENNAGATEAREA 0.00027817 ;
		ANTENNADIFFAREA 0.00194719 ;
		ANTENNAPARTIALMETALAREA 0.00195671 ;
	END WEN[51]

	PIN WEN[52]
		USE SIGNAL ;
		DIRECTION INPUT ;
		SHAPE ABUTMENT ;
		PORT
			 LAYER M2 ;
			RECT 0.0714 141.8227 0.1097 141.8604 ;
			 LAYER M3 ;
			RECT 0.0714 141.8227 0.1097 141.9231 ;
			 LAYER V2 ;
			RECT 0.0831 141.8349 0.098 141.8475 ;
		END

		ANTENNAGATEAREA 0.00027817 ;
		ANTENNADIFFAREA 0.00194719 ;
		ANTENNAPARTIALMETALAREA 0.00195671 ;
	END WEN[52]

	PIN WEN[53]
		USE SIGNAL ;
		DIRECTION INPUT ;
		SHAPE ABUTMENT ;
		PORT
			 LAYER M2 ;
			RECT 0.0714 144.3827 0.1097 144.4204 ;
			 LAYER M3 ;
			RECT 0.0714 144.3827 0.1097 144.4831 ;
			 LAYER V2 ;
			RECT 0.0831 144.3949 0.098 144.4075 ;
		END

		ANTENNAGATEAREA 0.00027817 ;
		ANTENNADIFFAREA 0.00194719 ;
		ANTENNAPARTIALMETALAREA 0.00195671 ;
	END WEN[53]

	PIN WEN[54]
		USE SIGNAL ;
		DIRECTION INPUT ;
		SHAPE ABUTMENT ;
		PORT
			 LAYER M2 ;
			RECT 0.0714 154.6416 0.1097 154.6792 ;
			 LAYER M3 ;
			RECT 0.0714 154.6416 0.1097 154.742 ;
			 LAYER V2 ;
			RECT 0.0831 154.6537 0.098 154.6663 ;
		END

		ANTENNAGATEAREA 0.00027817 ;
		ANTENNADIFFAREA 0.00194719 ;
		ANTENNAPARTIALMETALAREA 0.00195671 ;
	END WEN[54]

	PIN WEN[55]
		USE SIGNAL ;
		DIRECTION INPUT ;
		SHAPE ABUTMENT ;
		PORT
			 LAYER M2 ;
			RECT 0.0714 157.2016 0.1097 157.2392 ;
			 LAYER M3 ;
			RECT 0.0714 157.2016 0.1097 157.302 ;
			 LAYER V2 ;
			RECT 0.0831 157.2137 0.098 157.2263 ;
		END

		ANTENNAGATEAREA 0.00027817 ;
		ANTENNADIFFAREA 0.00194719 ;
		ANTENNAPARTIALMETALAREA 0.00195671 ;
	END WEN[55]

	PIN WEN[56]
		USE SIGNAL ;
		DIRECTION INPUT ;
		SHAPE ABUTMENT ;
		PORT
			 LAYER M2 ;
			RECT 0.0714 159.7616 0.1097 159.7992 ;
			 LAYER M3 ;
			RECT 0.0714 159.7616 0.1097 159.862 ;
			 LAYER V2 ;
			RECT 0.0831 159.7737 0.098 159.7863 ;
		END

		ANTENNAGATEAREA 0.00027817 ;
		ANTENNADIFFAREA 0.00194719 ;
		ANTENNAPARTIALMETALAREA 0.00195671 ;
	END WEN[56]

	PIN WEN[57]
		USE SIGNAL ;
		DIRECTION INPUT ;
		SHAPE ABUTMENT ;
		PORT
			 LAYER M2 ;
			RECT 0.0714 162.3216 0.1097 162.3592 ;
			 LAYER M3 ;
			RECT 0.0714 162.3216 0.1097 162.422 ;
			 LAYER V2 ;
			RECT 0.0831 162.3337 0.098 162.3463 ;
		END

		ANTENNAGATEAREA 0.00027817 ;
		ANTENNADIFFAREA 0.00194719 ;
		ANTENNAPARTIALMETALAREA 0.00195671 ;
	END WEN[57]

	PIN WEN[58]
		USE SIGNAL ;
		DIRECTION INPUT ;
		SHAPE ABUTMENT ;
		PORT
			 LAYER M2 ;
			RECT 0.0714 164.8816 0.1097 164.9192 ;
			 LAYER M3 ;
			RECT 0.0714 164.8816 0.1097 164.982 ;
			 LAYER V2 ;
			RECT 0.0831 164.8937 0.098 164.9063 ;
		END

		ANTENNAGATEAREA 0.00027817 ;
		ANTENNADIFFAREA 0.00194719 ;
		ANTENNAPARTIALMETALAREA 0.00195671 ;
	END WEN[58]

	PIN WEN[59]
		USE SIGNAL ;
		DIRECTION INPUT ;
		SHAPE ABUTMENT ;
		PORT
			 LAYER M2 ;
			RECT 0.0714 167.4416 0.1097 167.4792 ;
			 LAYER M3 ;
			RECT 0.0714 167.4416 0.1097 167.542 ;
			 LAYER V2 ;
			RECT 0.0831 167.4537 0.098 167.4663 ;
		END

		ANTENNAGATEAREA 0.00027817 ;
		ANTENNADIFFAREA 0.00194719 ;
		ANTENNAPARTIALMETALAREA 0.00195671 ;
	END WEN[59]

	PIN WEN[5]
		USE SIGNAL ;
		DIRECTION INPUT ;
		SHAPE ABUTMENT ;
		PORT
			 LAYER M2 ;
			RECT 0.0714 15.109 0.1097 15.1467 ;
			 LAYER M3 ;
			RECT 0.0714 15.0463 0.1097 15.1467 ;
			 LAYER V2 ;
			RECT 0.0831 15.122 0.098 15.1345 ;
		END

		ANTENNAGATEAREA 0.00027817 ;
		ANTENNADIFFAREA 0.00194719 ;
		ANTENNAPARTIALMETALAREA 0.00195671 ;
	END WEN[5]

	PIN WEN[60]
		USE SIGNAL ;
		DIRECTION INPUT ;
		SHAPE ABUTMENT ;
		PORT
			 LAYER M2 ;
			RECT 0.0714 170.0016 0.1097 170.0392 ;
			 LAYER M3 ;
			RECT 0.0714 170.0016 0.1097 170.102 ;
			 LAYER V2 ;
			RECT 0.0831 170.0137 0.098 170.0263 ;
		END

		ANTENNAGATEAREA 0.00027817 ;
		ANTENNADIFFAREA 0.00194719 ;
		ANTENNAPARTIALMETALAREA 0.00195671 ;
	END WEN[60]

	PIN WEN[61]
		USE SIGNAL ;
		DIRECTION INPUT ;
		SHAPE ABUTMENT ;
		PORT
			 LAYER M2 ;
			RECT 0.0714 172.5616 0.1097 172.5992 ;
			 LAYER M3 ;
			RECT 0.0714 172.5616 0.1097 172.662 ;
			 LAYER V2 ;
			RECT 0.0831 172.5737 0.098 172.5863 ;
		END

		ANTENNAGATEAREA 0.00027817 ;
		ANTENNADIFFAREA 0.00194719 ;
		ANTENNAPARTIALMETALAREA 0.00195671 ;
	END WEN[61]

	PIN WEN[62]
		USE SIGNAL ;
		DIRECTION INPUT ;
		SHAPE ABUTMENT ;
		PORT
			 LAYER M2 ;
			RECT 0.0714 175.1216 0.1097 175.1592 ;
			 LAYER M3 ;
			RECT 0.0714 175.1216 0.1097 175.222 ;
			 LAYER V2 ;
			RECT 0.0831 175.1337 0.098 175.1463 ;
		END

		ANTENNAGATEAREA 0.00027817 ;
		ANTENNADIFFAREA 0.00194719 ;
		ANTENNAPARTIALMETALAREA 0.00195671 ;
	END WEN[62]

	PIN WEN[63]
		USE SIGNAL ;
		DIRECTION INPUT ;
		SHAPE ABUTMENT ;
		PORT
			 LAYER M2 ;
			RECT 0.0714 177.6816 0.1097 177.7192 ;
			 LAYER M3 ;
			RECT 0.0714 177.6816 0.1097 177.782 ;
			 LAYER V2 ;
			RECT 0.0831 177.6937 0.098 177.7063 ;
		END

		ANTENNAGATEAREA 0.00027817 ;
		ANTENNADIFFAREA 0.00194719 ;
		ANTENNAPARTIALMETALAREA 0.00195671 ;
	END WEN[63]

	PIN WEN[64]
		USE SIGNAL ;
		DIRECTION INPUT ;
		SHAPE ABUTMENT ;
		PORT
			 LAYER M2 ;
			RECT 0.0714 180.2416 0.1097 180.2792 ;
			 LAYER M3 ;
			RECT 0.0714 180.2416 0.1097 180.342 ;
			 LAYER V2 ;
			RECT 0.0831 180.2537 0.098 180.2663 ;
		END

		ANTENNAGATEAREA 0.00027817 ;
		ANTENNADIFFAREA 0.00194719 ;
		ANTENNAPARTIALMETALAREA 0.00195671 ;
	END WEN[64]

	PIN WEN[65]
		USE SIGNAL ;
		DIRECTION INPUT ;
		SHAPE ABUTMENT ;
		PORT
			 LAYER M2 ;
			RECT 0.0714 182.8016 0.1097 182.8392 ;
			 LAYER M3 ;
			RECT 0.0714 182.8016 0.1097 182.902 ;
			 LAYER V2 ;
			RECT 0.0831 182.8137 0.098 182.8263 ;
		END

		ANTENNAGATEAREA 0.00027817 ;
		ANTENNADIFFAREA 0.00194719 ;
		ANTENNAPARTIALMETALAREA 0.00195671 ;
	END WEN[65]

	PIN WEN[66]
		USE SIGNAL ;
		DIRECTION INPUT ;
		SHAPE ABUTMENT ;
		PORT
			 LAYER M2 ;
			RECT 0.0714 185.3616 0.1097 185.3992 ;
			 LAYER M3 ;
			RECT 0.0714 185.3616 0.1097 185.462 ;
			 LAYER V2 ;
			RECT 0.0831 185.3737 0.098 185.3863 ;
		END

		ANTENNAGATEAREA 0.00027817 ;
		ANTENNADIFFAREA 0.00194719 ;
		ANTENNAPARTIALMETALAREA 0.00195671 ;
	END WEN[66]

	PIN WEN[67]
		USE SIGNAL ;
		DIRECTION INPUT ;
		SHAPE ABUTMENT ;
		PORT
			 LAYER M2 ;
			RECT 0.0714 187.9216 0.1097 187.9592 ;
			 LAYER M3 ;
			RECT 0.0714 187.9216 0.1097 188.022 ;
			 LAYER V2 ;
			RECT 0.0831 187.9337 0.098 187.9463 ;
		END

		ANTENNAGATEAREA 0.00027817 ;
		ANTENNADIFFAREA 0.00194719 ;
		ANTENNAPARTIALMETALAREA 0.00195671 ;
	END WEN[67]

	PIN WEN[68]
		USE SIGNAL ;
		DIRECTION INPUT ;
		SHAPE ABUTMENT ;
		PORT
			 LAYER M2 ;
			RECT 0.0714 190.4816 0.1097 190.5192 ;
			 LAYER M3 ;
			RECT 0.0714 190.4816 0.1097 190.582 ;
			 LAYER V2 ;
			RECT 0.0831 190.4937 0.098 190.5063 ;
		END

		ANTENNAGATEAREA 0.00027817 ;
		ANTENNADIFFAREA 0.00194719 ;
		ANTENNAPARTIALMETALAREA 0.00195671 ;
	END WEN[68]

	PIN WEN[69]
		USE SIGNAL ;
		DIRECTION INPUT ;
		SHAPE ABUTMENT ;
		PORT
			 LAYER M2 ;
			RECT 0.0714 193.0416 0.1097 193.0792 ;
			 LAYER M3 ;
			RECT 0.0714 193.0416 0.1097 193.142 ;
			 LAYER V2 ;
			RECT 0.0831 193.0537 0.098 193.0663 ;
		END

		ANTENNAGATEAREA 0.00027817 ;
		ANTENNADIFFAREA 0.00194719 ;
		ANTENNAPARTIALMETALAREA 0.00195671 ;
	END WEN[69]

	PIN WEN[6]
		USE SIGNAL ;
		DIRECTION INPUT ;
		SHAPE ABUTMENT ;
		PORT
			 LAYER M2 ;
			RECT 0.0714 17.669 0.1097 17.7067 ;
			 LAYER M3 ;
			RECT 0.0714 17.6063 0.1097 17.7067 ;
			 LAYER V2 ;
			RECT 0.0831 17.682 0.098 17.6945 ;
		END

		ANTENNAGATEAREA 0.00027817 ;
		ANTENNADIFFAREA 0.00194719 ;
		ANTENNAPARTIALMETALAREA 0.00195671 ;
	END WEN[6]

	PIN WEN[70]
		USE SIGNAL ;
		DIRECTION INPUT ;
		SHAPE ABUTMENT ;
		PORT
			 LAYER M2 ;
			RECT 0.0714 195.6016 0.1097 195.6392 ;
			 LAYER M3 ;
			RECT 0.0714 195.6016 0.1097 195.702 ;
			 LAYER V2 ;
			RECT 0.0831 195.6137 0.098 195.6263 ;
		END

		ANTENNAGATEAREA 0.00027817 ;
		ANTENNADIFFAREA 0.00194719 ;
		ANTENNAPARTIALMETALAREA 0.00195671 ;
	END WEN[70]

	PIN WEN[71]
		USE SIGNAL ;
		DIRECTION INPUT ;
		SHAPE ABUTMENT ;
		PORT
			 LAYER M2 ;
			RECT 0.0714 198.1616 0.1097 198.1992 ;
			 LAYER M3 ;
			RECT 0.0714 198.1616 0.1097 198.262 ;
			 LAYER V2 ;
			RECT 0.0831 198.1737 0.098 198.1863 ;
		END

		ANTENNAGATEAREA 0.00027817 ;
		ANTENNADIFFAREA 0.00194719 ;
		ANTENNAPARTIALMETALAREA 0.00195671 ;
	END WEN[71]

	PIN WEN[7]
		USE SIGNAL ;
		DIRECTION INPUT ;
		SHAPE ABUTMENT ;
		PORT
			 LAYER M2 ;
			RECT 0.0714 20.229 0.1097 20.2667 ;
			 LAYER M3 ;
			RECT 0.0714 20.1663 0.1097 20.2667 ;
			 LAYER V2 ;
			RECT 0.0831 20.242 0.098 20.2545 ;
		END

		ANTENNAGATEAREA 0.00027817 ;
		ANTENNADIFFAREA 0.00194719 ;
		ANTENNAPARTIALMETALAREA 0.00195671 ;
	END WEN[7]

	PIN WEN[8]
		USE SIGNAL ;
		DIRECTION INPUT ;
		SHAPE ABUTMENT ;
		PORT
			 LAYER M2 ;
			RECT 0.0714 22.789 0.1097 22.8267 ;
			 LAYER M3 ;
			RECT 0.0714 22.7263 0.1097 22.8267 ;
			 LAYER V2 ;
			RECT 0.0831 22.802 0.098 22.8145 ;
		END

		ANTENNAGATEAREA 0.00027817 ;
		ANTENNADIFFAREA 0.00194719 ;
		ANTENNAPARTIALMETALAREA 0.00195671 ;
	END WEN[8]

	PIN WEN[9]
		USE SIGNAL ;
		DIRECTION INPUT ;
		SHAPE ABUTMENT ;
		PORT
			 LAYER M2 ;
			RECT 0.0714 25.349 0.1097 25.3867 ;
			 LAYER M3 ;
			RECT 0.0714 25.2863 0.1097 25.3867 ;
			 LAYER V2 ;
			RECT 0.0831 25.362 0.098 25.3745 ;
		END

		ANTENNAGATEAREA 0.00027817 ;
		ANTENNADIFFAREA 0.00194719 ;
		ANTENNAPARTIALMETALAREA 0.00195671 ;
	END WEN[9]

	OBS
		 LAYER M1 SPACING 0.012 ;
		RECT 0 0 124.383 200.5082 ;
		 LAYER M2 SPACING 0.012 ;
		RECT 0.133 0 124.383 200.5082 ;
		RECT 0 0 0.133 0.0439 ;
		RECT 0 0.182 0.133 2.2275 ;
		RECT 0.0714 2.3718 0.133 2.5035 ;
		RECT 0 2.491 0.133 2.5035 ;
		RECT 0.0714 2.5035 0.133 2.629 ;
		RECT 0 2.7671 0.133 4.7875 ;
		RECT 0.0714 4.9318 0.133 5.0635 ;
		RECT 0 5.051 0.133 5.0635 ;
		RECT 0.0714 5.0635 0.133 5.189 ;
		RECT 0 5.3271 0.133 7.3475 ;
		RECT 0.0714 7.4918 0.133 7.6235 ;
		RECT 0 7.611 0.133 7.6235 ;
		RECT 0.0714 7.6235 0.133 7.749 ;
		RECT 0 7.8871 0.133 9.9075 ;
		RECT 0.0714 10.0518 0.133 10.1835 ;
		RECT 0 10.171 0.133 10.1835 ;
		RECT 0.0714 10.1835 0.133 10.309 ;
		RECT 0 10.4471 0.133 12.4675 ;
		RECT 0.0714 12.6118 0.133 12.7435 ;
		RECT 0 12.731 0.133 12.7435 ;
		RECT 0.0714 12.7435 0.133 12.869 ;
		RECT 0 13.0071 0.133 15.0275 ;
		RECT 0.0714 15.1718 0.133 15.3035 ;
		RECT 0 15.291 0.133 15.3035 ;
		RECT 0.0714 15.3035 0.133 15.429 ;
		RECT 0 15.5671 0.133 17.5875 ;
		RECT 0.0714 17.7318 0.133 17.8635 ;
		RECT 0 17.851 0.133 17.8635 ;
		RECT 0.0714 17.8635 0.133 17.989 ;
		RECT 0 18.1271 0.133 20.1475 ;
		RECT 0.0714 20.2918 0.133 20.4235 ;
		RECT 0 20.411 0.133 20.4235 ;
		RECT 0.0714 20.4235 0.133 20.549 ;
		RECT 0 20.6871 0.133 22.7075 ;
		RECT 0.0714 22.8518 0.133 22.9835 ;
		RECT 0 22.971 0.133 22.9835 ;
		RECT 0.0714 22.9835 0.133 23.109 ;
		RECT 0 23.2471 0.133 25.2675 ;
		RECT 0.0714 25.4118 0.133 25.5435 ;
		RECT 0 25.531 0.133 25.5435 ;
		RECT 0.0714 25.5435 0.133 25.669 ;
		RECT 0 25.8071 0.133 27.8275 ;
		RECT 0.0714 27.9718 0.133 28.1035 ;
		RECT 0 28.091 0.133 28.1035 ;
		RECT 0.0714 28.1035 0.133 28.229 ;
		RECT 0 28.3671 0.133 30.3875 ;
		RECT 0.0714 30.5318 0.133 30.6635 ;
		RECT 0 30.651 0.133 30.6635 ;
		RECT 0.0714 30.6635 0.133 30.789 ;
		RECT 0 30.9271 0.133 32.9475 ;
		RECT 0.0714 33.0918 0.133 33.2235 ;
		RECT 0 33.211 0.133 33.2235 ;
		RECT 0.0714 33.2235 0.133 33.349 ;
		RECT 0 33.4871 0.133 35.5075 ;
		RECT 0.0714 35.6518 0.133 35.7835 ;
		RECT 0 35.771 0.133 35.7835 ;
		RECT 0.0714 35.7835 0.133 35.909 ;
		RECT 0 36.0471 0.133 38.0675 ;
		RECT 0.0714 38.2118 0.133 38.3435 ;
		RECT 0 38.331 0.133 38.3435 ;
		RECT 0.0714 38.3435 0.133 38.469 ;
		RECT 0 38.6071 0.133 40.6275 ;
		RECT 0.0714 40.7718 0.133 40.9035 ;
		RECT 0 40.891 0.133 40.9035 ;
		RECT 0.0714 40.9035 0.133 41.029 ;
		RECT 0 41.1671 0.133 43.1875 ;
		RECT 0.0714 43.3318 0.133 43.4635 ;
		RECT 0 43.451 0.133 43.4635 ;
		RECT 0.0714 43.4635 0.133 43.589 ;
		RECT 0 43.7271 0.133 45.7475 ;
		RECT 0.0714 45.8918 0.133 46.0235 ;
		RECT 0 46.011 0.133 46.0235 ;
		RECT 0.0714 46.0235 0.133 46.149 ;
		RECT 0 46.2871 0.133 56.0063 ;
		RECT 0.0714 56.1506 0.133 56.2824 ;
		RECT 0 56.2698 0.133 56.2824 ;
		RECT 0.0714 56.2824 0.133 56.4078 ;
		RECT 0 56.5459 0.133 58.5663 ;
		RECT 0.0714 58.7106 0.133 58.8424 ;
		RECT 0 58.8298 0.133 58.8424 ;
		RECT 0.0714 58.8424 0.133 58.9678 ;
		RECT 0 59.1059 0.133 61.1263 ;
		RECT 0.0714 61.2706 0.133 61.4024 ;
		RECT 0 61.3898 0.133 61.4024 ;
		RECT 0.0714 61.4024 0.133 61.5278 ;
		RECT 0 61.6659 0.133 63.6863 ;
		RECT 0.0714 63.8306 0.133 63.9624 ;
		RECT 0 63.9498 0.133 63.9624 ;
		RECT 0.0714 63.9624 0.133 64.0878 ;
		RECT 0 64.2259 0.133 66.2463 ;
		RECT 0.0714 66.3906 0.133 66.5224 ;
		RECT 0 66.5098 0.133 66.5224 ;
		RECT 0.0714 66.5224 0.133 66.6478 ;
		RECT 0 66.7859 0.133 68.8063 ;
		RECT 0.0714 68.9506 0.133 69.0824 ;
		RECT 0 69.0698 0.133 69.0824 ;
		RECT 0.0714 69.0824 0.133 69.2078 ;
		RECT 0 69.3459 0.133 71.3663 ;
		RECT 0.0714 71.5106 0.133 71.6424 ;
		RECT 0 71.6298 0.133 71.6424 ;
		RECT 0.0714 71.6424 0.133 71.7678 ;
		RECT 0 71.9059 0.133 73.9263 ;
		RECT 0.0714 74.0706 0.133 74.2024 ;
		RECT 0 74.1898 0.133 74.2024 ;
		RECT 0.0714 74.2024 0.133 74.3278 ;
		RECT 0 74.4659 0.133 76.4863 ;
		RECT 0.0714 76.6306 0.133 76.7624 ;
		RECT 0 76.7498 0.133 76.7624 ;
		RECT 0.0714 76.7624 0.133 76.8878 ;
		RECT 0 77.0259 0.133 79.0463 ;
		RECT 0.0714 79.1906 0.133 79.3224 ;
		RECT 0 79.3098 0.133 79.3224 ;
		RECT 0.0714 79.3224 0.133 79.4478 ;
		RECT 0 79.5859 0.133 81.6063 ;
		RECT 0.0714 81.7506 0.133 81.8824 ;
		RECT 0 81.8698 0.133 81.8824 ;
		RECT 0.0714 81.8824 0.133 82.0078 ;
		RECT 0 82.1459 0.133 84.1663 ;
		RECT 0.0714 84.3106 0.133 84.4424 ;
		RECT 0 84.4298 0.133 84.4424 ;
		RECT 0.0714 84.4424 0.133 84.5678 ;
		RECT 0 84.7059 0.133 86.7263 ;
		RECT 0.0714 86.8706 0.133 87.0024 ;
		RECT 0 86.9898 0.133 87.0024 ;
		RECT 0.0714 87.0024 0.133 87.1278 ;
		RECT 0 87.2659 0.133 87.3537 ;
		RECT 0 87.4918 0.133 88.7592 ;
		RECT 0.0714 88.7592 0.133 89.2361 ;
		RECT 0 88.8973 0.133 89.2361 ;
		RECT 0 89.3741 0.133 89.3867 ;
		RECT 0 89.5247 0.133 89.5373 ;
		RECT 0.0714 89.5373 0.133 89.6878 ;
		RECT 0 89.6753 0.133 89.6878 ;
		RECT 0 89.8259 0.133 89.8635 ;
		RECT 0 90.0016 0.133 90.0141 ;
		RECT 0 90.1522 0.133 90.1647 ;
		RECT 0.0714 90.1647 0.133 90.6416 ;
		RECT 0 90.3027 0.133 90.6416 ;
		RECT 0.0714 90.6416 0.133 90.7922 ;
		RECT 0 90.7796 0.133 90.7922 ;
		RECT 0.0714 90.7922 0.133 91.1184 ;
		RECT 0 90.9302 0.133 91.1184 ;
		RECT 0.0714 91.1184 0.133 91.269 ;
		RECT 0 91.2565 0.133 91.269 ;
		RECT 0.0714 91.269 0.133 91.5702 ;
		RECT 0 91.4071 0.133 91.5702 ;
		RECT 0.0714 91.5702 0.133 91.7459 ;
		RECT 0 91.7082 0.133 91.7459 ;
		RECT 0.0714 91.7459 0.133 91.8714 ;
		RECT 0 92.0094 0.133 92.0471 ;
		RECT 0.0714 92.0471 0.133 92.1976 ;
		RECT 0 92.1851 0.133 92.1976 ;
		RECT 0 92.3357 0.133 92.3733 ;
		RECT 0 92.5114 0.133 92.5239 ;
		RECT 0.0714 92.5239 0.133 93.2769 ;
		RECT 0 92.662 0.133 93.2769 ;
		RECT 0.0714 93.2769 0.133 93.4275 ;
		RECT 0 93.4149 0.133 93.4275 ;
		RECT 0.0714 93.4275 0.133 93.6784 ;
		RECT 0 93.5655 0.133 93.6784 ;
		RECT 0.0714 93.6784 0.133 93.829 ;
		RECT 0 93.8165 0.133 93.829 ;
		RECT 0.0714 93.829 0.133 94.2557 ;
		RECT 0 93.9671 0.133 94.2557 ;
		RECT 0.0714 94.2557 0.133 94.4063 ;
		RECT 0 94.3937 0.133 94.4063 ;
		RECT 0 94.5443 0.133 94.5569 ;
		RECT 0 94.6949 0.133 94.7075 ;
		RECT 0 94.8455 0.133 94.8831 ;
		RECT 0 95.0212 0.133 95.0337 ;
		RECT 0 95.1718 0.133 95.1843 ;
		RECT 0.0714 95.1843 0.133 95.7867 ;
		RECT 0 95.3224 0.133 95.7867 ;
		RECT 0.0714 95.7867 0.133 95.9373 ;
		RECT 0 95.9247 0.133 95.9373 ;
		RECT 0.0714 95.9373 0.133 96.0627 ;
		RECT 0.0714 96.0627 0.133 96.2886 ;
		RECT 0 96.2008 0.133 96.2886 ;
		RECT 0 96.4267 0.133 96.4392 ;
		RECT 0.0714 96.4392 0.133 96.891 ;
		RECT 0 96.5773 0.133 96.891 ;
		RECT 0 97.029 0.133 97.0416 ;
		RECT 0 97.1796 0.133 97.1922 ;
		RECT 0.0714 97.1922 0.133 97.3678 ;
		RECT 0 97.3302 0.133 97.3678 ;
		RECT 0 97.5059 0.133 98.8486 ;
		RECT 0 98.9867 0.133 98.9992 ;
		RECT 0.0714 98.9992 0.133 99.1498 ;
		RECT 0 99.1373 0.133 99.1498 ;
		RECT 0.0714 99.1498 0.133 99.3004 ;
		RECT 0 99.2878 0.133 99.3004 ;
		RECT 0.0714 99.3004 0.133 99.451 ;
		RECT 0 99.4384 0.133 99.451 ;
		RECT 0 99.589 0.133 99.6016 ;
		RECT 0 99.7396 0.133 99.7522 ;
		RECT 0 99.8902 0.133 99.9278 ;
		RECT 0 100.0659 0.133 100.4424 ;
		RECT 0 100.5804 0.133 100.5929 ;
		RECT 0 100.731 0.133 100.7435 ;
		RECT 0 100.8816 0.133 100.8941 ;
		RECT 0 101.0322 0.133 101.0447 ;
		RECT 0 101.1827 0.133 101.2706 ;
		RECT 0 101.4086 0.133 101.4965 ;
		RECT 0 101.6345 0.133 102.4753 ;
		RECT 0.0714 102.4753 0.133 102.8518 ;
		RECT 0 102.6133 0.133 102.8518 ;
		RECT 0 102.9898 0.133 103.0024 ;
		RECT 0 103.1404 0.133 103.1529 ;
		RECT 0.0714 103.1529 0.133 103.3035 ;
		RECT 0 103.291 0.133 103.3035 ;
		RECT 0 103.4416 0.133 103.4541 ;
		RECT 0 103.5922 0.133 103.8306 ;
		RECT 0.0714 103.8306 0.133 104.0565 ;
		RECT 0 103.9686 0.133 104.0565 ;
		RECT 0 104.1945 0.133 105.2612 ;
		RECT 0 105.3992 0.133 105.4118 ;
		RECT 0 105.5498 0.133 105.5624 ;
		RECT 0 105.7004 0.133 105.7129 ;
		RECT 0 105.851 0.133 105.8635 ;
		RECT 0 106.0016 0.133 106.0141 ;
		RECT 0 106.1522 0.133 106.6165 ;
		RECT 0 106.7545 0.133 106.9929 ;
		RECT 0.0714 106.9929 0.133 107.9718 ;
		RECT 0 107.131 0.133 107.9718 ;
		RECT 0.0714 107.9718 0.133 108.1976 ;
		RECT 0 108.1098 0.133 108.1976 ;
		RECT 0 108.3357 0.133 108.4235 ;
		RECT 0 108.5616 0.133 108.5741 ;
		RECT 0 108.7122 0.133 109.7035 ;
		RECT 0.0714 109.7035 0.133 110.3812 ;
		RECT 0 109.8416 0.133 110.3812 ;
		RECT 0.0714 110.3812 0.133 110.6071 ;
		RECT 0 110.5192 0.133 110.6071 ;
		RECT 0.0714 110.6071 0.133 110.9835 ;
		RECT 0 110.7451 0.133 110.9835 ;
		RECT 0 111.1216 0.133 111.1341 ;
		RECT 0 111.2722 0.133 111.5106 ;
		RECT 0 111.6486 0.133 112.3388 ;
		RECT 0.0714 112.3388 0.133 113.0165 ;
		RECT 0 112.4769 0.133 113.0165 ;
		RECT 0 113.1545 0.133 113.2424 ;
		RECT 0.0714 113.3867 0.133 113.5184 ;
		RECT 0 113.5059 0.133 113.5184 ;
		RECT 0.0714 113.5184 0.133 113.6439 ;
		RECT 0 113.782 0.133 115.8024 ;
		RECT 0.0714 115.9467 0.133 116.0784 ;
		RECT 0 116.0659 0.133 116.0784 ;
		RECT 0.0714 116.0784 0.133 116.2039 ;
		RECT 0 116.342 0.133 118.3624 ;
		RECT 0.0714 118.5067 0.133 118.6384 ;
		RECT 0 118.6259 0.133 118.6384 ;
		RECT 0.0714 118.6384 0.133 118.7639 ;
		RECT 0 118.902 0.133 120.9224 ;
		RECT 0.0714 121.0667 0.133 121.1984 ;
		RECT 0 121.1859 0.133 121.1984 ;
		RECT 0.0714 121.1984 0.133 121.3239 ;
		RECT 0 121.462 0.133 123.4824 ;
		RECT 0.0714 123.6267 0.133 123.7584 ;
		RECT 0 123.7459 0.133 123.7584 ;
		RECT 0.0714 123.7584 0.133 123.8839 ;
		RECT 0 124.022 0.133 126.0424 ;
		RECT 0.0714 126.1867 0.133 126.3184 ;
		RECT 0 126.3059 0.133 126.3184 ;
		RECT 0.0714 126.3184 0.133 126.4439 ;
		RECT 0 126.582 0.133 128.6024 ;
		RECT 0.0714 128.7467 0.133 128.8784 ;
		RECT 0 128.8659 0.133 128.8784 ;
		RECT 0.0714 128.8784 0.133 129.0039 ;
		RECT 0 129.142 0.133 131.1624 ;
		RECT 0.0714 131.3067 0.133 131.4384 ;
		RECT 0 131.4259 0.133 131.4384 ;
		RECT 0.0714 131.4384 0.133 131.5639 ;
		RECT 0 131.702 0.133 133.7224 ;
		RECT 0.0714 133.8667 0.133 133.9984 ;
		RECT 0 133.9859 0.133 133.9984 ;
		RECT 0.0714 133.9984 0.133 134.1239 ;
		RECT 0 134.262 0.133 136.2824 ;
		RECT 0.0714 136.4267 0.133 136.5584 ;
		RECT 0 136.5459 0.133 136.5584 ;
		RECT 0.0714 136.5584 0.133 136.6839 ;
		RECT 0 136.822 0.133 138.8424 ;
		RECT 0.0714 138.9867 0.133 139.1184 ;
		RECT 0 139.1059 0.133 139.1184 ;
		RECT 0.0714 139.1184 0.133 139.2439 ;
		RECT 0 139.382 0.133 141.4024 ;
		RECT 0.0714 141.5467 0.133 141.6784 ;
		RECT 0 141.6659 0.133 141.6784 ;
		RECT 0.0714 141.6784 0.133 141.8039 ;
		RECT 0 141.942 0.133 143.9624 ;
		RECT 0.0714 144.1067 0.133 144.2384 ;
		RECT 0 144.2259 0.133 144.2384 ;
		RECT 0.0714 144.2384 0.133 144.3639 ;
		RECT 0 144.502 0.133 154.2212 ;
		RECT 0.0714 154.3655 0.133 154.4973 ;
		RECT 0 154.4847 0.133 154.4973 ;
		RECT 0.0714 154.4973 0.133 154.6227 ;
		RECT 0 154.7608 0.133 156.7812 ;
		RECT 0.0714 156.9255 0.133 157.0573 ;
		RECT 0 157.0447 0.133 157.0573 ;
		RECT 0.0714 157.0573 0.133 157.1827 ;
		RECT 0 157.3208 0.133 159.3412 ;
		RECT 0.0714 159.4855 0.133 159.6173 ;
		RECT 0 159.6047 0.133 159.6173 ;
		RECT 0.0714 159.6173 0.133 159.7427 ;
		RECT 0 159.8808 0.133 161.9012 ;
		RECT 0.0714 162.0455 0.133 162.1773 ;
		RECT 0 162.1647 0.133 162.1773 ;
		RECT 0.0714 162.1773 0.133 162.3027 ;
		RECT 0 162.4408 0.133 164.4612 ;
		RECT 0.0714 164.6055 0.133 164.7373 ;
		RECT 0 164.7247 0.133 164.7373 ;
		RECT 0.0714 164.7373 0.133 164.8627 ;
		RECT 0 165.0008 0.133 167.0212 ;
		RECT 0.0714 167.1655 0.133 167.2973 ;
		RECT 0 167.2847 0.133 167.2973 ;
		RECT 0.0714 167.2973 0.133 167.4227 ;
		RECT 0 167.5608 0.133 169.5812 ;
		RECT 0.0714 169.7255 0.133 169.8573 ;
		RECT 0 169.8447 0.133 169.8573 ;
		RECT 0.0714 169.8573 0.133 169.9827 ;
		RECT 0 170.1208 0.133 172.1412 ;
		RECT 0.0714 172.2855 0.133 172.4173 ;
		RECT 0 172.4047 0.133 172.4173 ;
		RECT 0.0714 172.4173 0.133 172.5427 ;
		RECT 0 172.6808 0.133 174.7012 ;
		RECT 0.0714 174.8455 0.133 174.9773 ;
		RECT 0 174.9647 0.133 174.9773 ;
		RECT 0.0714 174.9773 0.133 175.1027 ;
		RECT 0 175.2408 0.133 177.2612 ;
		RECT 0.0714 177.4055 0.133 177.5373 ;
		RECT 0 177.5247 0.133 177.5373 ;
		RECT 0.0714 177.5373 0.133 177.6627 ;
		RECT 0 177.8008 0.133 179.8212 ;
		RECT 0.0714 179.9655 0.133 180.0973 ;
		RECT 0 180.0847 0.133 180.0973 ;
		RECT 0.0714 180.0973 0.133 180.2227 ;
		RECT 0 180.3608 0.133 182.3812 ;
		RECT 0.0714 182.5255 0.133 182.6573 ;
		RECT 0 182.6447 0.133 182.6573 ;
		RECT 0.0714 182.6573 0.133 182.7827 ;
		RECT 0 182.9208 0.133 184.9412 ;
		RECT 0.0714 185.0855 0.133 185.2173 ;
		RECT 0 185.2047 0.133 185.2173 ;
		RECT 0.0714 185.2173 0.133 185.3427 ;
		RECT 0 185.4808 0.133 187.5012 ;
		RECT 0.0714 187.6455 0.133 187.7773 ;
		RECT 0 187.7647 0.133 187.7773 ;
		RECT 0.0714 187.7773 0.133 187.9027 ;
		RECT 0 188.0408 0.133 190.0612 ;
		RECT 0.0714 190.2055 0.133 190.3373 ;
		RECT 0 190.3247 0.133 190.3373 ;
		RECT 0.0714 190.3373 0.133 190.4627 ;
		RECT 0 190.6008 0.133 192.6212 ;
		RECT 0.0714 192.7655 0.133 192.8973 ;
		RECT 0 192.8847 0.133 192.8973 ;
		RECT 0.0714 192.8973 0.133 193.0227 ;
		RECT 0 193.1608 0.133 195.1812 ;
		RECT 0.0714 195.3255 0.133 195.4573 ;
		RECT 0 195.4447 0.133 195.4573 ;
		RECT 0.0714 195.4573 0.133 195.5827 ;
		RECT 0 195.7208 0.133 197.7412 ;
		RECT 0.0714 197.8855 0.133 198.0173 ;
		RECT 0 198.0047 0.133 198.0173 ;
		RECT 0.0714 198.0173 0.133 198.1427 ;
		RECT 0 198.2808 0.133 200.3263 ;
		RECT 0 200.4643 0.133 200.5082 ;
		 LAYER M2 ;
		RECT 0.0098 46.5694 0.0481 46.6698 ;
		RECT 0.0098 47.0212 0.0481 47.1216 ;
		RECT 0.0098 52.869 0.0481 52.9694 ;
		RECT 0.0098 53.2706 0.0481 53.371 ;
		RECT 0.0098 90.9616 0.0481 91.062 ;
		RECT 0.0098 97.4494 0.0481 97.4871 ;
		RECT 0.0098 97.5122 0.0481 97.6125 ;
		RECT 0.0098 97.8133 0.0481 97.9137 ;
		RECT 0.0098 0.1255 0.0481 0.1631 ;
		RECT 0.0098 153.8384 0.0481 153.9388 ;
		RECT 0.0098 153.3867 0.0481 153.4871 ;
		RECT 0.0098 153.2345 0.0481 153.3349 ;
		RECT 0.0098 47.1733 0.0481 47.2737 ;
		RECT 0.0098 152.9851 0.0481 153.0855 ;
		RECT 0.0098 152.4329 0.0481 152.5333 ;
		RECT 0.0098 150.8769 0.0481 150.9773 ;
		RECT 0.0098 149.8478 0.0481 149.9482 ;
		RECT 0.0098 149.5216 0.0481 149.622 ;
		RECT 0.0098 149.12 0.0481 149.2204 ;
		RECT 0.0098 148.0408 0.0481 148.1412 ;
		RECT 0.0098 147.7145 0.0481 147.8149 ;
		RECT 0.0098 147.5388 0.0481 147.6392 ;
		RECT 0.0098 147.1373 0.0481 147.2376 ;
		RECT 0.0098 47.4227 0.0481 47.5231 ;
		RECT 0.0098 112.5961 0.0481 112.6965 ;
		RECT 0.0098 112.2071 0.0481 112.3075 ;
		RECT 0.0098 111.5294 0.0481 111.5671 ;
		RECT 0.0098 109.5216 0.0481 109.622 ;
		RECT 0.0714 102.9333 0.1097 102.971 ;
		RECT 0.0098 101.9169 0.0481 102.0173 ;
		RECT 0.0098 101.7663 0.0481 101.8667 ;
		RECT 0.0098 101.0635 0.0481 101.1012 ;
		RECT 0.0098 200.3451 0.0481 200.3827 ;
		RECT 0.0098 47.9749 0.0481 48.0753 ;
		RECT 0.0098 50.56 0.0481 50.6604 ;
		RECT 0.0098 50.8863 0.0481 50.9867 ;
		RECT 0.0098 51.2878 0.0481 51.3882 ;
		RECT 0.0098 52.3671 0.0481 52.4675 ;
		RECT 0.0098 52.6933 0.0481 52.7937 ;
		 LAYER M2 SPACING 0.012 ;
		RECT 0.0098 46.5694 0.0481 46.6698 ;
		RECT 0.0098 47.0212 0.0481 47.1216 ;
		RECT 0.0098 52.869 0.0481 52.9694 ;
		RECT 0.0098 53.2706 0.0481 53.371 ;
		RECT 0.0098 90.9616 0.0481 91.062 ;
		RECT 0.0098 97.4494 0.0481 97.4871 ;
		RECT 0.0098 97.5122 0.0481 97.6125 ;
		RECT 0.0098 97.8133 0.0481 97.9137 ;
		RECT 0.0098 0.1255 0.0481 0.1631 ;
		RECT 0.0098 153.8384 0.0481 153.9388 ;
		RECT 0.0098 153.3867 0.0481 153.4871 ;
		RECT 0.0098 153.2345 0.0481 153.3349 ;
		RECT 0.0098 47.1733 0.0481 47.2737 ;
		RECT 0.0098 152.9851 0.0481 153.0855 ;
		RECT 0.0098 152.4329 0.0481 152.5333 ;
		RECT 0.0098 150.8769 0.0481 150.9773 ;
		RECT 0.0098 149.8478 0.0481 149.9482 ;
		RECT 0.0098 149.5216 0.0481 149.622 ;
		RECT 0.0098 149.12 0.0481 149.2204 ;
		RECT 0.0098 148.0408 0.0481 148.1412 ;
		RECT 0.0098 147.7145 0.0481 147.8149 ;
		RECT 0.0098 147.5388 0.0481 147.6392 ;
		RECT 0.0098 147.1373 0.0481 147.2376 ;
		RECT 0.0098 47.4227 0.0481 47.5231 ;
		RECT 0.0098 112.5961 0.0481 112.6965 ;
		RECT 0.0098 112.2071 0.0481 112.3075 ;
		RECT 0.0098 111.5294 0.0481 111.5671 ;
		RECT 0.0098 109.5216 0.0481 109.622 ;
		RECT 0.0714 102.9333 0.1097 102.971 ;
		RECT 0.0098 101.9169 0.0481 102.0173 ;
		RECT 0.0098 101.7663 0.0481 101.8667 ;
		RECT 0.0098 101.0635 0.0481 101.1012 ;
		RECT 0.0098 200.3451 0.0481 200.3827 ;
		RECT 0.0098 47.9749 0.0481 48.0753 ;
		RECT 0.0098 50.56 0.0481 50.6604 ;
		RECT 0.0098 50.8863 0.0481 50.9867 ;
		RECT 0.0098 51.2878 0.0481 51.3882 ;
		RECT 0.0098 52.3671 0.0481 52.4675 ;
		RECT 0.0098 52.6933 0.0481 52.7937 ;
		 LAYER M3 SPACING 0.012 ;
		RECT 0.133 0 124.383 200.5082 ;
		RECT 0 0 0.133 0.0439 ;
		RECT 0 0.182 0.133 2.2275 ;
		RECT 0.0714 2.3718 0.133 2.5035 ;
		RECT 0 2.491 0.133 2.5035 ;
		RECT 0.0714 2.5035 0.133 2.629 ;
		RECT 0 2.7671 0.133 4.7875 ;
		RECT 0.0714 4.9318 0.133 5.0635 ;
		RECT 0 5.051 0.133 5.0635 ;
		RECT 0.0714 5.0635 0.133 5.189 ;
		RECT 0 5.3271 0.133 7.3475 ;
		RECT 0.0714 7.4918 0.133 7.6235 ;
		RECT 0 7.611 0.133 7.6235 ;
		RECT 0.0714 7.6235 0.133 7.749 ;
		RECT 0 7.8871 0.133 9.9075 ;
		RECT 0.0714 10.0518 0.133 10.1835 ;
		RECT 0 10.171 0.133 10.1835 ;
		RECT 0.0714 10.1835 0.133 10.309 ;
		RECT 0 10.4471 0.133 12.4675 ;
		RECT 0.0714 12.6118 0.133 12.7435 ;
		RECT 0 12.731 0.133 12.7435 ;
		RECT 0.0714 12.7435 0.133 12.869 ;
		RECT 0 13.0071 0.133 15.0275 ;
		RECT 0.0714 15.1718 0.133 15.3035 ;
		RECT 0 15.291 0.133 15.3035 ;
		RECT 0.0714 15.3035 0.133 15.429 ;
		RECT 0 15.5671 0.133 17.5875 ;
		RECT 0.0714 17.7318 0.133 17.8635 ;
		RECT 0 17.851 0.133 17.8635 ;
		RECT 0.0714 17.8635 0.133 17.989 ;
		RECT 0 18.1271 0.133 20.1475 ;
		RECT 0.0714 20.2918 0.133 20.4235 ;
		RECT 0 20.411 0.133 20.4235 ;
		RECT 0.0714 20.4235 0.133 20.549 ;
		RECT 0 20.6871 0.133 22.7075 ;
		RECT 0.0714 22.8518 0.133 22.9835 ;
		RECT 0 22.971 0.133 22.9835 ;
		RECT 0.0714 22.9835 0.133 23.109 ;
		RECT 0 23.2471 0.133 25.2675 ;
		RECT 0.0714 25.4118 0.133 25.5435 ;
		RECT 0 25.531 0.133 25.5435 ;
		RECT 0.0714 25.5435 0.133 25.669 ;
		RECT 0 25.8071 0.133 27.8275 ;
		RECT 0.0714 27.9718 0.133 28.1035 ;
		RECT 0 28.091 0.133 28.1035 ;
		RECT 0.0714 28.1035 0.133 28.229 ;
		RECT 0 28.3671 0.133 30.3875 ;
		RECT 0.0714 30.5318 0.133 30.6635 ;
		RECT 0 30.651 0.133 30.6635 ;
		RECT 0.0714 30.6635 0.133 30.789 ;
		RECT 0 30.9271 0.133 32.9475 ;
		RECT 0.0714 33.0918 0.133 33.2235 ;
		RECT 0 33.211 0.133 33.2235 ;
		RECT 0.0714 33.2235 0.133 33.349 ;
		RECT 0 33.4871 0.133 35.5075 ;
		RECT 0.0714 35.6518 0.133 35.7835 ;
		RECT 0 35.771 0.133 35.7835 ;
		RECT 0.0714 35.7835 0.133 35.909 ;
		RECT 0 36.0471 0.133 38.0675 ;
		RECT 0.0714 38.2118 0.133 38.3435 ;
		RECT 0 38.331 0.133 38.3435 ;
		RECT 0.0714 38.3435 0.133 38.469 ;
		RECT 0 38.6071 0.133 40.6275 ;
		RECT 0.0714 40.7718 0.133 40.9035 ;
		RECT 0 40.891 0.133 40.9035 ;
		RECT 0.0714 40.9035 0.133 41.029 ;
		RECT 0 41.1671 0.133 43.1875 ;
		RECT 0.0714 43.3318 0.133 43.4635 ;
		RECT 0 43.451 0.133 43.4635 ;
		RECT 0.0714 43.4635 0.133 43.589 ;
		RECT 0 43.7271 0.133 45.7475 ;
		RECT 0.0714 45.8918 0.133 46.0235 ;
		RECT 0 46.011 0.133 46.0235 ;
		RECT 0.0714 46.0235 0.133 46.149 ;
		RECT 0 46.2871 0.133 56.0063 ;
		RECT 0.0714 56.1506 0.133 56.2824 ;
		RECT 0 56.2698 0.133 56.2824 ;
		RECT 0.0714 56.2824 0.133 56.4078 ;
		RECT 0 56.5459 0.133 58.5663 ;
		RECT 0.0714 58.7106 0.133 58.8424 ;
		RECT 0 58.8298 0.133 58.8424 ;
		RECT 0.0714 58.8424 0.133 58.9678 ;
		RECT 0 59.1059 0.133 61.1263 ;
		RECT 0.0714 61.2706 0.133 61.4024 ;
		RECT 0 61.3898 0.133 61.4024 ;
		RECT 0.0714 61.4024 0.133 61.5278 ;
		RECT 0 61.6659 0.133 63.6863 ;
		RECT 0.0714 63.8306 0.133 63.9624 ;
		RECT 0 63.9498 0.133 63.9624 ;
		RECT 0.0714 63.9624 0.133 64.0878 ;
		RECT 0 64.2259 0.133 66.2463 ;
		RECT 0.0714 66.3906 0.133 66.5224 ;
		RECT 0 66.5098 0.133 66.5224 ;
		RECT 0.0714 66.5224 0.133 66.6478 ;
		RECT 0 66.7859 0.133 68.8063 ;
		RECT 0.0714 68.9506 0.133 69.0824 ;
		RECT 0 69.0698 0.133 69.0824 ;
		RECT 0.0714 69.0824 0.133 69.2078 ;
		RECT 0 69.3459 0.133 71.3663 ;
		RECT 0.0714 71.5106 0.133 71.6424 ;
		RECT 0 71.6298 0.133 71.6424 ;
		RECT 0.0714 71.6424 0.133 71.7678 ;
		RECT 0 71.9059 0.133 73.9263 ;
		RECT 0.0714 74.0706 0.133 74.2024 ;
		RECT 0 74.1898 0.133 74.2024 ;
		RECT 0.0714 74.2024 0.133 74.3278 ;
		RECT 0 74.4659 0.133 76.4863 ;
		RECT 0.0714 76.6306 0.133 76.7624 ;
		RECT 0 76.7498 0.133 76.7624 ;
		RECT 0.0714 76.7624 0.133 76.8878 ;
		RECT 0 77.0259 0.133 79.0463 ;
		RECT 0.0714 79.1906 0.133 79.3224 ;
		RECT 0 79.3098 0.133 79.3224 ;
		RECT 0.0714 79.3224 0.133 79.4478 ;
		RECT 0 79.5859 0.133 81.6063 ;
		RECT 0.0714 81.7506 0.133 81.8824 ;
		RECT 0 81.8698 0.133 81.8824 ;
		RECT 0.0714 81.8824 0.133 82.0078 ;
		RECT 0 82.1459 0.133 84.1663 ;
		RECT 0.0714 84.3106 0.133 84.4424 ;
		RECT 0 84.4298 0.133 84.4424 ;
		RECT 0.0714 84.4424 0.133 84.5678 ;
		RECT 0 84.7059 0.133 86.7263 ;
		RECT 0.0714 86.8706 0.133 87.0024 ;
		RECT 0 86.9898 0.133 87.0024 ;
		RECT 0.0714 87.0024 0.133 87.1278 ;
		RECT 0 87.2659 0.133 87.3537 ;
		RECT 0 87.4918 0.133 88.7592 ;
		RECT 0.0714 88.7592 0.133 89.2361 ;
		RECT 0 88.8973 0.133 89.2361 ;
		RECT 0 89.3741 0.133 89.3867 ;
		RECT 0 89.5247 0.133 89.5373 ;
		RECT 0.0714 89.5373 0.133 89.6878 ;
		RECT 0 89.6753 0.133 89.6878 ;
		RECT 0 89.8259 0.133 89.8635 ;
		RECT 0 90.0016 0.133 90.0141 ;
		RECT 0 90.1522 0.133 90.1647 ;
		RECT 0.0714 90.1647 0.133 90.6416 ;
		RECT 0 90.3027 0.133 90.6416 ;
		RECT 0.0714 90.6416 0.133 90.7922 ;
		RECT 0 90.7796 0.133 90.7922 ;
		RECT 0.0714 90.7922 0.133 91.1184 ;
		RECT 0 90.9302 0.133 91.1184 ;
		RECT 0.0714 91.1184 0.133 91.269 ;
		RECT 0 91.2565 0.133 91.269 ;
		RECT 0.0714 91.269 0.133 91.5702 ;
		RECT 0 91.4071 0.133 91.5702 ;
		RECT 0.0714 91.5702 0.133 91.7459 ;
		RECT 0 91.7082 0.133 91.7459 ;
		RECT 0.0714 91.7459 0.133 91.8714 ;
		RECT 0 92.0094 0.133 92.0471 ;
		RECT 0.0714 92.0471 0.133 92.1976 ;
		RECT 0 92.1851 0.133 92.1976 ;
		RECT 0 92.3357 0.133 92.3733 ;
		RECT 0 92.5114 0.133 92.5239 ;
		RECT 0.0714 92.5239 0.133 93.2769 ;
		RECT 0 92.662 0.133 93.2769 ;
		RECT 0.0714 93.2769 0.133 93.4275 ;
		RECT 0 93.4149 0.133 93.4275 ;
		RECT 0.0714 93.4275 0.133 93.6784 ;
		RECT 0 93.5655 0.133 93.6784 ;
		RECT 0.0714 93.6784 0.133 93.829 ;
		RECT 0 93.8165 0.133 93.829 ;
		RECT 0.0714 93.829 0.133 94.2557 ;
		RECT 0 93.9671 0.133 94.2557 ;
		RECT 0.0714 94.2557 0.133 94.4063 ;
		RECT 0 94.3937 0.133 94.4063 ;
		RECT 0 94.5443 0.133 94.5569 ;
		RECT 0 94.6949 0.133 94.7075 ;
		RECT 0 94.8455 0.133 94.8831 ;
		RECT 0 95.0212 0.133 95.0337 ;
		RECT 0 95.1718 0.133 95.1843 ;
		RECT 0.0714 95.1843 0.133 95.7867 ;
		RECT 0 95.3224 0.133 95.7867 ;
		RECT 0.0714 95.7867 0.133 95.9373 ;
		RECT 0 95.9247 0.133 95.9373 ;
		RECT 0.0714 95.9373 0.133 96.0627 ;
		RECT 0.0714 96.0627 0.133 96.2886 ;
		RECT 0 96.2008 0.133 96.2886 ;
		RECT 0 96.4267 0.133 96.4392 ;
		RECT 0.0714 96.4392 0.133 96.891 ;
		RECT 0 96.5773 0.133 96.891 ;
		RECT 0 97.029 0.133 97.0416 ;
		RECT 0 97.1796 0.133 97.1922 ;
		RECT 0.0714 97.1922 0.133 97.3678 ;
		RECT 0 97.3302 0.133 97.3678 ;
		RECT 0 97.5059 0.133 98.8486 ;
		RECT 0 98.9867 0.133 98.9992 ;
		RECT 0.0714 98.9992 0.133 99.1498 ;
		RECT 0 99.1373 0.133 99.1498 ;
		RECT 0.0714 99.1498 0.133 99.3004 ;
		RECT 0 99.2878 0.133 99.3004 ;
		RECT 0.0714 99.3004 0.133 99.451 ;
		RECT 0 99.4384 0.133 99.451 ;
		RECT 0 99.589 0.133 99.6016 ;
		RECT 0 99.7396 0.133 99.7522 ;
		RECT 0 99.8902 0.133 99.9278 ;
		RECT 0 100.0659 0.133 100.4424 ;
		RECT 0 100.5804 0.133 100.5929 ;
		RECT 0 100.731 0.133 100.7435 ;
		RECT 0 100.8816 0.133 100.8941 ;
		RECT 0 101.0322 0.133 101.0447 ;
		RECT 0 101.1827 0.133 101.2706 ;
		RECT 0 101.4086 0.133 101.4965 ;
		RECT 0 101.6345 0.133 102.4753 ;
		RECT 0.0714 102.4753 0.133 102.8518 ;
		RECT 0 102.6133 0.133 102.8518 ;
		RECT 0 102.9898 0.133 103.0024 ;
		RECT 0 103.1404 0.133 103.1529 ;
		RECT 0.0714 103.1529 0.133 103.3035 ;
		RECT 0 103.291 0.133 103.3035 ;
		RECT 0 103.4416 0.133 103.4541 ;
		RECT 0 103.5922 0.133 103.8306 ;
		RECT 0.0714 103.8306 0.133 104.0565 ;
		RECT 0 103.9686 0.133 104.0565 ;
		RECT 0 104.1945 0.133 105.2612 ;
		RECT 0 105.3992 0.133 105.4118 ;
		RECT 0 105.5498 0.133 105.5624 ;
		RECT 0 105.7004 0.133 105.7129 ;
		RECT 0 105.851 0.133 105.8635 ;
		RECT 0 106.0016 0.133 106.0141 ;
		RECT 0 106.1522 0.133 106.6165 ;
		RECT 0 106.7545 0.133 106.9929 ;
		RECT 0.0714 106.9929 0.133 107.9718 ;
		RECT 0 107.131 0.133 107.9718 ;
		RECT 0.0714 107.9718 0.133 108.1976 ;
		RECT 0 108.1098 0.133 108.1976 ;
		RECT 0 108.3357 0.133 108.4235 ;
		RECT 0 108.5616 0.133 108.5741 ;
		RECT 0 108.7122 0.133 109.7035 ;
		RECT 0.0714 109.7035 0.133 110.3812 ;
		RECT 0 109.8416 0.133 110.3812 ;
		RECT 0.0714 110.3812 0.133 110.6071 ;
		RECT 0 110.5192 0.133 110.6071 ;
		RECT 0.0714 110.6071 0.133 110.9835 ;
		RECT 0 110.7451 0.133 110.9835 ;
		RECT 0 111.1216 0.133 111.1341 ;
		RECT 0 111.2722 0.133 111.5106 ;
		RECT 0 111.6486 0.133 112.3388 ;
		RECT 0.0714 112.3388 0.133 113.0165 ;
		RECT 0 112.4769 0.133 113.0165 ;
		RECT 0 113.1545 0.133 113.2424 ;
		RECT 0.0714 113.3867 0.133 113.5184 ;
		RECT 0 113.5059 0.133 113.5184 ;
		RECT 0.0714 113.5184 0.133 113.6439 ;
		RECT 0 113.782 0.133 115.8024 ;
		RECT 0.0714 115.9467 0.133 116.0784 ;
		RECT 0 116.0659 0.133 116.0784 ;
		RECT 0.0714 116.0784 0.133 116.2039 ;
		RECT 0 116.342 0.133 118.3624 ;
		RECT 0.0714 118.5067 0.133 118.6384 ;
		RECT 0 118.6259 0.133 118.6384 ;
		RECT 0.0714 118.6384 0.133 118.7639 ;
		RECT 0 118.902 0.133 120.9224 ;
		RECT 0.0714 121.0667 0.133 121.1984 ;
		RECT 0 121.1859 0.133 121.1984 ;
		RECT 0.0714 121.1984 0.133 121.3239 ;
		RECT 0 121.462 0.133 123.4824 ;
		RECT 0.0714 123.6267 0.133 123.7584 ;
		RECT 0 123.7459 0.133 123.7584 ;
		RECT 0.0714 123.7584 0.133 123.8839 ;
		RECT 0 124.022 0.133 126.0424 ;
		RECT 0.0714 126.1867 0.133 126.3184 ;
		RECT 0 126.3059 0.133 126.3184 ;
		RECT 0.0714 126.3184 0.133 126.4439 ;
		RECT 0 126.582 0.133 128.6024 ;
		RECT 0.0714 128.7467 0.133 128.8784 ;
		RECT 0 128.8659 0.133 128.8784 ;
		RECT 0.0714 128.8784 0.133 129.0039 ;
		RECT 0 129.142 0.133 131.1624 ;
		RECT 0.0714 131.3067 0.133 131.4384 ;
		RECT 0 131.4259 0.133 131.4384 ;
		RECT 0.0714 131.4384 0.133 131.5639 ;
		RECT 0 131.702 0.133 133.7224 ;
		RECT 0.0714 133.8667 0.133 133.9984 ;
		RECT 0 133.9859 0.133 133.9984 ;
		RECT 0.0714 133.9984 0.133 134.1239 ;
		RECT 0 134.262 0.133 136.2824 ;
		RECT 0.0714 136.4267 0.133 136.5584 ;
		RECT 0 136.5459 0.133 136.5584 ;
		RECT 0.0714 136.5584 0.133 136.6839 ;
		RECT 0 136.822 0.133 138.8424 ;
		RECT 0.0714 138.9867 0.133 139.1184 ;
		RECT 0 139.1059 0.133 139.1184 ;
		RECT 0.0714 139.1184 0.133 139.2439 ;
		RECT 0 139.382 0.133 141.4024 ;
		RECT 0.0714 141.5467 0.133 141.6784 ;
		RECT 0 141.6659 0.133 141.6784 ;
		RECT 0.0714 141.6784 0.133 141.8039 ;
		RECT 0 141.942 0.133 143.9624 ;
		RECT 0.0714 144.1067 0.133 144.2384 ;
		RECT 0 144.2259 0.133 144.2384 ;
		RECT 0.0714 144.2384 0.133 144.3639 ;
		RECT 0 144.502 0.133 154.2212 ;
		RECT 0.0714 154.3655 0.133 154.4973 ;
		RECT 0 154.4847 0.133 154.4973 ;
		RECT 0.0714 154.4973 0.133 154.6227 ;
		RECT 0 154.7608 0.133 156.7812 ;
		RECT 0.0714 156.9255 0.133 157.0573 ;
		RECT 0 157.0447 0.133 157.0573 ;
		RECT 0.0714 157.0573 0.133 157.1827 ;
		RECT 0 157.3208 0.133 159.3412 ;
		RECT 0.0714 159.4855 0.133 159.6173 ;
		RECT 0 159.6047 0.133 159.6173 ;
		RECT 0.0714 159.6173 0.133 159.7427 ;
		RECT 0 159.8808 0.133 161.9012 ;
		RECT 0.0714 162.0455 0.133 162.1773 ;
		RECT 0 162.1647 0.133 162.1773 ;
		RECT 0.0714 162.1773 0.133 162.3027 ;
		RECT 0 162.4408 0.133 164.4612 ;
		RECT 0.0714 164.6055 0.133 164.7373 ;
		RECT 0 164.7247 0.133 164.7373 ;
		RECT 0.0714 164.7373 0.133 164.8627 ;
		RECT 0 165.0008 0.133 167.0212 ;
		RECT 0.0714 167.1655 0.133 167.2973 ;
		RECT 0 167.2847 0.133 167.2973 ;
		RECT 0.0714 167.2973 0.133 167.4227 ;
		RECT 0 167.5608 0.133 169.5812 ;
		RECT 0.0714 169.7255 0.133 169.8573 ;
		RECT 0 169.8447 0.133 169.8573 ;
		RECT 0.0714 169.8573 0.133 169.9827 ;
		RECT 0 170.1208 0.133 172.1412 ;
		RECT 0.0714 172.2855 0.133 172.4173 ;
		RECT 0 172.4047 0.133 172.4173 ;
		RECT 0.0714 172.4173 0.133 172.5427 ;
		RECT 0 172.6808 0.133 174.7012 ;
		RECT 0.0714 174.8455 0.133 174.9773 ;
		RECT 0 174.9647 0.133 174.9773 ;
		RECT 0.0714 174.9773 0.133 175.1027 ;
		RECT 0 175.2408 0.133 177.2612 ;
		RECT 0.0714 177.4055 0.133 177.5373 ;
		RECT 0 177.5247 0.133 177.5373 ;
		RECT 0.0714 177.5373 0.133 177.6627 ;
		RECT 0 177.8008 0.133 179.8212 ;
		RECT 0.0714 179.9655 0.133 180.0973 ;
		RECT 0 180.0847 0.133 180.0973 ;
		RECT 0.0714 180.0973 0.133 180.2227 ;
		RECT 0 180.3608 0.133 182.3812 ;
		RECT 0.0714 182.5255 0.133 182.6573 ;
		RECT 0 182.6447 0.133 182.6573 ;
		RECT 0.0714 182.6573 0.133 182.7827 ;
		RECT 0 182.9208 0.133 184.9412 ;
		RECT 0.0714 185.0855 0.133 185.2173 ;
		RECT 0 185.2047 0.133 185.2173 ;
		RECT 0.0714 185.2173 0.133 185.3427 ;
		RECT 0 185.4808 0.133 187.5012 ;
		RECT 0.0714 187.6455 0.133 187.7773 ;
		RECT 0 187.7647 0.133 187.7773 ;
		RECT 0.0714 187.7773 0.133 187.9027 ;
		RECT 0 188.0408 0.133 190.0612 ;
		RECT 0.0714 190.2055 0.133 190.3373 ;
		RECT 0 190.3247 0.133 190.3373 ;
		RECT 0.0714 190.3373 0.133 190.4627 ;
		RECT 0 190.6008 0.133 192.6212 ;
		RECT 0.0714 192.7655 0.133 192.8973 ;
		RECT 0 192.8847 0.133 192.8973 ;
		RECT 0.0714 192.8973 0.133 193.0227 ;
		RECT 0 193.1608 0.133 195.1812 ;
		RECT 0.0714 195.3255 0.133 195.4573 ;
		RECT 0 195.4447 0.133 195.4573 ;
		RECT 0.0714 195.4573 0.133 195.5827 ;
		RECT 0 195.7208 0.133 197.7412 ;
		RECT 0.0714 197.8855 0.133 198.0173 ;
		RECT 0 198.0047 0.133 198.0173 ;
		RECT 0.0714 198.0173 0.133 198.1427 ;
		RECT 0 198.2808 0.133 200.3263 ;
		RECT 0 200.4643 0.133 200.5082 ;
		 LAYER M3 ;
		RECT 0.0098 46.5694 0.0481 46.6698 ;
		RECT 0.0098 47.0212 0.0481 47.1216 ;
		RECT 0.0098 47.1733 0.0481 47.2737 ;
		RECT 0.0098 47.4227 0.0481 47.5231 ;
		RECT 0.0098 47.9749 0.0481 48.0753 ;
		RECT 0.0098 50.56 0.0481 50.6604 ;
		RECT 0.0098 50.8863 0.0481 50.9867 ;
		RECT 0.0098 51.2878 0.0481 51.3882 ;
		RECT 0.0098 52.3671 0.0481 52.4675 ;
		RECT 0.0098 52.6933 0.0481 52.7937 ;
		RECT 0.0098 52.869 0.0481 52.9694 ;
		RECT 0.0098 53.2706 0.0481 53.371 ;
		RECT 0.0098 90.9616 0.0481 91.062 ;
		RECT 0.0098 97.3867 0.0481 97.4871 ;
		RECT 0.0098 97.5122 0.0481 97.6125 ;
		RECT 0.0098 97.8133 0.0481 97.9137 ;
		RECT 0.0098 0.0627 0.0481 0.1631 ;
		RECT 0.0098 153.8384 0.0481 153.9388 ;
		RECT 0.0098 153.3867 0.0481 153.4871 ;
		RECT 0.0098 153.2345 0.0481 153.3349 ;
		RECT 0.0098 152.9851 0.0481 153.0855 ;
		RECT 0.0098 152.4329 0.0481 152.5333 ;
		RECT 0.0098 150.8769 0.0481 150.9773 ;
		RECT 0.0098 149.8478 0.0481 149.9482 ;
		RECT 0.0098 149.5216 0.0481 149.622 ;
		RECT 0.0098 149.12 0.0481 149.2204 ;
		RECT 0.0098 148.0408 0.0481 148.1412 ;
		RECT 0.0098 147.7145 0.0481 147.8149 ;
		RECT 0.0098 147.5388 0.0481 147.6392 ;
		RECT 0.0098 147.1373 0.0481 147.2376 ;
		RECT 0.0098 112.5961 0.0481 112.6965 ;
		RECT 0.0098 112.2071 0.0481 112.3075 ;
		RECT 0.0098 111.5294 0.0481 111.6298 ;
		RECT 0.0098 109.5216 0.0481 109.622 ;
		RECT 0.0714 102.8706 0.1097 102.971 ;
		RECT 0.0098 101.9169 0.0481 102.0173 ;
		RECT 0.0098 101.7663 0.0481 101.8667 ;
		RECT 0.0098 101.0635 0.0481 101.1639 ;
		RECT 0.0098 200.3451 0.0481 200.4455 ;
		 LAYER M3 SPACING 0.012 ;
		RECT 0.0098 46.5694 0.0481 46.6698 ;
		RECT 0.0098 47.0212 0.0481 47.1216 ;
		RECT 0.0098 47.1733 0.0481 47.2737 ;
		RECT 0.0098 47.4227 0.0481 47.5231 ;
		RECT 0.0098 47.9749 0.0481 48.0753 ;
		RECT 0.0098 50.56 0.0481 50.6604 ;
		RECT 0.0098 50.8863 0.0481 50.9867 ;
		RECT 0.0098 51.2878 0.0481 51.3882 ;
		RECT 0.0098 52.3671 0.0481 52.4675 ;
		RECT 0.0098 52.6933 0.0481 52.7937 ;
		RECT 0.0098 52.869 0.0481 52.9694 ;
		RECT 0.0098 53.2706 0.0481 53.371 ;
		RECT 0.0098 90.9616 0.0481 91.062 ;
		RECT 0.0098 97.3867 0.0481 97.4871 ;
		RECT 0.0098 97.5122 0.0481 97.6125 ;
		RECT 0.0098 97.8133 0.0481 97.9137 ;
		RECT 0.0098 0.0627 0.0481 0.1631 ;
		RECT 0.0098 153.8384 0.0481 153.9388 ;
		RECT 0.0098 153.3867 0.0481 153.4871 ;
		RECT 0.0098 153.2345 0.0481 153.3349 ;
		RECT 0.0098 152.9851 0.0481 153.0855 ;
		RECT 0.0098 152.4329 0.0481 152.5333 ;
		RECT 0.0098 150.8769 0.0481 150.9773 ;
		RECT 0.0098 149.8478 0.0481 149.9482 ;
		RECT 0.0098 149.5216 0.0481 149.622 ;
		RECT 0.0098 149.12 0.0481 149.2204 ;
		RECT 0.0098 148.0408 0.0481 148.1412 ;
		RECT 0.0098 147.7145 0.0481 147.8149 ;
		RECT 0.0098 147.5388 0.0481 147.6392 ;
		RECT 0.0098 147.1373 0.0481 147.2376 ;
		RECT 0.0098 112.5961 0.0481 112.6965 ;
		RECT 0.0098 112.2071 0.0481 112.3075 ;
		RECT 0.0098 111.5294 0.0481 111.6298 ;
		RECT 0.0098 109.5216 0.0481 109.622 ;
		RECT 0.0714 102.8706 0.1097 102.971 ;
		RECT 0.0098 101.9169 0.0481 102.0173 ;
		RECT 0.0098 101.7663 0.0481 101.8667 ;
		RECT 0.0098 101.0635 0.0481 101.1639 ;
		RECT 0.0098 200.3451 0.0481 200.4455 ;
		 LAYER M4 SPACING 0.018 ;
		RECT 0.2105 0.3286 124.236 0.5302 ;
		RECT 124.236 0.3286 124.383 0.5302 ;
		RECT 0.2105 0.64 124.236 0.7631 ;
		RECT 124.236 0.64 124.383 0.7631 ;
		RECT 0.2105 0.9686 124.236 1.1702 ;
		RECT 124.236 0.9686 124.383 1.1702 ;
		RECT 0.2105 1.28 124.236 1.4031 ;
		RECT 124.236 1.28 124.383 1.4031 ;
		RECT 0.2105 1.6086 124.236 1.8102 ;
		RECT 124.236 1.6086 124.383 1.8102 ;
		RECT 0.2105 1.92 124.236 2.0431 ;
		RECT 124.236 1.92 124.383 2.0431 ;
		RECT 0.2105 2.2486 124.236 2.4502 ;
		RECT 124.236 2.2486 124.383 2.4502 ;
		RECT 0.2105 2.56 124.236 2.6831 ;
		RECT 124.236 2.56 124.383 2.6831 ;
		RECT 0.2105 2.8886 124.236 3.0902 ;
		RECT 124.236 2.8886 124.383 3.0902 ;
		RECT 0.2105 3.2 124.236 3.3231 ;
		RECT 124.236 3.2 124.383 3.3231 ;
		RECT 0.2105 3.5286 124.236 3.7302 ;
		RECT 124.236 3.5286 124.383 3.7302 ;
		RECT 0.2105 3.84 124.236 3.9631 ;
		RECT 124.236 3.84 124.383 3.9631 ;
		RECT 0.2105 4.1686 124.236 4.3702 ;
		RECT 124.236 4.1686 124.383 4.3702 ;
		RECT 0.2105 4.48 124.236 4.6031 ;
		RECT 124.236 4.48 124.383 4.6031 ;
		RECT 0.2105 4.8086 124.236 5.0102 ;
		RECT 124.236 4.8086 124.383 5.0102 ;
		RECT 0.2105 5.12 124.236 5.2431 ;
		RECT 124.236 5.12 124.383 5.2431 ;
		RECT 0.2105 5.4486 124.236 5.6502 ;
		RECT 124.236 5.4486 124.383 5.6502 ;
		RECT 0.2105 5.76 124.236 5.8831 ;
		RECT 124.236 5.76 124.383 5.8831 ;
		RECT 0.2105 6.0886 124.236 6.2902 ;
		RECT 124.236 6.0886 124.383 6.2902 ;
		RECT 0.2105 6.4 124.236 6.5231 ;
		RECT 124.236 6.4 124.383 6.5231 ;
		RECT 0.2105 6.7286 124.236 6.9302 ;
		RECT 124.236 6.7286 124.383 6.9302 ;
		RECT 0.2105 7.04 124.236 7.1631 ;
		RECT 124.236 7.04 124.383 7.1631 ;
		RECT 0.2105 7.3686 124.236 7.5702 ;
		RECT 124.236 7.3686 124.383 7.5702 ;
		RECT 0.2105 7.68 124.236 7.8031 ;
		RECT 124.236 7.68 124.383 7.8031 ;
		RECT 0.2105 8.0086 124.236 8.2102 ;
		RECT 124.236 8.0086 124.383 8.2102 ;
		RECT 0.2105 8.32 124.236 8.4431 ;
		RECT 124.236 8.32 124.383 8.4431 ;
		RECT 0.2105 8.6486 124.236 8.8502 ;
		RECT 124.236 8.6486 124.383 8.8502 ;
		RECT 0.2105 8.96 124.236 9.0831 ;
		RECT 124.236 8.96 124.383 9.0831 ;
		RECT 0.2105 9.2886 124.236 9.4902 ;
		RECT 124.236 9.2886 124.383 9.4902 ;
		RECT 0.2105 9.6 124.236 9.7231 ;
		RECT 124.236 9.6 124.383 9.7231 ;
		RECT 0.2105 9.9286 124.236 10.1302 ;
		RECT 124.236 9.9286 124.383 10.1302 ;
		RECT 0.2105 10.24 124.236 10.3631 ;
		RECT 124.236 10.24 124.383 10.3631 ;
		RECT 0.2105 10.5686 124.236 10.7702 ;
		RECT 124.236 10.5686 124.383 10.7702 ;
		RECT 0.2105 10.88 124.236 11.0031 ;
		RECT 124.236 10.88 124.383 11.0031 ;
		RECT 0.2105 11.2086 124.236 11.4102 ;
		RECT 124.236 11.2086 124.383 11.4102 ;
		RECT 0.2105 11.52 124.236 11.6431 ;
		RECT 124.236 11.52 124.383 11.6431 ;
		RECT 0.2105 11.8486 124.236 12.0502 ;
		RECT 124.236 11.8486 124.383 12.0502 ;
		RECT 0.2105 12.16 124.236 12.2831 ;
		RECT 124.236 12.16 124.383 12.2831 ;
		RECT 0.2105 12.4886 124.236 12.6902 ;
		RECT 124.236 12.4886 124.383 12.6902 ;
		RECT 0.2105 12.8 124.236 12.9231 ;
		RECT 124.236 12.8 124.383 12.9231 ;
		RECT 0.2105 13.1286 124.236 13.3302 ;
		RECT 124.236 13.1286 124.383 13.3302 ;
		RECT 0.2105 13.44 124.236 13.5631 ;
		RECT 124.236 13.44 124.383 13.5631 ;
		RECT 0.2105 13.7686 124.236 13.9702 ;
		RECT 124.236 13.7686 124.383 13.9702 ;
		RECT 0.2105 14.08 124.236 14.2031 ;
		RECT 124.236 14.08 124.383 14.2031 ;
		RECT 0.2105 14.4086 124.236 14.6102 ;
		RECT 124.236 14.4086 124.383 14.6102 ;
		RECT 0.2105 14.72 124.236 14.8431 ;
		RECT 124.236 14.72 124.383 14.8431 ;
		RECT 0.2105 15.0486 124.236 15.2502 ;
		RECT 124.236 15.0486 124.383 15.2502 ;
		RECT 0.2105 15.36 124.236 15.4831 ;
		RECT 124.236 15.36 124.383 15.4831 ;
		RECT 0.2105 15.6886 124.236 15.8902 ;
		RECT 124.236 15.6886 124.383 15.8902 ;
		RECT 0.2105 16 124.236 16.1231 ;
		RECT 124.236 16 124.383 16.1231 ;
		RECT 0.2105 16.3286 124.236 16.5302 ;
		RECT 124.236 16.3286 124.383 16.5302 ;
		RECT 0.2105 16.64 124.236 16.7631 ;
		RECT 124.236 16.64 124.383 16.7631 ;
		RECT 0.2105 16.9686 124.236 17.1702 ;
		RECT 124.236 16.9686 124.383 17.1702 ;
		RECT 0.2105 17.28 124.236 17.4031 ;
		RECT 124.236 17.28 124.383 17.4031 ;
		RECT 0.2105 17.6086 124.236 17.8102 ;
		RECT 124.236 17.6086 124.383 17.8102 ;
		RECT 0.2105 17.92 124.236 18.0431 ;
		RECT 124.236 17.92 124.383 18.0431 ;
		RECT 0.2105 18.2486 124.236 18.4502 ;
		RECT 124.236 18.2486 124.383 18.4502 ;
		RECT 0.2105 18.56 124.236 18.6831 ;
		RECT 124.236 18.56 124.383 18.6831 ;
		RECT 0.2105 18.8886 124.236 19.0902 ;
		RECT 124.236 18.8886 124.383 19.0902 ;
		RECT 0.2105 19.2 124.236 19.3231 ;
		RECT 124.236 19.2 124.383 19.3231 ;
		RECT 0.2105 19.5286 124.236 19.7302 ;
		RECT 124.236 19.5286 124.383 19.7302 ;
		RECT 0.2105 19.84 124.236 19.9631 ;
		RECT 124.236 19.84 124.383 19.9631 ;
		RECT 0.2105 20.1686 124.236 20.3702 ;
		RECT 124.236 20.1686 124.383 20.3702 ;
		RECT 0.2105 20.48 124.236 20.6031 ;
		RECT 124.236 20.48 124.383 20.6031 ;
		RECT 0.2105 20.8086 124.236 21.0102 ;
		RECT 124.236 20.8086 124.383 21.0102 ;
		RECT 0.2105 21.12 124.236 21.2431 ;
		RECT 124.236 21.12 124.383 21.2431 ;
		RECT 0.2105 21.4486 124.236 21.6502 ;
		RECT 124.236 21.4486 124.383 21.6502 ;
		RECT 0.2105 21.76 124.236 21.8831 ;
		RECT 124.236 21.76 124.383 21.8831 ;
		RECT 0.2105 22.0886 124.236 22.2902 ;
		RECT 124.236 22.0886 124.383 22.2902 ;
		RECT 0.2105 22.4 124.236 22.5231 ;
		RECT 124.236 22.4 124.383 22.5231 ;
		RECT 0.2105 22.7286 124.236 22.9302 ;
		RECT 124.236 22.7286 124.383 22.9302 ;
		RECT 0.2105 23.04 124.236 23.1631 ;
		RECT 124.236 23.04 124.383 23.1631 ;
		RECT 0.2105 23.3686 124.236 23.5702 ;
		RECT 124.236 23.3686 124.383 23.5702 ;
		RECT 0.2105 23.68 124.236 23.8031 ;
		RECT 124.236 23.68 124.383 23.8031 ;
		RECT 0.2105 24.0086 124.236 24.2102 ;
		RECT 124.236 24.0086 124.383 24.2102 ;
		RECT 0.2105 24.32 124.236 24.4431 ;
		RECT 124.236 24.32 124.383 24.4431 ;
		RECT 0.2105 24.6486 124.236 24.8502 ;
		RECT 124.236 24.6486 124.383 24.8502 ;
		RECT 0.2105 24.96 124.236 25.0831 ;
		RECT 124.236 24.96 124.383 25.0831 ;
		RECT 0.2105 25.2886 124.236 25.4902 ;
		RECT 124.236 25.2886 124.383 25.4902 ;
		RECT 0.2105 25.6 124.236 25.7231 ;
		RECT 124.236 25.6 124.383 25.7231 ;
		RECT 0.2105 25.9286 124.236 26.1302 ;
		RECT 124.236 25.9286 124.383 26.1302 ;
		RECT 0.2105 26.24 124.236 26.3631 ;
		RECT 124.236 26.24 124.383 26.3631 ;
		RECT 0.2105 26.5686 124.236 26.7702 ;
		RECT 124.236 26.5686 124.383 26.7702 ;
		RECT 0.2105 26.88 124.236 27.0031 ;
		RECT 124.236 26.88 124.383 27.0031 ;
		RECT 0.2105 27.2086 124.236 27.4102 ;
		RECT 124.236 27.2086 124.383 27.4102 ;
		RECT 0.2105 27.52 124.236 27.6431 ;
		RECT 124.236 27.52 124.383 27.6431 ;
		RECT 0.2105 27.8486 124.236 28.0502 ;
		RECT 124.236 27.8486 124.383 28.0502 ;
		RECT 0.2105 28.16 124.236 28.2831 ;
		RECT 124.236 28.16 124.383 28.2831 ;
		RECT 0.2105 28.4886 124.236 28.6902 ;
		RECT 124.236 28.4886 124.383 28.6902 ;
		RECT 0.2105 28.8 124.236 28.9231 ;
		RECT 124.236 28.8 124.383 28.9231 ;
		RECT 0.2105 29.1286 124.236 29.3302 ;
		RECT 124.236 29.1286 124.383 29.3302 ;
		RECT 0.2105 29.44 124.236 29.5631 ;
		RECT 124.236 29.44 124.383 29.5631 ;
		RECT 0.2105 29.7686 124.236 29.9702 ;
		RECT 124.236 29.7686 124.383 29.9702 ;
		RECT 0.2105 30.08 124.236 30.2031 ;
		RECT 124.236 30.08 124.383 30.2031 ;
		RECT 0.2105 30.4086 124.236 30.6102 ;
		RECT 124.236 30.4086 124.383 30.6102 ;
		RECT 0.2105 30.72 124.236 30.8431 ;
		RECT 124.236 30.72 124.383 30.8431 ;
		RECT 0.2105 31.0486 124.236 31.2502 ;
		RECT 124.236 31.0486 124.383 31.2502 ;
		RECT 0.2105 31.36 124.236 31.4831 ;
		RECT 124.236 31.36 124.383 31.4831 ;
		RECT 0.2105 31.6886 124.236 31.8902 ;
		RECT 124.236 31.6886 124.383 31.8902 ;
		RECT 0.2105 32 124.236 32.1231 ;
		RECT 124.236 32 124.383 32.1231 ;
		RECT 0.2105 32.3286 124.236 32.5302 ;
		RECT 124.236 32.3286 124.383 32.5302 ;
		RECT 0.2105 32.64 124.236 32.7631 ;
		RECT 124.236 32.64 124.383 32.7631 ;
		RECT 0.2105 32.9686 124.236 33.1702 ;
		RECT 124.236 32.9686 124.383 33.1702 ;
		RECT 0.2105 33.28 124.236 33.4031 ;
		RECT 124.236 33.28 124.383 33.4031 ;
		RECT 0.2105 33.6086 124.236 33.8102 ;
		RECT 124.236 33.6086 124.383 33.8102 ;
		RECT 0.2105 33.92 124.236 34.0431 ;
		RECT 124.236 33.92 124.383 34.0431 ;
		RECT 0.2105 34.2486 124.236 34.4502 ;
		RECT 124.236 34.2486 124.383 34.4502 ;
		RECT 0.2105 34.56 124.236 34.6831 ;
		RECT 124.236 34.56 124.383 34.6831 ;
		RECT 0.2105 34.8886 124.236 35.0902 ;
		RECT 124.236 34.8886 124.383 35.0902 ;
		RECT 0.2105 35.2 124.236 35.3231 ;
		RECT 124.236 35.2 124.383 35.3231 ;
		RECT 0.2105 35.5286 124.236 35.7302 ;
		RECT 124.236 35.5286 124.383 35.7302 ;
		RECT 0.2105 35.84 124.236 35.9631 ;
		RECT 124.236 35.84 124.383 35.9631 ;
		RECT 0.2105 36.1686 124.236 36.3702 ;
		RECT 124.236 36.1686 124.383 36.3702 ;
		RECT 0.2105 36.48 124.236 36.6031 ;
		RECT 124.236 36.48 124.383 36.6031 ;
		RECT 0.2105 36.8086 124.236 37.0102 ;
		RECT 124.236 36.8086 124.383 37.0102 ;
		RECT 0.2105 37.12 124.236 37.2431 ;
		RECT 124.236 37.12 124.383 37.2431 ;
		RECT 0.2105 37.4486 124.236 37.6502 ;
		RECT 124.236 37.4486 124.383 37.6502 ;
		RECT 0.2105 37.76 124.236 37.8831 ;
		RECT 124.236 37.76 124.383 37.8831 ;
		RECT 0.2105 38.0886 124.236 38.2902 ;
		RECT 124.236 38.0886 124.383 38.2902 ;
		RECT 0.2105 38.4 124.236 38.5231 ;
		RECT 124.236 38.4 124.383 38.5231 ;
		RECT 0.2105 38.7286 124.236 38.9302 ;
		RECT 124.236 38.7286 124.383 38.9302 ;
		RECT 0.2105 39.04 124.236 39.1631 ;
		RECT 124.236 39.04 124.383 39.1631 ;
		RECT 0.2105 39.3686 124.236 39.5702 ;
		RECT 124.236 39.3686 124.383 39.5702 ;
		RECT 0.2105 39.68 124.236 39.8031 ;
		RECT 124.236 39.68 124.383 39.8031 ;
		RECT 0.2105 40.0086 124.236 40.2102 ;
		RECT 124.236 40.0086 124.383 40.2102 ;
		RECT 0.2105 40.32 124.236 40.4431 ;
		RECT 124.236 40.32 124.383 40.4431 ;
		RECT 0.2105 40.6486 124.236 40.8502 ;
		RECT 124.236 40.6486 124.383 40.8502 ;
		RECT 0.2105 40.96 124.236 41.0831 ;
		RECT 124.236 40.96 124.383 41.0831 ;
		RECT 0.2105 41.2886 124.236 41.4902 ;
		RECT 124.236 41.2886 124.383 41.4902 ;
		RECT 0.2105 41.6 124.236 41.7231 ;
		RECT 124.236 41.6 124.383 41.7231 ;
		RECT 0.2105 41.9286 124.236 42.1302 ;
		RECT 124.236 41.9286 124.383 42.1302 ;
		RECT 0.2105 42.24 124.236 42.3631 ;
		RECT 124.236 42.24 124.383 42.3631 ;
		RECT 0.2105 42.5686 124.236 42.7702 ;
		RECT 124.236 42.5686 124.383 42.7702 ;
		RECT 0.2105 42.88 124.236 43.0031 ;
		RECT 124.236 42.88 124.383 43.0031 ;
		RECT 0.2105 43.2086 124.236 43.4102 ;
		RECT 124.236 43.2086 124.383 43.4102 ;
		RECT 0.2105 43.52 124.236 43.6431 ;
		RECT 124.236 43.52 124.383 43.6431 ;
		RECT 0.2105 43.8486 124.236 44.0502 ;
		RECT 124.236 43.8486 124.383 44.0502 ;
		RECT 0.2105 44.16 124.236 44.2831 ;
		RECT 124.236 44.16 124.383 44.2831 ;
		RECT 0.2105 44.4886 124.236 44.6902 ;
		RECT 124.236 44.4886 124.383 44.6902 ;
		RECT 0.2105 44.8 124.236 44.9231 ;
		RECT 124.236 44.8 124.383 44.9231 ;
		RECT 0.2105 45.1286 124.236 45.3302 ;
		RECT 124.236 45.1286 124.383 45.3302 ;
		RECT 0.2105 45.44 124.236 45.5631 ;
		RECT 124.236 45.44 124.383 45.5631 ;
		RECT 0.2105 45.7686 124.236 45.9702 ;
		RECT 124.236 45.7686 124.383 45.9702 ;
		RECT 0.2105 46.08 124.236 46.2031 ;
		RECT 124.236 46.08 124.383 46.2031 ;
		RECT 0.2105 46.6667 124.236 46.9161 ;
		RECT 124.236 46.6667 124.383 46.9161 ;
		RECT 0.2105 47.3961 124.236 47.7349 ;
		RECT 124.236 47.3961 124.383 47.7349 ;
		RECT 0.2105 47.9231 124.236 48.262 ;
		RECT 124.236 47.9231 124.383 48.262 ;
		RECT 0.2105 48.4502 124.236 48.789 ;
		RECT 124.236 48.4502 124.383 48.789 ;
		RECT 0.2105 48.9773 124.236 49.3161 ;
		RECT 124.236 48.9773 124.383 49.3161 ;
		RECT 0.2105 49.5043 124.236 50.3702 ;
		RECT 124.236 49.5043 124.383 50.3702 ;
		RECT 0.2105 50.5584 124.236 51.4243 ;
		RECT 124.236 50.5584 124.383 51.4243 ;
		RECT 0.2105 51.6125 124.236 51.9514 ;
		RECT 124.236 51.6125 124.383 51.9514 ;
		RECT 0.2105 52.1396 124.236 52.4784 ;
		RECT 124.236 52.1396 124.383 52.4784 ;
		RECT 0.2105 52.6667 124.236 53.0055 ;
		RECT 124.236 52.6667 124.383 53.0055 ;
		RECT 0.2105 53.5639 124.236 53.8043 ;
		RECT 124.236 53.5639 124.383 53.8043 ;
		RECT 0.2105 54.1075 124.236 54.309 ;
		RECT 124.236 54.1075 124.383 54.309 ;
		RECT 0.2105 54.4188 124.236 54.542 ;
		RECT 124.236 54.4188 124.383 54.542 ;
		RECT 0.2105 54.7475 124.236 54.949 ;
		RECT 124.236 54.7475 124.383 54.949 ;
		RECT 0.2105 55.0588 124.236 55.182 ;
		RECT 124.236 55.0588 124.383 55.182 ;
		RECT 0.2105 55.3875 124.236 55.589 ;
		RECT 124.236 55.3875 124.383 55.589 ;
		RECT 0.2105 55.6988 124.236 55.822 ;
		RECT 124.236 55.6988 124.383 55.822 ;
		RECT 0.2105 56.0275 124.236 56.229 ;
		RECT 124.236 56.0275 124.383 56.229 ;
		RECT 0.2105 56.3388 124.236 56.462 ;
		RECT 124.236 56.3388 124.383 56.462 ;
		RECT 0.2105 56.6675 124.236 56.869 ;
		RECT 124.236 56.6675 124.383 56.869 ;
		RECT 0.2105 56.9788 124.236 57.102 ;
		RECT 124.236 56.9788 124.383 57.102 ;
		RECT 0.2105 57.3075 124.236 57.509 ;
		RECT 124.236 57.3075 124.383 57.509 ;
		RECT 0.2105 57.6188 124.236 57.742 ;
		RECT 124.236 57.6188 124.383 57.742 ;
		RECT 0.2105 57.9475 124.236 58.149 ;
		RECT 124.236 57.9475 124.383 58.149 ;
		RECT 0.2105 58.2588 124.236 58.382 ;
		RECT 124.236 58.2588 124.383 58.382 ;
		RECT 0.2105 58.5875 124.236 58.789 ;
		RECT 124.236 58.5875 124.383 58.789 ;
		RECT 0.2105 58.8988 124.236 59.022 ;
		RECT 124.236 58.8988 124.383 59.022 ;
		RECT 0.2105 59.2275 124.236 59.429 ;
		RECT 124.236 59.2275 124.383 59.429 ;
		RECT 0.2105 59.5388 124.236 59.662 ;
		RECT 124.236 59.5388 124.383 59.662 ;
		RECT 0.2105 59.8675 124.236 60.069 ;
		RECT 124.236 59.8675 124.383 60.069 ;
		RECT 0.2105 60.1788 124.236 60.302 ;
		RECT 124.236 60.1788 124.383 60.302 ;
		RECT 0.2105 60.5075 124.236 60.709 ;
		RECT 124.236 60.5075 124.383 60.709 ;
		RECT 0.2105 60.8188 124.236 60.942 ;
		RECT 124.236 60.8188 124.383 60.942 ;
		RECT 0.2105 61.1475 124.236 61.349 ;
		RECT 124.236 61.1475 124.383 61.349 ;
		RECT 0.2105 61.4588 124.236 61.582 ;
		RECT 124.236 61.4588 124.383 61.582 ;
		RECT 0.2105 61.7875 124.236 61.989 ;
		RECT 124.236 61.7875 124.383 61.989 ;
		RECT 0.2105 62.0988 124.236 62.222 ;
		RECT 124.236 62.0988 124.383 62.222 ;
		RECT 0.2105 62.4275 124.236 62.629 ;
		RECT 124.236 62.4275 124.383 62.629 ;
		RECT 0.2105 62.7388 124.236 62.862 ;
		RECT 124.236 62.7388 124.383 62.862 ;
		RECT 0.2105 63.0675 124.236 63.269 ;
		RECT 124.236 63.0675 124.383 63.269 ;
		RECT 0.2105 63.3788 124.236 63.502 ;
		RECT 124.236 63.3788 124.383 63.502 ;
		RECT 0.2105 63.7075 124.236 63.909 ;
		RECT 124.236 63.7075 124.383 63.909 ;
		RECT 0.2105 64.0188 124.236 64.142 ;
		RECT 124.236 64.0188 124.383 64.142 ;
		RECT 0.2105 64.3475 124.236 64.549 ;
		RECT 124.236 64.3475 124.383 64.549 ;
		RECT 0.2105 64.6588 124.236 64.782 ;
		RECT 124.236 64.6588 124.383 64.782 ;
		RECT 0.2105 64.9875 124.236 65.189 ;
		RECT 124.236 64.9875 124.383 65.189 ;
		RECT 0.2105 65.2988 124.236 65.422 ;
		RECT 124.236 65.2988 124.383 65.422 ;
		RECT 0.2105 65.6275 124.236 65.829 ;
		RECT 124.236 65.6275 124.383 65.829 ;
		RECT 0.2105 65.9388 124.236 66.062 ;
		RECT 124.236 65.9388 124.383 66.062 ;
		RECT 0.2105 66.2675 124.236 66.469 ;
		RECT 124.236 66.2675 124.383 66.469 ;
		RECT 0.2105 66.5788 124.236 66.702 ;
		RECT 124.236 66.5788 124.383 66.702 ;
		RECT 0.2105 66.9075 124.236 67.109 ;
		RECT 124.236 66.9075 124.383 67.109 ;
		RECT 0.2105 67.2188 124.236 67.342 ;
		RECT 124.236 67.2188 124.383 67.342 ;
		RECT 0.2105 67.5475 124.236 67.749 ;
		RECT 124.236 67.5475 124.383 67.749 ;
		RECT 0.2105 67.8588 124.236 67.982 ;
		RECT 124.236 67.8588 124.383 67.982 ;
		RECT 0.2105 68.1875 124.236 68.389 ;
		RECT 124.236 68.1875 124.383 68.389 ;
		RECT 0.2105 68.4988 124.236 68.622 ;
		RECT 124.236 68.4988 124.383 68.622 ;
		RECT 0.2105 68.8275 124.236 69.029 ;
		RECT 124.236 68.8275 124.383 69.029 ;
		RECT 0.2105 69.1388 124.236 69.262 ;
		RECT 124.236 69.1388 124.383 69.262 ;
		RECT 0.2105 69.4675 124.236 69.669 ;
		RECT 124.236 69.4675 124.383 69.669 ;
		RECT 0.2105 69.7788 124.236 69.902 ;
		RECT 124.236 69.7788 124.383 69.902 ;
		RECT 0.2105 70.1075 124.236 70.309 ;
		RECT 124.236 70.1075 124.383 70.309 ;
		RECT 0.2105 70.4188 124.236 70.542 ;
		RECT 124.236 70.4188 124.383 70.542 ;
		RECT 0.2105 70.7475 124.236 70.949 ;
		RECT 124.236 70.7475 124.383 70.949 ;
		RECT 0.2105 71.0588 124.236 71.182 ;
		RECT 124.236 71.0588 124.383 71.182 ;
		RECT 0.2105 71.3875 124.236 71.589 ;
		RECT 124.236 71.3875 124.383 71.589 ;
		RECT 0.2105 71.6988 124.236 71.822 ;
		RECT 124.236 71.6988 124.383 71.822 ;
		RECT 0.2105 72.0275 124.236 72.229 ;
		RECT 124.236 72.0275 124.383 72.229 ;
		RECT 0.2105 72.3388 124.236 72.462 ;
		RECT 124.236 72.3388 124.383 72.462 ;
		RECT 0.2105 72.6675 124.236 72.869 ;
		RECT 124.236 72.6675 124.383 72.869 ;
		RECT 0.2105 72.9788 124.236 73.102 ;
		RECT 124.236 72.9788 124.383 73.102 ;
		RECT 0.2105 73.3075 124.236 73.509 ;
		RECT 124.236 73.3075 124.383 73.509 ;
		RECT 0.2105 73.6188 124.236 73.742 ;
		RECT 124.236 73.6188 124.383 73.742 ;
		RECT 0.2105 73.9475 124.236 74.149 ;
		RECT 124.236 73.9475 124.383 74.149 ;
		RECT 0.2105 74.2588 124.236 74.382 ;
		RECT 124.236 74.2588 124.383 74.382 ;
		RECT 0.2105 74.5875 124.236 74.789 ;
		RECT 124.236 74.5875 124.383 74.789 ;
		RECT 0.2105 74.8988 124.236 75.022 ;
		RECT 124.236 74.8988 124.383 75.022 ;
		RECT 0.2105 75.2275 124.236 75.429 ;
		RECT 124.236 75.2275 124.383 75.429 ;
		RECT 0.2105 75.5388 124.236 75.662 ;
		RECT 124.236 75.5388 124.383 75.662 ;
		RECT 0.2105 75.8675 124.236 76.069 ;
		RECT 124.236 75.8675 124.383 76.069 ;
		RECT 0.2105 76.1788 124.236 76.302 ;
		RECT 124.236 76.1788 124.383 76.302 ;
		RECT 0.2105 76.5075 124.236 76.709 ;
		RECT 124.236 76.5075 124.383 76.709 ;
		RECT 0.2105 76.8188 124.236 76.942 ;
		RECT 124.236 76.8188 124.383 76.942 ;
		RECT 0.2105 77.1475 124.236 77.349 ;
		RECT 124.236 77.1475 124.383 77.349 ;
		RECT 0.2105 77.4588 124.236 77.582 ;
		RECT 124.236 77.4588 124.383 77.582 ;
		RECT 0.2105 77.7875 124.236 77.989 ;
		RECT 124.236 77.7875 124.383 77.989 ;
		RECT 0.2105 78.0988 124.236 78.222 ;
		RECT 124.236 78.0988 124.383 78.222 ;
		RECT 0.2105 78.4275 124.236 78.629 ;
		RECT 124.236 78.4275 124.383 78.629 ;
		RECT 0.2105 78.7388 124.236 78.862 ;
		RECT 124.236 78.7388 124.383 78.862 ;
		RECT 0.2105 79.0675 124.236 79.269 ;
		RECT 124.236 79.0675 124.383 79.269 ;
		RECT 0.2105 79.3788 124.236 79.502 ;
		RECT 124.236 79.3788 124.383 79.502 ;
		RECT 0.2105 79.7075 124.236 79.909 ;
		RECT 124.236 79.7075 124.383 79.909 ;
		RECT 0.2105 80.0188 124.236 80.142 ;
		RECT 124.236 80.0188 124.383 80.142 ;
		RECT 0.2105 80.3475 124.236 80.549 ;
		RECT 124.236 80.3475 124.383 80.549 ;
		RECT 0.2105 80.6588 124.236 80.782 ;
		RECT 124.236 80.6588 124.383 80.782 ;
		RECT 0.2105 80.9875 124.236 81.189 ;
		RECT 124.236 80.9875 124.383 81.189 ;
		RECT 0.2105 81.2988 124.236 81.422 ;
		RECT 124.236 81.2988 124.383 81.422 ;
		RECT 0.2105 81.6275 124.236 81.829 ;
		RECT 124.236 81.6275 124.383 81.829 ;
		RECT 0.2105 81.9388 124.236 82.062 ;
		RECT 124.236 81.9388 124.383 82.062 ;
		RECT 0.2105 82.2675 124.236 82.469 ;
		RECT 124.236 82.2675 124.383 82.469 ;
		RECT 0.2105 82.5788 124.236 82.702 ;
		RECT 124.236 82.5788 124.383 82.702 ;
		RECT 0.2105 82.9075 124.236 83.109 ;
		RECT 124.236 82.9075 124.383 83.109 ;
		RECT 0.2105 83.2188 124.236 83.342 ;
		RECT 124.236 83.2188 124.383 83.342 ;
		RECT 0.2105 83.5475 124.236 83.749 ;
		RECT 124.236 83.5475 124.383 83.749 ;
		RECT 0.2105 83.8588 124.236 83.982 ;
		RECT 124.236 83.8588 124.383 83.982 ;
		RECT 0.2105 84.1875 124.236 84.389 ;
		RECT 124.236 84.1875 124.383 84.389 ;
		RECT 0.2105 84.4988 124.236 84.622 ;
		RECT 124.236 84.4988 124.383 84.622 ;
		RECT 0.2105 84.8275 124.236 85.029 ;
		RECT 124.236 84.8275 124.383 85.029 ;
		RECT 0.2105 85.1388 124.236 85.262 ;
		RECT 124.236 85.1388 124.383 85.262 ;
		RECT 0.2105 85.4675 124.236 85.669 ;
		RECT 124.236 85.4675 124.383 85.669 ;
		RECT 0.2105 85.7788 124.236 85.902 ;
		RECT 124.236 85.7788 124.383 85.902 ;
		RECT 0.2105 86.1075 124.236 86.309 ;
		RECT 124.236 86.1075 124.383 86.309 ;
		RECT 0.2105 86.4188 124.236 86.542 ;
		RECT 124.236 86.4188 124.383 86.542 ;
		RECT 0.2105 86.7475 124.236 86.949 ;
		RECT 124.236 86.7475 124.383 86.949 ;
		RECT 0.2105 87.0588 124.236 87.182 ;
		RECT 124.236 87.0588 124.383 87.182 ;
		RECT 0.2105 87.3875 124.236 87.589 ;
		RECT 124.236 87.3875 124.383 87.589 ;
		RECT 0.2105 87.6988 124.236 87.822 ;
		RECT 124.236 87.6988 124.383 87.822 ;
		RECT 0.2105 88.0275 124.236 88.229 ;
		RECT 124.236 88.0275 124.383 88.229 ;
		RECT 0.2105 88.3388 124.236 88.462 ;
		RECT 124.236 88.3388 124.383 88.462 ;
		RECT 0.2105 88.6675 124.236 88.869 ;
		RECT 124.236 88.6675 124.383 88.869 ;
		RECT 0.2105 88.9788 124.236 89.102 ;
		RECT 124.236 88.9788 124.383 89.102 ;
		RECT 0.2105 89.3075 124.236 89.509 ;
		RECT 124.236 89.3075 124.383 89.509 ;
		RECT 0.2105 89.6188 124.236 89.742 ;
		RECT 124.236 89.6188 124.383 89.742 ;
		RECT 0.2105 89.9475 124.236 90.149 ;
		RECT 124.236 89.9475 124.383 90.149 ;
		RECT 0.2105 90.2588 124.236 90.382 ;
		RECT 124.236 90.2588 124.383 90.382 ;
		RECT 0.2105 90.5875 124.236 90.789 ;
		RECT 124.236 90.5875 124.383 90.789 ;
		RECT 0.2105 90.8988 124.236 91.022 ;
		RECT 124.236 90.8988 124.383 91.022 ;
		RECT 0.2105 91.2275 124.236 91.429 ;
		RECT 124.236 91.2275 124.383 91.429 ;
		RECT 0.2105 91.5388 124.236 91.662 ;
		RECT 124.236 91.5388 124.383 91.662 ;
		RECT 0.2105 91.8675 124.236 92.069 ;
		RECT 124.236 91.8675 124.383 92.069 ;
		RECT 0.2105 92.1788 124.236 92.302 ;
		RECT 124.236 92.1788 124.383 92.302 ;
		RECT 0.2105 92.5075 124.236 92.709 ;
		RECT 124.236 92.5075 124.383 92.709 ;
		RECT 0.2105 92.8188 124.236 92.942 ;
		RECT 124.236 92.8188 124.383 92.942 ;
		RECT 0.2105 93.1475 124.236 93.349 ;
		RECT 124.236 93.1475 124.383 93.349 ;
		RECT 0.2105 93.4588 124.236 93.582 ;
		RECT 124.236 93.4588 124.383 93.582 ;
		RECT 0.2105 93.7875 124.236 93.989 ;
		RECT 124.236 93.7875 124.383 93.989 ;
		RECT 0.2105 94.0988 124.236 94.222 ;
		RECT 124.236 94.0988 124.383 94.222 ;
		RECT 0.2105 94.4275 124.236 94.629 ;
		RECT 124.236 94.4275 124.383 94.629 ;
		RECT 0.2105 94.7388 124.236 94.862 ;
		RECT 124.236 94.7388 124.383 94.862 ;
		RECT 0.2105 95.0675 124.236 95.269 ;
		RECT 124.236 95.0675 124.383 95.269 ;
		RECT 0.2105 95.3788 124.236 95.502 ;
		RECT 124.236 95.3788 124.383 95.502 ;
		RECT 0.2105 95.7075 124.236 95.909 ;
		RECT 124.236 95.7075 124.383 95.909 ;
		RECT 0.2105 96.0188 124.236 96.142 ;
		RECT 124.236 96.0188 124.383 96.142 ;
		RECT 0.2105 96.3475 124.236 96.549 ;
		RECT 124.236 96.3475 124.383 96.549 ;
		RECT 0.2105 96.6588 124.236 96.782 ;
		RECT 124.236 96.6588 124.383 96.782 ;
		RECT 0.2105 96.9875 124.236 97.189 ;
		RECT 124.236 96.9875 124.383 97.189 ;
		RECT 0.2105 97.2988 124.236 97.422 ;
		RECT 124.236 97.2988 124.383 97.422 ;
		RECT 0.2105 97.6275 124.236 97.829 ;
		RECT 124.236 97.6275 124.383 97.829 ;
		RECT 0.2105 97.9388 124.236 98.062 ;
		RECT 124.236 97.9388 124.383 98.062 ;
		RECT 0.2105 98.2675 124.236 98.469 ;
		RECT 124.236 98.2675 124.383 98.469 ;
		RECT 0.2105 98.5788 124.236 98.702 ;
		RECT 124.236 98.5788 124.383 98.702 ;
		RECT 0.2105 98.9075 124.236 99.109 ;
		RECT 124.236 98.9075 124.383 99.109 ;
		RECT 0.2105 99.2188 124.236 99.342 ;
		RECT 124.236 99.2188 124.383 99.342 ;
		RECT 0.2105 99.5475 124.236 99.749 ;
		RECT 124.236 99.5475 124.383 99.749 ;
		RECT 0.2105 99.8588 124.236 99.982 ;
		RECT 124.236 99.8588 124.383 99.982 ;
		RECT 0.2105 100.5263 124.236 100.6494 ;
		RECT 124.236 100.5263 124.383 100.6494 ;
		RECT 0.2105 100.7592 124.236 100.9608 ;
		RECT 124.236 100.7592 124.383 100.9608 ;
		RECT 0.2105 101.1663 124.236 101.2894 ;
		RECT 124.236 101.1663 124.383 101.2894 ;
		RECT 0.2105 101.3992 124.236 101.6008 ;
		RECT 124.236 101.3992 124.383 101.6008 ;
		RECT 0.2105 101.8063 124.236 101.9294 ;
		RECT 124.236 101.8063 124.383 101.9294 ;
		RECT 0.2105 102.0392 124.236 102.2408 ;
		RECT 124.236 102.0392 124.383 102.2408 ;
		RECT 0.2105 102.4463 124.236 102.5694 ;
		RECT 124.236 102.4463 124.383 102.5694 ;
		RECT 0.2105 102.6792 124.236 102.8808 ;
		RECT 124.236 102.6792 124.383 102.8808 ;
		RECT 0.2105 103.0863 124.236 103.2094 ;
		RECT 124.236 103.0863 124.383 103.2094 ;
		RECT 0.2105 103.3192 124.236 103.5208 ;
		RECT 124.236 103.3192 124.383 103.5208 ;
		RECT 0.2105 103.7263 124.236 103.8494 ;
		RECT 124.236 103.7263 124.383 103.8494 ;
		RECT 0.2105 103.9592 124.236 104.1608 ;
		RECT 124.236 103.9592 124.383 104.1608 ;
		RECT 0.2105 104.3663 124.236 104.4894 ;
		RECT 124.236 104.3663 124.383 104.4894 ;
		RECT 0.2105 104.5992 124.236 104.8008 ;
		RECT 124.236 104.5992 124.383 104.8008 ;
		RECT 0.2105 105.0063 124.236 105.1294 ;
		RECT 124.236 105.0063 124.383 105.1294 ;
		RECT 0.2105 105.2392 124.236 105.4408 ;
		RECT 124.236 105.2392 124.383 105.4408 ;
		RECT 0.2105 105.6463 124.236 105.7694 ;
		RECT 124.236 105.6463 124.383 105.7694 ;
		RECT 0.2105 105.8792 124.236 106.0808 ;
		RECT 124.236 105.8792 124.383 106.0808 ;
		RECT 0.2105 106.2863 124.236 106.4094 ;
		RECT 124.236 106.2863 124.383 106.4094 ;
		RECT 0.2105 106.5192 124.236 106.7208 ;
		RECT 124.236 106.5192 124.383 106.7208 ;
		RECT 0.2105 106.9263 124.236 107.0494 ;
		RECT 124.236 106.9263 124.383 107.0494 ;
		RECT 0.2105 107.1592 124.236 107.3608 ;
		RECT 124.236 107.1592 124.383 107.3608 ;
		RECT 0.2105 107.5663 124.236 107.6894 ;
		RECT 124.236 107.5663 124.383 107.6894 ;
		RECT 0.2105 107.7992 124.236 108.0008 ;
		RECT 124.236 107.7992 124.383 108.0008 ;
		RECT 0.2105 108.2063 124.236 108.3294 ;
		RECT 124.236 108.2063 124.383 108.3294 ;
		RECT 0.2105 108.4392 124.236 108.6408 ;
		RECT 124.236 108.4392 124.383 108.6408 ;
		RECT 0.2105 108.8463 124.236 108.9694 ;
		RECT 124.236 108.8463 124.383 108.9694 ;
		RECT 0.2105 109.0792 124.236 109.2808 ;
		RECT 124.236 109.0792 124.383 109.2808 ;
		RECT 0.2105 109.4863 124.236 109.6094 ;
		RECT 124.236 109.4863 124.383 109.6094 ;
		RECT 0.2105 109.7192 124.236 109.9208 ;
		RECT 124.236 109.7192 124.383 109.9208 ;
		RECT 0.2105 110.1263 124.236 110.2494 ;
		RECT 124.236 110.1263 124.383 110.2494 ;
		RECT 0.2105 110.3592 124.236 110.5608 ;
		RECT 124.236 110.3592 124.383 110.5608 ;
		RECT 0.2105 110.7663 124.236 110.8894 ;
		RECT 124.236 110.7663 124.383 110.8894 ;
		RECT 0.2105 110.9992 124.236 111.2008 ;
		RECT 124.236 110.9992 124.383 111.2008 ;
		RECT 0.2105 111.4063 124.236 111.5294 ;
		RECT 124.236 111.4063 124.383 111.5294 ;
		RECT 0.2105 111.6392 124.236 111.8408 ;
		RECT 124.236 111.6392 124.383 111.8408 ;
		RECT 0.2105 112.0463 124.236 112.1694 ;
		RECT 124.236 112.0463 124.383 112.1694 ;
		RECT 0.2105 112.2792 124.236 112.4808 ;
		RECT 124.236 112.2792 124.383 112.4808 ;
		RECT 0.2105 112.6863 124.236 112.8094 ;
		RECT 124.236 112.6863 124.383 112.8094 ;
		RECT 0.2105 112.9192 124.236 113.1208 ;
		RECT 124.236 112.9192 124.383 113.1208 ;
		RECT 0.2105 113.3263 124.236 113.4494 ;
		RECT 124.236 113.3263 124.383 113.4494 ;
		RECT 0.2105 113.5592 124.236 113.7608 ;
		RECT 124.236 113.5592 124.383 113.7608 ;
		RECT 0.2105 113.9663 124.236 114.0894 ;
		RECT 124.236 113.9663 124.383 114.0894 ;
		RECT 0.2105 114.1992 124.236 114.4008 ;
		RECT 124.236 114.1992 124.383 114.4008 ;
		RECT 0.2105 114.6063 124.236 114.7294 ;
		RECT 124.236 114.6063 124.383 114.7294 ;
		RECT 0.2105 114.8392 124.236 115.0408 ;
		RECT 124.236 114.8392 124.383 115.0408 ;
		RECT 0.2105 115.2463 124.236 115.3694 ;
		RECT 124.236 115.2463 124.383 115.3694 ;
		RECT 0.2105 115.4792 124.236 115.6808 ;
		RECT 124.236 115.4792 124.383 115.6808 ;
		RECT 0.2105 115.8863 124.236 116.0094 ;
		RECT 124.236 115.8863 124.383 116.0094 ;
		RECT 0.2105 116.1192 124.236 116.3208 ;
		RECT 124.236 116.1192 124.383 116.3208 ;
		RECT 0.2105 116.5263 124.236 116.6494 ;
		RECT 124.236 116.5263 124.383 116.6494 ;
		RECT 0.2105 116.7592 124.236 116.9608 ;
		RECT 124.236 116.7592 124.383 116.9608 ;
		RECT 0.2105 117.1663 124.236 117.2894 ;
		RECT 124.236 117.1663 124.383 117.2894 ;
		RECT 0.2105 117.3992 124.236 117.6008 ;
		RECT 124.236 117.3992 124.383 117.6008 ;
		RECT 0.2105 117.8063 124.236 117.9294 ;
		RECT 124.236 117.8063 124.383 117.9294 ;
		RECT 0.2105 118.0392 124.236 118.2408 ;
		RECT 124.236 118.0392 124.383 118.2408 ;
		RECT 0.2105 118.4463 124.236 118.5694 ;
		RECT 124.236 118.4463 124.383 118.5694 ;
		RECT 0.2105 118.6792 124.236 118.8808 ;
		RECT 124.236 118.6792 124.383 118.8808 ;
		RECT 0.2105 119.0863 124.236 119.2094 ;
		RECT 124.236 119.0863 124.383 119.2094 ;
		RECT 0.2105 119.3192 124.236 119.5208 ;
		RECT 124.236 119.3192 124.383 119.5208 ;
		RECT 0.2105 119.7263 124.236 119.8494 ;
		RECT 124.236 119.7263 124.383 119.8494 ;
		RECT 0.2105 119.9592 124.236 120.1608 ;
		RECT 124.236 119.9592 124.383 120.1608 ;
		RECT 0.2105 120.3663 124.236 120.4894 ;
		RECT 124.236 120.3663 124.383 120.4894 ;
		RECT 0.2105 120.5992 124.236 120.8008 ;
		RECT 124.236 120.5992 124.383 120.8008 ;
		RECT 0.2105 121.0063 124.236 121.1294 ;
		RECT 124.236 121.0063 124.383 121.1294 ;
		RECT 0.2105 121.2392 124.236 121.4408 ;
		RECT 124.236 121.2392 124.383 121.4408 ;
		RECT 0.2105 121.6463 124.236 121.7694 ;
		RECT 124.236 121.6463 124.383 121.7694 ;
		RECT 0.2105 121.8792 124.236 122.0808 ;
		RECT 124.236 121.8792 124.383 122.0808 ;
		RECT 0.2105 122.2863 124.236 122.4094 ;
		RECT 124.236 122.2863 124.383 122.4094 ;
		RECT 0.2105 122.5192 124.236 122.7208 ;
		RECT 124.236 122.5192 124.383 122.7208 ;
		RECT 0.2105 122.9263 124.236 123.0494 ;
		RECT 124.236 122.9263 124.383 123.0494 ;
		RECT 0.2105 123.1592 124.236 123.3608 ;
		RECT 124.236 123.1592 124.383 123.3608 ;
		RECT 0.2105 123.5663 124.236 123.6894 ;
		RECT 124.236 123.5663 124.383 123.6894 ;
		RECT 0.2105 123.7992 124.236 124.0008 ;
		RECT 124.236 123.7992 124.383 124.0008 ;
		RECT 0.2105 124.2063 124.236 124.3294 ;
		RECT 124.236 124.2063 124.383 124.3294 ;
		RECT 0.2105 124.4392 124.236 124.6408 ;
		RECT 124.236 124.4392 124.383 124.6408 ;
		RECT 0.2105 124.8463 124.236 124.9694 ;
		RECT 124.236 124.8463 124.383 124.9694 ;
		RECT 0.2105 125.0792 124.236 125.2808 ;
		RECT 124.236 125.0792 124.383 125.2808 ;
		RECT 0.2105 125.4863 124.236 125.6094 ;
		RECT 124.236 125.4863 124.383 125.6094 ;
		RECT 0.2105 125.7192 124.236 125.9208 ;
		RECT 124.236 125.7192 124.383 125.9208 ;
		RECT 0.2105 126.1263 124.236 126.2494 ;
		RECT 124.236 126.1263 124.383 126.2494 ;
		RECT 0.2105 126.3592 124.236 126.5608 ;
		RECT 124.236 126.3592 124.383 126.5608 ;
		RECT 0.2105 126.7663 124.236 126.8894 ;
		RECT 124.236 126.7663 124.383 126.8894 ;
		RECT 0.2105 126.9992 124.236 127.2008 ;
		RECT 124.236 126.9992 124.383 127.2008 ;
		RECT 0.2105 127.4063 124.236 127.5294 ;
		RECT 124.236 127.4063 124.383 127.5294 ;
		RECT 0.2105 127.6392 124.236 127.8408 ;
		RECT 124.236 127.6392 124.383 127.8408 ;
		RECT 0.2105 128.0463 124.236 128.1694 ;
		RECT 124.236 128.0463 124.383 128.1694 ;
		RECT 0.2105 128.2792 124.236 128.4808 ;
		RECT 124.236 128.2792 124.383 128.4808 ;
		RECT 0.2105 128.6863 124.236 128.8094 ;
		RECT 124.236 128.6863 124.383 128.8094 ;
		RECT 0.2105 128.9192 124.236 129.1208 ;
		RECT 124.236 128.9192 124.383 129.1208 ;
		RECT 0.2105 129.3263 124.236 129.4494 ;
		RECT 124.236 129.3263 124.383 129.4494 ;
		RECT 0.2105 129.5592 124.236 129.7608 ;
		RECT 124.236 129.5592 124.383 129.7608 ;
		RECT 0.2105 129.9663 124.236 130.0894 ;
		RECT 124.236 129.9663 124.383 130.0894 ;
		RECT 0.2105 130.1992 124.236 130.4008 ;
		RECT 124.236 130.1992 124.383 130.4008 ;
		RECT 0.2105 130.6063 124.236 130.7294 ;
		RECT 124.236 130.6063 124.383 130.7294 ;
		RECT 0.2105 130.8392 124.236 131.0408 ;
		RECT 124.236 130.8392 124.383 131.0408 ;
		RECT 0.2105 131.2463 124.236 131.3694 ;
		RECT 124.236 131.2463 124.383 131.3694 ;
		RECT 0.2105 131.4792 124.236 131.6808 ;
		RECT 124.236 131.4792 124.383 131.6808 ;
		RECT 0.2105 131.8863 124.236 132.0094 ;
		RECT 124.236 131.8863 124.383 132.0094 ;
		RECT 0.2105 132.1192 124.236 132.3208 ;
		RECT 124.236 132.1192 124.383 132.3208 ;
		RECT 0.2105 132.5263 124.236 132.6494 ;
		RECT 124.236 132.5263 124.383 132.6494 ;
		RECT 0.2105 132.7592 124.236 132.9608 ;
		RECT 124.236 132.7592 124.383 132.9608 ;
		RECT 0.2105 133.1663 124.236 133.2894 ;
		RECT 124.236 133.1663 124.383 133.2894 ;
		RECT 0.2105 133.3992 124.236 133.6008 ;
		RECT 124.236 133.3992 124.383 133.6008 ;
		RECT 0.2105 133.8063 124.236 133.9294 ;
		RECT 124.236 133.8063 124.383 133.9294 ;
		RECT 0.2105 134.0392 124.236 134.2408 ;
		RECT 124.236 134.0392 124.383 134.2408 ;
		RECT 0.2105 134.4463 124.236 134.5694 ;
		RECT 124.236 134.4463 124.383 134.5694 ;
		RECT 0.2105 134.6792 124.236 134.8808 ;
		RECT 124.236 134.6792 124.383 134.8808 ;
		RECT 0.2105 135.0863 124.236 135.2094 ;
		RECT 124.236 135.0863 124.383 135.2094 ;
		RECT 0.2105 135.3192 124.236 135.5208 ;
		RECT 124.236 135.3192 124.383 135.5208 ;
		RECT 0.2105 135.7263 124.236 135.8494 ;
		RECT 124.236 135.7263 124.383 135.8494 ;
		RECT 0.2105 135.9592 124.236 136.1608 ;
		RECT 124.236 135.9592 124.383 136.1608 ;
		RECT 0.2105 136.3663 124.236 136.4894 ;
		RECT 124.236 136.3663 124.383 136.4894 ;
		RECT 0.2105 136.5992 124.236 136.8008 ;
		RECT 124.236 136.5992 124.383 136.8008 ;
		RECT 0.2105 137.0063 124.236 137.1294 ;
		RECT 124.236 137.0063 124.383 137.1294 ;
		RECT 0.2105 137.2392 124.236 137.4408 ;
		RECT 124.236 137.2392 124.383 137.4408 ;
		RECT 0.2105 137.6463 124.236 137.7694 ;
		RECT 124.236 137.6463 124.383 137.7694 ;
		RECT 0.2105 137.8792 124.236 138.0808 ;
		RECT 124.236 137.8792 124.383 138.0808 ;
		RECT 0.2105 138.2863 124.236 138.4094 ;
		RECT 124.236 138.2863 124.383 138.4094 ;
		RECT 0.2105 138.5192 124.236 138.7208 ;
		RECT 124.236 138.5192 124.383 138.7208 ;
		RECT 0.2105 138.9263 124.236 139.0494 ;
		RECT 124.236 138.9263 124.383 139.0494 ;
		RECT 0.2105 139.1592 124.236 139.3608 ;
		RECT 124.236 139.1592 124.383 139.3608 ;
		RECT 0.2105 139.5663 124.236 139.6894 ;
		RECT 124.236 139.5663 124.383 139.6894 ;
		RECT 0.2105 139.7992 124.236 140.0008 ;
		RECT 124.236 139.7992 124.383 140.0008 ;
		RECT 0.2105 140.2063 124.236 140.3294 ;
		RECT 124.236 140.2063 124.383 140.3294 ;
		RECT 0.2105 140.4392 124.236 140.6408 ;
		RECT 124.236 140.4392 124.383 140.6408 ;
		RECT 0.2105 140.8463 124.236 140.9694 ;
		RECT 124.236 140.8463 124.383 140.9694 ;
		RECT 0.2105 141.0792 124.236 141.2808 ;
		RECT 124.236 141.0792 124.383 141.2808 ;
		RECT 0.2105 141.4863 124.236 141.6094 ;
		RECT 124.236 141.4863 124.383 141.6094 ;
		RECT 0.2105 141.7192 124.236 141.9208 ;
		RECT 124.236 141.7192 124.383 141.9208 ;
		RECT 0.2105 142.1263 124.236 142.2494 ;
		RECT 124.236 142.1263 124.383 142.2494 ;
		RECT 0.2105 142.3592 124.236 142.5608 ;
		RECT 124.236 142.3592 124.383 142.5608 ;
		RECT 0.2105 142.7663 124.236 142.8894 ;
		RECT 124.236 142.7663 124.383 142.8894 ;
		RECT 0.2105 142.9992 124.236 143.2008 ;
		RECT 124.236 142.9992 124.383 143.2008 ;
		RECT 0.2105 143.4063 124.236 143.5294 ;
		RECT 124.236 143.4063 124.383 143.5294 ;
		RECT 0.2105 143.6392 124.236 143.8408 ;
		RECT 124.236 143.6392 124.383 143.8408 ;
		RECT 0.2105 144.0463 124.236 144.1694 ;
		RECT 124.236 144.0463 124.383 144.1694 ;
		RECT 0.2105 144.2792 124.236 144.4808 ;
		RECT 124.236 144.2792 124.383 144.4808 ;
		RECT 0.2105 144.6863 124.236 144.8094 ;
		RECT 124.236 144.6863 124.383 144.8094 ;
		RECT 0.2105 144.9192 124.236 145.1208 ;
		RECT 124.236 144.9192 124.383 145.1208 ;
		RECT 0.2105 145.3263 124.236 145.4494 ;
		RECT 124.236 145.3263 124.383 145.4494 ;
		RECT 0.2105 145.5592 124.236 145.7608 ;
		RECT 124.236 145.5592 124.383 145.7608 ;
		RECT 0.2105 145.9663 124.236 146.0894 ;
		RECT 124.236 145.9663 124.383 146.0894 ;
		RECT 0.2105 146.1992 124.236 146.4008 ;
		RECT 124.236 146.1992 124.383 146.4008 ;
		RECT 0.2105 146.7039 124.236 146.9443 ;
		RECT 124.236 146.7039 124.383 146.9443 ;
		RECT 0.2105 147.5027 124.236 147.8416 ;
		RECT 124.236 147.5027 124.383 147.8416 ;
		RECT 0.2105 148.0298 124.236 148.3686 ;
		RECT 124.236 148.0298 124.383 148.3686 ;
		RECT 0.2105 148.5569 124.236 148.8957 ;
		RECT 124.236 148.5569 124.383 148.8957 ;
		RECT 0.2105 149.0839 124.236 149.9498 ;
		RECT 124.236 149.0839 124.383 149.9498 ;
		RECT 0.2105 150.138 124.236 151.0039 ;
		RECT 124.236 150.138 124.383 151.0039 ;
		RECT 0.2105 151.1922 124.236 151.531 ;
		RECT 124.236 151.1922 124.383 151.531 ;
		RECT 0.2105 151.7192 124.236 152.058 ;
		RECT 124.236 151.7192 124.383 152.058 ;
		RECT 0.2105 152.2463 124.236 152.5851 ;
		RECT 124.236 152.2463 124.383 152.5851 ;
		RECT 0.2105 152.7733 124.236 153.1122 ;
		RECT 124.236 152.7733 124.383 153.1122 ;
		RECT 0.2105 153.5922 124.236 153.8416 ;
		RECT 124.236 153.5922 124.383 153.8416 ;
		RECT 0.2105 154.3051 124.236 154.4282 ;
		RECT 124.236 154.3051 124.383 154.4282 ;
		RECT 0.2105 154.538 124.236 154.7396 ;
		RECT 124.236 154.538 124.383 154.7396 ;
		RECT 0.2105 154.9451 124.236 155.0682 ;
		RECT 124.236 154.9451 124.383 155.0682 ;
		RECT 0.2105 155.178 124.236 155.3796 ;
		RECT 124.236 155.178 124.383 155.3796 ;
		RECT 0.2105 155.5851 124.236 155.7082 ;
		RECT 124.236 155.5851 124.383 155.7082 ;
		RECT 0.2105 155.818 124.236 156.0196 ;
		RECT 124.236 155.818 124.383 156.0196 ;
		RECT 0.2105 156.2251 124.236 156.3482 ;
		RECT 124.236 156.2251 124.383 156.3482 ;
		RECT 0.2105 156.458 124.236 156.6596 ;
		RECT 124.236 156.458 124.383 156.6596 ;
		RECT 0.2105 156.8651 124.236 156.9882 ;
		RECT 124.236 156.8651 124.383 156.9882 ;
		RECT 0.2105 157.098 124.236 157.2996 ;
		RECT 124.236 157.098 124.383 157.2996 ;
		RECT 0.2105 157.5051 124.236 157.6282 ;
		RECT 124.236 157.5051 124.383 157.6282 ;
		RECT 0.2105 157.738 124.236 157.9396 ;
		RECT 124.236 157.738 124.383 157.9396 ;
		RECT 0.2105 158.1451 124.236 158.2682 ;
		RECT 124.236 158.1451 124.383 158.2682 ;
		RECT 0.2105 158.378 124.236 158.5796 ;
		RECT 124.236 158.378 124.383 158.5796 ;
		RECT 0.2105 158.7851 124.236 158.9082 ;
		RECT 124.236 158.7851 124.383 158.9082 ;
		RECT 0.2105 159.018 124.236 159.2196 ;
		RECT 124.236 159.018 124.383 159.2196 ;
		RECT 0.2105 159.4251 124.236 159.5482 ;
		RECT 124.236 159.4251 124.383 159.5482 ;
		RECT 0.2105 159.658 124.236 159.8596 ;
		RECT 124.236 159.658 124.383 159.8596 ;
		RECT 0.2105 160.0651 124.236 160.1882 ;
		RECT 124.236 160.0651 124.383 160.1882 ;
		RECT 0.2105 160.298 124.236 160.4996 ;
		RECT 124.236 160.298 124.383 160.4996 ;
		RECT 0.2105 160.7051 124.236 160.8282 ;
		RECT 124.236 160.7051 124.383 160.8282 ;
		RECT 0.2105 160.938 124.236 161.1396 ;
		RECT 124.236 160.938 124.383 161.1396 ;
		RECT 0.2105 161.3451 124.236 161.4682 ;
		RECT 124.236 161.3451 124.383 161.4682 ;
		RECT 0.2105 161.578 124.236 161.7796 ;
		RECT 124.236 161.578 124.383 161.7796 ;
		RECT 0.2105 161.9851 124.236 162.1082 ;
		RECT 124.236 161.9851 124.383 162.1082 ;
		RECT 0.2105 162.218 124.236 162.4196 ;
		RECT 124.236 162.218 124.383 162.4196 ;
		RECT 0.2105 162.6251 124.236 162.7482 ;
		RECT 124.236 162.6251 124.383 162.7482 ;
		RECT 0.2105 162.858 124.236 163.0596 ;
		RECT 124.236 162.858 124.383 163.0596 ;
		RECT 0.2105 163.2651 124.236 163.3882 ;
		RECT 124.236 163.2651 124.383 163.3882 ;
		RECT 0.2105 163.498 124.236 163.6996 ;
		RECT 124.236 163.498 124.383 163.6996 ;
		RECT 0.2105 163.9051 124.236 164.0282 ;
		RECT 124.236 163.9051 124.383 164.0282 ;
		RECT 0.2105 164.138 124.236 164.3396 ;
		RECT 124.236 164.138 124.383 164.3396 ;
		RECT 0.2105 164.5451 124.236 164.6682 ;
		RECT 124.236 164.5451 124.383 164.6682 ;
		RECT 0.2105 164.778 124.236 164.9796 ;
		RECT 124.236 164.778 124.383 164.9796 ;
		RECT 0.2105 165.1851 124.236 165.3082 ;
		RECT 124.236 165.1851 124.383 165.3082 ;
		RECT 0.2105 165.418 124.236 165.6196 ;
		RECT 124.236 165.418 124.383 165.6196 ;
		RECT 0.2105 165.8251 124.236 165.9482 ;
		RECT 124.236 165.8251 124.383 165.9482 ;
		RECT 0.2105 166.058 124.236 166.2596 ;
		RECT 124.236 166.058 124.383 166.2596 ;
		RECT 0.2105 166.4651 124.236 166.5882 ;
		RECT 124.236 166.4651 124.383 166.5882 ;
		RECT 0.2105 166.698 124.236 166.8996 ;
		RECT 124.236 166.698 124.383 166.8996 ;
		RECT 0.2105 167.1051 124.236 167.2282 ;
		RECT 124.236 167.1051 124.383 167.2282 ;
		RECT 0.2105 167.338 124.236 167.5396 ;
		RECT 124.236 167.338 124.383 167.5396 ;
		RECT 0.2105 167.7451 124.236 167.8682 ;
		RECT 124.236 167.7451 124.383 167.8682 ;
		RECT 0.2105 167.978 124.236 168.1796 ;
		RECT 124.236 167.978 124.383 168.1796 ;
		RECT 0.2105 168.3851 124.236 168.5082 ;
		RECT 124.236 168.3851 124.383 168.5082 ;
		RECT 0.2105 168.618 124.236 168.8196 ;
		RECT 124.236 168.618 124.383 168.8196 ;
		RECT 0.2105 169.0251 124.236 169.1482 ;
		RECT 124.236 169.0251 124.383 169.1482 ;
		RECT 0.2105 169.258 124.236 169.4596 ;
		RECT 124.236 169.258 124.383 169.4596 ;
		RECT 0.2105 169.6651 124.236 169.7882 ;
		RECT 124.236 169.6651 124.383 169.7882 ;
		RECT 0.2105 169.898 124.236 170.0996 ;
		RECT 124.236 169.898 124.383 170.0996 ;
		RECT 0.2105 170.3051 124.236 170.4282 ;
		RECT 124.236 170.3051 124.383 170.4282 ;
		RECT 0.2105 170.538 124.236 170.7396 ;
		RECT 124.236 170.538 124.383 170.7396 ;
		RECT 0.2105 170.9451 124.236 171.0682 ;
		RECT 124.236 170.9451 124.383 171.0682 ;
		RECT 0.2105 171.178 124.236 171.3796 ;
		RECT 124.236 171.178 124.383 171.3796 ;
		RECT 0.2105 171.5851 124.236 171.7082 ;
		RECT 124.236 171.5851 124.383 171.7082 ;
		RECT 0.2105 171.818 124.236 172.0196 ;
		RECT 124.236 171.818 124.383 172.0196 ;
		RECT 0.2105 172.2251 124.236 172.3482 ;
		RECT 124.236 172.2251 124.383 172.3482 ;
		RECT 0.2105 172.458 124.236 172.6596 ;
		RECT 124.236 172.458 124.383 172.6596 ;
		RECT 0.2105 172.8651 124.236 172.9882 ;
		RECT 124.236 172.8651 124.383 172.9882 ;
		RECT 0.2105 173.098 124.236 173.2996 ;
		RECT 124.236 173.098 124.383 173.2996 ;
		RECT 0.2105 173.5051 124.236 173.6282 ;
		RECT 124.236 173.5051 124.383 173.6282 ;
		RECT 0.2105 173.738 124.236 173.9396 ;
		RECT 124.236 173.738 124.383 173.9396 ;
		RECT 0.2105 174.1451 124.236 174.2682 ;
		RECT 124.236 174.1451 124.383 174.2682 ;
		RECT 0.2105 174.378 124.236 174.5796 ;
		RECT 124.236 174.378 124.383 174.5796 ;
		RECT 0.2105 174.7851 124.236 174.9082 ;
		RECT 124.236 174.7851 124.383 174.9082 ;
		RECT 0.2105 175.018 124.236 175.2196 ;
		RECT 124.236 175.018 124.383 175.2196 ;
		RECT 0.2105 175.4251 124.236 175.5482 ;
		RECT 124.236 175.4251 124.383 175.5482 ;
		RECT 0.2105 175.658 124.236 175.8596 ;
		RECT 124.236 175.658 124.383 175.8596 ;
		RECT 0.2105 176.0651 124.236 176.1882 ;
		RECT 124.236 176.0651 124.383 176.1882 ;
		RECT 0.2105 176.298 124.236 176.4996 ;
		RECT 124.236 176.298 124.383 176.4996 ;
		RECT 0.2105 176.7051 124.236 176.8282 ;
		RECT 124.236 176.7051 124.383 176.8282 ;
		RECT 0.2105 176.938 124.236 177.1396 ;
		RECT 124.236 176.938 124.383 177.1396 ;
		RECT 0.2105 177.3451 124.236 177.4682 ;
		RECT 124.236 177.3451 124.383 177.4682 ;
		RECT 0.2105 177.578 124.236 177.7796 ;
		RECT 124.236 177.578 124.383 177.7796 ;
		RECT 0.2105 177.9851 124.236 178.1082 ;
		RECT 124.236 177.9851 124.383 178.1082 ;
		RECT 0.2105 178.218 124.236 178.4196 ;
		RECT 124.236 178.218 124.383 178.4196 ;
		RECT 0.2105 178.6251 124.236 178.7482 ;
		RECT 124.236 178.6251 124.383 178.7482 ;
		RECT 0.2105 178.858 124.236 179.0596 ;
		RECT 124.236 178.858 124.383 179.0596 ;
		RECT 0.2105 179.2651 124.236 179.3882 ;
		RECT 124.236 179.2651 124.383 179.3882 ;
		RECT 0.2105 179.498 124.236 179.6996 ;
		RECT 124.236 179.498 124.383 179.6996 ;
		RECT 0.2105 179.9051 124.236 180.0282 ;
		RECT 124.236 179.9051 124.383 180.0282 ;
		RECT 0.2105 180.138 124.236 180.3396 ;
		RECT 124.236 180.138 124.383 180.3396 ;
		RECT 0.2105 180.5451 124.236 180.6682 ;
		RECT 124.236 180.5451 124.383 180.6682 ;
		RECT 0.2105 180.778 124.236 180.9796 ;
		RECT 124.236 180.778 124.383 180.9796 ;
		RECT 0.2105 181.1851 124.236 181.3082 ;
		RECT 124.236 181.1851 124.383 181.3082 ;
		RECT 0.2105 181.418 124.236 181.6196 ;
		RECT 124.236 181.418 124.383 181.6196 ;
		RECT 0.2105 181.8251 124.236 181.9482 ;
		RECT 124.236 181.8251 124.383 181.9482 ;
		RECT 0.2105 182.058 124.236 182.2596 ;
		RECT 124.236 182.058 124.383 182.2596 ;
		RECT 0.2105 182.4651 124.236 182.5882 ;
		RECT 124.236 182.4651 124.383 182.5882 ;
		RECT 0.2105 182.698 124.236 182.8996 ;
		RECT 124.236 182.698 124.383 182.8996 ;
		RECT 0.2105 183.1051 124.236 183.2282 ;
		RECT 124.236 183.1051 124.383 183.2282 ;
		RECT 0.2105 183.338 124.236 183.5396 ;
		RECT 124.236 183.338 124.383 183.5396 ;
		RECT 0.2105 183.7451 124.236 183.8682 ;
		RECT 124.236 183.7451 124.383 183.8682 ;
		RECT 0.2105 183.978 124.236 184.1796 ;
		RECT 124.236 183.978 124.383 184.1796 ;
		RECT 0.2105 184.3851 124.236 184.5082 ;
		RECT 124.236 184.3851 124.383 184.5082 ;
		RECT 0.2105 184.618 124.236 184.8196 ;
		RECT 124.236 184.618 124.383 184.8196 ;
		RECT 0.2105 185.0251 124.236 185.1482 ;
		RECT 124.236 185.0251 124.383 185.1482 ;
		RECT 0.2105 185.258 124.236 185.4596 ;
		RECT 124.236 185.258 124.383 185.4596 ;
		RECT 0.2105 185.6651 124.236 185.7882 ;
		RECT 124.236 185.6651 124.383 185.7882 ;
		RECT 0.2105 185.898 124.236 186.0996 ;
		RECT 124.236 185.898 124.383 186.0996 ;
		RECT 0.2105 186.3051 124.236 186.4282 ;
		RECT 124.236 186.3051 124.383 186.4282 ;
		RECT 0.2105 186.538 124.236 186.7396 ;
		RECT 124.236 186.538 124.383 186.7396 ;
		RECT 0.2105 186.9451 124.236 187.0682 ;
		RECT 124.236 186.9451 124.383 187.0682 ;
		RECT 0.2105 187.178 124.236 187.3796 ;
		RECT 124.236 187.178 124.383 187.3796 ;
		RECT 0.2105 187.5851 124.236 187.7082 ;
		RECT 124.236 187.5851 124.383 187.7082 ;
		RECT 0.2105 187.818 124.236 188.0196 ;
		RECT 124.236 187.818 124.383 188.0196 ;
		RECT 0.2105 188.2251 124.236 188.3482 ;
		RECT 124.236 188.2251 124.383 188.3482 ;
		RECT 0.2105 188.458 124.236 188.6596 ;
		RECT 124.236 188.458 124.383 188.6596 ;
		RECT 0.2105 188.8651 124.236 188.9882 ;
		RECT 124.236 188.8651 124.383 188.9882 ;
		RECT 0.2105 189.098 124.236 189.2996 ;
		RECT 124.236 189.098 124.383 189.2996 ;
		RECT 0.2105 189.5051 124.236 189.6282 ;
		RECT 124.236 189.5051 124.383 189.6282 ;
		RECT 0.2105 189.738 124.236 189.9396 ;
		RECT 124.236 189.738 124.383 189.9396 ;
		RECT 0.2105 190.1451 124.236 190.2682 ;
		RECT 124.236 190.1451 124.383 190.2682 ;
		RECT 0.2105 190.378 124.236 190.5796 ;
		RECT 124.236 190.378 124.383 190.5796 ;
		RECT 0.2105 190.7851 124.236 190.9082 ;
		RECT 124.236 190.7851 124.383 190.9082 ;
		RECT 0.2105 191.018 124.236 191.2196 ;
		RECT 124.236 191.018 124.383 191.2196 ;
		RECT 0.2105 191.4251 124.236 191.5482 ;
		RECT 124.236 191.4251 124.383 191.5482 ;
		RECT 0.2105 191.658 124.236 191.8596 ;
		RECT 124.236 191.658 124.383 191.8596 ;
		RECT 0.2105 192.0651 124.236 192.1882 ;
		RECT 124.236 192.0651 124.383 192.1882 ;
		RECT 0.2105 192.298 124.236 192.4996 ;
		RECT 124.236 192.298 124.383 192.4996 ;
		RECT 0.2105 192.7051 124.236 192.8282 ;
		RECT 124.236 192.7051 124.383 192.8282 ;
		RECT 0.2105 192.938 124.236 193.1396 ;
		RECT 124.236 192.938 124.383 193.1396 ;
		RECT 0.2105 193.3451 124.236 193.4682 ;
		RECT 124.236 193.3451 124.383 193.4682 ;
		RECT 0.2105 193.578 124.236 193.7796 ;
		RECT 124.236 193.578 124.383 193.7796 ;
		RECT 0.2105 193.9851 124.236 194.1082 ;
		RECT 124.236 193.9851 124.383 194.1082 ;
		RECT 0.2105 194.218 124.236 194.4196 ;
		RECT 124.236 194.218 124.383 194.4196 ;
		RECT 0.2105 194.6251 124.236 194.7482 ;
		RECT 124.236 194.6251 124.383 194.7482 ;
		RECT 0.2105 194.858 124.236 195.0596 ;
		RECT 124.236 194.858 124.383 195.0596 ;
		RECT 0.2105 195.2651 124.236 195.3882 ;
		RECT 124.236 195.2651 124.383 195.3882 ;
		RECT 0.2105 195.498 124.236 195.6996 ;
		RECT 124.236 195.498 124.383 195.6996 ;
		RECT 0.2105 195.9051 124.236 196.0282 ;
		RECT 124.236 195.9051 124.383 196.0282 ;
		RECT 0.2105 196.138 124.236 196.3396 ;
		RECT 124.236 196.138 124.383 196.3396 ;
		RECT 0.2105 196.5451 124.236 196.6682 ;
		RECT 124.236 196.5451 124.383 196.6682 ;
		RECT 0.2105 196.778 124.236 196.9796 ;
		RECT 124.236 196.778 124.383 196.9796 ;
		RECT 0.2105 197.1851 124.236 197.3082 ;
		RECT 124.236 197.1851 124.383 197.3082 ;
		RECT 0.2105 197.418 124.236 197.6196 ;
		RECT 124.236 197.418 124.383 197.6196 ;
		RECT 0.2105 197.8251 124.236 197.9482 ;
		RECT 124.236 197.8251 124.383 197.9482 ;
		RECT 0.2105 198.058 124.236 198.2596 ;
		RECT 124.236 198.058 124.383 198.2596 ;
		RECT 0.2105 198.4651 124.236 198.5882 ;
		RECT 124.236 198.4651 124.383 198.5882 ;
		RECT 0.2105 198.698 124.236 198.8996 ;
		RECT 124.236 198.698 124.383 198.8996 ;
		RECT 0.2105 199.1051 124.236 199.2282 ;
		RECT 124.236 199.1051 124.383 199.2282 ;
		RECT 0.2105 199.338 124.236 199.5396 ;
		RECT 124.236 199.338 124.383 199.5396 ;
		RECT 0.2105 199.7451 124.236 199.8682 ;
		RECT 124.236 199.7451 124.383 199.8682 ;
		RECT 0.2105 199.978 124.236 200.1796 ;
		RECT 124.236 199.978 124.383 200.1796 ;
		 LAYER M4 ;
		RECT 0.2105 0 124.236 0.022 ;
		RECT 124.236 0 124.383 0.022 ;
		RECT 0.2105 47.1043 124.236 47.1294 ;
		RECT 124.236 47.1043 124.383 47.1294 ;
		RECT 0.2105 53.3506 124.236 53.3757 ;
		RECT 124.236 53.3506 124.383 53.3757 ;
		RECT 0.2105 147.1325 124.236 147.1576 ;
		RECT 124.236 147.1325 124.383 147.1576 ;
		RECT 0.2105 153.3788 124.236 153.4039 ;
		RECT 124.236 153.3788 124.383 153.4039 ;
		RECT 0.2105 200.4863 124.236 200.5082 ;
		RECT 124.236 200.4863 124.383 200.5082 ;
		 LAYER M4 SPACING 0.018 ;
		RECT 0.2105 0 124.236 0.022 ;
		RECT 124.236 0 124.383 0.022 ;
		RECT 0.2105 47.1043 124.236 47.1294 ;
		RECT 124.236 47.1043 124.383 47.1294 ;
		RECT 0.2105 53.3506 124.236 53.3757 ;
		RECT 124.236 53.3506 124.383 53.3757 ;
		RECT 0.2105 147.1325 124.236 147.1576 ;
		RECT 124.236 147.1325 124.383 147.1576 ;
		RECT 0.2105 153.3788 124.236 153.4039 ;
		RECT 124.236 153.3788 124.383 153.4039 ;
		RECT 0.2105 200.4863 124.236 200.5082 ;
		RECT 124.236 200.4863 124.383 200.5082 ;
		 LAYER V1 SPACING 0 ;
		RECT 0 0 124.383 200.5082 ;
		 LAYER V2 SPACING 0 ;
		RECT 0.1097 0 124.383 200.5082 ;
		RECT 0 0 0.1097 0.0627 ;
		RECT 0 0.1631 0.1097 2.2463 ;
		RECT 0 2.3467 0.1097 2.3718 ;
		RECT 0 2.4722 0.1097 2.5224 ;
		RECT 0 2.6227 0.1097 2.6478 ;
		RECT 0 2.7482 0.1097 4.8063 ;
		RECT 0 4.9067 0.1097 4.9318 ;
		RECT 0 5.0322 0.1097 5.0824 ;
		RECT 0 5.1827 0.1097 5.2078 ;
		RECT 0 5.3082 0.1097 7.3663 ;
		RECT 0 7.4667 0.1097 7.4918 ;
		RECT 0 7.5922 0.1097 7.6424 ;
		RECT 0 7.7427 0.1097 7.7678 ;
		RECT 0 7.8682 0.1097 9.9263 ;
		RECT 0 10.0267 0.1097 10.0518 ;
		RECT 0 10.1522 0.1097 10.2024 ;
		RECT 0 10.3027 0.1097 10.3278 ;
		RECT 0 10.4282 0.1097 12.4863 ;
		RECT 0 12.5867 0.1097 12.6118 ;
		RECT 0 12.7122 0.1097 12.7624 ;
		RECT 0 12.8627 0.1097 12.8878 ;
		RECT 0 12.9882 0.1097 15.0463 ;
		RECT 0 15.1467 0.1097 15.1718 ;
		RECT 0 15.2722 0.1097 15.3224 ;
		RECT 0 15.4227 0.1097 15.4478 ;
		RECT 0 15.5482 0.1097 17.6063 ;
		RECT 0 17.7067 0.1097 17.7318 ;
		RECT 0 17.8322 0.1097 17.8824 ;
		RECT 0 17.9827 0.1097 18.0078 ;
		RECT 0 18.1082 0.1097 20.1663 ;
		RECT 0 20.2667 0.1097 20.2918 ;
		RECT 0 20.3922 0.1097 20.4424 ;
		RECT 0 20.5427 0.1097 20.5678 ;
		RECT 0 20.6682 0.1097 22.7263 ;
		RECT 0 22.8267 0.1097 22.8518 ;
		RECT 0 22.9522 0.1097 23.0024 ;
		RECT 0 23.1027 0.1097 23.1278 ;
		RECT 0 23.2282 0.1097 25.2863 ;
		RECT 0 25.3867 0.1097 25.4118 ;
		RECT 0 25.5122 0.1097 25.5624 ;
		RECT 0 25.6627 0.1097 25.6878 ;
		RECT 0 25.7882 0.1097 27.8463 ;
		RECT 0 27.9467 0.1097 27.9718 ;
		RECT 0 28.0722 0.1097 28.1224 ;
		RECT 0 28.2227 0.1097 28.2478 ;
		RECT 0 28.3482 0.1097 30.4063 ;
		RECT 0 30.5067 0.1097 30.5318 ;
		RECT 0 30.6322 0.1097 30.6824 ;
		RECT 0 30.7827 0.1097 30.8078 ;
		RECT 0 30.9082 0.1097 32.9663 ;
		RECT 0 33.0667 0.1097 33.0918 ;
		RECT 0 33.1922 0.1097 33.2424 ;
		RECT 0 33.3427 0.1097 33.3678 ;
		RECT 0 33.4682 0.1097 35.5263 ;
		RECT 0 35.6267 0.1097 35.6518 ;
		RECT 0 35.7522 0.1097 35.8024 ;
		RECT 0 35.9027 0.1097 35.9278 ;
		RECT 0 36.0282 0.1097 38.0863 ;
		RECT 0 38.1867 0.1097 38.2118 ;
		RECT 0 38.3122 0.1097 38.3624 ;
		RECT 0 38.4627 0.1097 38.4878 ;
		RECT 0 38.5882 0.1097 40.6463 ;
		RECT 0 40.7467 0.1097 40.7718 ;
		RECT 0 40.8722 0.1097 40.9224 ;
		RECT 0 41.0227 0.1097 41.0478 ;
		RECT 0 41.1482 0.1097 43.2063 ;
		RECT 0 43.3067 0.1097 43.3318 ;
		RECT 0 43.4322 0.1097 43.4824 ;
		RECT 0 43.5827 0.1097 43.6078 ;
		RECT 0 43.7082 0.1097 45.7663 ;
		RECT 0 45.8667 0.1097 45.8918 ;
		RECT 0 45.9922 0.1097 46.0424 ;
		RECT 0 46.1427 0.1097 46.1678 ;
		RECT 0 46.2682 0.1097 56.0251 ;
		RECT 0 56.1255 0.1097 56.1506 ;
		RECT 0 56.251 0.1097 56.3012 ;
		RECT 0 56.4016 0.1097 56.4267 ;
		RECT 0 56.5271 0.1097 58.5851 ;
		RECT 0 58.6855 0.1097 58.7106 ;
		RECT 0 58.811 0.1097 58.8612 ;
		RECT 0 58.9616 0.1097 58.9867 ;
		RECT 0 59.0871 0.1097 61.1451 ;
		RECT 0 61.2455 0.1097 61.2706 ;
		RECT 0 61.371 0.1097 61.4212 ;
		RECT 0 61.5216 0.1097 61.5467 ;
		RECT 0 61.6471 0.1097 63.7051 ;
		RECT 0 63.8055 0.1097 63.8306 ;
		RECT 0 63.931 0.1097 63.9812 ;
		RECT 0 64.0816 0.1097 64.1067 ;
		RECT 0 64.2071 0.1097 66.2651 ;
		RECT 0 66.3655 0.1097 66.3906 ;
		RECT 0 66.491 0.1097 66.5412 ;
		RECT 0 66.6416 0.1097 66.6667 ;
		RECT 0 66.7671 0.1097 68.8251 ;
		RECT 0 68.9255 0.1097 68.9506 ;
		RECT 0 69.051 0.1097 69.1012 ;
		RECT 0 69.2016 0.1097 69.2267 ;
		RECT 0 69.3271 0.1097 71.3851 ;
		RECT 0 71.4855 0.1097 71.5106 ;
		RECT 0 71.611 0.1097 71.6612 ;
		RECT 0 71.7616 0.1097 71.7867 ;
		RECT 0 71.8871 0.1097 73.9451 ;
		RECT 0 74.0455 0.1097 74.0706 ;
		RECT 0 74.171 0.1097 74.2212 ;
		RECT 0 74.3216 0.1097 74.3467 ;
		RECT 0 74.4471 0.1097 76.5051 ;
		RECT 0 76.6055 0.1097 76.6306 ;
		RECT 0 76.731 0.1097 76.7812 ;
		RECT 0 76.8816 0.1097 76.9067 ;
		RECT 0 77.0071 0.1097 79.0651 ;
		RECT 0 79.1655 0.1097 79.1906 ;
		RECT 0 79.291 0.1097 79.3412 ;
		RECT 0 79.4416 0.1097 79.4667 ;
		RECT 0 79.5671 0.1097 81.6251 ;
		RECT 0 81.7255 0.1097 81.7506 ;
		RECT 0 81.851 0.1097 81.9012 ;
		RECT 0 82.0016 0.1097 82.0267 ;
		RECT 0 82.1271 0.1097 84.1851 ;
		RECT 0 84.2855 0.1097 84.3106 ;
		RECT 0 84.411 0.1097 84.4612 ;
		RECT 0 84.5616 0.1097 84.5867 ;
		RECT 0 84.6871 0.1097 86.7451 ;
		RECT 0 86.8455 0.1097 86.8706 ;
		RECT 0 86.971 0.1097 87.0212 ;
		RECT 0 87.1216 0.1097 87.1467 ;
		RECT 0 87.2471 0.1097 87.3725 ;
		RECT 0 87.4729 0.1097 88.778 ;
		RECT 0 88.8784 0.1097 89.2549 ;
		RECT 0 89.3553 0.1097 89.4055 ;
		RECT 0 89.5059 0.1097 89.5561 ;
		RECT 0 89.6565 0.1097 89.7067 ;
		RECT 0 89.8071 0.1097 89.8824 ;
		RECT 0 89.9827 0.1097 90.0329 ;
		RECT 0 90.1333 0.1097 90.1835 ;
		RECT 0 90.2839 0.1097 90.6604 ;
		RECT 0 90.7608 0.1097 90.811 ;
		RECT 0 90.9114 0.1097 91.1373 ;
		RECT 0 91.2376 0.1097 91.2878 ;
		RECT 0 91.3882 0.1097 91.589 ;
		RECT 0 91.6894 0.1097 91.7647 ;
		RECT 0 91.8651 0.1097 91.8902 ;
		RECT 0 91.9906 0.1097 92.0659 ;
		RECT 0 92.1663 0.1097 92.2165 ;
		RECT 0 92.3169 0.1097 92.3922 ;
		RECT 0 92.4925 0.1097 92.5427 ;
		RECT 0 92.6431 0.1097 93.2957 ;
		RECT 0 93.3961 0.1097 93.4463 ;
		RECT 0 93.5467 0.1097 93.6973 ;
		RECT 0 93.7976 0.1097 93.8478 ;
		RECT 0 93.9482 0.1097 94.2745 ;
		RECT 0 94.3749 0.1097 94.4251 ;
		RECT 0 94.5255 0.1097 94.5757 ;
		RECT 0 94.6761 0.1097 94.7263 ;
		RECT 0 94.8267 0.1097 94.902 ;
		RECT 0 95.0024 0.1097 95.0525 ;
		RECT 0 95.1529 0.1097 95.2031 ;
		RECT 0 95.3035 0.1097 95.8055 ;
		RECT 0 95.9059 0.1097 95.9561 ;
		RECT 0 96.0565 0.1097 96.0816 ;
		RECT 0 96.182 0.1097 96.3075 ;
		RECT 0 96.4078 0.1097 96.458 ;
		RECT 0 96.5584 0.1097 96.9098 ;
		RECT 0 97.0102 0.1097 97.0604 ;
		RECT 0 97.1608 0.1097 97.211 ;
		RECT 0 97.3114 0.1097 97.3867 ;
		RECT 0 97.4871 0.1097 98.8675 ;
		RECT 0 98.9678 0.1097 99.018 ;
		RECT 0 99.1184 0.1097 99.1686 ;
		RECT 0 99.269 0.1097 99.3192 ;
		RECT 0 99.4196 0.1097 99.4698 ;
		RECT 0 99.5702 0.1097 99.6204 ;
		RECT 0 99.7208 0.1097 99.771 ;
		RECT 0 99.8714 0.1097 99.9467 ;
		RECT 0 100.0471 0.1097 100.4612 ;
		RECT 0 100.5616 0.1097 100.6118 ;
		RECT 0 100.7122 0.1097 100.7624 ;
		RECT 0 100.8627 0.1097 100.9129 ;
		RECT 0 101.0133 0.1097 101.0635 ;
		RECT 0 101.1639 0.1097 101.2894 ;
		RECT 0 101.3898 0.1097 101.5153 ;
		RECT 0 101.6157 0.1097 102.4941 ;
		RECT 0 102.5945 0.1097 102.8706 ;
		RECT 0 102.971 0.1097 103.0212 ;
		RECT 0 103.1216 0.1097 103.1718 ;
		RECT 0 103.2722 0.1097 103.3224 ;
		RECT 0 103.4227 0.1097 103.4729 ;
		RECT 0 103.5733 0.1097 103.8494 ;
		RECT 0 103.9498 0.1097 104.0753 ;
		RECT 0 104.1757 0.1097 105.28 ;
		RECT 0 105.3804 0.1097 105.4306 ;
		RECT 0 105.531 0.1097 105.5812 ;
		RECT 0 105.6816 0.1097 105.7318 ;
		RECT 0 105.8322 0.1097 105.8824 ;
		RECT 0 105.9827 0.1097 106.0329 ;
		RECT 0 106.1333 0.1097 106.6353 ;
		RECT 0 106.7357 0.1097 107.0118 ;
		RECT 0 107.1122 0.1097 107.9906 ;
		RECT 0 108.091 0.1097 108.2165 ;
		RECT 0 108.3169 0.1097 108.4424 ;
		RECT 0 108.5427 0.1097 108.5929 ;
		RECT 0 108.6933 0.1097 109.7224 ;
		RECT 0 109.8227 0.1097 110.4 ;
		RECT 0 110.5004 0.1097 110.6259 ;
		RECT 0 110.7263 0.1097 111.0024 ;
		RECT 0 111.1027 0.1097 111.1529 ;
		RECT 0 111.2533 0.1097 111.5294 ;
		RECT 0 111.6298 0.1097 112.3576 ;
		RECT 0 112.458 0.1097 113.0353 ;
		RECT 0 113.1357 0.1097 113.2612 ;
		RECT 0 113.3616 0.1097 113.3867 ;
		RECT 0 113.4871 0.1097 113.5373 ;
		RECT 0 113.6376 0.1097 113.6627 ;
		RECT 0 113.7631 0.1097 115.8212 ;
		RECT 0 115.9216 0.1097 115.9467 ;
		RECT 0 116.0471 0.1097 116.0973 ;
		RECT 0 116.1976 0.1097 116.2227 ;
		RECT 0 116.3231 0.1097 118.3812 ;
		RECT 0 118.4816 0.1097 118.5067 ;
		RECT 0 118.6071 0.1097 118.6573 ;
		RECT 0 118.7576 0.1097 118.7827 ;
		RECT 0 118.8831 0.1097 120.9412 ;
		RECT 0 121.0416 0.1097 121.0667 ;
		RECT 0 121.1671 0.1097 121.2173 ;
		RECT 0 121.3176 0.1097 121.3427 ;
		RECT 0 121.4431 0.1097 123.5012 ;
		RECT 0 123.6016 0.1097 123.6267 ;
		RECT 0 123.7271 0.1097 123.7773 ;
		RECT 0 123.8776 0.1097 123.9027 ;
		RECT 0 124.0031 0.1097 126.0612 ;
		RECT 0 126.1616 0.1097 126.1867 ;
		RECT 0 126.2871 0.1097 126.3373 ;
		RECT 0 126.4376 0.1097 126.4627 ;
		RECT 0 126.5631 0.1097 128.6212 ;
		RECT 0 128.7216 0.1097 128.7467 ;
		RECT 0 128.8471 0.1097 128.8973 ;
		RECT 0 128.9976 0.1097 129.0227 ;
		RECT 0 129.1231 0.1097 131.1812 ;
		RECT 0 131.2816 0.1097 131.3067 ;
		RECT 0 131.4071 0.1097 131.4573 ;
		RECT 0 131.5576 0.1097 131.5827 ;
		RECT 0 131.6831 0.1097 133.7412 ;
		RECT 0 133.8416 0.1097 133.8667 ;
		RECT 0 133.9671 0.1097 134.0173 ;
		RECT 0 134.1176 0.1097 134.1427 ;
		RECT 0 134.2431 0.1097 136.3012 ;
		RECT 0 136.4016 0.1097 136.4267 ;
		RECT 0 136.5271 0.1097 136.5773 ;
		RECT 0 136.6776 0.1097 136.7027 ;
		RECT 0 136.8031 0.1097 138.8612 ;
		RECT 0 138.9616 0.1097 138.9867 ;
		RECT 0 139.0871 0.1097 139.1373 ;
		RECT 0 139.2376 0.1097 139.2627 ;
		RECT 0 139.3631 0.1097 141.4212 ;
		RECT 0 141.5216 0.1097 141.5467 ;
		RECT 0 141.6471 0.1097 141.6973 ;
		RECT 0 141.7976 0.1097 141.8227 ;
		RECT 0 141.9231 0.1097 143.9812 ;
		RECT 0 144.0816 0.1097 144.1067 ;
		RECT 0 144.2071 0.1097 144.2573 ;
		RECT 0 144.3576 0.1097 144.3827 ;
		RECT 0 144.4831 0.1097 154.24 ;
		RECT 0 154.3404 0.1097 154.3655 ;
		RECT 0 154.4659 0.1097 154.5161 ;
		RECT 0 154.6165 0.1097 154.6416 ;
		RECT 0 154.742 0.1097 156.8 ;
		RECT 0 156.9004 0.1097 156.9255 ;
		RECT 0 157.0259 0.1097 157.0761 ;
		RECT 0 157.1765 0.1097 157.2016 ;
		RECT 0 157.302 0.1097 159.36 ;
		RECT 0 159.4604 0.1097 159.4855 ;
		RECT 0 159.5859 0.1097 159.6361 ;
		RECT 0 159.7365 0.1097 159.7616 ;
		RECT 0 159.862 0.1097 161.92 ;
		RECT 0 162.0204 0.1097 162.0455 ;
		RECT 0 162.1459 0.1097 162.1961 ;
		RECT 0 162.2965 0.1097 162.3216 ;
		RECT 0 162.422 0.1097 164.48 ;
		RECT 0 164.5804 0.1097 164.6055 ;
		RECT 0 164.7059 0.1097 164.7561 ;
		RECT 0 164.8565 0.1097 164.8816 ;
		RECT 0 164.982 0.1097 167.04 ;
		RECT 0 167.1404 0.1097 167.1655 ;
		RECT 0 167.2659 0.1097 167.3161 ;
		RECT 0 167.4165 0.1097 167.4416 ;
		RECT 0 167.542 0.1097 169.6 ;
		RECT 0 169.7004 0.1097 169.7255 ;
		RECT 0 169.8259 0.1097 169.8761 ;
		RECT 0 169.9765 0.1097 170.0016 ;
		RECT 0 170.102 0.1097 172.16 ;
		RECT 0 172.2604 0.1097 172.2855 ;
		RECT 0 172.3859 0.1097 172.4361 ;
		RECT 0 172.5365 0.1097 172.5616 ;
		RECT 0 172.662 0.1097 174.72 ;
		RECT 0 174.8204 0.1097 174.8455 ;
		RECT 0 174.9459 0.1097 174.9961 ;
		RECT 0 175.0965 0.1097 175.1216 ;
		RECT 0 175.222 0.1097 177.28 ;
		RECT 0 177.3804 0.1097 177.4055 ;
		RECT 0 177.5059 0.1097 177.5561 ;
		RECT 0 177.6565 0.1097 177.6816 ;
		RECT 0 177.782 0.1097 179.84 ;
		RECT 0 179.9404 0.1097 179.9655 ;
		RECT 0 180.0659 0.1097 180.1161 ;
		RECT 0 180.2165 0.1097 180.2416 ;
		RECT 0 180.342 0.1097 182.4 ;
		RECT 0 182.5004 0.1097 182.5255 ;
		RECT 0 182.6259 0.1097 182.6761 ;
		RECT 0 182.7765 0.1097 182.8016 ;
		RECT 0 182.902 0.1097 184.96 ;
		RECT 0 185.0604 0.1097 185.0855 ;
		RECT 0 185.1859 0.1097 185.2361 ;
		RECT 0 185.3365 0.1097 185.3616 ;
		RECT 0 185.462 0.1097 187.52 ;
		RECT 0 187.6204 0.1097 187.6455 ;
		RECT 0 187.7459 0.1097 187.7961 ;
		RECT 0 187.8965 0.1097 187.9216 ;
		RECT 0 188.022 0.1097 190.08 ;
		RECT 0 190.1804 0.1097 190.2055 ;
		RECT 0 190.3059 0.1097 190.3561 ;
		RECT 0 190.4565 0.1097 190.4816 ;
		RECT 0 190.582 0.1097 192.64 ;
		RECT 0 192.7404 0.1097 192.7655 ;
		RECT 0 192.8659 0.1097 192.9161 ;
		RECT 0 193.0165 0.1097 193.0416 ;
		RECT 0 193.142 0.1097 195.2 ;
		RECT 0 195.3004 0.1097 195.3255 ;
		RECT 0 195.4259 0.1097 195.4761 ;
		RECT 0 195.5765 0.1097 195.6016 ;
		RECT 0 195.702 0.1097 197.76 ;
		RECT 0 197.8604 0.1097 197.8855 ;
		RECT 0 197.9859 0.1097 198.0361 ;
		RECT 0 198.1365 0.1097 198.1616 ;
		RECT 0 198.262 0.1097 200.3451 ;
		RECT 0 200.4455 0.1097 200.5082 ;
		 LAYER V2 ;
		RECT 0.0481 2.3718 0.1097 2.5224 ;
		RECT 0.0481 2.5224 0.1097 2.6478 ;
		RECT 0.0481 4.9318 0.1097 5.0824 ;
		RECT 0.0481 5.0824 0.1097 5.2078 ;
		RECT 0.0481 7.4918 0.1097 7.6424 ;
		RECT 0.0481 7.6424 0.1097 7.7678 ;
		RECT 0.0481 10.0518 0.1097 10.2024 ;
		RECT 0.0481 10.2024 0.1097 10.3278 ;
		RECT 0.0481 12.6118 0.1097 12.7624 ;
		RECT 0.0481 12.7624 0.1097 12.8878 ;
		RECT 0.0481 15.1718 0.1097 15.3224 ;
		RECT 0.0481 15.3224 0.1097 15.4478 ;
		RECT 0.0481 17.7318 0.1097 17.8824 ;
		RECT 0.0481 17.8824 0.1097 18.0078 ;
		RECT 0.0481 20.2918 0.1097 20.4424 ;
		RECT 0.0481 20.4424 0.1097 20.5678 ;
		RECT 0.0481 22.8518 0.1097 23.0024 ;
		RECT 0.0481 23.0024 0.1097 23.1278 ;
		RECT 0.0481 25.4118 0.1097 25.5624 ;
		RECT 0.0481 25.5624 0.1097 25.6878 ;
		RECT 0.0481 27.9718 0.1097 28.1224 ;
		RECT 0.0481 28.1224 0.1097 28.2478 ;
		RECT 0.0481 30.5318 0.1097 30.6824 ;
		RECT 0.0481 30.6824 0.1097 30.8078 ;
		RECT 0.0481 33.0918 0.1097 33.2424 ;
		RECT 0.0481 33.2424 0.1097 33.3678 ;
		RECT 0.0481 35.6518 0.1097 35.8024 ;
		RECT 0.0481 35.8024 0.1097 35.9278 ;
		RECT 0.0481 38.2118 0.1097 38.3624 ;
		RECT 0.0481 38.3624 0.1097 38.4878 ;
		RECT 0.0481 40.7718 0.1097 40.9224 ;
		RECT 0.0481 40.9224 0.1097 41.0478 ;
		RECT 0.0481 43.3318 0.1097 43.4824 ;
		RECT 0.0481 43.4824 0.1097 43.6078 ;
		RECT 0.0481 45.8918 0.1097 46.0424 ;
		RECT 0.0481 46.0424 0.1097 46.1678 ;
		RECT 0.0481 56.1506 0.1097 56.3012 ;
		RECT 0.0481 56.3012 0.1097 56.4267 ;
		RECT 0.0481 58.7106 0.1097 58.8612 ;
		RECT 0.0481 58.8612 0.1097 58.9867 ;
		RECT 0.0481 61.2706 0.1097 61.4212 ;
		RECT 0.0481 61.4212 0.1097 61.5467 ;
		RECT 0.0481 63.8306 0.1097 63.9812 ;
		RECT 0.0481 63.9812 0.1097 64.1067 ;
		RECT 0.0481 66.3906 0.1097 66.5412 ;
		RECT 0.0481 66.5412 0.1097 66.6667 ;
		RECT 0.0481 68.9506 0.1097 69.1012 ;
		RECT 0.0481 69.1012 0.1097 69.2267 ;
		RECT 0.0481 71.5106 0.1097 71.6612 ;
		RECT 0.0481 71.6612 0.1097 71.7867 ;
		RECT 0.0481 74.0706 0.1097 74.2212 ;
		RECT 0.0481 74.2212 0.1097 74.3467 ;
		RECT 0.0481 76.6306 0.1097 76.7812 ;
		RECT 0.0481 76.7812 0.1097 76.9067 ;
		RECT 0.0481 79.1906 0.1097 79.3412 ;
		RECT 0.0481 79.3412 0.1097 79.4667 ;
		RECT 0.0481 81.7506 0.1097 81.9012 ;
		RECT 0.0481 81.9012 0.1097 82.0267 ;
		RECT 0.0481 84.3106 0.1097 84.4612 ;
		RECT 0.0481 84.4612 0.1097 84.5867 ;
		RECT 0.0481 86.8706 0.1097 87.0212 ;
		RECT 0.0481 87.0212 0.1097 87.1467 ;
		RECT 0.0481 88.778 0.1097 89.2549 ;
		RECT 0.0481 89.5561 0.1097 89.7067 ;
		RECT 0.0481 90.1835 0.1097 90.6604 ;
		RECT 0.0481 90.6604 0.1097 90.811 ;
		RECT 0.0481 90.811 0.1097 91.1373 ;
		RECT 0.0481 91.1373 0.1097 91.2878 ;
		RECT 0.0481 91.2878 0.1097 91.589 ;
		RECT 0.0481 91.589 0.1097 91.7647 ;
		RECT 0.0481 91.7647 0.1097 91.8902 ;
		RECT 0.0481 92.0659 0.1097 92.2165 ;
		RECT 0.0481 92.5427 0.1097 93.2957 ;
		RECT 0.0481 93.2957 0.1097 93.4463 ;
		RECT 0.0481 93.4463 0.1097 93.6973 ;
		RECT 0.0481 93.6973 0.1097 93.8478 ;
		RECT 0.0481 93.8478 0.1097 94.2745 ;
		RECT 0.0481 94.2745 0.1097 94.4251 ;
		RECT 0.0481 95.2031 0.1097 95.8055 ;
		RECT 0.0481 95.8055 0.1097 95.9561 ;
		RECT 0.0481 95.9561 0.1097 96.0816 ;
		RECT 0.0481 96.0816 0.1097 96.3075 ;
		RECT 0.0481 96.458 0.1097 96.9098 ;
		RECT 0.0481 97.211 0.1097 97.3867 ;
		RECT 0.0481 99.018 0.1097 99.1686 ;
		RECT 0.0481 99.1686 0.1097 99.3192 ;
		RECT 0.0481 99.3192 0.1097 99.4698 ;
		RECT 0.0481 102.4941 0.1097 102.8706 ;
		RECT 0.0481 103.1718 0.1097 103.3224 ;
		RECT 0.0481 103.8494 0.1097 104.0753 ;
		RECT 0.0481 107.0118 0.1097 107.9906 ;
		RECT 0.0481 107.9906 0.1097 108.2165 ;
		RECT 0.0481 109.7224 0.1097 110.4 ;
		RECT 0.0481 110.4 0.1097 110.6259 ;
		RECT 0.0481 110.6259 0.1097 111.0024 ;
		RECT 0.0481 112.3576 0.1097 113.0353 ;
		RECT 0.0481 113.3867 0.1097 113.5373 ;
		RECT 0.0481 113.5373 0.1097 113.6627 ;
		RECT 0.0481 115.9467 0.1097 116.0973 ;
		RECT 0.0481 116.0973 0.1097 116.2227 ;
		RECT 0.0481 118.5067 0.1097 118.6573 ;
		RECT 0.0481 118.6573 0.1097 118.7827 ;
		RECT 0.0481 121.0667 0.1097 121.2173 ;
		RECT 0.0481 121.2173 0.1097 121.3427 ;
		RECT 0.0481 123.6267 0.1097 123.7773 ;
		RECT 0.0481 123.7773 0.1097 123.9027 ;
		RECT 0.0481 126.1867 0.1097 126.3373 ;
		RECT 0.0481 126.3373 0.1097 126.4627 ;
		RECT 0.0481 128.7467 0.1097 128.8973 ;
		RECT 0.0481 128.8973 0.1097 129.0227 ;
		RECT 0.0481 131.3067 0.1097 131.4573 ;
		RECT 0.0481 131.4573 0.1097 131.5827 ;
		RECT 0.0481 133.8667 0.1097 134.0173 ;
		RECT 0.0481 134.0173 0.1097 134.1427 ;
		RECT 0.0481 136.4267 0.1097 136.5773 ;
		RECT 0.0481 136.5773 0.1097 136.7027 ;
		RECT 0.0481 138.9867 0.1097 139.1373 ;
		RECT 0.0481 139.1373 0.1097 139.2627 ;
		RECT 0.0481 141.5467 0.1097 141.6973 ;
		RECT 0.0481 141.6973 0.1097 141.8227 ;
		RECT 0.0481 144.1067 0.1097 144.2573 ;
		RECT 0.0481 144.2573 0.1097 144.3827 ;
		RECT 0.0481 154.3655 0.1097 154.5161 ;
		RECT 0.0481 154.5161 0.1097 154.6416 ;
		RECT 0.0481 156.9255 0.1097 157.0761 ;
		RECT 0.0481 157.0761 0.1097 157.2016 ;
		RECT 0.0481 159.4855 0.1097 159.6361 ;
		RECT 0.0481 159.6361 0.1097 159.7616 ;
		RECT 0.0481 162.0455 0.1097 162.1961 ;
		RECT 0.0481 162.1961 0.1097 162.3216 ;
		RECT 0.0481 164.6055 0.1097 164.7561 ;
		RECT 0.0481 164.7561 0.1097 164.8816 ;
		RECT 0.0481 167.1655 0.1097 167.3161 ;
		RECT 0.0481 167.3161 0.1097 167.4416 ;
		RECT 0.0481 169.7255 0.1097 169.8761 ;
		RECT 0.0481 169.8761 0.1097 170.0016 ;
		RECT 0.0481 172.2855 0.1097 172.4361 ;
		RECT 0.0481 172.4361 0.1097 172.5616 ;
		RECT 0.0481 174.8455 0.1097 174.9961 ;
		RECT 0.0481 174.9961 0.1097 175.1216 ;
		RECT 0.0481 177.4055 0.1097 177.5561 ;
		RECT 0.0481 177.5561 0.1097 177.6816 ;
		RECT 0.0481 179.9655 0.1097 180.1161 ;
		RECT 0.0481 180.1161 0.1097 180.2416 ;
		RECT 0.0481 182.5255 0.1097 182.6761 ;
		RECT 0.0481 182.6761 0.1097 182.8016 ;
		RECT 0.0481 185.0855 0.1097 185.2361 ;
		RECT 0.0481 185.2361 0.1097 185.3616 ;
		RECT 0.0481 187.6455 0.1097 187.7961 ;
		RECT 0.0481 187.7961 0.1097 187.9216 ;
		RECT 0.0481 190.2055 0.1097 190.3561 ;
		RECT 0.0481 190.3561 0.1097 190.4816 ;
		RECT 0.0481 192.7655 0.1097 192.9161 ;
		RECT 0.0481 192.9161 0.1097 193.0416 ;
		RECT 0.0481 195.3255 0.1097 195.4761 ;
		RECT 0.0481 195.4761 0.1097 195.6016 ;
		RECT 0.0481 197.8855 0.1097 198.0361 ;
		RECT 0.0481 198.0361 0.1097 198.1616 ;
		RECT 0.021 46.6443 0.0359 46.6569 ;
		RECT 0.021 47.0961 0.0359 47.1086 ;
		RECT 0.021 47.1863 0.0359 47.1988 ;
		RECT 0.021 47.4976 0.0359 47.5102 ;
		RECT 0.021 48.0498 0.0359 48.0624 ;
		RECT 0.021 50.6349 0.0359 50.6475 ;
		RECT 0.021 50.9612 0.0359 50.9737 ;
		RECT 0.021 51.3627 0.0359 51.3753 ;
		RECT 0.021 52.442 0.0359 52.4545 ;
		RECT 0.021 52.7682 0.0359 52.7808 ;
		RECT 0.021 52.9439 0.0359 52.9565 ;
		RECT 0.021 53.3455 0.0359 53.358 ;
		RECT 0.021 91.0365 0.0359 91.049 ;
		RECT 0.0215 97.4616 0.0364 97.4741 ;
		RECT 0.021 97.5871 0.0359 97.5996 ;
		RECT 0.021 97.8882 0.0359 97.9008 ;
		RECT 0.0215 0.1376 0.0364 0.1502 ;
		RECT 0.021 153.8514 0.0359 153.8639 ;
		RECT 0.021 153.3996 0.0359 153.4122 ;
		RECT 0.021 153.3094 0.0359 153.322 ;
		RECT 0.021 152.998 0.0359 153.0106 ;
		RECT 0.021 152.4459 0.0359 152.4584 ;
		RECT 0.021 150.8898 0.0359 150.9024 ;
		RECT 0.021 149.8608 0.0359 149.8733 ;
		RECT 0.021 149.5345 0.0359 149.5471 ;
		RECT 0.021 149.1329 0.0359 149.1455 ;
		RECT 0.021 148.0537 0.0359 148.0663 ;
		RECT 0.021 147.7275 0.0359 147.74 ;
		RECT 0.021 147.5518 0.0359 147.5643 ;
		RECT 0.021 147.1502 0.0359 147.1627 ;
		RECT 0.021 112.671 0.0359 112.6835 ;
		RECT 0.021 112.282 0.0359 112.2945 ;
		RECT 0.0215 111.5424 0.0364 111.5549 ;
		RECT 0.021 109.5965 0.0359 109.609 ;
		RECT 0.0831 102.9463 0.098 102.9588 ;
		RECT 0.021 101.9918 0.0359 102.0043 ;
		RECT 0.021 101.8412 0.0359 101.8537 ;
		RECT 0.0215 101.0765 0.0364 101.089 ;
		RECT 0.0215 200.358 0.0364 200.3706 ;
		 LAYER V2 SPACING 0 ;
		RECT 0.0481 2.3718 0.1097 2.5224 ;
		RECT 0.0481 2.5224 0.1097 2.6478 ;
		RECT 0.0481 4.9318 0.1097 5.0824 ;
		RECT 0.0481 5.0824 0.1097 5.2078 ;
		RECT 0.0481 7.4918 0.1097 7.6424 ;
		RECT 0.0481 7.6424 0.1097 7.7678 ;
		RECT 0.0481 10.0518 0.1097 10.2024 ;
		RECT 0.0481 10.2024 0.1097 10.3278 ;
		RECT 0.0481 12.6118 0.1097 12.7624 ;
		RECT 0.0481 12.7624 0.1097 12.8878 ;
		RECT 0.0481 15.1718 0.1097 15.3224 ;
		RECT 0.0481 15.3224 0.1097 15.4478 ;
		RECT 0.0481 17.7318 0.1097 17.8824 ;
		RECT 0.0481 17.8824 0.1097 18.0078 ;
		RECT 0.0481 20.2918 0.1097 20.4424 ;
		RECT 0.0481 20.4424 0.1097 20.5678 ;
		RECT 0.0481 22.8518 0.1097 23.0024 ;
		RECT 0.0481 23.0024 0.1097 23.1278 ;
		RECT 0.0481 25.4118 0.1097 25.5624 ;
		RECT 0.0481 25.5624 0.1097 25.6878 ;
		RECT 0.0481 27.9718 0.1097 28.1224 ;
		RECT 0.0481 28.1224 0.1097 28.2478 ;
		RECT 0.0481 30.5318 0.1097 30.6824 ;
		RECT 0.0481 30.6824 0.1097 30.8078 ;
		RECT 0.0481 33.0918 0.1097 33.2424 ;
		RECT 0.0481 33.2424 0.1097 33.3678 ;
		RECT 0.0481 35.6518 0.1097 35.8024 ;
		RECT 0.0481 35.8024 0.1097 35.9278 ;
		RECT 0.0481 38.2118 0.1097 38.3624 ;
		RECT 0.0481 38.3624 0.1097 38.4878 ;
		RECT 0.0481 40.7718 0.1097 40.9224 ;
		RECT 0.0481 40.9224 0.1097 41.0478 ;
		RECT 0.0481 43.3318 0.1097 43.4824 ;
		RECT 0.0481 43.4824 0.1097 43.6078 ;
		RECT 0.0481 45.8918 0.1097 46.0424 ;
		RECT 0.0481 46.0424 0.1097 46.1678 ;
		RECT 0.0481 56.1506 0.1097 56.3012 ;
		RECT 0.0481 56.3012 0.1097 56.4267 ;
		RECT 0.0481 58.7106 0.1097 58.8612 ;
		RECT 0.0481 58.8612 0.1097 58.9867 ;
		RECT 0.0481 61.2706 0.1097 61.4212 ;
		RECT 0.0481 61.4212 0.1097 61.5467 ;
		RECT 0.0481 63.8306 0.1097 63.9812 ;
		RECT 0.0481 63.9812 0.1097 64.1067 ;
		RECT 0.0481 66.3906 0.1097 66.5412 ;
		RECT 0.0481 66.5412 0.1097 66.6667 ;
		RECT 0.0481 68.9506 0.1097 69.1012 ;
		RECT 0.0481 69.1012 0.1097 69.2267 ;
		RECT 0.0481 71.5106 0.1097 71.6612 ;
		RECT 0.0481 71.6612 0.1097 71.7867 ;
		RECT 0.0481 74.0706 0.1097 74.2212 ;
		RECT 0.0481 74.2212 0.1097 74.3467 ;
		RECT 0.0481 76.6306 0.1097 76.7812 ;
		RECT 0.0481 76.7812 0.1097 76.9067 ;
		RECT 0.0481 79.1906 0.1097 79.3412 ;
		RECT 0.0481 79.3412 0.1097 79.4667 ;
		RECT 0.0481 81.7506 0.1097 81.9012 ;
		RECT 0.0481 81.9012 0.1097 82.0267 ;
		RECT 0.0481 84.3106 0.1097 84.4612 ;
		RECT 0.0481 84.4612 0.1097 84.5867 ;
		RECT 0.0481 86.8706 0.1097 87.0212 ;
		RECT 0.0481 87.0212 0.1097 87.1467 ;
		RECT 0.0481 88.778 0.1097 89.2549 ;
		RECT 0.0481 89.5561 0.1097 89.7067 ;
		RECT 0.0481 90.1835 0.1097 90.6604 ;
		RECT 0.0481 90.6604 0.1097 90.811 ;
		RECT 0.0481 90.811 0.1097 91.1373 ;
		RECT 0.0481 91.1373 0.1097 91.2878 ;
		RECT 0.0481 91.2878 0.1097 91.589 ;
		RECT 0.0481 91.589 0.1097 91.7647 ;
		RECT 0.0481 91.7647 0.1097 91.8902 ;
		RECT 0.0481 92.0659 0.1097 92.2165 ;
		RECT 0.0481 92.5427 0.1097 93.2957 ;
		RECT 0.0481 93.2957 0.1097 93.4463 ;
		RECT 0.0481 93.4463 0.1097 93.6973 ;
		RECT 0.0481 93.6973 0.1097 93.8478 ;
		RECT 0.0481 93.8478 0.1097 94.2745 ;
		RECT 0.0481 94.2745 0.1097 94.4251 ;
		RECT 0.0481 95.2031 0.1097 95.8055 ;
		RECT 0.0481 95.8055 0.1097 95.9561 ;
		RECT 0.0481 95.9561 0.1097 96.0816 ;
		RECT 0.0481 96.0816 0.1097 96.3075 ;
		RECT 0.0481 96.458 0.1097 96.9098 ;
		RECT 0.0481 97.211 0.1097 97.3867 ;
		RECT 0.0481 99.018 0.1097 99.1686 ;
		RECT 0.0481 99.1686 0.1097 99.3192 ;
		RECT 0.0481 99.3192 0.1097 99.4698 ;
		RECT 0.0481 102.4941 0.1097 102.8706 ;
		RECT 0.0481 103.1718 0.1097 103.3224 ;
		RECT 0.0481 103.8494 0.1097 104.0753 ;
		RECT 0.0481 107.0118 0.1097 107.9906 ;
		RECT 0.0481 107.9906 0.1097 108.2165 ;
		RECT 0.0481 109.7224 0.1097 110.4 ;
		RECT 0.0481 110.4 0.1097 110.6259 ;
		RECT 0.0481 110.6259 0.1097 111.0024 ;
		RECT 0.0481 112.3576 0.1097 113.0353 ;
		RECT 0.0481 113.3867 0.1097 113.5373 ;
		RECT 0.0481 113.5373 0.1097 113.6627 ;
		RECT 0.0481 115.9467 0.1097 116.0973 ;
		RECT 0.0481 116.0973 0.1097 116.2227 ;
		RECT 0.0481 118.5067 0.1097 118.6573 ;
		RECT 0.0481 118.6573 0.1097 118.7827 ;
		RECT 0.0481 121.0667 0.1097 121.2173 ;
		RECT 0.0481 121.2173 0.1097 121.3427 ;
		RECT 0.0481 123.6267 0.1097 123.7773 ;
		RECT 0.0481 123.7773 0.1097 123.9027 ;
		RECT 0.0481 126.1867 0.1097 126.3373 ;
		RECT 0.0481 126.3373 0.1097 126.4627 ;
		RECT 0.0481 128.7467 0.1097 128.8973 ;
		RECT 0.0481 128.8973 0.1097 129.0227 ;
		RECT 0.0481 131.3067 0.1097 131.4573 ;
		RECT 0.0481 131.4573 0.1097 131.5827 ;
		RECT 0.0481 133.8667 0.1097 134.0173 ;
		RECT 0.0481 134.0173 0.1097 134.1427 ;
		RECT 0.0481 136.4267 0.1097 136.5773 ;
		RECT 0.0481 136.5773 0.1097 136.7027 ;
		RECT 0.0481 138.9867 0.1097 139.1373 ;
		RECT 0.0481 139.1373 0.1097 139.2627 ;
		RECT 0.0481 141.5467 0.1097 141.6973 ;
		RECT 0.0481 141.6973 0.1097 141.8227 ;
		RECT 0.0481 144.1067 0.1097 144.2573 ;
		RECT 0.0481 144.2573 0.1097 144.3827 ;
		RECT 0.0481 154.3655 0.1097 154.5161 ;
		RECT 0.0481 154.5161 0.1097 154.6416 ;
		RECT 0.0481 156.9255 0.1097 157.0761 ;
		RECT 0.0481 157.0761 0.1097 157.2016 ;
		RECT 0.0481 159.4855 0.1097 159.6361 ;
		RECT 0.0481 159.6361 0.1097 159.7616 ;
		RECT 0.0481 162.0455 0.1097 162.1961 ;
		RECT 0.0481 162.1961 0.1097 162.3216 ;
		RECT 0.0481 164.6055 0.1097 164.7561 ;
		RECT 0.0481 164.7561 0.1097 164.8816 ;
		RECT 0.0481 167.1655 0.1097 167.3161 ;
		RECT 0.0481 167.3161 0.1097 167.4416 ;
		RECT 0.0481 169.7255 0.1097 169.8761 ;
		RECT 0.0481 169.8761 0.1097 170.0016 ;
		RECT 0.0481 172.2855 0.1097 172.4361 ;
		RECT 0.0481 172.4361 0.1097 172.5616 ;
		RECT 0.0481 174.8455 0.1097 174.9961 ;
		RECT 0.0481 174.9961 0.1097 175.1216 ;
		RECT 0.0481 177.4055 0.1097 177.5561 ;
		RECT 0.0481 177.5561 0.1097 177.6816 ;
		RECT 0.0481 179.9655 0.1097 180.1161 ;
		RECT 0.0481 180.1161 0.1097 180.2416 ;
		RECT 0.0481 182.5255 0.1097 182.6761 ;
		RECT 0.0481 182.6761 0.1097 182.8016 ;
		RECT 0.0481 185.0855 0.1097 185.2361 ;
		RECT 0.0481 185.2361 0.1097 185.3616 ;
		RECT 0.0481 187.6455 0.1097 187.7961 ;
		RECT 0.0481 187.7961 0.1097 187.9216 ;
		RECT 0.0481 190.2055 0.1097 190.3561 ;
		RECT 0.0481 190.3561 0.1097 190.4816 ;
		RECT 0.0481 192.7655 0.1097 192.9161 ;
		RECT 0.0481 192.9161 0.1097 193.0416 ;
		RECT 0.0481 195.3255 0.1097 195.4761 ;
		RECT 0.0481 195.4761 0.1097 195.6016 ;
		RECT 0.0481 197.8855 0.1097 198.0361 ;
		RECT 0.0481 198.0361 0.1097 198.1616 ;
		RECT 0.021 46.6443 0.0359 46.6569 ;
		RECT 0.021 47.0961 0.0359 47.1086 ;
		RECT 0.021 47.1863 0.0359 47.1988 ;
		RECT 0.021 47.4976 0.0359 47.5102 ;
		RECT 0.021 48.0498 0.0359 48.0624 ;
		RECT 0.021 50.6349 0.0359 50.6475 ;
		RECT 0.021 50.9612 0.0359 50.9737 ;
		RECT 0.021 51.3627 0.0359 51.3753 ;
		RECT 0.021 52.442 0.0359 52.4545 ;
		RECT 0.021 52.7682 0.0359 52.7808 ;
		RECT 0.021 52.9439 0.0359 52.9565 ;
		RECT 0.021 53.3455 0.0359 53.358 ;
		RECT 0.021 91.0365 0.0359 91.049 ;
		RECT 0.0215 97.4616 0.0364 97.4741 ;
		RECT 0.021 97.5871 0.0359 97.5996 ;
		RECT 0.021 97.8882 0.0359 97.9008 ;
		RECT 0.0215 0.1376 0.0364 0.1502 ;
		RECT 0.021 153.8514 0.0359 153.8639 ;
		RECT 0.021 153.3996 0.0359 153.4122 ;
		RECT 0.021 153.3094 0.0359 153.322 ;
		RECT 0.021 152.998 0.0359 153.0106 ;
		RECT 0.021 152.4459 0.0359 152.4584 ;
		RECT 0.021 150.8898 0.0359 150.9024 ;
		RECT 0.021 149.8608 0.0359 149.8733 ;
		RECT 0.021 149.5345 0.0359 149.5471 ;
		RECT 0.021 149.1329 0.0359 149.1455 ;
		RECT 0.021 148.0537 0.0359 148.0663 ;
		RECT 0.021 147.7275 0.0359 147.74 ;
		RECT 0.021 147.5518 0.0359 147.5643 ;
		RECT 0.021 147.1502 0.0359 147.1627 ;
		RECT 0.021 112.671 0.0359 112.6835 ;
		RECT 0.021 112.282 0.0359 112.2945 ;
		RECT 0.0215 111.5424 0.0364 111.5549 ;
		RECT 0.021 109.5965 0.0359 109.609 ;
		RECT 0.0831 102.9463 0.098 102.9588 ;
		RECT 0.021 101.9918 0.0359 102.0043 ;
		RECT 0.021 101.8412 0.0359 101.8537 ;
		RECT 0.0215 101.0765 0.0364 101.089 ;
		RECT 0.0215 200.358 0.0364 200.3706 ;
	END

END HD_16384X72M16B8

END LIBRARY

